# Scaled down LEF created by ScaleLEFMacro.pl
# Original LEF: 16nm/HD_1024X66M8B2.lef
# Don't forget to change metal layer LEF separately!

# Copyright (c) 1993 - 2021 ARM Limited. All Rights Reserved.
# Use of this Software is subject to the terms and conditions of the
# applicable license agreement with ARM Limited.

# PhyVGen V 8.22.0
# ARM Version r3p2
# Creation Date: Thu Sep  9 16:13:23 2021


# Memory Configuration:
# ~~~~~~~~~~~~~~~~~~~~~
#  -activity_factor 50 -atf off -back_biasing off -bits 66 -bmux on
# -bus_notation on -check_instname on -compiler_type sp -diodes on -drive 6
# -ema on -flexible_banking 2 -frequency 1000 -instname HD_1024X66M8B2
# -left_bus_delim "[" -lren_bankmask off -metal_stack 2Xa1Xd -mux 8 -mvt LP
# -name_case upper -pipeline off -power_gating off -power_type otc -prefix ""
# -pwr_gnd_rename vddpe:VDDPE,vddce:VDDCE,vsse:VSSE -rcols 2 -redundancy off
# -retention on -right_bus_delim "]" -rows_p_bl 256 -rrows 0 -scan on -ser none
# -site_def off -top_layer m5-m10 -vmin_assist on -words 1024 -write_mask on
# -write_thru off -corners tt_0p80v_0p80v_25c
# 

VERSION 5.7 ;
BUSBITCHARS "[]" ;
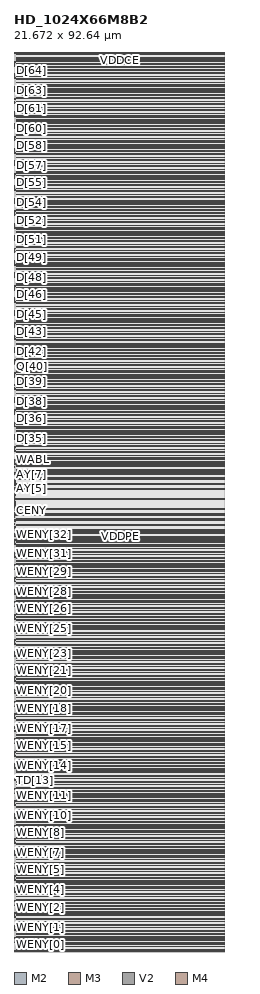
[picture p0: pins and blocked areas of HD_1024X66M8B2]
MACRO HD_1024X66M8B2
	FOREIGN HD_1024X66M8B2 0 0 ;
	SYMMETRY X Y ;
	SIZE 21.672 BY 92.64 ;
	CLASS BLOCK ;
	PIN AY[0]
		USE SIGNAL ;
		DIRECTION OUTPUT ;
		SHAPE ABUTMENT ;
		PORT
			 LAYER M2 ;
			RECT 0.0714 45.7914 0.1097 45.829 ;
			 LAYER M3 ;
			RECT 0.0714 45.7914 0.1097 45.8918 ;
			 LAYER V2 ;
			RECT 0.0831 45.8035 0.098 45.8161 ;
		END

		ANTENNADIFFAREA 0.00194719 ;
		ANTENNAPARTIALMETALAREA 0.00195671 ;
	END AY[0]

	PIN AY[1]
		USE SIGNAL ;
		DIRECTION OUTPUT ;
		SHAPE ABUTMENT ;
		PORT
			 LAYER M2 ;
			RECT 0.0714 46.0925 0.1097 46.1302 ;
			 LAYER M3 ;
			RECT 0.0714 46.0925 0.1097 46.1929 ;
			 LAYER V2 ;
			RECT 0.0831 46.1047 0.098 46.1173 ;
		END

		ANTENNADIFFAREA 0.00194719 ;
		ANTENNAPARTIALMETALAREA 0.00195671 ;
	END AY[1]

	PIN AY[2]
		USE SIGNAL ;
		DIRECTION OUTPUT ;
		SHAPE ABUTMENT ;
		PORT
			 LAYER M2 ;
			RECT 0.0714 46.2431 0.1097 46.2808 ;
			 LAYER M3 ;
			RECT 0.0714 46.2431 0.1097 46.3435 ;
			 LAYER V2 ;
			RECT 0.0831 46.2553 0.098 46.2678 ;
		END

		ANTENNADIFFAREA 0.00194719 ;
		ANTENNAPARTIALMETALAREA 0.00195671 ;
	END AY[2]

	PIN AY[3]
		USE SIGNAL ;
		DIRECTION OUTPUT ;
		SHAPE ABUTMENT ;
		PORT
			 LAYER M2 ;
			RECT 0.0098 46.9082 0.0481 46.9459 ;
			 LAYER M3 ;
			RECT 0.0098 46.8455 0.0481 46.9459 ;
			 LAYER V2 ;
			RECT 0.0215 46.9204 0.0364 46.9329 ;
		END

		ANTENNADIFFAREA 0.00194719 ;
		ANTENNAPARTIALMETALAREA 0.00195671 ;
	END AY[3]

	PIN AY[4]
		USE SIGNAL ;
		DIRECTION OUTPUT ;
		SHAPE ABUTMENT ;
		PORT
			 LAYER M2 ;
			RECT 0.0098 46.0047 0.0481 46.0424 ;
			 LAYER M3 ;
			RECT 0.0098 45.942 0.0481 46.0424 ;
			 LAYER V2 ;
			RECT 0.0215 46.0169 0.0364 46.0294 ;
		END

		ANTENNADIFFAREA 0.00194719 ;
		ANTENNAPARTIALMETALAREA 0.00195671 ;
	END AY[4]

	PIN AY[5]
		USE SIGNAL ;
		DIRECTION OUTPUT ;
		SHAPE ABUTMENT ;
		PORT
			 LAYER M2 ;
			RECT 0.0098 47.6612 0.0481 47.6988 ;
		END

		ANTENNADIFFAREA 0.00194719 ;
		ANTENNAPARTIALMETALAREA 0.00195671 ;
	END AY[5]

	PIN AY[6]
		USE SIGNAL ;
		DIRECTION OUTPUT ;
		SHAPE ABUTMENT ;
		PORT
			 LAYER M2 ;
			RECT 0.0714 47.4478 0.1097 47.4855 ;
			 LAYER M3 ;
			RECT 0.0714 47.4478 0.1097 47.5482 ;
			 LAYER V2 ;
			RECT 0.0831 47.46 0.098 47.4725 ;
		END

		ANTENNADIFFAREA 0.00194719 ;
		ANTENNAPARTIALMETALAREA 0.00195671 ;
	END AY[6]

	PIN AY[7]
		USE SIGNAL ;
		DIRECTION OUTPUT ;
		SHAPE ABUTMENT ;
		PORT
			 LAYER M2 ;
			RECT 0.0098 48.3514 0.0481 48.389 ;
		END

		ANTENNADIFFAREA 0.00194719 ;
		ANTENNAPARTIALMETALAREA 0.00195671 ;
	END AY[7]

	PIN AY[8]
		USE SIGNAL ;
		DIRECTION OUTPUT ;
		SHAPE ABUTMENT ;
		PORT
			 LAYER M2 ;
			RECT 0.0714 48.6525 0.1097 48.6902 ;
			 LAYER M3 ;
			RECT 0.0714 48.6525 0.1097 48.7529 ;
			 LAYER V2 ;
			RECT 0.0831 48.6647 0.098 48.6773 ;
		END

		ANTENNADIFFAREA 0.00194719 ;
		ANTENNAPARTIALMETALAREA 0.00195671 ;
	END AY[8]

	PIN AY[9]
		USE SIGNAL ;
		DIRECTION OUTPUT ;
		SHAPE ABUTMENT ;
		PORT
			 LAYER M3 ;
			RECT 0.0714 48.3514 0.1097 48.4518 ;
		END

		ANTENNADIFFAREA 0.00194719 ;
		ANTENNAPARTIALMETALAREA 0.00195671 ;
	END AY[9]

	PIN A[0]
		USE SIGNAL ;
		DIRECTION INPUT ;
		SHAPE ABUTMENT ;
		PORT
			 LAYER M2 ;
			RECT 0.0098 45.5529 0.0481 45.5906 ;
			 LAYER M3 ;
			RECT 0.0098 45.4902 0.0481 45.5906 ;
			 LAYER V2 ;
			RECT 0.0215 45.5651 0.0364 45.5776 ;
		END

		ANTENNAGATEAREA 0.00027817 ;
		ANTENNADIFFAREA 0.00194719 ;
		ANTENNAPARTIALMETALAREA 0.00195671 ;
	END A[0]

	PIN A[1]
		USE SIGNAL ;
		DIRECTION INPUT ;
		SHAPE ABUTMENT ;
		PORT
			 LAYER M2 ;
			RECT 0.0098 44.8 0.0481 44.8376 ;
			 LAYER M3 ;
			RECT 0.0098 44.7373 0.0481 44.8376 ;
			 LAYER V2 ;
			RECT 0.0215 44.8122 0.0364 44.8247 ;
		END

		ANTENNAGATEAREA 0.00027817 ;
		ANTENNADIFFAREA 0.00194719 ;
		ANTENNAPARTIALMETALAREA 0.00195671 ;
	END A[1]

	PIN A[2]
		USE SIGNAL ;
		DIRECTION INPUT ;
		SHAPE ABUTMENT ;
		PORT
			 LAYER M2 ;
			RECT 0.0714 48.2008 0.1097 48.2384 ;
			 LAYER M3 ;
			RECT 0.0714 48.2008 0.1097 48.3012 ;
			 LAYER V2 ;
			RECT 0.0831 48.2129 0.098 48.2255 ;
		END

		ANTENNAGATEAREA 0.00027817 ;
		ANTENNADIFFAREA 0.00194719 ;
		ANTENNAPARTIALMETALAREA 0.00195671 ;
	END A[2]

	PIN A[3]
		USE SIGNAL ;
		DIRECTION INPUT ;
		SHAPE ABUTMENT ;
		PORT
			 LAYER M2 ;
			RECT 0.0098 47.0588 0.0481 47.0965 ;
			 LAYER M3 ;
			RECT 0.0098 46.9961 0.0481 47.0965 ;
			 LAYER V2 ;
			RECT 0.0215 47.071 0.0364 47.0835 ;
		END

		ANTENNAGATEAREA 0.00027817 ;
		ANTENNADIFFAREA 0.00194719 ;
		ANTENNAPARTIALMETALAREA 0.00195671 ;
	END A[3]

	PIN A[4]
		USE SIGNAL ;
		DIRECTION INPUT ;
		SHAPE ABUTMENT ;
		PORT
			 LAYER M2 ;
			RECT 0.0098 46.4565 0.0481 46.4941 ;
			 LAYER M3 ;
			RECT 0.0098 46.3937 0.0481 46.4941 ;
			 LAYER V2 ;
			RECT 0.0215 46.4686 0.0364 46.4812 ;
		END

		ANTENNAGATEAREA 0.00027817 ;
		ANTENNADIFFAREA 0.00194719 ;
		ANTENNAPARTIALMETALAREA 0.00195671 ;
	END A[4]

	PIN A[5]
		USE SIGNAL ;
		DIRECTION INPUT ;
		SHAPE ABUTMENT ;
		PORT
			 LAYER M2 ;
			RECT 0.0098 47.2094 0.0481 47.2471 ;
			 LAYER M3 ;
			RECT 0.0098 47.1467 0.0481 47.2471 ;
			 LAYER V2 ;
			RECT 0.0215 47.2216 0.0364 47.2341 ;
		END

		ANTENNAGATEAREA 0.00027817 ;
		ANTENNADIFFAREA 0.00194719 ;
		ANTENNAPARTIALMETALAREA 0.00195671 ;
	END A[5]

	PIN A[6]
		USE SIGNAL ;
		DIRECTION INPUT ;
		SHAPE ABUTMENT ;
		PORT
			 LAYER M2 ;
			RECT 0.0098 47.8118 0.0481 47.8494 ;
		END

		ANTENNAGATEAREA 0.00027817 ;
		ANTENNADIFFAREA 0.00194719 ;
		ANTENNAPARTIALMETALAREA 0.00195671 ;
	END A[6]

	PIN A[7]
		USE SIGNAL ;
		DIRECTION INPUT ;
		SHAPE ABUTMENT ;
		PORT
			 LAYER M2 ;
			RECT 0.0098 48.1129 0.0481 48.1506 ;
			 LAYER M3 ;
			RECT 0.0098 48.0502 0.0481 48.1506 ;
			 LAYER V2 ;
			RECT 0.0215 48.1251 0.0364 48.1376 ;
		END

		ANTENNAGATEAREA 0.00027817 ;
		ANTENNADIFFAREA 0.00194719 ;
		ANTENNAPARTIALMETALAREA 0.00195671 ;
	END A[7]

	PIN A[8]
		USE SIGNAL ;
		DIRECTION INPUT ;
		SHAPE ABUTMENT ;
		PORT
			 LAYER M2 ;
			RECT 0.0098 48.2635 0.0481 48.3012 ;
			 LAYER M3 ;
			RECT 0.0098 48.2008 0.0481 48.3012 ;
			 LAYER V2 ;
			RECT 0.0215 48.2757 0.0364 48.2882 ;
		END

		ANTENNAGATEAREA 0.00027817 ;
		ANTENNADIFFAREA 0.00194719 ;
		ANTENNAPARTIALMETALAREA 0.00195671 ;
	END A[8]

	PIN A[9]
		USE SIGNAL ;
		DIRECTION INPUT ;
		SHAPE ABUTMENT ;
		PORT
			 LAYER M2 ;
			RECT 0.0098 48.7153 0.0481 48.7529 ;
			 LAYER M3 ;
			RECT 0.0098 48.6525 0.0481 48.7529 ;
			 LAYER V2 ;
			RECT 0.0215 48.7275 0.0364 48.74 ;
		END

		ANTENNAGATEAREA 0.00027817 ;
		ANTENNADIFFAREA 0.00194719 ;
		ANTENNAPARTIALMETALAREA 0.00195671 ;
	END A[9]

	PIN CEN
		USE SIGNAL ;
		DIRECTION INPUT ;
		SHAPE ABUTMENT ;
		PORT
			 LAYER M2 ;
			RECT 0.0714 49.2549 0.1097 49.2925 ;
			 LAYER M3 ;
			RECT 0.0714 49.2549 0.1097 49.3553 ;
			 LAYER V2 ;
			RECT 0.0831 49.2671 0.098 49.2796 ;
		END

		ANTENNAGATEAREA 0.00027817 ;
		ANTENNADIFFAREA 0.00194719 ;
		ANTENNAPARTIALMETALAREA 0.00195671 ;
	END CEN

	PIN CENY
		USE SIGNAL ;
		DIRECTION OUTPUT ;
		SHAPE ABUTMENT ;
		PORT
			 LAYER M2 ;
			RECT 0.0098 45.4024 0.0481 45.44 ;
		END

		ANTENNADIFFAREA 0.00194719 ;
		ANTENNAPARTIALMETALAREA 0.00195671 ;
	END CENY

	PIN CLK
		USE SIGNAL ;
		DIRECTION INPUT ;
		SHAPE ABUTMENT ;
		PORT
			 LAYER M2 ;
			RECT 0.0098 45.8541 0.0481 45.8918 ;
			 LAYER M3 ;
			RECT 0.0098 45.7914 0.0481 45.8918 ;
			 LAYER V2 ;
			RECT 0.0215 45.8663 0.0364 45.8788 ;
		END

		ANTENNAGATEAREA 0.00027817 ;
		ANTENNADIFFAREA 0.00194719 ;
		ANTENNAPARTIALMETALAREA 0.00195671 ;
	END CLK

	PIN DFTRAMBYP
		USE SIGNAL ;
		DIRECTION INPUT ;
		SHAPE ABUTMENT ;
		PORT
			 LAYER M2 ;
			RECT 0.0714 44.2855 0.1097 44.3231 ;
			 LAYER M3 ;
			RECT 0.0714 44.2855 0.1097 44.3859 ;
			 LAYER V2 ;
			RECT 0.0831 44.2976 0.098 44.3102 ;
		END

		ANTENNAGATEAREA 0.00027817 ;
		ANTENNADIFFAREA 0.00194719 ;
		ANTENNAPARTIALMETALAREA 0.00195671 ;
	END DFTRAMBYP

	PIN D[0]
		USE SIGNAL ;
		DIRECTION INPUT ;
		SHAPE ABUTMENT ;
		PORT
			 LAYER M2 ;
			RECT 0.0098 1.3678 0.0481 1.4055 ;
			 LAYER M3 ;
			RECT 0.0098 1.3678 0.0481 1.4682 ;
			 LAYER V2 ;
			RECT 0.0215 1.3808 0.0364 1.3933 ;
		END

		ANTENNAGATEAREA 0.00027817 ;
		ANTENNADIFFAREA 0.00194719 ;
		ANTENNAPARTIALMETALAREA 0.00195671 ;
	END D[0]

	PIN D[10]
		USE SIGNAL ;
		DIRECTION INPUT ;
		SHAPE ABUTMENT ;
		PORT
			 LAYER M2 ;
			RECT 0.0098 14.1678 0.0481 14.2055 ;
			 LAYER M3 ;
			RECT 0.0098 14.1678 0.0481 14.2682 ;
			 LAYER V2 ;
			RECT 0.0215 14.1808 0.0364 14.1933 ;
		END

		ANTENNAGATEAREA 0.00027817 ;
		ANTENNADIFFAREA 0.00194719 ;
		ANTENNAPARTIALMETALAREA 0.00195671 ;
	END D[10]

	PIN D[11]
		USE SIGNAL ;
		DIRECTION INPUT ;
		SHAPE ABUTMENT ;
		PORT
			 LAYER M2 ;
			RECT 0.0098 15.4478 0.0481 15.4855 ;
			 LAYER M3 ;
			RECT 0.0098 15.4478 0.0481 15.5482 ;
			 LAYER V2 ;
			RECT 0.0215 15.4608 0.0364 15.4733 ;
		END

		ANTENNAGATEAREA 0.00027817 ;
		ANTENNADIFFAREA 0.00194719 ;
		ANTENNAPARTIALMETALAREA 0.00195671 ;
	END D[11]

	PIN D[12]
		USE SIGNAL ;
		DIRECTION INPUT ;
		SHAPE ABUTMENT ;
		PORT
			 LAYER M2 ;
			RECT 0.0098 16.7278 0.0481 16.7655 ;
			 LAYER M3 ;
			RECT 0.0098 16.7278 0.0481 16.8282 ;
			 LAYER V2 ;
			RECT 0.0215 16.7408 0.0364 16.7533 ;
		END

		ANTENNAGATEAREA 0.00027817 ;
		ANTENNADIFFAREA 0.00194719 ;
		ANTENNAPARTIALMETALAREA 0.00195671 ;
	END D[12]

	PIN D[13]
		USE SIGNAL ;
		DIRECTION INPUT ;
		SHAPE ABUTMENT ;
		PORT
			 LAYER M2 ;
			RECT 0.0098 18.0078 0.0481 18.0455 ;
			 LAYER M3 ;
			RECT 0.0098 18.0078 0.0481 18.1082 ;
			 LAYER V2 ;
			RECT 0.0215 18.0208 0.0364 18.0333 ;
		END

		ANTENNAGATEAREA 0.00027817 ;
		ANTENNADIFFAREA 0.00194719 ;
		ANTENNAPARTIALMETALAREA 0.00195671 ;
	END D[13]

	PIN D[14]
		USE SIGNAL ;
		DIRECTION INPUT ;
		SHAPE ABUTMENT ;
		PORT
			 LAYER M2 ;
			RECT 0.0098 19.2878 0.0481 19.3255 ;
			 LAYER M3 ;
			RECT 0.0098 19.2878 0.0481 19.3882 ;
			 LAYER V2 ;
			RECT 0.0215 19.3008 0.0364 19.3133 ;
		END

		ANTENNAGATEAREA 0.00027817 ;
		ANTENNADIFFAREA 0.00194719 ;
		ANTENNAPARTIALMETALAREA 0.00195671 ;
	END D[14]

	PIN D[15]
		USE SIGNAL ;
		DIRECTION INPUT ;
		SHAPE ABUTMENT ;
		PORT
			 LAYER M2 ;
			RECT 0.0098 20.5678 0.0481 20.6055 ;
			 LAYER M3 ;
			RECT 0.0098 20.5678 0.0481 20.6682 ;
			 LAYER V2 ;
			RECT 0.0215 20.5808 0.0364 20.5933 ;
		END

		ANTENNAGATEAREA 0.00027817 ;
		ANTENNADIFFAREA 0.00194719 ;
		ANTENNAPARTIALMETALAREA 0.00195671 ;
	END D[15]

	PIN D[16]
		USE SIGNAL ;
		DIRECTION INPUT ;
		SHAPE ABUTMENT ;
		PORT
			 LAYER M2 ;
			RECT 0.0098 21.8478 0.0481 21.8855 ;
			 LAYER M3 ;
			RECT 0.0098 21.8478 0.0481 21.9482 ;
			 LAYER V2 ;
			RECT 0.0215 21.8608 0.0364 21.8733 ;
		END

		ANTENNAGATEAREA 0.00027817 ;
		ANTENNADIFFAREA 0.00194719 ;
		ANTENNAPARTIALMETALAREA 0.00195671 ;
	END D[16]

	PIN D[17]
		USE SIGNAL ;
		DIRECTION INPUT ;
		SHAPE ABUTMENT ;
		PORT
			 LAYER M2 ;
			RECT 0.0098 23.1278 0.0481 23.1655 ;
			 LAYER M3 ;
			RECT 0.0098 23.1278 0.0481 23.2282 ;
			 LAYER V2 ;
			RECT 0.0215 23.1408 0.0364 23.1533 ;
		END

		ANTENNAGATEAREA 0.00027817 ;
		ANTENNADIFFAREA 0.00194719 ;
		ANTENNAPARTIALMETALAREA 0.00195671 ;
	END D[17]

	PIN D[18]
		USE SIGNAL ;
		DIRECTION INPUT ;
		SHAPE ABUTMENT ;
		PORT
			 LAYER M2 ;
			RECT 0.0098 24.4078 0.0481 24.4455 ;
			 LAYER M3 ;
			RECT 0.0098 24.4078 0.0481 24.5082 ;
			 LAYER V2 ;
			RECT 0.0215 24.4208 0.0364 24.4333 ;
		END

		ANTENNAGATEAREA 0.00027817 ;
		ANTENNADIFFAREA 0.00194719 ;
		ANTENNAPARTIALMETALAREA 0.00195671 ;
	END D[18]

	PIN D[19]
		USE SIGNAL ;
		DIRECTION INPUT ;
		SHAPE ABUTMENT ;
		PORT
			 LAYER M2 ;
			RECT 0.0098 25.6878 0.0481 25.7255 ;
			 LAYER M3 ;
			RECT 0.0098 25.6878 0.0481 25.7882 ;
			 LAYER V2 ;
			RECT 0.0215 25.7008 0.0364 25.7133 ;
		END

		ANTENNAGATEAREA 0.00027817 ;
		ANTENNADIFFAREA 0.00194719 ;
		ANTENNAPARTIALMETALAREA 0.00195671 ;
	END D[19]

	PIN D[1]
		USE SIGNAL ;
		DIRECTION INPUT ;
		SHAPE ABUTMENT ;
		PORT
			 LAYER M2 ;
			RECT 0.0098 2.6478 0.0481 2.6855 ;
			 LAYER M3 ;
			RECT 0.0098 2.6478 0.0481 2.7482 ;
			 LAYER V2 ;
			RECT 0.0215 2.6608 0.0364 2.6733 ;
		END

		ANTENNAGATEAREA 0.00027817 ;
		ANTENNADIFFAREA 0.00194719 ;
		ANTENNAPARTIALMETALAREA 0.00195671 ;
	END D[1]

	PIN D[20]
		USE SIGNAL ;
		DIRECTION INPUT ;
		SHAPE ABUTMENT ;
		PORT
			 LAYER M2 ;
			RECT 0.0098 26.9678 0.0481 27.0055 ;
			 LAYER M3 ;
			RECT 0.0098 26.9678 0.0481 27.0682 ;
			 LAYER V2 ;
			RECT 0.0215 26.9808 0.0364 26.9933 ;
		END

		ANTENNAGATEAREA 0.00027817 ;
		ANTENNADIFFAREA 0.00194719 ;
		ANTENNAPARTIALMETALAREA 0.00195671 ;
	END D[20]

	PIN D[21]
		USE SIGNAL ;
		DIRECTION INPUT ;
		SHAPE ABUTMENT ;
		PORT
			 LAYER M2 ;
			RECT 0.0098 28.2478 0.0481 28.2855 ;
			 LAYER M3 ;
			RECT 0.0098 28.2478 0.0481 28.3482 ;
			 LAYER V2 ;
			RECT 0.0215 28.2608 0.0364 28.2733 ;
		END

		ANTENNAGATEAREA 0.00027817 ;
		ANTENNADIFFAREA 0.00194719 ;
		ANTENNAPARTIALMETALAREA 0.00195671 ;
	END D[21]

	PIN D[22]
		USE SIGNAL ;
		DIRECTION INPUT ;
		SHAPE ABUTMENT ;
		PORT
			 LAYER M2 ;
			RECT 0.0098 29.5278 0.0481 29.5655 ;
			 LAYER M3 ;
			RECT 0.0098 29.5278 0.0481 29.6282 ;
			 LAYER V2 ;
			RECT 0.0215 29.5408 0.0364 29.5533 ;
		END

		ANTENNAGATEAREA 0.00027817 ;
		ANTENNADIFFAREA 0.00194719 ;
		ANTENNAPARTIALMETALAREA 0.00195671 ;
	END D[22]

	PIN D[23]
		USE SIGNAL ;
		DIRECTION INPUT ;
		SHAPE ABUTMENT ;
		PORT
			 LAYER M2 ;
			RECT 0.0098 30.8078 0.0481 30.8455 ;
			 LAYER M3 ;
			RECT 0.0098 30.8078 0.0481 30.9082 ;
			 LAYER V2 ;
			RECT 0.0215 30.8208 0.0364 30.8333 ;
		END

		ANTENNAGATEAREA 0.00027817 ;
		ANTENNADIFFAREA 0.00194719 ;
		ANTENNAPARTIALMETALAREA 0.00195671 ;
	END D[23]

	PIN D[24]
		USE SIGNAL ;
		DIRECTION INPUT ;
		SHAPE ABUTMENT ;
		PORT
			 LAYER M2 ;
			RECT 0.0098 32.0878 0.0481 32.1255 ;
			 LAYER M3 ;
			RECT 0.0098 32.0878 0.0481 32.1882 ;
			 LAYER V2 ;
			RECT 0.0215 32.1008 0.0364 32.1133 ;
		END

		ANTENNAGATEAREA 0.00027817 ;
		ANTENNADIFFAREA 0.00194719 ;
		ANTENNAPARTIALMETALAREA 0.00195671 ;
	END D[24]

	PIN D[25]
		USE SIGNAL ;
		DIRECTION INPUT ;
		SHAPE ABUTMENT ;
		PORT
			 LAYER M2 ;
			RECT 0.0098 33.3678 0.0481 33.4055 ;
			 LAYER M3 ;
			RECT 0.0098 33.3678 0.0481 33.4682 ;
			 LAYER V2 ;
			RECT 0.0215 33.3808 0.0364 33.3933 ;
		END

		ANTENNAGATEAREA 0.00027817 ;
		ANTENNADIFFAREA 0.00194719 ;
		ANTENNAPARTIALMETALAREA 0.00195671 ;
	END D[25]

	PIN D[26]
		USE SIGNAL ;
		DIRECTION INPUT ;
		SHAPE ABUTMENT ;
		PORT
			 LAYER M2 ;
			RECT 0.0098 34.6478 0.0481 34.6855 ;
			 LAYER M3 ;
			RECT 0.0098 34.6478 0.0481 34.7482 ;
			 LAYER V2 ;
			RECT 0.0215 34.6608 0.0364 34.6733 ;
		END

		ANTENNAGATEAREA 0.00027817 ;
		ANTENNADIFFAREA 0.00194719 ;
		ANTENNAPARTIALMETALAREA 0.00195671 ;
	END D[26]

	PIN D[27]
		USE SIGNAL ;
		DIRECTION INPUT ;
		SHAPE ABUTMENT ;
		PORT
			 LAYER M2 ;
			RECT 0.0098 35.9278 0.0481 35.9655 ;
			 LAYER M3 ;
			RECT 0.0098 35.9278 0.0481 36.0282 ;
			 LAYER V2 ;
			RECT 0.0215 35.9408 0.0364 35.9533 ;
		END

		ANTENNAGATEAREA 0.00027817 ;
		ANTENNADIFFAREA 0.00194719 ;
		ANTENNAPARTIALMETALAREA 0.00195671 ;
	END D[27]

	PIN D[28]
		USE SIGNAL ;
		DIRECTION INPUT ;
		SHAPE ABUTMENT ;
		PORT
			 LAYER M2 ;
			RECT 0.0098 37.2078 0.0481 37.2455 ;
			 LAYER M3 ;
			RECT 0.0098 37.2078 0.0481 37.3082 ;
			 LAYER V2 ;
			RECT 0.0215 37.2208 0.0364 37.2333 ;
		END

		ANTENNAGATEAREA 0.00027817 ;
		ANTENNADIFFAREA 0.00194719 ;
		ANTENNAPARTIALMETALAREA 0.00195671 ;
	END D[28]

	PIN D[29]
		USE SIGNAL ;
		DIRECTION INPUT ;
		SHAPE ABUTMENT ;
		PORT
			 LAYER M2 ;
			RECT 0.0098 38.4878 0.0481 38.5255 ;
			 LAYER M3 ;
			RECT 0.0098 38.4878 0.0481 38.5882 ;
			 LAYER V2 ;
			RECT 0.0215 38.5008 0.0364 38.5133 ;
		END

		ANTENNAGATEAREA 0.00027817 ;
		ANTENNADIFFAREA 0.00194719 ;
		ANTENNAPARTIALMETALAREA 0.00195671 ;
	END D[29]

	PIN D[2]
		USE SIGNAL ;
		DIRECTION INPUT ;
		SHAPE ABUTMENT ;
		PORT
			 LAYER M2 ;
			RECT 0.0098 3.9278 0.0481 3.9655 ;
			 LAYER M3 ;
			RECT 0.0098 3.9278 0.0481 4.0282 ;
			 LAYER V2 ;
			RECT 0.0215 3.9408 0.0364 3.9533 ;
		END

		ANTENNAGATEAREA 0.00027817 ;
		ANTENNADIFFAREA 0.00194719 ;
		ANTENNAPARTIALMETALAREA 0.00195671 ;
	END D[2]

	PIN D[30]
		USE SIGNAL ;
		DIRECTION INPUT ;
		SHAPE ABUTMENT ;
		PORT
			 LAYER M2 ;
			RECT 0.0098 39.7678 0.0481 39.8055 ;
			 LAYER M3 ;
			RECT 0.0098 39.7678 0.0481 39.8682 ;
			 LAYER V2 ;
			RECT 0.0215 39.7808 0.0364 39.7933 ;
		END

		ANTENNAGATEAREA 0.00027817 ;
		ANTENNADIFFAREA 0.00194719 ;
		ANTENNAPARTIALMETALAREA 0.00195671 ;
	END D[30]

	PIN D[31]
		USE SIGNAL ;
		DIRECTION INPUT ;
		SHAPE ABUTMENT ;
		PORT
			 LAYER M2 ;
			RECT 0.0098 41.0478 0.0481 41.0855 ;
			 LAYER M3 ;
			RECT 0.0098 41.0478 0.0481 41.1482 ;
			 LAYER V2 ;
			RECT 0.0215 41.0608 0.0364 41.0733 ;
		END

		ANTENNAGATEAREA 0.00027817 ;
		ANTENNADIFFAREA 0.00194719 ;
		ANTENNAPARTIALMETALAREA 0.00195671 ;
	END D[31]

	PIN D[32]
		USE SIGNAL ;
		DIRECTION INPUT ;
		SHAPE ABUTMENT ;
		PORT
			 LAYER M2 ;
			RECT 0.0098 42.3278 0.0481 42.3655 ;
			 LAYER M3 ;
			RECT 0.0098 42.3278 0.0481 42.4282 ;
			 LAYER V2 ;
			RECT 0.0215 42.3408 0.0364 42.3533 ;
		END

		ANTENNAGATEAREA 0.00027817 ;
		ANTENNADIFFAREA 0.00194719 ;
		ANTENNAPARTIALMETALAREA 0.00195671 ;
	END D[32]

	PIN D[33]
		USE SIGNAL ;
		DIRECTION INPUT ;
		SHAPE ABUTMENT ;
		PORT
			 LAYER M2 ;
			RECT 0.0098 50.2651 0.0481 50.3027 ;
			 LAYER M3 ;
			RECT 0.0098 50.2024 0.0481 50.3027 ;
			 LAYER V2 ;
			RECT 0.0215 50.2773 0.0364 50.2898 ;
		END

		ANTENNAGATEAREA 0.00027817 ;
		ANTENNADIFFAREA 0.00194719 ;
		ANTENNAPARTIALMETALAREA 0.00195671 ;
	END D[33]

	PIN D[34]
		USE SIGNAL ;
		DIRECTION INPUT ;
		SHAPE ABUTMENT ;
		PORT
			 LAYER M2 ;
			RECT 0.0098 51.5451 0.0481 51.5827 ;
			 LAYER M3 ;
			RECT 0.0098 51.4824 0.0481 51.5827 ;
			 LAYER V2 ;
			RECT 0.0215 51.5573 0.0364 51.5698 ;
		END

		ANTENNAGATEAREA 0.00027817 ;
		ANTENNADIFFAREA 0.00194719 ;
		ANTENNAPARTIALMETALAREA 0.00195671 ;
	END D[34]

	PIN D[35]
		USE SIGNAL ;
		DIRECTION INPUT ;
		SHAPE ABUTMENT ;
		PORT
			 LAYER M2 ;
			RECT 0.0098 52.8251 0.0481 52.8627 ;
			 LAYER M3 ;
			RECT 0.0098 52.7624 0.0481 52.8627 ;
			 LAYER V2 ;
			RECT 0.0215 52.8373 0.0364 52.8498 ;
		END

		ANTENNAGATEAREA 0.00027817 ;
		ANTENNADIFFAREA 0.00194719 ;
		ANTENNAPARTIALMETALAREA 0.00195671 ;
	END D[35]

	PIN D[36]
		USE SIGNAL ;
		DIRECTION INPUT ;
		SHAPE ABUTMENT ;
		PORT
			 LAYER M2 ;
			RECT 0.0098 54.1051 0.0481 54.1427 ;
			 LAYER M3 ;
			RECT 0.0098 54.0424 0.0481 54.1427 ;
			 LAYER V2 ;
			RECT 0.0215 54.1173 0.0364 54.1298 ;
		END

		ANTENNAGATEAREA 0.00027817 ;
		ANTENNADIFFAREA 0.00194719 ;
		ANTENNAPARTIALMETALAREA 0.00195671 ;
	END D[36]

	PIN D[37]
		USE SIGNAL ;
		DIRECTION INPUT ;
		SHAPE ABUTMENT ;
		PORT
			 LAYER M2 ;
			RECT 0.0098 55.3851 0.0481 55.4227 ;
			 LAYER M3 ;
			RECT 0.0098 55.3224 0.0481 55.4227 ;
			 LAYER V2 ;
			RECT 0.0215 55.3973 0.0364 55.4098 ;
		END

		ANTENNAGATEAREA 0.00027817 ;
		ANTENNADIFFAREA 0.00194719 ;
		ANTENNAPARTIALMETALAREA 0.00195671 ;
	END D[37]

	PIN D[38]
		USE SIGNAL ;
		DIRECTION INPUT ;
		SHAPE ABUTMENT ;
		PORT
			 LAYER M2 ;
			RECT 0.0098 56.6651 0.0481 56.7027 ;
			 LAYER M3 ;
			RECT 0.0098 56.6024 0.0481 56.7027 ;
			 LAYER V2 ;
			RECT 0.0215 56.6773 0.0364 56.6898 ;
		END

		ANTENNAGATEAREA 0.00027817 ;
		ANTENNADIFFAREA 0.00194719 ;
		ANTENNAPARTIALMETALAREA 0.00195671 ;
	END D[38]

	PIN D[39]
		USE SIGNAL ;
		DIRECTION INPUT ;
		SHAPE ABUTMENT ;
		PORT
			 LAYER M2 ;
			RECT 0.0098 57.9451 0.0481 57.9827 ;
			 LAYER M3 ;
			RECT 0.0098 57.8824 0.0481 57.9827 ;
			 LAYER V2 ;
			RECT 0.0215 57.9573 0.0364 57.9698 ;
		END

		ANTENNAGATEAREA 0.00027817 ;
		ANTENNADIFFAREA 0.00194719 ;
		ANTENNAPARTIALMETALAREA 0.00195671 ;
	END D[39]

	PIN D[3]
		USE SIGNAL ;
		DIRECTION INPUT ;
		SHAPE ABUTMENT ;
		PORT
			 LAYER M2 ;
			RECT 0.0098 5.2078 0.0481 5.2455 ;
			 LAYER M3 ;
			RECT 0.0098 5.2078 0.0481 5.3082 ;
			 LAYER V2 ;
			RECT 0.0215 5.2208 0.0364 5.2333 ;
		END

		ANTENNAGATEAREA 0.00027817 ;
		ANTENNADIFFAREA 0.00194719 ;
		ANTENNAPARTIALMETALAREA 0.00195671 ;
	END D[3]

	PIN D[40]
		USE SIGNAL ;
		DIRECTION INPUT ;
		SHAPE ABUTMENT ;
		PORT
			 LAYER M2 ;
			RECT 0.0098 59.2251 0.0481 59.2627 ;
			 LAYER M3 ;
			RECT 0.0098 59.1624 0.0481 59.2627 ;
			 LAYER V2 ;
			RECT 0.0215 59.2373 0.0364 59.2498 ;
		END

		ANTENNAGATEAREA 0.00027817 ;
		ANTENNADIFFAREA 0.00194719 ;
		ANTENNAPARTIALMETALAREA 0.00195671 ;
	END D[40]

	PIN D[41]
		USE SIGNAL ;
		DIRECTION INPUT ;
		SHAPE ABUTMENT ;
		PORT
			 LAYER M2 ;
			RECT 0.0098 60.5051 0.0481 60.5427 ;
			 LAYER M3 ;
			RECT 0.0098 60.4424 0.0481 60.5427 ;
			 LAYER V2 ;
			RECT 0.0215 60.5173 0.0364 60.5298 ;
		END

		ANTENNAGATEAREA 0.00027817 ;
		ANTENNADIFFAREA 0.00194719 ;
		ANTENNAPARTIALMETALAREA 0.00195671 ;
	END D[41]

	PIN D[42]
		USE SIGNAL ;
		DIRECTION INPUT ;
		SHAPE ABUTMENT ;
		PORT
			 LAYER M2 ;
			RECT 0.0098 61.7851 0.0481 61.8227 ;
			 LAYER M3 ;
			RECT 0.0098 61.7224 0.0481 61.8227 ;
			 LAYER V2 ;
			RECT 0.0215 61.7973 0.0364 61.8098 ;
		END

		ANTENNAGATEAREA 0.00027817 ;
		ANTENNADIFFAREA 0.00194719 ;
		ANTENNAPARTIALMETALAREA 0.00195671 ;
	END D[42]

	PIN D[43]
		USE SIGNAL ;
		DIRECTION INPUT ;
		SHAPE ABUTMENT ;
		PORT
			 LAYER M2 ;
			RECT 0.0098 63.0651 0.0481 63.1027 ;
			 LAYER M3 ;
			RECT 0.0098 63.0024 0.0481 63.1027 ;
			 LAYER V2 ;
			RECT 0.0215 63.0773 0.0364 63.0898 ;
		END

		ANTENNAGATEAREA 0.00027817 ;
		ANTENNADIFFAREA 0.00194719 ;
		ANTENNAPARTIALMETALAREA 0.00195671 ;
	END D[43]

	PIN D[44]
		USE SIGNAL ;
		DIRECTION INPUT ;
		SHAPE ABUTMENT ;
		PORT
			 LAYER M2 ;
			RECT 0.0098 64.3451 0.0481 64.3827 ;
			 LAYER M3 ;
			RECT 0.0098 64.2824 0.0481 64.3827 ;
			 LAYER V2 ;
			RECT 0.0215 64.3573 0.0364 64.3698 ;
		END

		ANTENNAGATEAREA 0.00027817 ;
		ANTENNADIFFAREA 0.00194719 ;
		ANTENNAPARTIALMETALAREA 0.00195671 ;
	END D[44]

	PIN D[45]
		USE SIGNAL ;
		DIRECTION INPUT ;
		SHAPE ABUTMENT ;
		PORT
			 LAYER M2 ;
			RECT 0.0098 65.6251 0.0481 65.6627 ;
			 LAYER M3 ;
			RECT 0.0098 65.5624 0.0481 65.6627 ;
			 LAYER V2 ;
			RECT 0.0215 65.6373 0.0364 65.6498 ;
		END

		ANTENNAGATEAREA 0.00027817 ;
		ANTENNADIFFAREA 0.00194719 ;
		ANTENNAPARTIALMETALAREA 0.00195671 ;
	END D[45]

	PIN D[46]
		USE SIGNAL ;
		DIRECTION INPUT ;
		SHAPE ABUTMENT ;
		PORT
			 LAYER M2 ;
			RECT 0.0098 66.9051 0.0481 66.9427 ;
			 LAYER M3 ;
			RECT 0.0098 66.8424 0.0481 66.9427 ;
			 LAYER V2 ;
			RECT 0.0215 66.9173 0.0364 66.9298 ;
		END

		ANTENNAGATEAREA 0.00027817 ;
		ANTENNADIFFAREA 0.00194719 ;
		ANTENNAPARTIALMETALAREA 0.00195671 ;
	END D[46]

	PIN D[47]
		USE SIGNAL ;
		DIRECTION INPUT ;
		SHAPE ABUTMENT ;
		PORT
			 LAYER M2 ;
			RECT 0.0098 68.1851 0.0481 68.2227 ;
			 LAYER M3 ;
			RECT 0.0098 68.1224 0.0481 68.2227 ;
			 LAYER V2 ;
			RECT 0.0215 68.1973 0.0364 68.2098 ;
		END

		ANTENNAGATEAREA 0.00027817 ;
		ANTENNADIFFAREA 0.00194719 ;
		ANTENNAPARTIALMETALAREA 0.00195671 ;
	END D[47]

	PIN D[48]
		USE SIGNAL ;
		DIRECTION INPUT ;
		SHAPE ABUTMENT ;
		PORT
			 LAYER M2 ;
			RECT 0.0098 69.4651 0.0481 69.5027 ;
			 LAYER M3 ;
			RECT 0.0098 69.4024 0.0481 69.5027 ;
			 LAYER V2 ;
			RECT 0.0215 69.4773 0.0364 69.4898 ;
		END

		ANTENNAGATEAREA 0.00027817 ;
		ANTENNADIFFAREA 0.00194719 ;
		ANTENNAPARTIALMETALAREA 0.00195671 ;
	END D[48]

	PIN D[49]
		USE SIGNAL ;
		DIRECTION INPUT ;
		SHAPE ABUTMENT ;
		PORT
			 LAYER M2 ;
			RECT 0.0098 70.7451 0.0481 70.7827 ;
			 LAYER M3 ;
			RECT 0.0098 70.6824 0.0481 70.7827 ;
			 LAYER V2 ;
			RECT 0.0215 70.7573 0.0364 70.7698 ;
		END

		ANTENNAGATEAREA 0.00027817 ;
		ANTENNADIFFAREA 0.00194719 ;
		ANTENNAPARTIALMETALAREA 0.00195671 ;
	END D[49]

	PIN D[4]
		USE SIGNAL ;
		DIRECTION INPUT ;
		SHAPE ABUTMENT ;
		PORT
			 LAYER M2 ;
			RECT 0.0098 6.4878 0.0481 6.5255 ;
			 LAYER M3 ;
			RECT 0.0098 6.4878 0.0481 6.5882 ;
			 LAYER V2 ;
			RECT 0.0215 6.5008 0.0364 6.5133 ;
		END

		ANTENNAGATEAREA 0.00027817 ;
		ANTENNADIFFAREA 0.00194719 ;
		ANTENNAPARTIALMETALAREA 0.00195671 ;
	END D[4]

	PIN D[50]
		USE SIGNAL ;
		DIRECTION INPUT ;
		SHAPE ABUTMENT ;
		PORT
			 LAYER M2 ;
			RECT 0.0098 72.0251 0.0481 72.0627 ;
			 LAYER M3 ;
			RECT 0.0098 71.9624 0.0481 72.0627 ;
			 LAYER V2 ;
			RECT 0.0215 72.0373 0.0364 72.0498 ;
		END

		ANTENNAGATEAREA 0.00027817 ;
		ANTENNADIFFAREA 0.00194719 ;
		ANTENNAPARTIALMETALAREA 0.00195671 ;
	END D[50]

	PIN D[51]
		USE SIGNAL ;
		DIRECTION INPUT ;
		SHAPE ABUTMENT ;
		PORT
			 LAYER M2 ;
			RECT 0.0098 73.3051 0.0481 73.3427 ;
			 LAYER M3 ;
			RECT 0.0098 73.2424 0.0481 73.3427 ;
			 LAYER V2 ;
			RECT 0.0215 73.3173 0.0364 73.3298 ;
		END

		ANTENNAGATEAREA 0.00027817 ;
		ANTENNADIFFAREA 0.00194719 ;
		ANTENNAPARTIALMETALAREA 0.00195671 ;
	END D[51]

	PIN D[52]
		USE SIGNAL ;
		DIRECTION INPUT ;
		SHAPE ABUTMENT ;
		PORT
			 LAYER M2 ;
			RECT 0.0098 74.5851 0.0481 74.6227 ;
			 LAYER M3 ;
			RECT 0.0098 74.5224 0.0481 74.6227 ;
			 LAYER V2 ;
			RECT 0.0215 74.5973 0.0364 74.6098 ;
		END

		ANTENNAGATEAREA 0.00027817 ;
		ANTENNADIFFAREA 0.00194719 ;
		ANTENNAPARTIALMETALAREA 0.00195671 ;
	END D[52]

	PIN D[53]
		USE SIGNAL ;
		DIRECTION INPUT ;
		SHAPE ABUTMENT ;
		PORT
			 LAYER M2 ;
			RECT 0.0098 75.8651 0.0481 75.9027 ;
			 LAYER M3 ;
			RECT 0.0098 75.8024 0.0481 75.9027 ;
			 LAYER V2 ;
			RECT 0.0215 75.8773 0.0364 75.8898 ;
		END

		ANTENNAGATEAREA 0.00027817 ;
		ANTENNADIFFAREA 0.00194719 ;
		ANTENNAPARTIALMETALAREA 0.00195671 ;
	END D[53]

	PIN D[54]
		USE SIGNAL ;
		DIRECTION INPUT ;
		SHAPE ABUTMENT ;
		PORT
			 LAYER M2 ;
			RECT 0.0098 77.1451 0.0481 77.1827 ;
			 LAYER M3 ;
			RECT 0.0098 77.0824 0.0481 77.1827 ;
			 LAYER V2 ;
			RECT 0.0215 77.1573 0.0364 77.1698 ;
		END

		ANTENNAGATEAREA 0.00027817 ;
		ANTENNADIFFAREA 0.00194719 ;
		ANTENNAPARTIALMETALAREA 0.00195671 ;
	END D[54]

	PIN D[55]
		USE SIGNAL ;
		DIRECTION INPUT ;
		SHAPE ABUTMENT ;
		PORT
			 LAYER M2 ;
			RECT 0.0098 78.4251 0.0481 78.4627 ;
			 LAYER M3 ;
			RECT 0.0098 78.3624 0.0481 78.4627 ;
			 LAYER V2 ;
			RECT 0.0215 78.4373 0.0364 78.4498 ;
		END

		ANTENNAGATEAREA 0.00027817 ;
		ANTENNADIFFAREA 0.00194719 ;
		ANTENNAPARTIALMETALAREA 0.00195671 ;
	END D[55]

	PIN D[56]
		USE SIGNAL ;
		DIRECTION INPUT ;
		SHAPE ABUTMENT ;
		PORT
			 LAYER M2 ;
			RECT 0.0098 79.7051 0.0481 79.7427 ;
			 LAYER M3 ;
			RECT 0.0098 79.6424 0.0481 79.7427 ;
			 LAYER V2 ;
			RECT 0.0215 79.7173 0.0364 79.7298 ;
		END

		ANTENNAGATEAREA 0.00027817 ;
		ANTENNADIFFAREA 0.00194719 ;
		ANTENNAPARTIALMETALAREA 0.00195671 ;
	END D[56]

	PIN D[57]
		USE SIGNAL ;
		DIRECTION INPUT ;
		SHAPE ABUTMENT ;
		PORT
			 LAYER M2 ;
			RECT 0.0098 80.9851 0.0481 81.0227 ;
			 LAYER M3 ;
			RECT 0.0098 80.9224 0.0481 81.0227 ;
			 LAYER V2 ;
			RECT 0.0215 80.9973 0.0364 81.0098 ;
		END

		ANTENNAGATEAREA 0.00027817 ;
		ANTENNADIFFAREA 0.00194719 ;
		ANTENNAPARTIALMETALAREA 0.00195671 ;
	END D[57]

	PIN D[58]
		USE SIGNAL ;
		DIRECTION INPUT ;
		SHAPE ABUTMENT ;
		PORT
			 LAYER M2 ;
			RECT 0.0098 82.2651 0.0481 82.3027 ;
			 LAYER M3 ;
			RECT 0.0098 82.2024 0.0481 82.3027 ;
			 LAYER V2 ;
			RECT 0.0215 82.2773 0.0364 82.2898 ;
		END

		ANTENNAGATEAREA 0.00027817 ;
		ANTENNADIFFAREA 0.00194719 ;
		ANTENNAPARTIALMETALAREA 0.00195671 ;
	END D[58]

	PIN D[59]
		USE SIGNAL ;
		DIRECTION INPUT ;
		SHAPE ABUTMENT ;
		PORT
			 LAYER M2 ;
			RECT 0.0098 83.5451 0.0481 83.5827 ;
			 LAYER M3 ;
			RECT 0.0098 83.4824 0.0481 83.5827 ;
			 LAYER V2 ;
			RECT 0.0215 83.5573 0.0364 83.5698 ;
		END

		ANTENNAGATEAREA 0.00027817 ;
		ANTENNADIFFAREA 0.00194719 ;
		ANTENNAPARTIALMETALAREA 0.00195671 ;
	END D[59]

	PIN D[5]
		USE SIGNAL ;
		DIRECTION INPUT ;
		SHAPE ABUTMENT ;
		PORT
			 LAYER M2 ;
			RECT 0.0098 7.7678 0.0481 7.8055 ;
			 LAYER M3 ;
			RECT 0.0098 7.7678 0.0481 7.8682 ;
			 LAYER V2 ;
			RECT 0.0215 7.7808 0.0364 7.7933 ;
		END

		ANTENNAGATEAREA 0.00027817 ;
		ANTENNADIFFAREA 0.00194719 ;
		ANTENNAPARTIALMETALAREA 0.00195671 ;
	END D[5]

	PIN D[60]
		USE SIGNAL ;
		DIRECTION INPUT ;
		SHAPE ABUTMENT ;
		PORT
			 LAYER M2 ;
			RECT 0.0098 84.8251 0.0481 84.8627 ;
			 LAYER M3 ;
			RECT 0.0098 84.7624 0.0481 84.8627 ;
			 LAYER V2 ;
			RECT 0.0215 84.8373 0.0364 84.8498 ;
		END

		ANTENNAGATEAREA 0.00027817 ;
		ANTENNADIFFAREA 0.00194719 ;
		ANTENNAPARTIALMETALAREA 0.00195671 ;
	END D[60]

	PIN D[61]
		USE SIGNAL ;
		DIRECTION INPUT ;
		SHAPE ABUTMENT ;
		PORT
			 LAYER M2 ;
			RECT 0.0098 86.1051 0.0481 86.1427 ;
			 LAYER M3 ;
			RECT 0.0098 86.0424 0.0481 86.1427 ;
			 LAYER V2 ;
			RECT 0.0215 86.1173 0.0364 86.1298 ;
		END

		ANTENNAGATEAREA 0.00027817 ;
		ANTENNADIFFAREA 0.00194719 ;
		ANTENNAPARTIALMETALAREA 0.00195671 ;
	END D[61]

	PIN D[62]
		USE SIGNAL ;
		DIRECTION INPUT ;
		SHAPE ABUTMENT ;
		PORT
			 LAYER M2 ;
			RECT 0.0098 87.3851 0.0481 87.4227 ;
			 LAYER M3 ;
			RECT 0.0098 87.3224 0.0481 87.4227 ;
			 LAYER V2 ;
			RECT 0.0215 87.3973 0.0364 87.4098 ;
		END

		ANTENNAGATEAREA 0.00027817 ;
		ANTENNADIFFAREA 0.00194719 ;
		ANTENNAPARTIALMETALAREA 0.00195671 ;
	END D[62]

	PIN D[63]
		USE SIGNAL ;
		DIRECTION INPUT ;
		SHAPE ABUTMENT ;
		PORT
			 LAYER M2 ;
			RECT 0.0098 88.6651 0.0481 88.7027 ;
			 LAYER M3 ;
			RECT 0.0098 88.6024 0.0481 88.7027 ;
			 LAYER V2 ;
			RECT 0.0215 88.6773 0.0364 88.6898 ;
		END

		ANTENNAGATEAREA 0.00027817 ;
		ANTENNADIFFAREA 0.00194719 ;
		ANTENNAPARTIALMETALAREA 0.00195671 ;
	END D[63]

	PIN D[64]
		USE SIGNAL ;
		DIRECTION INPUT ;
		SHAPE ABUTMENT ;
		PORT
			 LAYER M2 ;
			RECT 0.0098 89.9451 0.0481 89.9827 ;
			 LAYER M3 ;
			RECT 0.0098 89.8824 0.0481 89.9827 ;
			 LAYER V2 ;
			RECT 0.0215 89.9573 0.0364 89.9698 ;
		END

		ANTENNAGATEAREA 0.00027817 ;
		ANTENNADIFFAREA 0.00194719 ;
		ANTENNAPARTIALMETALAREA 0.00195671 ;
	END D[64]

	PIN D[65]
		USE SIGNAL ;
		DIRECTION INPUT ;
		SHAPE ABUTMENT ;
		PORT
			 LAYER M2 ;
			RECT 0.0098 91.2251 0.0481 91.2627 ;
			 LAYER M3 ;
			RECT 0.0098 91.1624 0.0481 91.2627 ;
			 LAYER V2 ;
			RECT 0.0215 91.2373 0.0364 91.2498 ;
		END

		ANTENNAGATEAREA 0.00027817 ;
		ANTENNADIFFAREA 0.00194719 ;
		ANTENNAPARTIALMETALAREA 0.00195671 ;
	END D[65]

	PIN D[6]
		USE SIGNAL ;
		DIRECTION INPUT ;
		SHAPE ABUTMENT ;
		PORT
			 LAYER M2 ;
			RECT 0.0098 9.0478 0.0481 9.0855 ;
			 LAYER M3 ;
			RECT 0.0098 9.0478 0.0481 9.1482 ;
			 LAYER V2 ;
			RECT 0.0215 9.0608 0.0364 9.0733 ;
		END

		ANTENNAGATEAREA 0.00027817 ;
		ANTENNADIFFAREA 0.00194719 ;
		ANTENNAPARTIALMETALAREA 0.00195671 ;
	END D[6]

	PIN D[7]
		USE SIGNAL ;
		DIRECTION INPUT ;
		SHAPE ABUTMENT ;
		PORT
			 LAYER M2 ;
			RECT 0.0098 10.3278 0.0481 10.3655 ;
			 LAYER M3 ;
			RECT 0.0098 10.3278 0.0481 10.4282 ;
			 LAYER V2 ;
			RECT 0.0215 10.3408 0.0364 10.3533 ;
		END

		ANTENNAGATEAREA 0.00027817 ;
		ANTENNADIFFAREA 0.00194719 ;
		ANTENNAPARTIALMETALAREA 0.00195671 ;
	END D[7]

	PIN D[8]
		USE SIGNAL ;
		DIRECTION INPUT ;
		SHAPE ABUTMENT ;
		PORT
			 LAYER M2 ;
			RECT 0.0098 11.6078 0.0481 11.6455 ;
			 LAYER M3 ;
			RECT 0.0098 11.6078 0.0481 11.7082 ;
			 LAYER V2 ;
			RECT 0.0215 11.6208 0.0364 11.6333 ;
		END

		ANTENNAGATEAREA 0.00027817 ;
		ANTENNADIFFAREA 0.00194719 ;
		ANTENNAPARTIALMETALAREA 0.00195671 ;
	END D[8]

	PIN D[9]
		USE SIGNAL ;
		DIRECTION INPUT ;
		SHAPE ABUTMENT ;
		PORT
			 LAYER M2 ;
			RECT 0.0098 12.8878 0.0481 12.9255 ;
			 LAYER M3 ;
			RECT 0.0098 12.8878 0.0481 12.9882 ;
			 LAYER V2 ;
			RECT 0.0215 12.9008 0.0364 12.9133 ;
		END

		ANTENNAGATEAREA 0.00027817 ;
		ANTENNADIFFAREA 0.00194719 ;
		ANTENNAPARTIALMETALAREA 0.00195671 ;
	END D[9]

	PIN EMAS
		USE SIGNAL ;
		DIRECTION INPUT ;
		SHAPE ABUTMENT ;
		PORT
			 LAYER M2 ;
			RECT 0.0714 44.8878 0.1097 44.9255 ;
			 LAYER M3 ;
			RECT 0.0714 44.8878 0.1097 44.9882 ;
			 LAYER V2 ;
			RECT 0.0831 44.9 0.098 44.9125 ;
		END

		ANTENNAGATEAREA 0.00027817 ;
		ANTENNADIFFAREA 0.00194719 ;
		ANTENNAPARTIALMETALAREA 0.00195671 ;
	END EMAS

	PIN EMAW[0]
		USE SIGNAL ;
		DIRECTION INPUT ;
		SHAPE ABUTMENT ;
		PORT
			 LAYER M2 ;
			RECT 0.0714 43.6831 0.1097 43.7208 ;
			 LAYER M3 ;
			RECT 0.0714 43.6831 0.1097 43.7835 ;
			 LAYER V2 ;
			RECT 0.0831 43.6953 0.098 43.7078 ;
		END

		ANTENNAGATEAREA 0.00027817 ;
		ANTENNADIFFAREA 0.00194719 ;
		ANTENNAPARTIALMETALAREA 0.00195671 ;
	END EMAW[0]

	PIN EMAW[1]
		USE SIGNAL ;
		DIRECTION INPUT ;
		SHAPE ABUTMENT ;
		PORT
			 LAYER M2 ;
			RECT 0.0098 43.7459 0.0481 43.7835 ;
			 LAYER M3 ;
			RECT 0.0098 43.6831 0.0481 43.7835 ;
			 LAYER V2 ;
			RECT 0.0215 43.758 0.0364 43.7706 ;
		END

		ANTENNAGATEAREA 0.00027817 ;
		ANTENNADIFFAREA 0.00194719 ;
		ANTENNAPARTIALMETALAREA 0.00195671 ;
	END EMAW[1]

	PIN EMA[0]
		USE SIGNAL ;
		DIRECTION INPUT ;
		SHAPE ABUTMENT ;
		PORT
			 LAYER M2 ;
			RECT 0.0098 43.4447 0.0481 43.4824 ;
			 LAYER M3 ;
			RECT 0.0098 43.382 0.0481 43.4824 ;
			 LAYER V2 ;
			RECT 0.0215 43.4569 0.0364 43.4694 ;
		END

		ANTENNAGATEAREA 0.00027817 ;
		ANTENNADIFFAREA 0.00194719 ;
		ANTENNAPARTIALMETALAREA 0.00195671 ;
	END EMA[0]

	PIN EMA[1]
		USE SIGNAL ;
		DIRECTION INPUT ;
		SHAPE ABUTMENT ;
		PORT
			 LAYER M2 ;
			RECT 0.0714 43.5325 0.1097 43.5702 ;
			 LAYER M3 ;
			RECT 0.0714 43.5325 0.1097 43.6329 ;
			 LAYER V2 ;
			RECT 0.0831 43.5447 0.098 43.5573 ;
		END

		ANTENNAGATEAREA 0.00027817 ;
		ANTENNADIFFAREA 0.00194719 ;
		ANTENNAPARTIALMETALAREA 0.00195671 ;
	END EMA[1]

	PIN EMA[2]
		USE SIGNAL ;
		DIRECTION INPUT ;
		SHAPE ABUTMENT ;
		PORT
			 LAYER M2 ;
			RECT 0.0714 44.4361 0.1097 44.4737 ;
			 LAYER M3 ;
			RECT 0.0714 44.4361 0.1097 44.5365 ;
			 LAYER V2 ;
			RECT 0.0831 44.4482 0.098 44.4608 ;
		END

		ANTENNAGATEAREA 0.00027817 ;
		ANTENNADIFFAREA 0.00194719 ;
		ANTENNAPARTIALMETALAREA 0.00195671 ;
	END EMA[2]

	PIN GWEN
		USE SIGNAL ;
		DIRECTION INPUT ;
		SHAPE ABUTMENT ;
		PORT
			 LAYER M2 ;
			RECT 0.0098 44.3482 0.0481 44.3859 ;
			 LAYER M3 ;
			RECT 0.0098 44.2855 0.0481 44.3859 ;
			 LAYER V2 ;
			RECT 0.0215 44.3604 0.0364 44.3729 ;
		END

		ANTENNAGATEAREA 0.00027817 ;
		ANTENNADIFFAREA 0.00194719 ;
		ANTENNAPARTIALMETALAREA 0.00195671 ;
	END GWEN

	PIN GWENY
		USE SIGNAL ;
		DIRECTION OUTPUT ;
		SHAPE ABUTMENT ;
		PORT
			 LAYER M2 ;
			RECT 0.0714 45.0384 0.1097 45.0761 ;
			 LAYER M3 ;
			RECT 0.0714 45.0384 0.1097 45.1388 ;
			 LAYER V2 ;
			RECT 0.0831 45.0506 0.098 45.0631 ;
		END

		ANTENNADIFFAREA 0.00194719 ;
		ANTENNAPARTIALMETALAREA 0.00195671 ;
	END GWENY

	PIN Q[0]
		USE SIGNAL ;
		DIRECTION OUTPUT ;
		SHAPE ABUTMENT ;
		PORT
			 LAYER M2 ;
			RECT 0.0098 1.0918 0.0481 1.1922 ;
			 LAYER M3 ;
			RECT 0.0098 1.0918 0.0481 1.1922 ;
			 LAYER V2 ;
			RECT 0.021 1.1667 0.0359 1.1792 ;
		END

		ANTENNADIFFAREA 0.00194719 ;
		ANTENNAPARTIALMETALAREA 0.00195671 ;
	END Q[0]

	PIN Q[10]
		USE SIGNAL ;
		DIRECTION OUTPUT ;
		SHAPE ABUTMENT ;
		PORT
			 LAYER M2 ;
			RECT 0.0098 13.8918 0.0481 13.9922 ;
			 LAYER M3 ;
			RECT 0.0098 13.8918 0.0481 13.9922 ;
			 LAYER V2 ;
			RECT 0.021 13.9667 0.0359 13.9792 ;
		END

		ANTENNADIFFAREA 0.00194719 ;
		ANTENNAPARTIALMETALAREA 0.00195671 ;
	END Q[10]

	PIN Q[11]
		USE SIGNAL ;
		DIRECTION OUTPUT ;
		SHAPE ABUTMENT ;
		PORT
			 LAYER M2 ;
			RECT 0.0098 15.1718 0.0481 15.2722 ;
			 LAYER M3 ;
			RECT 0.0098 15.1718 0.0481 15.2722 ;
			 LAYER V2 ;
			RECT 0.021 15.2467 0.0359 15.2592 ;
		END

		ANTENNADIFFAREA 0.00194719 ;
		ANTENNAPARTIALMETALAREA 0.00195671 ;
	END Q[11]

	PIN Q[12]
		USE SIGNAL ;
		DIRECTION OUTPUT ;
		SHAPE ABUTMENT ;
		PORT
			 LAYER M2 ;
			RECT 0.0098 16.4518 0.0481 16.5522 ;
			 LAYER M3 ;
			RECT 0.0098 16.4518 0.0481 16.5522 ;
			 LAYER V2 ;
			RECT 0.021 16.5267 0.0359 16.5392 ;
		END

		ANTENNADIFFAREA 0.00194719 ;
		ANTENNAPARTIALMETALAREA 0.00195671 ;
	END Q[12]

	PIN Q[13]
		USE SIGNAL ;
		DIRECTION OUTPUT ;
		SHAPE ABUTMENT ;
		PORT
			 LAYER M2 ;
			RECT 0.0098 17.7318 0.0481 17.8322 ;
			 LAYER M3 ;
			RECT 0.0098 17.7318 0.0481 17.8322 ;
			 LAYER V2 ;
			RECT 0.021 17.8067 0.0359 17.8192 ;
		END

		ANTENNADIFFAREA 0.00194719 ;
		ANTENNAPARTIALMETALAREA 0.00195671 ;
	END Q[13]

	PIN Q[14]
		USE SIGNAL ;
		DIRECTION OUTPUT ;
		SHAPE ABUTMENT ;
		PORT
			 LAYER M2 ;
			RECT 0.0098 19.0118 0.0481 19.1122 ;
			 LAYER M3 ;
			RECT 0.0098 19.0118 0.0481 19.1122 ;
			 LAYER V2 ;
			RECT 0.021 19.0867 0.0359 19.0992 ;
		END

		ANTENNADIFFAREA 0.00194719 ;
		ANTENNAPARTIALMETALAREA 0.00195671 ;
	END Q[14]

	PIN Q[15]
		USE SIGNAL ;
		DIRECTION OUTPUT ;
		SHAPE ABUTMENT ;
		PORT
			 LAYER M2 ;
			RECT 0.0098 20.2918 0.0481 20.3922 ;
			 LAYER M3 ;
			RECT 0.0098 20.2918 0.0481 20.3922 ;
			 LAYER V2 ;
			RECT 0.021 20.3667 0.0359 20.3792 ;
		END

		ANTENNADIFFAREA 0.00194719 ;
		ANTENNAPARTIALMETALAREA 0.00195671 ;
	END Q[15]

	PIN Q[16]
		USE SIGNAL ;
		DIRECTION OUTPUT ;
		SHAPE ABUTMENT ;
		PORT
			 LAYER M2 ;
			RECT 0.0098 21.5718 0.0481 21.6722 ;
			 LAYER M3 ;
			RECT 0.0098 21.5718 0.0481 21.6722 ;
			 LAYER V2 ;
			RECT 0.021 21.6467 0.0359 21.6592 ;
		END

		ANTENNADIFFAREA 0.00194719 ;
		ANTENNAPARTIALMETALAREA 0.00195671 ;
	END Q[16]

	PIN Q[17]
		USE SIGNAL ;
		DIRECTION OUTPUT ;
		SHAPE ABUTMENT ;
		PORT
			 LAYER M2 ;
			RECT 0.0098 22.8518 0.0481 22.9522 ;
			 LAYER M3 ;
			RECT 0.0098 22.8518 0.0481 22.9522 ;
			 LAYER V2 ;
			RECT 0.021 22.9267 0.0359 22.9392 ;
		END

		ANTENNADIFFAREA 0.00194719 ;
		ANTENNAPARTIALMETALAREA 0.00195671 ;
	END Q[17]

	PIN Q[18]
		USE SIGNAL ;
		DIRECTION OUTPUT ;
		SHAPE ABUTMENT ;
		PORT
			 LAYER M2 ;
			RECT 0.0098 24.1318 0.0481 24.2322 ;
			 LAYER M3 ;
			RECT 0.0098 24.1318 0.0481 24.2322 ;
			 LAYER V2 ;
			RECT 0.021 24.2067 0.0359 24.2192 ;
		END

		ANTENNADIFFAREA 0.00194719 ;
		ANTENNAPARTIALMETALAREA 0.00195671 ;
	END Q[18]

	PIN Q[19]
		USE SIGNAL ;
		DIRECTION OUTPUT ;
		SHAPE ABUTMENT ;
		PORT
			 LAYER M2 ;
			RECT 0.0098 25.4118 0.0481 25.5122 ;
			 LAYER M3 ;
			RECT 0.0098 25.4118 0.0481 25.5122 ;
			 LAYER V2 ;
			RECT 0.021 25.4867 0.0359 25.4992 ;
		END

		ANTENNADIFFAREA 0.00194719 ;
		ANTENNAPARTIALMETALAREA 0.00195671 ;
	END Q[19]

	PIN Q[1]
		USE SIGNAL ;
		DIRECTION OUTPUT ;
		SHAPE ABUTMENT ;
		PORT
			 LAYER M2 ;
			RECT 0.0098 2.3718 0.0481 2.4722 ;
			 LAYER M3 ;
			RECT 0.0098 2.3718 0.0481 2.4722 ;
			 LAYER V2 ;
			RECT 0.021 2.4467 0.0359 2.4592 ;
		END

		ANTENNADIFFAREA 0.00194719 ;
		ANTENNAPARTIALMETALAREA 0.00195671 ;
	END Q[1]

	PIN Q[20]
		USE SIGNAL ;
		DIRECTION OUTPUT ;
		SHAPE ABUTMENT ;
		PORT
			 LAYER M2 ;
			RECT 0.0098 26.6918 0.0481 26.7922 ;
			 LAYER M3 ;
			RECT 0.0098 26.6918 0.0481 26.7922 ;
			 LAYER V2 ;
			RECT 0.021 26.7667 0.0359 26.7792 ;
		END

		ANTENNADIFFAREA 0.00194719 ;
		ANTENNAPARTIALMETALAREA 0.00195671 ;
	END Q[20]

	PIN Q[21]
		USE SIGNAL ;
		DIRECTION OUTPUT ;
		SHAPE ABUTMENT ;
		PORT
			 LAYER M2 ;
			RECT 0.0098 27.9718 0.0481 28.0722 ;
			 LAYER M3 ;
			RECT 0.0098 27.9718 0.0481 28.0722 ;
			 LAYER V2 ;
			RECT 0.021 28.0467 0.0359 28.0592 ;
		END

		ANTENNADIFFAREA 0.00194719 ;
		ANTENNAPARTIALMETALAREA 0.00195671 ;
	END Q[21]

	PIN Q[22]
		USE SIGNAL ;
		DIRECTION OUTPUT ;
		SHAPE ABUTMENT ;
		PORT
			 LAYER M2 ;
			RECT 0.0098 29.2518 0.0481 29.3522 ;
			 LAYER M3 ;
			RECT 0.0098 29.2518 0.0481 29.3522 ;
			 LAYER V2 ;
			RECT 0.021 29.3267 0.0359 29.3392 ;
		END

		ANTENNADIFFAREA 0.00194719 ;
		ANTENNAPARTIALMETALAREA 0.00195671 ;
	END Q[22]

	PIN Q[23]
		USE SIGNAL ;
		DIRECTION OUTPUT ;
		SHAPE ABUTMENT ;
		PORT
			 LAYER M2 ;
			RECT 0.0098 30.5318 0.0481 30.6322 ;
			 LAYER M3 ;
			RECT 0.0098 30.5318 0.0481 30.6322 ;
			 LAYER V2 ;
			RECT 0.021 30.6067 0.0359 30.6192 ;
		END

		ANTENNADIFFAREA 0.00194719 ;
		ANTENNAPARTIALMETALAREA 0.00195671 ;
	END Q[23]

	PIN Q[24]
		USE SIGNAL ;
		DIRECTION OUTPUT ;
		SHAPE ABUTMENT ;
		PORT
			 LAYER M2 ;
			RECT 0.0098 31.8118 0.0481 31.9122 ;
			 LAYER M3 ;
			RECT 0.0098 31.8118 0.0481 31.9122 ;
			 LAYER V2 ;
			RECT 0.021 31.8867 0.0359 31.8992 ;
		END

		ANTENNADIFFAREA 0.00194719 ;
		ANTENNAPARTIALMETALAREA 0.00195671 ;
	END Q[24]

	PIN Q[25]
		USE SIGNAL ;
		DIRECTION OUTPUT ;
		SHAPE ABUTMENT ;
		PORT
			 LAYER M2 ;
			RECT 0.0098 33.0918 0.0481 33.1922 ;
			 LAYER M3 ;
			RECT 0.0098 33.0918 0.0481 33.1922 ;
			 LAYER V2 ;
			RECT 0.021 33.1667 0.0359 33.1792 ;
		END

		ANTENNADIFFAREA 0.00194719 ;
		ANTENNAPARTIALMETALAREA 0.00195671 ;
	END Q[25]

	PIN Q[26]
		USE SIGNAL ;
		DIRECTION OUTPUT ;
		SHAPE ABUTMENT ;
		PORT
			 LAYER M2 ;
			RECT 0.0098 34.3718 0.0481 34.4722 ;
			 LAYER M3 ;
			RECT 0.0098 34.3718 0.0481 34.4722 ;
			 LAYER V2 ;
			RECT 0.021 34.4467 0.0359 34.4592 ;
		END

		ANTENNADIFFAREA 0.00194719 ;
		ANTENNAPARTIALMETALAREA 0.00195671 ;
	END Q[26]

	PIN Q[27]
		USE SIGNAL ;
		DIRECTION OUTPUT ;
		SHAPE ABUTMENT ;
		PORT
			 LAYER M2 ;
			RECT 0.0098 35.6518 0.0481 35.7522 ;
			 LAYER M3 ;
			RECT 0.0098 35.6518 0.0481 35.7522 ;
			 LAYER V2 ;
			RECT 0.021 35.7267 0.0359 35.7392 ;
		END

		ANTENNADIFFAREA 0.00194719 ;
		ANTENNAPARTIALMETALAREA 0.00195671 ;
	END Q[27]

	PIN Q[28]
		USE SIGNAL ;
		DIRECTION OUTPUT ;
		SHAPE ABUTMENT ;
		PORT
			 LAYER M2 ;
			RECT 0.0098 36.9318 0.0481 37.0322 ;
			 LAYER M3 ;
			RECT 0.0098 36.9318 0.0481 37.0322 ;
			 LAYER V2 ;
			RECT 0.021 37.0067 0.0359 37.0192 ;
		END

		ANTENNADIFFAREA 0.00194719 ;
		ANTENNAPARTIALMETALAREA 0.00195671 ;
	END Q[28]

	PIN Q[29]
		USE SIGNAL ;
		DIRECTION OUTPUT ;
		SHAPE ABUTMENT ;
		PORT
			 LAYER M2 ;
			RECT 0.0098 38.2118 0.0481 38.3122 ;
			 LAYER M3 ;
			RECT 0.0098 38.2118 0.0481 38.3122 ;
			 LAYER V2 ;
			RECT 0.021 38.2867 0.0359 38.2992 ;
		END

		ANTENNADIFFAREA 0.00194719 ;
		ANTENNAPARTIALMETALAREA 0.00195671 ;
	END Q[29]

	PIN Q[2]
		USE SIGNAL ;
		DIRECTION OUTPUT ;
		SHAPE ABUTMENT ;
		PORT
			 LAYER M2 ;
			RECT 0.0098 3.6518 0.0481 3.7522 ;
			 LAYER M3 ;
			RECT 0.0098 3.6518 0.0481 3.7522 ;
			 LAYER V2 ;
			RECT 0.021 3.7267 0.0359 3.7392 ;
		END

		ANTENNADIFFAREA 0.00194719 ;
		ANTENNAPARTIALMETALAREA 0.00195671 ;
	END Q[2]

	PIN Q[30]
		USE SIGNAL ;
		DIRECTION OUTPUT ;
		SHAPE ABUTMENT ;
		PORT
			 LAYER M2 ;
			RECT 0.0098 39.4918 0.0481 39.5922 ;
			 LAYER M3 ;
			RECT 0.0098 39.4918 0.0481 39.5922 ;
			 LAYER V2 ;
			RECT 0.021 39.5667 0.0359 39.5792 ;
		END

		ANTENNADIFFAREA 0.00194719 ;
		ANTENNAPARTIALMETALAREA 0.00195671 ;
	END Q[30]

	PIN Q[31]
		USE SIGNAL ;
		DIRECTION OUTPUT ;
		SHAPE ABUTMENT ;
		PORT
			 LAYER M2 ;
			RECT 0.0098 40.7718 0.0481 40.8722 ;
			 LAYER M3 ;
			RECT 0.0098 40.7718 0.0481 40.8722 ;
			 LAYER V2 ;
			RECT 0.021 40.8467 0.0359 40.8592 ;
		END

		ANTENNADIFFAREA 0.00194719 ;
		ANTENNAPARTIALMETALAREA 0.00195671 ;
	END Q[31]

	PIN Q[32]
		USE SIGNAL ;
		DIRECTION OUTPUT ;
		SHAPE ABUTMENT ;
		PORT
			 LAYER M2 ;
			RECT 0.0098 42.0518 0.0481 42.1522 ;
			 LAYER M3 ;
			RECT 0.0098 42.0518 0.0481 42.1522 ;
			 LAYER V2 ;
			RECT 0.021 42.1267 0.0359 42.1392 ;
		END

		ANTENNADIFFAREA 0.00194719 ;
		ANTENNAPARTIALMETALAREA 0.00195671 ;
	END Q[32]

	PIN Q[33]
		USE SIGNAL ;
		DIRECTION OUTPUT ;
		SHAPE ABUTMENT ;
		PORT
			 LAYER M2 ;
			RECT 0.0098 50.4784 0.0481 50.5788 ;
			 LAYER M3 ;
			RECT 0.0098 50.4784 0.0481 50.5788 ;
			 LAYER V2 ;
			RECT 0.021 50.4914 0.0359 50.5039 ;
		END

		ANTENNADIFFAREA 0.00194719 ;
		ANTENNAPARTIALMETALAREA 0.00195671 ;
	END Q[33]

	PIN Q[34]
		USE SIGNAL ;
		DIRECTION OUTPUT ;
		SHAPE ABUTMENT ;
		PORT
			 LAYER M2 ;
			RECT 0.0098 51.7584 0.0481 51.8588 ;
			 LAYER M3 ;
			RECT 0.0098 51.7584 0.0481 51.8588 ;
			 LAYER V2 ;
			RECT 0.021 51.7714 0.0359 51.7839 ;
		END

		ANTENNADIFFAREA 0.00194719 ;
		ANTENNAPARTIALMETALAREA 0.00195671 ;
	END Q[34]

	PIN Q[35]
		USE SIGNAL ;
		DIRECTION OUTPUT ;
		SHAPE ABUTMENT ;
		PORT
			 LAYER M2 ;
			RECT 0.0098 53.0384 0.0481 53.1388 ;
			 LAYER M3 ;
			RECT 0.0098 53.0384 0.0481 53.1388 ;
			 LAYER V2 ;
			RECT 0.021 53.0514 0.0359 53.0639 ;
		END

		ANTENNADIFFAREA 0.00194719 ;
		ANTENNAPARTIALMETALAREA 0.00195671 ;
	END Q[35]

	PIN Q[36]
		USE SIGNAL ;
		DIRECTION OUTPUT ;
		SHAPE ABUTMENT ;
		PORT
			 LAYER M2 ;
			RECT 0.0098 54.3184 0.0481 54.4188 ;
			 LAYER M3 ;
			RECT 0.0098 54.3184 0.0481 54.4188 ;
			 LAYER V2 ;
			RECT 0.021 54.3314 0.0359 54.3439 ;
		END

		ANTENNADIFFAREA 0.00194719 ;
		ANTENNAPARTIALMETALAREA 0.00195671 ;
	END Q[36]

	PIN Q[37]
		USE SIGNAL ;
		DIRECTION OUTPUT ;
		SHAPE ABUTMENT ;
		PORT
			 LAYER M2 ;
			RECT 0.0098 55.5984 0.0481 55.6988 ;
			 LAYER M3 ;
			RECT 0.0098 55.5984 0.0481 55.6988 ;
			 LAYER V2 ;
			RECT 0.021 55.6114 0.0359 55.6239 ;
		END

		ANTENNADIFFAREA 0.00194719 ;
		ANTENNAPARTIALMETALAREA 0.00195671 ;
	END Q[37]

	PIN Q[38]
		USE SIGNAL ;
		DIRECTION OUTPUT ;
		SHAPE ABUTMENT ;
		PORT
			 LAYER M2 ;
			RECT 0.0098 56.8784 0.0481 56.9788 ;
			 LAYER M3 ;
			RECT 0.0098 56.8784 0.0481 56.9788 ;
			 LAYER V2 ;
			RECT 0.021 56.8914 0.0359 56.9039 ;
		END

		ANTENNADIFFAREA 0.00194719 ;
		ANTENNAPARTIALMETALAREA 0.00195671 ;
	END Q[38]

	PIN Q[39]
		USE SIGNAL ;
		DIRECTION OUTPUT ;
		SHAPE ABUTMENT ;
		PORT
			 LAYER M2 ;
			RECT 0.0098 58.1584 0.0481 58.2588 ;
			 LAYER M3 ;
			RECT 0.0098 58.1584 0.0481 58.2588 ;
			 LAYER V2 ;
			RECT 0.021 58.1714 0.0359 58.1839 ;
		END

		ANTENNADIFFAREA 0.00194719 ;
		ANTENNAPARTIALMETALAREA 0.00195671 ;
	END Q[39]

	PIN Q[3]
		USE SIGNAL ;
		DIRECTION OUTPUT ;
		SHAPE ABUTMENT ;
		PORT
			 LAYER M2 ;
			RECT 0.0098 4.9318 0.0481 5.0322 ;
			 LAYER M3 ;
			RECT 0.0098 4.9318 0.0481 5.0322 ;
			 LAYER V2 ;
			RECT 0.021 5.0067 0.0359 5.0192 ;
		END

		ANTENNADIFFAREA 0.00194719 ;
		ANTENNAPARTIALMETALAREA 0.00195671 ;
	END Q[3]

	PIN Q[40]
		USE SIGNAL ;
		DIRECTION OUTPUT ;
		SHAPE ABUTMENT ;
		PORT
			 LAYER M2 ;
			RECT 0.0098 59.4384 0.0481 59.5388 ;
			 LAYER M3 ;
			RECT 0.0098 59.4384 0.0481 59.5388 ;
			 LAYER V2 ;
			RECT 0.021 59.4514 0.0359 59.4639 ;
		END

		ANTENNADIFFAREA 0.00194719 ;
		ANTENNAPARTIALMETALAREA 0.00195671 ;
	END Q[40]

	PIN Q[41]
		USE SIGNAL ;
		DIRECTION OUTPUT ;
		SHAPE ABUTMENT ;
		PORT
			 LAYER M2 ;
			RECT 0.0098 60.7184 0.0481 60.8188 ;
			 LAYER M3 ;
			RECT 0.0098 60.7184 0.0481 60.8188 ;
			 LAYER V2 ;
			RECT 0.021 60.7314 0.0359 60.7439 ;
		END

		ANTENNADIFFAREA 0.00194719 ;
		ANTENNAPARTIALMETALAREA 0.00195671 ;
	END Q[41]

	PIN Q[42]
		USE SIGNAL ;
		DIRECTION OUTPUT ;
		SHAPE ABUTMENT ;
		PORT
			 LAYER M2 ;
			RECT 0.0098 61.9984 0.0481 62.0988 ;
			 LAYER M3 ;
			RECT 0.0098 61.9984 0.0481 62.0988 ;
			 LAYER V2 ;
			RECT 0.021 62.0114 0.0359 62.0239 ;
		END

		ANTENNADIFFAREA 0.00194719 ;
		ANTENNAPARTIALMETALAREA 0.00195671 ;
	END Q[42]

	PIN Q[43]
		USE SIGNAL ;
		DIRECTION OUTPUT ;
		SHAPE ABUTMENT ;
		PORT
			 LAYER M2 ;
			RECT 0.0098 63.2784 0.0481 63.3788 ;
			 LAYER M3 ;
			RECT 0.0098 63.2784 0.0481 63.3788 ;
			 LAYER V2 ;
			RECT 0.021 63.2914 0.0359 63.3039 ;
		END

		ANTENNADIFFAREA 0.00194719 ;
		ANTENNAPARTIALMETALAREA 0.00195671 ;
	END Q[43]

	PIN Q[44]
		USE SIGNAL ;
		DIRECTION OUTPUT ;
		SHAPE ABUTMENT ;
		PORT
			 LAYER M2 ;
			RECT 0.0098 64.5584 0.0481 64.6588 ;
			 LAYER M3 ;
			RECT 0.0098 64.5584 0.0481 64.6588 ;
			 LAYER V2 ;
			RECT 0.021 64.5714 0.0359 64.5839 ;
		END

		ANTENNADIFFAREA 0.00194719 ;
		ANTENNAPARTIALMETALAREA 0.00195671 ;
	END Q[44]

	PIN Q[45]
		USE SIGNAL ;
		DIRECTION OUTPUT ;
		SHAPE ABUTMENT ;
		PORT
			 LAYER M2 ;
			RECT 0.0098 65.8384 0.0481 65.9388 ;
			 LAYER M3 ;
			RECT 0.0098 65.8384 0.0481 65.9388 ;
			 LAYER V2 ;
			RECT 0.021 65.8514 0.0359 65.8639 ;
		END

		ANTENNADIFFAREA 0.00194719 ;
		ANTENNAPARTIALMETALAREA 0.00195671 ;
	END Q[45]

	PIN Q[46]
		USE SIGNAL ;
		DIRECTION OUTPUT ;
		SHAPE ABUTMENT ;
		PORT
			 LAYER M2 ;
			RECT 0.0098 67.1184 0.0481 67.2188 ;
			 LAYER M3 ;
			RECT 0.0098 67.1184 0.0481 67.2188 ;
			 LAYER V2 ;
			RECT 0.021 67.1314 0.0359 67.1439 ;
		END

		ANTENNADIFFAREA 0.00194719 ;
		ANTENNAPARTIALMETALAREA 0.00195671 ;
	END Q[46]

	PIN Q[47]
		USE SIGNAL ;
		DIRECTION OUTPUT ;
		SHAPE ABUTMENT ;
		PORT
			 LAYER M2 ;
			RECT 0.0098 68.3984 0.0481 68.4988 ;
			 LAYER M3 ;
			RECT 0.0098 68.3984 0.0481 68.4988 ;
			 LAYER V2 ;
			RECT 0.021 68.4114 0.0359 68.4239 ;
		END

		ANTENNADIFFAREA 0.00194719 ;
		ANTENNAPARTIALMETALAREA 0.00195671 ;
	END Q[47]

	PIN Q[48]
		USE SIGNAL ;
		DIRECTION OUTPUT ;
		SHAPE ABUTMENT ;
		PORT
			 LAYER M2 ;
			RECT 0.0098 69.6784 0.0481 69.7788 ;
			 LAYER M3 ;
			RECT 0.0098 69.6784 0.0481 69.7788 ;
			 LAYER V2 ;
			RECT 0.021 69.6914 0.0359 69.7039 ;
		END

		ANTENNADIFFAREA 0.00194719 ;
		ANTENNAPARTIALMETALAREA 0.00195671 ;
	END Q[48]

	PIN Q[49]
		USE SIGNAL ;
		DIRECTION OUTPUT ;
		SHAPE ABUTMENT ;
		PORT
			 LAYER M2 ;
			RECT 0.0098 70.9584 0.0481 71.0588 ;
			 LAYER M3 ;
			RECT 0.0098 70.9584 0.0481 71.0588 ;
			 LAYER V2 ;
			RECT 0.021 70.9714 0.0359 70.9839 ;
		END

		ANTENNADIFFAREA 0.00194719 ;
		ANTENNAPARTIALMETALAREA 0.00195671 ;
	END Q[49]

	PIN Q[4]
		USE SIGNAL ;
		DIRECTION OUTPUT ;
		SHAPE ABUTMENT ;
		PORT
			 LAYER M2 ;
			RECT 0.0098 6.2118 0.0481 6.3122 ;
			 LAYER M3 ;
			RECT 0.0098 6.2118 0.0481 6.3122 ;
			 LAYER V2 ;
			RECT 0.021 6.2867 0.0359 6.2992 ;
		END

		ANTENNADIFFAREA 0.00194719 ;
		ANTENNAPARTIALMETALAREA 0.00195671 ;
	END Q[4]

	PIN Q[50]
		USE SIGNAL ;
		DIRECTION OUTPUT ;
		SHAPE ABUTMENT ;
		PORT
			 LAYER M2 ;
			RECT 0.0098 72.2384 0.0481 72.3388 ;
			 LAYER M3 ;
			RECT 0.0098 72.2384 0.0481 72.3388 ;
			 LAYER V2 ;
			RECT 0.021 72.2514 0.0359 72.2639 ;
		END

		ANTENNADIFFAREA 0.00194719 ;
		ANTENNAPARTIALMETALAREA 0.00195671 ;
	END Q[50]

	PIN Q[51]
		USE SIGNAL ;
		DIRECTION OUTPUT ;
		SHAPE ABUTMENT ;
		PORT
			 LAYER M2 ;
			RECT 0.0098 73.5184 0.0481 73.6188 ;
			 LAYER M3 ;
			RECT 0.0098 73.5184 0.0481 73.6188 ;
			 LAYER V2 ;
			RECT 0.021 73.5314 0.0359 73.5439 ;
		END

		ANTENNADIFFAREA 0.00194719 ;
		ANTENNAPARTIALMETALAREA 0.00195671 ;
	END Q[51]

	PIN Q[52]
		USE SIGNAL ;
		DIRECTION OUTPUT ;
		SHAPE ABUTMENT ;
		PORT
			 LAYER M2 ;
			RECT 0.0098 74.7984 0.0481 74.8988 ;
			 LAYER M3 ;
			RECT 0.0098 74.7984 0.0481 74.8988 ;
			 LAYER V2 ;
			RECT 0.021 74.8114 0.0359 74.8239 ;
		END

		ANTENNADIFFAREA 0.00194719 ;
		ANTENNAPARTIALMETALAREA 0.00195671 ;
	END Q[52]

	PIN Q[53]
		USE SIGNAL ;
		DIRECTION OUTPUT ;
		SHAPE ABUTMENT ;
		PORT
			 LAYER M2 ;
			RECT 0.0098 76.0784 0.0481 76.1788 ;
			 LAYER M3 ;
			RECT 0.0098 76.0784 0.0481 76.1788 ;
			 LAYER V2 ;
			RECT 0.021 76.0914 0.0359 76.1039 ;
		END

		ANTENNADIFFAREA 0.00194719 ;
		ANTENNAPARTIALMETALAREA 0.00195671 ;
	END Q[53]

	PIN Q[54]
		USE SIGNAL ;
		DIRECTION OUTPUT ;
		SHAPE ABUTMENT ;
		PORT
			 LAYER M2 ;
			RECT 0.0098 77.3584 0.0481 77.4588 ;
			 LAYER M3 ;
			RECT 0.0098 77.3584 0.0481 77.4588 ;
			 LAYER V2 ;
			RECT 0.021 77.3714 0.0359 77.3839 ;
		END

		ANTENNADIFFAREA 0.00194719 ;
		ANTENNAPARTIALMETALAREA 0.00195671 ;
	END Q[54]

	PIN Q[55]
		USE SIGNAL ;
		DIRECTION OUTPUT ;
		SHAPE ABUTMENT ;
		PORT
			 LAYER M2 ;
			RECT 0.0098 78.6384 0.0481 78.7388 ;
			 LAYER M3 ;
			RECT 0.0098 78.6384 0.0481 78.7388 ;
			 LAYER V2 ;
			RECT 0.021 78.6514 0.0359 78.6639 ;
		END

		ANTENNADIFFAREA 0.00194719 ;
		ANTENNAPARTIALMETALAREA 0.00195671 ;
	END Q[55]

	PIN Q[56]
		USE SIGNAL ;
		DIRECTION OUTPUT ;
		SHAPE ABUTMENT ;
		PORT
			 LAYER M2 ;
			RECT 0.0098 79.9184 0.0481 80.0188 ;
			 LAYER M3 ;
			RECT 0.0098 79.9184 0.0481 80.0188 ;
			 LAYER V2 ;
			RECT 0.021 79.9314 0.0359 79.9439 ;
		END

		ANTENNADIFFAREA 0.00194719 ;
		ANTENNAPARTIALMETALAREA 0.00195671 ;
	END Q[56]

	PIN Q[57]
		USE SIGNAL ;
		DIRECTION OUTPUT ;
		SHAPE ABUTMENT ;
		PORT
			 LAYER M2 ;
			RECT 0.0098 81.1984 0.0481 81.2988 ;
			 LAYER M3 ;
			RECT 0.0098 81.1984 0.0481 81.2988 ;
			 LAYER V2 ;
			RECT 0.021 81.2114 0.0359 81.2239 ;
		END

		ANTENNADIFFAREA 0.00194719 ;
		ANTENNAPARTIALMETALAREA 0.00195671 ;
	END Q[57]

	PIN Q[58]
		USE SIGNAL ;
		DIRECTION OUTPUT ;
		SHAPE ABUTMENT ;
		PORT
			 LAYER M2 ;
			RECT 0.0098 82.4784 0.0481 82.5788 ;
			 LAYER M3 ;
			RECT 0.0098 82.4784 0.0481 82.5788 ;
			 LAYER V2 ;
			RECT 0.021 82.4914 0.0359 82.5039 ;
		END

		ANTENNADIFFAREA 0.00194719 ;
		ANTENNAPARTIALMETALAREA 0.00195671 ;
	END Q[58]

	PIN Q[59]
		USE SIGNAL ;
		DIRECTION OUTPUT ;
		SHAPE ABUTMENT ;
		PORT
			 LAYER M2 ;
			RECT 0.0098 83.7584 0.0481 83.8588 ;
			 LAYER M3 ;
			RECT 0.0098 83.7584 0.0481 83.8588 ;
			 LAYER V2 ;
			RECT 0.021 83.7714 0.0359 83.7839 ;
		END

		ANTENNADIFFAREA 0.00194719 ;
		ANTENNAPARTIALMETALAREA 0.00195671 ;
	END Q[59]

	PIN Q[5]
		USE SIGNAL ;
		DIRECTION OUTPUT ;
		SHAPE ABUTMENT ;
		PORT
			 LAYER M2 ;
			RECT 0.0098 7.4918 0.0481 7.5922 ;
			 LAYER M3 ;
			RECT 0.0098 7.4918 0.0481 7.5922 ;
			 LAYER V2 ;
			RECT 0.021 7.5667 0.0359 7.5792 ;
		END

		ANTENNADIFFAREA 0.00194719 ;
		ANTENNAPARTIALMETALAREA 0.00195671 ;
	END Q[5]

	PIN Q[60]
		USE SIGNAL ;
		DIRECTION OUTPUT ;
		SHAPE ABUTMENT ;
		PORT
			 LAYER M2 ;
			RECT 0.0098 85.0384 0.0481 85.1388 ;
			 LAYER M3 ;
			RECT 0.0098 85.0384 0.0481 85.1388 ;
			 LAYER V2 ;
			RECT 0.021 85.0514 0.0359 85.0639 ;
		END

		ANTENNADIFFAREA 0.00194719 ;
		ANTENNAPARTIALMETALAREA 0.00195671 ;
	END Q[60]

	PIN Q[61]
		USE SIGNAL ;
		DIRECTION OUTPUT ;
		SHAPE ABUTMENT ;
		PORT
			 LAYER M2 ;
			RECT 0.0098 86.3184 0.0481 86.4188 ;
			 LAYER M3 ;
			RECT 0.0098 86.3184 0.0481 86.4188 ;
			 LAYER V2 ;
			RECT 0.021 86.3314 0.0359 86.3439 ;
		END

		ANTENNADIFFAREA 0.00194719 ;
		ANTENNAPARTIALMETALAREA 0.00195671 ;
	END Q[61]

	PIN Q[62]
		USE SIGNAL ;
		DIRECTION OUTPUT ;
		SHAPE ABUTMENT ;
		PORT
			 LAYER M2 ;
			RECT 0.0098 87.5984 0.0481 87.6988 ;
			 LAYER M3 ;
			RECT 0.0098 87.5984 0.0481 87.6988 ;
			 LAYER V2 ;
			RECT 0.021 87.6114 0.0359 87.6239 ;
		END

		ANTENNADIFFAREA 0.00194719 ;
		ANTENNAPARTIALMETALAREA 0.00195671 ;
	END Q[62]

	PIN Q[63]
		USE SIGNAL ;
		DIRECTION OUTPUT ;
		SHAPE ABUTMENT ;
		PORT
			 LAYER M2 ;
			RECT 0.0098 88.8784 0.0481 88.9788 ;
			 LAYER M3 ;
			RECT 0.0098 88.8784 0.0481 88.9788 ;
			 LAYER V2 ;
			RECT 0.021 88.8914 0.0359 88.9039 ;
		END

		ANTENNADIFFAREA 0.00194719 ;
		ANTENNAPARTIALMETALAREA 0.00195671 ;
	END Q[63]

	PIN Q[64]
		USE SIGNAL ;
		DIRECTION OUTPUT ;
		SHAPE ABUTMENT ;
		PORT
			 LAYER M2 ;
			RECT 0.0098 90.1584 0.0481 90.2588 ;
			 LAYER M3 ;
			RECT 0.0098 90.1584 0.0481 90.2588 ;
			 LAYER V2 ;
			RECT 0.021 90.1714 0.0359 90.1839 ;
		END

		ANTENNADIFFAREA 0.00194719 ;
		ANTENNAPARTIALMETALAREA 0.00195671 ;
	END Q[64]

	PIN Q[65]
		USE SIGNAL ;
		DIRECTION OUTPUT ;
		SHAPE ABUTMENT ;
		PORT
			 LAYER M2 ;
			RECT 0.0098 91.4384 0.0481 91.5388 ;
			 LAYER M3 ;
			RECT 0.0098 91.4384 0.0481 91.5388 ;
			 LAYER V2 ;
			RECT 0.021 91.4514 0.0359 91.4639 ;
		END

		ANTENNADIFFAREA 0.00194719 ;
		ANTENNAPARTIALMETALAREA 0.00195671 ;
	END Q[65]

	PIN Q[6]
		USE SIGNAL ;
		DIRECTION OUTPUT ;
		SHAPE ABUTMENT ;
		PORT
			 LAYER M2 ;
			RECT 0.0098 8.7718 0.0481 8.8722 ;
			 LAYER M3 ;
			RECT 0.0098 8.7718 0.0481 8.8722 ;
			 LAYER V2 ;
			RECT 0.021 8.8467 0.0359 8.8592 ;
		END

		ANTENNADIFFAREA 0.00194719 ;
		ANTENNAPARTIALMETALAREA 0.00195671 ;
	END Q[6]

	PIN Q[7]
		USE SIGNAL ;
		DIRECTION OUTPUT ;
		SHAPE ABUTMENT ;
		PORT
			 LAYER M2 ;
			RECT 0.0098 10.0518 0.0481 10.1522 ;
			 LAYER M3 ;
			RECT 0.0098 10.0518 0.0481 10.1522 ;
			 LAYER V2 ;
			RECT 0.021 10.1267 0.0359 10.1392 ;
		END

		ANTENNADIFFAREA 0.00194719 ;
		ANTENNAPARTIALMETALAREA 0.00195671 ;
	END Q[7]

	PIN Q[8]
		USE SIGNAL ;
		DIRECTION OUTPUT ;
		SHAPE ABUTMENT ;
		PORT
			 LAYER M2 ;
			RECT 0.0098 11.3318 0.0481 11.4322 ;
			 LAYER M3 ;
			RECT 0.0098 11.3318 0.0481 11.4322 ;
			 LAYER V2 ;
			RECT 0.021 11.4067 0.0359 11.4192 ;
		END

		ANTENNADIFFAREA 0.00194719 ;
		ANTENNAPARTIALMETALAREA 0.00195671 ;
	END Q[8]

	PIN Q[9]
		USE SIGNAL ;
		DIRECTION OUTPUT ;
		SHAPE ABUTMENT ;
		PORT
			 LAYER M2 ;
			RECT 0.0098 12.6118 0.0481 12.7122 ;
			 LAYER M3 ;
			RECT 0.0098 12.6118 0.0481 12.7122 ;
			 LAYER V2 ;
			RECT 0.021 12.6867 0.0359 12.6992 ;
		END

		ANTENNADIFFAREA 0.00194719 ;
		ANTENNAPARTIALMETALAREA 0.00195671 ;
	END Q[9]

	PIN RAWL
		USE SIGNAL ;
		DIRECTION INPUT ;
		SHAPE ABUTMENT ;
		PORT
			 LAYER M2 ;
			RECT 0.0714 42.9302 0.1097 42.9678 ;
			 LAYER M3 ;
			RECT 0.0714 42.9302 0.1097 43.0306 ;
			 LAYER V2 ;
			RECT 0.0831 42.9424 0.098 42.9549 ;
		END

		ANTENNAGATEAREA 0.00027817 ;
		ANTENNADIFFAREA 0.00194719 ;
		ANTENNAPARTIALMETALAREA 0.00195671 ;
	END RAWL

	PIN RAWLM[0]
		USE SIGNAL ;
		DIRECTION INPUT ;
		SHAPE ABUTMENT ;
		PORT
			 LAYER M2 ;
			RECT 0.0098 46.6949 0.0481 46.7325 ;
		END

		ANTENNAGATEAREA 0.00027817 ;
		ANTENNADIFFAREA 0.00194719 ;
		ANTENNAPARTIALMETALAREA 0.00195671 ;
	END RAWLM[0]

	PIN RAWLM[1]
		USE SIGNAL ;
		DIRECTION INPUT ;
		SHAPE ABUTMENT ;
		PORT
			 LAYER M3 ;
			RECT 0.0714 47.5984 0.1097 47.6988 ;
		END

		ANTENNAGATEAREA 0.00027817 ;
		ANTENNADIFFAREA 0.00194719 ;
		ANTENNAPARTIALMETALAREA 0.00195671 ;
	END RAWLM[1]

	PIN RET1N
		USE SIGNAL ;
		DIRECTION INPUT ;
		SHAPE ABUTMENT ;
		PORT
			 LAYER M2 ;
			RECT 0.0098 44.4988 0.0481 44.5365 ;
			 LAYER M3 ;
			RECT 0.0098 44.4361 0.0481 44.5365 ;
			 LAYER V2 ;
			RECT 0.0215 44.511 0.0364 44.5235 ;
		END

		ANTENNAGATEAREA 0.00027817 ;
		ANTENNADIFFAREA 0.00194719 ;
		ANTENNAPARTIALMETALAREA 0.00195671 ;
	END RET1N

	PIN SE
		USE SIGNAL ;
		DIRECTION INPUT ;
		SHAPE ABUTMENT ;
		PORT
			 LAYER M3 ;
			RECT 0.0714 47.749 0.1097 47.8494 ;
		END

		ANTENNAGATEAREA 0.00027817 ;
		ANTENNADIFFAREA 0.00194719 ;
		ANTENNAPARTIALMETALAREA 0.00195671 ;
	END SE

	PIN SI[0]
		USE SIGNAL ;
		DIRECTION INPUT ;
		SHAPE ABUTMENT ;
		PORT
			 LAYER M2 ;
			RECT 0.0714 0.0627 0.1097 0.1004 ;
			 LAYER M3 ;
			RECT 0.0714 0.0627 0.1097 0.1631 ;
			 LAYER V2 ;
			RECT 0.0831 0.0749 0.098 0.0875 ;
		END

		ANTENNAGATEAREA 0.00027817 ;
		ANTENNADIFFAREA 0.00194719 ;
		ANTENNAPARTIALMETALAREA 0.00195671 ;
	END SI[0]

	PIN SI[1]
		USE SIGNAL ;
		DIRECTION INPUT ;
		SHAPE ABUTMENT ;
		PORT
			 LAYER M2 ;
			RECT 0.0714 92.5302 0.1097 92.5678 ;
			 LAYER M3 ;
			RECT 0.0714 92.4675 0.1097 92.5678 ;
			 LAYER V2 ;
			RECT 0.0831 92.5431 0.098 92.5557 ;
		END

		ANTENNAGATEAREA 0.00027817 ;
		ANTENNADIFFAREA 0.00194719 ;
		ANTENNAPARTIALMETALAREA 0.00195671 ;
	END SI[1]

	PIN SO[0]
		USE SIGNAL ;
		DIRECTION OUTPUT ;
		SHAPE ABUTMENT ;
		PORT
			 LAYER M2 ;
			RECT 0.0714 48.502 0.1097 48.5396 ;
			 LAYER M3 ;
			RECT 0.0714 48.502 0.1097 48.6024 ;
			 LAYER V2 ;
			RECT 0.0831 48.5141 0.098 48.5267 ;
		END

		ANTENNADIFFAREA 0.00194719 ;
		ANTENNAPARTIALMETALAREA 0.00195671 ;
	END SO[0]

	PIN SO[1]
		USE SIGNAL ;
		DIRECTION OUTPUT ;
		SHAPE ABUTMENT ;
		PORT
			 LAYER M2 ;
			RECT 0.0714 46.5443 0.1097 46.582 ;
			 LAYER M3 ;
			RECT 0.0714 46.5443 0.1097 46.6447 ;
			 LAYER V2 ;
			RECT 0.0831 46.5565 0.098 46.569 ;
		END

		ANTENNADIFFAREA 0.00194719 ;
		ANTENNAPARTIALMETALAREA 0.00195671 ;
	END SO[1]

	PIN STOV
		USE SIGNAL ;
		DIRECTION INPUT ;
		SHAPE ABUTMENT ;
		PORT
			 LAYER M2 ;
			RECT 0.0098 44.9506 0.0481 44.9882 ;
			 LAYER M3 ;
			RECT 0.0098 44.8878 0.0481 44.9882 ;
			 LAYER V2 ;
			RECT 0.0215 44.9627 0.0364 44.9753 ;
		END

		ANTENNAGATEAREA 0.00027817 ;
		ANTENNADIFFAREA 0.00194719 ;
		ANTENNAPARTIALMETALAREA 0.00195671 ;
	END STOV

	PIN TA[0]
		USE SIGNAL ;
		DIRECTION INPUT ;
		SHAPE ABUTMENT ;
		PORT
			 LAYER M2 ;
			RECT 0.0098 45.7035 0.0481 45.7412 ;
			 LAYER M3 ;
			RECT 0.0098 45.6408 0.0481 45.7412 ;
			 LAYER V2 ;
			RECT 0.0215 45.7157 0.0364 45.7282 ;
		END

		ANTENNAGATEAREA 0.00027817 ;
		ANTENNADIFFAREA 0.00194719 ;
		ANTENNAPARTIALMETALAREA 0.00195671 ;
	END TA[0]

	PIN TA[1]
		USE SIGNAL ;
		DIRECTION INPUT ;
		SHAPE ABUTMENT ;
		PORT
			 LAYER M2 ;
			RECT 0.0714 45.942 0.1097 45.9796 ;
			 LAYER M3 ;
			RECT 0.0714 45.942 0.1097 46.0424 ;
			 LAYER V2 ;
			RECT 0.0831 45.9541 0.098 45.9667 ;
		END

		ANTENNAGATEAREA 0.00027817 ;
		ANTENNADIFFAREA 0.00194719 ;
		ANTENNAPARTIALMETALAREA 0.00195671 ;
	END TA[1]

	PIN TA[2]
		USE SIGNAL ;
		DIRECTION INPUT ;
		SHAPE ABUTMENT ;
		PORT
			 LAYER M2 ;
			RECT 0.0098 46.3059 0.0481 46.3435 ;
			 LAYER M3 ;
			RECT 0.0098 46.2431 0.0481 46.3435 ;
			 LAYER V2 ;
			RECT 0.0215 46.318 0.0364 46.3306 ;
		END

		ANTENNAGATEAREA 0.00027817 ;
		ANTENNADIFFAREA 0.00194719 ;
		ANTENNAPARTIALMETALAREA 0.00195671 ;
	END TA[2]

	PIN TA[3]
		USE SIGNAL ;
		DIRECTION INPUT ;
		SHAPE ABUTMENT ;
		PORT
			 LAYER M2 ;
			RECT 0.0714 46.9961 0.1097 47.0337 ;
			 LAYER M3 ;
			RECT 0.0714 46.9961 0.1097 47.0965 ;
			 LAYER V2 ;
			RECT 0.0831 47.0082 0.098 47.0208 ;
		END

		ANTENNAGATEAREA 0.00027817 ;
		ANTENNADIFFAREA 0.00194719 ;
		ANTENNAPARTIALMETALAREA 0.00195671 ;
	END TA[3]

	PIN TA[4]
		USE SIGNAL ;
		DIRECTION INPUT ;
		SHAPE ABUTMENT ;
		PORT
			 LAYER M2 ;
			RECT 0.0098 46.1553 0.0481 46.1929 ;
			 LAYER M3 ;
			RECT 0.0098 46.0925 0.0481 46.1929 ;
			 LAYER V2 ;
			RECT 0.0215 46.1675 0.0364 46.18 ;
		END

		ANTENNAGATEAREA 0.00027817 ;
		ANTENNADIFFAREA 0.00194719 ;
		ANTENNAPARTIALMETALAREA 0.00195671 ;
	END TA[4]

	PIN TA[5]
		USE SIGNAL ;
		DIRECTION INPUT ;
		SHAPE ABUTMENT ;
		PORT
			 LAYER M2 ;
			RECT 0.0098 47.2973 0.0481 47.3349 ;
		END

		ANTENNAGATEAREA 0.00027817 ;
		ANTENNADIFFAREA 0.00194719 ;
		ANTENNAPARTIALMETALAREA 0.00195671 ;
	END TA[5]

	PIN TA[6]
		USE SIGNAL ;
		DIRECTION INPUT ;
		SHAPE ABUTMENT ;
		PORT
			 LAYER M2 ;
			RECT 0.0098 47.749 0.0481 47.7867 ;
		END

		ANTENNAGATEAREA 0.00027817 ;
		ANTENNADIFFAREA 0.00194719 ;
		ANTENNAPARTIALMETALAREA 0.00195671 ;
	END TA[6]

	PIN TA[7]
		USE SIGNAL ;
		DIRECTION INPUT ;
		SHAPE ABUTMENT ;
		PORT
			 LAYER M2 ;
			RECT 0.0098 48.5647 0.0481 48.6024 ;
			 LAYER M3 ;
			RECT 0.0098 48.502 0.0481 48.6024 ;
			 LAYER V2 ;
			RECT 0.0215 48.5769 0.0364 48.5894 ;
		END

		ANTENNAGATEAREA 0.00027817 ;
		ANTENNADIFFAREA 0.00194719 ;
		ANTENNAPARTIALMETALAREA 0.00195671 ;
	END TA[7]

	PIN TA[8]
		USE SIGNAL ;
		DIRECTION INPUT ;
		SHAPE ABUTMENT ;
		PORT
			 LAYER M2 ;
			RECT 0.0714 48.0502 0.1097 48.0878 ;
			 LAYER M3 ;
			RECT 0.0714 48.0502 0.1097 48.1506 ;
			 LAYER V2 ;
			RECT 0.0831 48.0624 0.098 48.0749 ;
		END

		ANTENNAGATEAREA 0.00027817 ;
		ANTENNADIFFAREA 0.00194719 ;
		ANTENNAPARTIALMETALAREA 0.00195671 ;
	END TA[8]

	PIN TA[9]
		USE SIGNAL ;
		DIRECTION INPUT ;
		SHAPE ABUTMENT ;
		PORT
			 LAYER M2 ;
			RECT 0.0714 49.1043 0.1097 49.142 ;
			 LAYER M3 ;
			RECT 0.0714 49.1043 0.1097 49.2047 ;
			 LAYER V2 ;
			RECT 0.0831 49.1165 0.098 49.129 ;
		END

		ANTENNAGATEAREA 0.00027817 ;
		ANTENNADIFFAREA 0.00194719 ;
		ANTENNAPARTIALMETALAREA 0.00195671 ;
	END TA[9]

	PIN TCEN
		USE SIGNAL ;
		DIRECTION INPUT ;
		SHAPE ABUTMENT ;
		PORT
			 LAYER M2 ;
			RECT 0.0098 45.1012 0.0481 45.1388 ;
			 LAYER M3 ;
			RECT 0.0098 45.0384 0.0481 45.1388 ;
			 LAYER V2 ;
			RECT 0.0215 45.1133 0.0364 45.1259 ;
		END

		ANTENNAGATEAREA 0.00027817 ;
		ANTENNADIFFAREA 0.00194719 ;
		ANTENNAPARTIALMETALAREA 0.00195671 ;
	END TCEN

	PIN TD[0]
		USE SIGNAL ;
		DIRECTION INPUT ;
		SHAPE ABUTMENT ;
		PORT
			 LAYER M2 ;
			RECT 0.0098 0.9663 0.0481 1.0039 ;
			 LAYER M3 ;
			RECT 0.0098 0.9663 0.0481 1.0667 ;
			 LAYER V2 ;
			RECT 0.0215 0.9792 0.0364 0.9918 ;
		END

		ANTENNAGATEAREA 0.00027817 ;
		ANTENNADIFFAREA 0.00194719 ;
		ANTENNAPARTIALMETALAREA 0.00195671 ;
	END TD[0]

	PIN TD[10]
		USE SIGNAL ;
		DIRECTION INPUT ;
		SHAPE ABUTMENT ;
		PORT
			 LAYER M2 ;
			RECT 0.0098 13.7663 0.0481 13.8039 ;
			 LAYER M3 ;
			RECT 0.0098 13.7663 0.0481 13.8667 ;
			 LAYER V2 ;
			RECT 0.0215 13.7792 0.0364 13.7918 ;
		END

		ANTENNAGATEAREA 0.00027817 ;
		ANTENNADIFFAREA 0.00194719 ;
		ANTENNAPARTIALMETALAREA 0.00195671 ;
	END TD[10]

	PIN TD[11]
		USE SIGNAL ;
		DIRECTION INPUT ;
		SHAPE ABUTMENT ;
		PORT
			 LAYER M2 ;
			RECT 0.0098 15.0463 0.0481 15.0839 ;
			 LAYER M3 ;
			RECT 0.0098 15.0463 0.0481 15.1467 ;
			 LAYER V2 ;
			RECT 0.0215 15.0592 0.0364 15.0718 ;
		END

		ANTENNAGATEAREA 0.00027817 ;
		ANTENNADIFFAREA 0.00194719 ;
		ANTENNAPARTIALMETALAREA 0.00195671 ;
	END TD[11]

	PIN TD[12]
		USE SIGNAL ;
		DIRECTION INPUT ;
		SHAPE ABUTMENT ;
		PORT
			 LAYER M2 ;
			RECT 0.0098 16.3263 0.0481 16.3639 ;
			 LAYER M3 ;
			RECT 0.0098 16.3263 0.0481 16.4267 ;
			 LAYER V2 ;
			RECT 0.0215 16.3392 0.0364 16.3518 ;
		END

		ANTENNAGATEAREA 0.00027817 ;
		ANTENNADIFFAREA 0.00194719 ;
		ANTENNAPARTIALMETALAREA 0.00195671 ;
	END TD[12]

	PIN TD[13]
		USE SIGNAL ;
		DIRECTION INPUT ;
		SHAPE ABUTMENT ;
		PORT
			 LAYER M2 ;
			RECT 0.0098 17.6063 0.0481 17.6439 ;
			 LAYER M3 ;
			RECT 0.0098 17.6063 0.0481 17.7067 ;
			 LAYER V2 ;
			RECT 0.0215 17.6192 0.0364 17.6318 ;
		END

		ANTENNAGATEAREA 0.00027817 ;
		ANTENNADIFFAREA 0.00194719 ;
		ANTENNAPARTIALMETALAREA 0.00195671 ;
	END TD[13]

	PIN TD[14]
		USE SIGNAL ;
		DIRECTION INPUT ;
		SHAPE ABUTMENT ;
		PORT
			 LAYER M2 ;
			RECT 0.0098 18.8863 0.0481 18.9239 ;
			 LAYER M3 ;
			RECT 0.0098 18.8863 0.0481 18.9867 ;
			 LAYER V2 ;
			RECT 0.0215 18.8992 0.0364 18.9118 ;
		END

		ANTENNAGATEAREA 0.00027817 ;
		ANTENNADIFFAREA 0.00194719 ;
		ANTENNAPARTIALMETALAREA 0.00195671 ;
	END TD[14]

	PIN TD[15]
		USE SIGNAL ;
		DIRECTION INPUT ;
		SHAPE ABUTMENT ;
		PORT
			 LAYER M2 ;
			RECT 0.0098 20.1663 0.0481 20.2039 ;
			 LAYER M3 ;
			RECT 0.0098 20.1663 0.0481 20.2667 ;
			 LAYER V2 ;
			RECT 0.0215 20.1792 0.0364 20.1918 ;
		END

		ANTENNAGATEAREA 0.00027817 ;
		ANTENNADIFFAREA 0.00194719 ;
		ANTENNAPARTIALMETALAREA 0.00195671 ;
	END TD[15]

	PIN TD[16]
		USE SIGNAL ;
		DIRECTION INPUT ;
		SHAPE ABUTMENT ;
		PORT
			 LAYER M2 ;
			RECT 0.0098 21.4463 0.0481 21.4839 ;
			 LAYER M3 ;
			RECT 0.0098 21.4463 0.0481 21.5467 ;
			 LAYER V2 ;
			RECT 0.0215 21.4592 0.0364 21.4718 ;
		END

		ANTENNAGATEAREA 0.00027817 ;
		ANTENNADIFFAREA 0.00194719 ;
		ANTENNAPARTIALMETALAREA 0.00195671 ;
	END TD[16]

	PIN TD[17]
		USE SIGNAL ;
		DIRECTION INPUT ;
		SHAPE ABUTMENT ;
		PORT
			 LAYER M2 ;
			RECT 0.0098 22.7263 0.0481 22.7639 ;
			 LAYER M3 ;
			RECT 0.0098 22.7263 0.0481 22.8267 ;
			 LAYER V2 ;
			RECT 0.0215 22.7392 0.0364 22.7518 ;
		END

		ANTENNAGATEAREA 0.00027817 ;
		ANTENNADIFFAREA 0.00194719 ;
		ANTENNAPARTIALMETALAREA 0.00195671 ;
	END TD[17]

	PIN TD[18]
		USE SIGNAL ;
		DIRECTION INPUT ;
		SHAPE ABUTMENT ;
		PORT
			 LAYER M2 ;
			RECT 0.0098 24.0063 0.0481 24.0439 ;
			 LAYER M3 ;
			RECT 0.0098 24.0063 0.0481 24.1067 ;
			 LAYER V2 ;
			RECT 0.0215 24.0192 0.0364 24.0318 ;
		END

		ANTENNAGATEAREA 0.00027817 ;
		ANTENNADIFFAREA 0.00194719 ;
		ANTENNAPARTIALMETALAREA 0.00195671 ;
	END TD[18]

	PIN TD[19]
		USE SIGNAL ;
		DIRECTION INPUT ;
		SHAPE ABUTMENT ;
		PORT
			 LAYER M2 ;
			RECT 0.0098 25.2863 0.0481 25.3239 ;
			 LAYER M3 ;
			RECT 0.0098 25.2863 0.0481 25.3867 ;
			 LAYER V2 ;
			RECT 0.0215 25.2992 0.0364 25.3118 ;
		END

		ANTENNAGATEAREA 0.00027817 ;
		ANTENNADIFFAREA 0.00194719 ;
		ANTENNAPARTIALMETALAREA 0.00195671 ;
	END TD[19]

	PIN TD[1]
		USE SIGNAL ;
		DIRECTION INPUT ;
		SHAPE ABUTMENT ;
		PORT
			 LAYER M2 ;
			RECT 0.0098 2.2463 0.0481 2.2839 ;
			 LAYER M3 ;
			RECT 0.0098 2.2463 0.0481 2.3467 ;
			 LAYER V2 ;
			RECT 0.0215 2.2592 0.0364 2.2718 ;
		END

		ANTENNAGATEAREA 0.00027817 ;
		ANTENNADIFFAREA 0.00194719 ;
		ANTENNAPARTIALMETALAREA 0.00195671 ;
	END TD[1]

	PIN TD[20]
		USE SIGNAL ;
		DIRECTION INPUT ;
		SHAPE ABUTMENT ;
		PORT
			 LAYER M2 ;
			RECT 0.0098 26.5663 0.0481 26.6039 ;
			 LAYER M3 ;
			RECT 0.0098 26.5663 0.0481 26.6667 ;
			 LAYER V2 ;
			RECT 0.0215 26.5792 0.0364 26.5918 ;
		END

		ANTENNAGATEAREA 0.00027817 ;
		ANTENNADIFFAREA 0.00194719 ;
		ANTENNAPARTIALMETALAREA 0.00195671 ;
	END TD[20]

	PIN TD[21]
		USE SIGNAL ;
		DIRECTION INPUT ;
		SHAPE ABUTMENT ;
		PORT
			 LAYER M2 ;
			RECT 0.0098 27.8463 0.0481 27.8839 ;
			 LAYER M3 ;
			RECT 0.0098 27.8463 0.0481 27.9467 ;
			 LAYER V2 ;
			RECT 0.0215 27.8592 0.0364 27.8718 ;
		END

		ANTENNAGATEAREA 0.00027817 ;
		ANTENNADIFFAREA 0.00194719 ;
		ANTENNAPARTIALMETALAREA 0.00195671 ;
	END TD[21]

	PIN TD[22]
		USE SIGNAL ;
		DIRECTION INPUT ;
		SHAPE ABUTMENT ;
		PORT
			 LAYER M2 ;
			RECT 0.0098 29.1263 0.0481 29.1639 ;
			 LAYER M3 ;
			RECT 0.0098 29.1263 0.0481 29.2267 ;
			 LAYER V2 ;
			RECT 0.0215 29.1392 0.0364 29.1518 ;
		END

		ANTENNAGATEAREA 0.00027817 ;
		ANTENNADIFFAREA 0.00194719 ;
		ANTENNAPARTIALMETALAREA 0.00195671 ;
	END TD[22]

	PIN TD[23]
		USE SIGNAL ;
		DIRECTION INPUT ;
		SHAPE ABUTMENT ;
		PORT
			 LAYER M2 ;
			RECT 0.0098 30.4063 0.0481 30.4439 ;
			 LAYER M3 ;
			RECT 0.0098 30.4063 0.0481 30.5067 ;
			 LAYER V2 ;
			RECT 0.0215 30.4192 0.0364 30.4318 ;
		END

		ANTENNAGATEAREA 0.00027817 ;
		ANTENNADIFFAREA 0.00194719 ;
		ANTENNAPARTIALMETALAREA 0.00195671 ;
	END TD[23]

	PIN TD[24]
		USE SIGNAL ;
		DIRECTION INPUT ;
		SHAPE ABUTMENT ;
		PORT
			 LAYER M2 ;
			RECT 0.0098 31.6863 0.0481 31.7239 ;
			 LAYER M3 ;
			RECT 0.0098 31.6863 0.0481 31.7867 ;
			 LAYER V2 ;
			RECT 0.0215 31.6992 0.0364 31.7118 ;
		END

		ANTENNAGATEAREA 0.00027817 ;
		ANTENNADIFFAREA 0.00194719 ;
		ANTENNAPARTIALMETALAREA 0.00195671 ;
	END TD[24]

	PIN TD[25]
		USE SIGNAL ;
		DIRECTION INPUT ;
		SHAPE ABUTMENT ;
		PORT
			 LAYER M2 ;
			RECT 0.0098 32.9663 0.0481 33.0039 ;
			 LAYER M3 ;
			RECT 0.0098 32.9663 0.0481 33.0667 ;
			 LAYER V2 ;
			RECT 0.0215 32.9792 0.0364 32.9918 ;
		END

		ANTENNAGATEAREA 0.00027817 ;
		ANTENNADIFFAREA 0.00194719 ;
		ANTENNAPARTIALMETALAREA 0.00195671 ;
	END TD[25]

	PIN TD[26]
		USE SIGNAL ;
		DIRECTION INPUT ;
		SHAPE ABUTMENT ;
		PORT
			 LAYER M2 ;
			RECT 0.0098 34.2463 0.0481 34.2839 ;
			 LAYER M3 ;
			RECT 0.0098 34.2463 0.0481 34.3467 ;
			 LAYER V2 ;
			RECT 0.0215 34.2592 0.0364 34.2718 ;
		END

		ANTENNAGATEAREA 0.00027817 ;
		ANTENNADIFFAREA 0.00194719 ;
		ANTENNAPARTIALMETALAREA 0.00195671 ;
	END TD[26]

	PIN TD[27]
		USE SIGNAL ;
		DIRECTION INPUT ;
		SHAPE ABUTMENT ;
		PORT
			 LAYER M2 ;
			RECT 0.0098 35.5263 0.0481 35.5639 ;
			 LAYER M3 ;
			RECT 0.0098 35.5263 0.0481 35.6267 ;
			 LAYER V2 ;
			RECT 0.0215 35.5392 0.0364 35.5518 ;
		END

		ANTENNAGATEAREA 0.00027817 ;
		ANTENNADIFFAREA 0.00194719 ;
		ANTENNAPARTIALMETALAREA 0.00195671 ;
	END TD[27]

	PIN TD[28]
		USE SIGNAL ;
		DIRECTION INPUT ;
		SHAPE ABUTMENT ;
		PORT
			 LAYER M2 ;
			RECT 0.0098 36.8063 0.0481 36.8439 ;
			 LAYER M3 ;
			RECT 0.0098 36.8063 0.0481 36.9067 ;
			 LAYER V2 ;
			RECT 0.0215 36.8192 0.0364 36.8318 ;
		END

		ANTENNAGATEAREA 0.00027817 ;
		ANTENNADIFFAREA 0.00194719 ;
		ANTENNAPARTIALMETALAREA 0.00195671 ;
	END TD[28]

	PIN TD[29]
		USE SIGNAL ;
		DIRECTION INPUT ;
		SHAPE ABUTMENT ;
		PORT
			 LAYER M2 ;
			RECT 0.0098 38.0863 0.0481 38.1239 ;
			 LAYER M3 ;
			RECT 0.0098 38.0863 0.0481 38.1867 ;
			 LAYER V2 ;
			RECT 0.0215 38.0992 0.0364 38.1118 ;
		END

		ANTENNAGATEAREA 0.00027817 ;
		ANTENNADIFFAREA 0.00194719 ;
		ANTENNAPARTIALMETALAREA 0.00195671 ;
	END TD[29]

	PIN TD[2]
		USE SIGNAL ;
		DIRECTION INPUT ;
		SHAPE ABUTMENT ;
		PORT
			 LAYER M2 ;
			RECT 0.0098 3.5263 0.0481 3.5639 ;
			 LAYER M3 ;
			RECT 0.0098 3.5263 0.0481 3.6267 ;
			 LAYER V2 ;
			RECT 0.0215 3.5392 0.0364 3.5518 ;
		END

		ANTENNAGATEAREA 0.00027817 ;
		ANTENNADIFFAREA 0.00194719 ;
		ANTENNAPARTIALMETALAREA 0.00195671 ;
	END TD[2]

	PIN TD[30]
		USE SIGNAL ;
		DIRECTION INPUT ;
		SHAPE ABUTMENT ;
		PORT
			 LAYER M2 ;
			RECT 0.0098 39.3663 0.0481 39.4039 ;
			 LAYER M3 ;
			RECT 0.0098 39.3663 0.0481 39.4667 ;
			 LAYER V2 ;
			RECT 0.0215 39.3792 0.0364 39.3918 ;
		END

		ANTENNAGATEAREA 0.00027817 ;
		ANTENNADIFFAREA 0.00194719 ;
		ANTENNAPARTIALMETALAREA 0.00195671 ;
	END TD[30]

	PIN TD[31]
		USE SIGNAL ;
		DIRECTION INPUT ;
		SHAPE ABUTMENT ;
		PORT
			 LAYER M2 ;
			RECT 0.0098 40.6463 0.0481 40.6839 ;
			 LAYER M3 ;
			RECT 0.0098 40.6463 0.0481 40.7467 ;
			 LAYER V2 ;
			RECT 0.0215 40.6592 0.0364 40.6718 ;
		END

		ANTENNAGATEAREA 0.00027817 ;
		ANTENNADIFFAREA 0.00194719 ;
		ANTENNAPARTIALMETALAREA 0.00195671 ;
	END TD[31]

	PIN TD[32]
		USE SIGNAL ;
		DIRECTION INPUT ;
		SHAPE ABUTMENT ;
		PORT
			 LAYER M2 ;
			RECT 0.0098 41.9263 0.0481 41.9639 ;
			 LAYER M3 ;
			RECT 0.0098 41.9263 0.0481 42.0267 ;
			 LAYER V2 ;
			RECT 0.0215 41.9392 0.0364 41.9518 ;
		END

		ANTENNAGATEAREA 0.00027817 ;
		ANTENNADIFFAREA 0.00194719 ;
		ANTENNAPARTIALMETALAREA 0.00195671 ;
	END TD[32]

	PIN TD[33]
		USE SIGNAL ;
		DIRECTION INPUT ;
		SHAPE ABUTMENT ;
		PORT
			 LAYER M2 ;
			RECT 0.0098 50.6667 0.0481 50.7043 ;
			 LAYER M3 ;
			RECT 0.0098 50.6039 0.0481 50.7043 ;
			 LAYER V2 ;
			RECT 0.0215 50.6788 0.0364 50.6914 ;
		END

		ANTENNAGATEAREA 0.00027817 ;
		ANTENNADIFFAREA 0.00194719 ;
		ANTENNAPARTIALMETALAREA 0.00195671 ;
	END TD[33]

	PIN TD[34]
		USE SIGNAL ;
		DIRECTION INPUT ;
		SHAPE ABUTMENT ;
		PORT
			 LAYER M2 ;
			RECT 0.0098 51.9467 0.0481 51.9843 ;
			 LAYER M3 ;
			RECT 0.0098 51.8839 0.0481 51.9843 ;
			 LAYER V2 ;
			RECT 0.0215 51.9588 0.0364 51.9714 ;
		END

		ANTENNAGATEAREA 0.00027817 ;
		ANTENNADIFFAREA 0.00194719 ;
		ANTENNAPARTIALMETALAREA 0.00195671 ;
	END TD[34]

	PIN TD[35]
		USE SIGNAL ;
		DIRECTION INPUT ;
		SHAPE ABUTMENT ;
		PORT
			 LAYER M2 ;
			RECT 0.0098 53.2267 0.0481 53.2643 ;
			 LAYER M3 ;
			RECT 0.0098 53.1639 0.0481 53.2643 ;
			 LAYER V2 ;
			RECT 0.0215 53.2388 0.0364 53.2514 ;
		END

		ANTENNAGATEAREA 0.00027817 ;
		ANTENNADIFFAREA 0.00194719 ;
		ANTENNAPARTIALMETALAREA 0.00195671 ;
	END TD[35]

	PIN TD[36]
		USE SIGNAL ;
		DIRECTION INPUT ;
		SHAPE ABUTMENT ;
		PORT
			 LAYER M2 ;
			RECT 0.0098 54.5067 0.0481 54.5443 ;
			 LAYER M3 ;
			RECT 0.0098 54.4439 0.0481 54.5443 ;
			 LAYER V2 ;
			RECT 0.0215 54.5188 0.0364 54.5314 ;
		END

		ANTENNAGATEAREA 0.00027817 ;
		ANTENNADIFFAREA 0.00194719 ;
		ANTENNAPARTIALMETALAREA 0.00195671 ;
	END TD[36]

	PIN TD[37]
		USE SIGNAL ;
		DIRECTION INPUT ;
		SHAPE ABUTMENT ;
		PORT
			 LAYER M2 ;
			RECT 0.0098 55.7867 0.0481 55.8243 ;
			 LAYER M3 ;
			RECT 0.0098 55.7239 0.0481 55.8243 ;
			 LAYER V2 ;
			RECT 0.0215 55.7988 0.0364 55.8114 ;
		END

		ANTENNAGATEAREA 0.00027817 ;
		ANTENNADIFFAREA 0.00194719 ;
		ANTENNAPARTIALMETALAREA 0.00195671 ;
	END TD[37]

	PIN TD[38]
		USE SIGNAL ;
		DIRECTION INPUT ;
		SHAPE ABUTMENT ;
		PORT
			 LAYER M2 ;
			RECT 0.0098 57.0667 0.0481 57.1043 ;
			 LAYER M3 ;
			RECT 0.0098 57.0039 0.0481 57.1043 ;
			 LAYER V2 ;
			RECT 0.0215 57.0788 0.0364 57.0914 ;
		END

		ANTENNAGATEAREA 0.00027817 ;
		ANTENNADIFFAREA 0.00194719 ;
		ANTENNAPARTIALMETALAREA 0.00195671 ;
	END TD[38]

	PIN TD[39]
		USE SIGNAL ;
		DIRECTION INPUT ;
		SHAPE ABUTMENT ;
		PORT
			 LAYER M2 ;
			RECT 0.0098 58.3467 0.0481 58.3843 ;
			 LAYER M3 ;
			RECT 0.0098 58.2839 0.0481 58.3843 ;
			 LAYER V2 ;
			RECT 0.0215 58.3588 0.0364 58.3714 ;
		END

		ANTENNAGATEAREA 0.00027817 ;
		ANTENNADIFFAREA 0.00194719 ;
		ANTENNAPARTIALMETALAREA 0.00195671 ;
	END TD[39]

	PIN TD[3]
		USE SIGNAL ;
		DIRECTION INPUT ;
		SHAPE ABUTMENT ;
		PORT
			 LAYER M2 ;
			RECT 0.0098 4.8063 0.0481 4.8439 ;
			 LAYER M3 ;
			RECT 0.0098 4.8063 0.0481 4.9067 ;
			 LAYER V2 ;
			RECT 0.0215 4.8192 0.0364 4.8318 ;
		END

		ANTENNAGATEAREA 0.00027817 ;
		ANTENNADIFFAREA 0.00194719 ;
		ANTENNAPARTIALMETALAREA 0.00195671 ;
	END TD[3]

	PIN TD[40]
		USE SIGNAL ;
		DIRECTION INPUT ;
		SHAPE ABUTMENT ;
		PORT
			 LAYER M2 ;
			RECT 0.0098 59.6267 0.0481 59.6643 ;
			 LAYER M3 ;
			RECT 0.0098 59.5639 0.0481 59.6643 ;
			 LAYER V2 ;
			RECT 0.0215 59.6388 0.0364 59.6514 ;
		END

		ANTENNAGATEAREA 0.00027817 ;
		ANTENNADIFFAREA 0.00194719 ;
		ANTENNAPARTIALMETALAREA 0.00195671 ;
	END TD[40]

	PIN TD[41]
		USE SIGNAL ;
		DIRECTION INPUT ;
		SHAPE ABUTMENT ;
		PORT
			 LAYER M2 ;
			RECT 0.0098 60.9067 0.0481 60.9443 ;
			 LAYER M3 ;
			RECT 0.0098 60.8439 0.0481 60.9443 ;
			 LAYER V2 ;
			RECT 0.0215 60.9188 0.0364 60.9314 ;
		END

		ANTENNAGATEAREA 0.00027817 ;
		ANTENNADIFFAREA 0.00194719 ;
		ANTENNAPARTIALMETALAREA 0.00195671 ;
	END TD[41]

	PIN TD[42]
		USE SIGNAL ;
		DIRECTION INPUT ;
		SHAPE ABUTMENT ;
		PORT
			 LAYER M2 ;
			RECT 0.0098 62.1867 0.0481 62.2243 ;
			 LAYER M3 ;
			RECT 0.0098 62.1239 0.0481 62.2243 ;
			 LAYER V2 ;
			RECT 0.0215 62.1988 0.0364 62.2114 ;
		END

		ANTENNAGATEAREA 0.00027817 ;
		ANTENNADIFFAREA 0.00194719 ;
		ANTENNAPARTIALMETALAREA 0.00195671 ;
	END TD[42]

	PIN TD[43]
		USE SIGNAL ;
		DIRECTION INPUT ;
		SHAPE ABUTMENT ;
		PORT
			 LAYER M2 ;
			RECT 0.0098 63.4667 0.0481 63.5043 ;
			 LAYER M3 ;
			RECT 0.0098 63.4039 0.0481 63.5043 ;
			 LAYER V2 ;
			RECT 0.0215 63.4788 0.0364 63.4914 ;
		END

		ANTENNAGATEAREA 0.00027817 ;
		ANTENNADIFFAREA 0.00194719 ;
		ANTENNAPARTIALMETALAREA 0.00195671 ;
	END TD[43]

	PIN TD[44]
		USE SIGNAL ;
		DIRECTION INPUT ;
		SHAPE ABUTMENT ;
		PORT
			 LAYER M2 ;
			RECT 0.0098 64.7467 0.0481 64.7843 ;
			 LAYER M3 ;
			RECT 0.0098 64.6839 0.0481 64.7843 ;
			 LAYER V2 ;
			RECT 0.0215 64.7588 0.0364 64.7714 ;
		END

		ANTENNAGATEAREA 0.00027817 ;
		ANTENNADIFFAREA 0.00194719 ;
		ANTENNAPARTIALMETALAREA 0.00195671 ;
	END TD[44]

	PIN TD[45]
		USE SIGNAL ;
		DIRECTION INPUT ;
		SHAPE ABUTMENT ;
		PORT
			 LAYER M2 ;
			RECT 0.0098 66.0267 0.0481 66.0643 ;
			 LAYER M3 ;
			RECT 0.0098 65.9639 0.0481 66.0643 ;
			 LAYER V2 ;
			RECT 0.0215 66.0388 0.0364 66.0514 ;
		END

		ANTENNAGATEAREA 0.00027817 ;
		ANTENNADIFFAREA 0.00194719 ;
		ANTENNAPARTIALMETALAREA 0.00195671 ;
	END TD[45]

	PIN TD[46]
		USE SIGNAL ;
		DIRECTION INPUT ;
		SHAPE ABUTMENT ;
		PORT
			 LAYER M2 ;
			RECT 0.0098 67.3067 0.0481 67.3443 ;
			 LAYER M3 ;
			RECT 0.0098 67.2439 0.0481 67.3443 ;
			 LAYER V2 ;
			RECT 0.0215 67.3188 0.0364 67.3314 ;
		END

		ANTENNAGATEAREA 0.00027817 ;
		ANTENNADIFFAREA 0.00194719 ;
		ANTENNAPARTIALMETALAREA 0.00195671 ;
	END TD[46]

	PIN TD[47]
		USE SIGNAL ;
		DIRECTION INPUT ;
		SHAPE ABUTMENT ;
		PORT
			 LAYER M2 ;
			RECT 0.0098 68.5867 0.0481 68.6243 ;
			 LAYER M3 ;
			RECT 0.0098 68.5239 0.0481 68.6243 ;
			 LAYER V2 ;
			RECT 0.0215 68.5988 0.0364 68.6114 ;
		END

		ANTENNAGATEAREA 0.00027817 ;
		ANTENNADIFFAREA 0.00194719 ;
		ANTENNAPARTIALMETALAREA 0.00195671 ;
	END TD[47]

	PIN TD[48]
		USE SIGNAL ;
		DIRECTION INPUT ;
		SHAPE ABUTMENT ;
		PORT
			 LAYER M2 ;
			RECT 0.0098 69.8667 0.0481 69.9043 ;
			 LAYER M3 ;
			RECT 0.0098 69.8039 0.0481 69.9043 ;
			 LAYER V2 ;
			RECT 0.0215 69.8788 0.0364 69.8914 ;
		END

		ANTENNAGATEAREA 0.00027817 ;
		ANTENNADIFFAREA 0.00194719 ;
		ANTENNAPARTIALMETALAREA 0.00195671 ;
	END TD[48]

	PIN TD[49]
		USE SIGNAL ;
		DIRECTION INPUT ;
		SHAPE ABUTMENT ;
		PORT
			 LAYER M2 ;
			RECT 0.0098 71.1467 0.0481 71.1843 ;
			 LAYER M3 ;
			RECT 0.0098 71.0839 0.0481 71.1843 ;
			 LAYER V2 ;
			RECT 0.0215 71.1588 0.0364 71.1714 ;
		END

		ANTENNAGATEAREA 0.00027817 ;
		ANTENNADIFFAREA 0.00194719 ;
		ANTENNAPARTIALMETALAREA 0.00195671 ;
	END TD[49]

	PIN TD[4]
		USE SIGNAL ;
		DIRECTION INPUT ;
		SHAPE ABUTMENT ;
		PORT
			 LAYER M2 ;
			RECT 0.0098 6.0863 0.0481 6.1239 ;
			 LAYER M3 ;
			RECT 0.0098 6.0863 0.0481 6.1867 ;
			 LAYER V2 ;
			RECT 0.0215 6.0992 0.0364 6.1118 ;
		END

		ANTENNAGATEAREA 0.00027817 ;
		ANTENNADIFFAREA 0.00194719 ;
		ANTENNAPARTIALMETALAREA 0.00195671 ;
	END TD[4]

	PIN TD[50]
		USE SIGNAL ;
		DIRECTION INPUT ;
		SHAPE ABUTMENT ;
		PORT
			 LAYER M2 ;
			RECT 0.0098 72.4267 0.0481 72.4643 ;
			 LAYER M3 ;
			RECT 0.0098 72.3639 0.0481 72.4643 ;
			 LAYER V2 ;
			RECT 0.0215 72.4388 0.0364 72.4514 ;
		END

		ANTENNAGATEAREA 0.00027817 ;
		ANTENNADIFFAREA 0.00194719 ;
		ANTENNAPARTIALMETALAREA 0.00195671 ;
	END TD[50]

	PIN TD[51]
		USE SIGNAL ;
		DIRECTION INPUT ;
		SHAPE ABUTMENT ;
		PORT
			 LAYER M2 ;
			RECT 0.0098 73.7067 0.0481 73.7443 ;
			 LAYER M3 ;
			RECT 0.0098 73.6439 0.0481 73.7443 ;
			 LAYER V2 ;
			RECT 0.0215 73.7188 0.0364 73.7314 ;
		END

		ANTENNAGATEAREA 0.00027817 ;
		ANTENNADIFFAREA 0.00194719 ;
		ANTENNAPARTIALMETALAREA 0.00195671 ;
	END TD[51]

	PIN TD[52]
		USE SIGNAL ;
		DIRECTION INPUT ;
		SHAPE ABUTMENT ;
		PORT
			 LAYER M2 ;
			RECT 0.0098 74.9867 0.0481 75.0243 ;
			 LAYER M3 ;
			RECT 0.0098 74.9239 0.0481 75.0243 ;
			 LAYER V2 ;
			RECT 0.0215 74.9988 0.0364 75.0114 ;
		END

		ANTENNAGATEAREA 0.00027817 ;
		ANTENNADIFFAREA 0.00194719 ;
		ANTENNAPARTIALMETALAREA 0.00195671 ;
	END TD[52]

	PIN TD[53]
		USE SIGNAL ;
		DIRECTION INPUT ;
		SHAPE ABUTMENT ;
		PORT
			 LAYER M2 ;
			RECT 0.0098 76.2667 0.0481 76.3043 ;
			 LAYER M3 ;
			RECT 0.0098 76.2039 0.0481 76.3043 ;
			 LAYER V2 ;
			RECT 0.0215 76.2788 0.0364 76.2914 ;
		END

		ANTENNAGATEAREA 0.00027817 ;
		ANTENNADIFFAREA 0.00194719 ;
		ANTENNAPARTIALMETALAREA 0.00195671 ;
	END TD[53]

	PIN TD[54]
		USE SIGNAL ;
		DIRECTION INPUT ;
		SHAPE ABUTMENT ;
		PORT
			 LAYER M2 ;
			RECT 0.0098 77.5467 0.0481 77.5843 ;
			 LAYER M3 ;
			RECT 0.0098 77.4839 0.0481 77.5843 ;
			 LAYER V2 ;
			RECT 0.0215 77.5588 0.0364 77.5714 ;
		END

		ANTENNAGATEAREA 0.00027817 ;
		ANTENNADIFFAREA 0.00194719 ;
		ANTENNAPARTIALMETALAREA 0.00195671 ;
	END TD[54]

	PIN TD[55]
		USE SIGNAL ;
		DIRECTION INPUT ;
		SHAPE ABUTMENT ;
		PORT
			 LAYER M2 ;
			RECT 0.0098 78.8267 0.0481 78.8643 ;
			 LAYER M3 ;
			RECT 0.0098 78.7639 0.0481 78.8643 ;
			 LAYER V2 ;
			RECT 0.0215 78.8388 0.0364 78.8514 ;
		END

		ANTENNAGATEAREA 0.00027817 ;
		ANTENNADIFFAREA 0.00194719 ;
		ANTENNAPARTIALMETALAREA 0.00195671 ;
	END TD[55]

	PIN TD[56]
		USE SIGNAL ;
		DIRECTION INPUT ;
		SHAPE ABUTMENT ;
		PORT
			 LAYER M2 ;
			RECT 0.0098 80.1067 0.0481 80.1443 ;
			 LAYER M3 ;
			RECT 0.0098 80.0439 0.0481 80.1443 ;
			 LAYER V2 ;
			RECT 0.0215 80.1188 0.0364 80.1314 ;
		END

		ANTENNAGATEAREA 0.00027817 ;
		ANTENNADIFFAREA 0.00194719 ;
		ANTENNAPARTIALMETALAREA 0.00195671 ;
	END TD[56]

	PIN TD[57]
		USE SIGNAL ;
		DIRECTION INPUT ;
		SHAPE ABUTMENT ;
		PORT
			 LAYER M2 ;
			RECT 0.0098 81.3867 0.0481 81.4243 ;
			 LAYER M3 ;
			RECT 0.0098 81.3239 0.0481 81.4243 ;
			 LAYER V2 ;
			RECT 0.0215 81.3988 0.0364 81.4114 ;
		END

		ANTENNAGATEAREA 0.00027817 ;
		ANTENNADIFFAREA 0.00194719 ;
		ANTENNAPARTIALMETALAREA 0.00195671 ;
	END TD[57]

	PIN TD[58]
		USE SIGNAL ;
		DIRECTION INPUT ;
		SHAPE ABUTMENT ;
		PORT
			 LAYER M2 ;
			RECT 0.0098 82.6667 0.0481 82.7043 ;
			 LAYER M3 ;
			RECT 0.0098 82.6039 0.0481 82.7043 ;
			 LAYER V2 ;
			RECT 0.0215 82.6788 0.0364 82.6914 ;
		END

		ANTENNAGATEAREA 0.00027817 ;
		ANTENNADIFFAREA 0.00194719 ;
		ANTENNAPARTIALMETALAREA 0.00195671 ;
	END TD[58]

	PIN TD[59]
		USE SIGNAL ;
		DIRECTION INPUT ;
		SHAPE ABUTMENT ;
		PORT
			 LAYER M2 ;
			RECT 0.0098 83.9467 0.0481 83.9843 ;
			 LAYER M3 ;
			RECT 0.0098 83.8839 0.0481 83.9843 ;
			 LAYER V2 ;
			RECT 0.0215 83.9588 0.0364 83.9714 ;
		END

		ANTENNAGATEAREA 0.00027817 ;
		ANTENNADIFFAREA 0.00194719 ;
		ANTENNAPARTIALMETALAREA 0.00195671 ;
	END TD[59]

	PIN TD[5]
		USE SIGNAL ;
		DIRECTION INPUT ;
		SHAPE ABUTMENT ;
		PORT
			 LAYER M2 ;
			RECT 0.0098 7.3663 0.0481 7.4039 ;
			 LAYER M3 ;
			RECT 0.0098 7.3663 0.0481 7.4667 ;
			 LAYER V2 ;
			RECT 0.0215 7.3792 0.0364 7.3918 ;
		END

		ANTENNAGATEAREA 0.00027817 ;
		ANTENNADIFFAREA 0.00194719 ;
		ANTENNAPARTIALMETALAREA 0.00195671 ;
	END TD[5]

	PIN TD[60]
		USE SIGNAL ;
		DIRECTION INPUT ;
		SHAPE ABUTMENT ;
		PORT
			 LAYER M2 ;
			RECT 0.0098 85.2267 0.0481 85.2643 ;
			 LAYER M3 ;
			RECT 0.0098 85.1639 0.0481 85.2643 ;
			 LAYER V2 ;
			RECT 0.0215 85.2388 0.0364 85.2514 ;
		END

		ANTENNAGATEAREA 0.00027817 ;
		ANTENNADIFFAREA 0.00194719 ;
		ANTENNAPARTIALMETALAREA 0.00195671 ;
	END TD[60]

	PIN TD[61]
		USE SIGNAL ;
		DIRECTION INPUT ;
		SHAPE ABUTMENT ;
		PORT
			 LAYER M2 ;
			RECT 0.0098 86.5067 0.0481 86.5443 ;
			 LAYER M3 ;
			RECT 0.0098 86.4439 0.0481 86.5443 ;
			 LAYER V2 ;
			RECT 0.0215 86.5188 0.0364 86.5314 ;
		END

		ANTENNAGATEAREA 0.00027817 ;
		ANTENNADIFFAREA 0.00194719 ;
		ANTENNAPARTIALMETALAREA 0.00195671 ;
	END TD[61]

	PIN TD[62]
		USE SIGNAL ;
		DIRECTION INPUT ;
		SHAPE ABUTMENT ;
		PORT
			 LAYER M2 ;
			RECT 0.0098 87.7867 0.0481 87.8243 ;
			 LAYER M3 ;
			RECT 0.0098 87.7239 0.0481 87.8243 ;
			 LAYER V2 ;
			RECT 0.0215 87.7988 0.0364 87.8114 ;
		END

		ANTENNAGATEAREA 0.00027817 ;
		ANTENNADIFFAREA 0.00194719 ;
		ANTENNAPARTIALMETALAREA 0.00195671 ;
	END TD[62]

	PIN TD[63]
		USE SIGNAL ;
		DIRECTION INPUT ;
		SHAPE ABUTMENT ;
		PORT
			 LAYER M2 ;
			RECT 0.0098 89.0667 0.0481 89.1043 ;
			 LAYER M3 ;
			RECT 0.0098 89.0039 0.0481 89.1043 ;
			 LAYER V2 ;
			RECT 0.0215 89.0788 0.0364 89.0914 ;
		END

		ANTENNAGATEAREA 0.00027817 ;
		ANTENNADIFFAREA 0.00194719 ;
		ANTENNAPARTIALMETALAREA 0.00195671 ;
	END TD[63]

	PIN TD[64]
		USE SIGNAL ;
		DIRECTION INPUT ;
		SHAPE ABUTMENT ;
		PORT
			 LAYER M2 ;
			RECT 0.0098 90.3467 0.0481 90.3843 ;
			 LAYER M3 ;
			RECT 0.0098 90.2839 0.0481 90.3843 ;
			 LAYER V2 ;
			RECT 0.0215 90.3588 0.0364 90.3714 ;
		END

		ANTENNAGATEAREA 0.00027817 ;
		ANTENNADIFFAREA 0.00194719 ;
		ANTENNAPARTIALMETALAREA 0.00195671 ;
	END TD[64]

	PIN TD[65]
		USE SIGNAL ;
		DIRECTION INPUT ;
		SHAPE ABUTMENT ;
		PORT
			 LAYER M2 ;
			RECT 0.0098 91.6267 0.0481 91.6643 ;
			 LAYER M3 ;
			RECT 0.0098 91.5639 0.0481 91.6643 ;
			 LAYER V2 ;
			RECT 0.0215 91.6388 0.0364 91.6514 ;
		END

		ANTENNAGATEAREA 0.00027817 ;
		ANTENNADIFFAREA 0.00194719 ;
		ANTENNAPARTIALMETALAREA 0.00195671 ;
	END TD[65]

	PIN TD[6]
		USE SIGNAL ;
		DIRECTION INPUT ;
		SHAPE ABUTMENT ;
		PORT
			 LAYER M2 ;
			RECT 0.0098 8.6463 0.0481 8.6839 ;
			 LAYER M3 ;
			RECT 0.0098 8.6463 0.0481 8.7467 ;
			 LAYER V2 ;
			RECT 0.0215 8.6592 0.0364 8.6718 ;
		END

		ANTENNAGATEAREA 0.00027817 ;
		ANTENNADIFFAREA 0.00194719 ;
		ANTENNAPARTIALMETALAREA 0.00195671 ;
	END TD[6]

	PIN TD[7]
		USE SIGNAL ;
		DIRECTION INPUT ;
		SHAPE ABUTMENT ;
		PORT
			 LAYER M2 ;
			RECT 0.0098 9.9263 0.0481 9.9639 ;
			 LAYER M3 ;
			RECT 0.0098 9.9263 0.0481 10.0267 ;
			 LAYER V2 ;
			RECT 0.0215 9.9392 0.0364 9.9518 ;
		END

		ANTENNAGATEAREA 0.00027817 ;
		ANTENNADIFFAREA 0.00194719 ;
		ANTENNAPARTIALMETALAREA 0.00195671 ;
	END TD[7]

	PIN TD[8]
		USE SIGNAL ;
		DIRECTION INPUT ;
		SHAPE ABUTMENT ;
		PORT
			 LAYER M2 ;
			RECT 0.0098 11.2063 0.0481 11.2439 ;
			 LAYER M3 ;
			RECT 0.0098 11.2063 0.0481 11.3067 ;
			 LAYER V2 ;
			RECT 0.0215 11.2192 0.0364 11.2318 ;
		END

		ANTENNAGATEAREA 0.00027817 ;
		ANTENNADIFFAREA 0.00194719 ;
		ANTENNAPARTIALMETALAREA 0.00195671 ;
	END TD[8]

	PIN TD[9]
		USE SIGNAL ;
		DIRECTION INPUT ;
		SHAPE ABUTMENT ;
		PORT
			 LAYER M2 ;
			RECT 0.0098 12.4863 0.0481 12.5239 ;
			 LAYER M3 ;
			RECT 0.0098 12.4863 0.0481 12.5867 ;
			 LAYER V2 ;
			RECT 0.0215 12.4992 0.0364 12.5118 ;
		END

		ANTENNAGATEAREA 0.00027817 ;
		ANTENNADIFFAREA 0.00194719 ;
		ANTENNAPARTIALMETALAREA 0.00195671 ;
	END TD[9]

	PIN TEN
		USE SIGNAL ;
		DIRECTION INPUT ;
		SHAPE ABUTMENT ;
		PORT
			 LAYER M2 ;
			RECT 0.0098 44.0471 0.0481 44.0847 ;
			 LAYER M3 ;
			RECT 0.0098 43.9843 0.0481 44.0847 ;
			 LAYER V2 ;
			RECT 0.0215 44.0592 0.0364 44.0718 ;
		END

		ANTENNAGATEAREA 0.00027817 ;
		ANTENNADIFFAREA 0.00194719 ;
		ANTENNAPARTIALMETALAREA 0.00195671 ;
	END TEN

	PIN TGWEN
		USE SIGNAL ;
		DIRECTION INPUT ;
		SHAPE ABUTMENT ;
		PORT
			 LAYER M2 ;
			RECT 0.0714 45.189 0.1097 45.2267 ;
			 LAYER M3 ;
			RECT 0.0714 45.189 0.1097 45.2894 ;
			 LAYER V2 ;
			RECT 0.0831 45.2012 0.098 45.2137 ;
		END

		ANTENNAGATEAREA 0.00027817 ;
		ANTENNADIFFAREA 0.00194719 ;
		ANTENNAPARTIALMETALAREA 0.00195671 ;
	END TGWEN

	PIN TWEN[0]
		USE SIGNAL ;
		DIRECTION INPUT ;
		SHAPE ABUTMENT ;
		PORT
			 LAYER M2 ;
			RECT 0.0714 1.4306 0.1097 1.4682 ;
			 LAYER M3 ;
			RECT 0.0714 1.3678 0.1097 1.4682 ;
			 LAYER V2 ;
			RECT 0.0831 1.4435 0.098 1.4561 ;
		END

		ANTENNAGATEAREA 0.00027817 ;
		ANTENNADIFFAREA 0.00194719 ;
		ANTENNAPARTIALMETALAREA 0.00195671 ;
	END TWEN[0]

	PIN TWEN[10]
		USE SIGNAL ;
		DIRECTION INPUT ;
		SHAPE ABUTMENT ;
		PORT
			 LAYER M2 ;
			RECT 0.0714 14.2306 0.1097 14.2682 ;
			 LAYER M3 ;
			RECT 0.0714 14.1678 0.1097 14.2682 ;
			 LAYER V2 ;
			RECT 0.0831 14.2435 0.098 14.2561 ;
		END

		ANTENNAGATEAREA 0.00027817 ;
		ANTENNADIFFAREA 0.00194719 ;
		ANTENNAPARTIALMETALAREA 0.00195671 ;
	END TWEN[10]

	PIN TWEN[11]
		USE SIGNAL ;
		DIRECTION INPUT ;
		SHAPE ABUTMENT ;
		PORT
			 LAYER M2 ;
			RECT 0.0714 15.5106 0.1097 15.5482 ;
			 LAYER M3 ;
			RECT 0.0714 15.4478 0.1097 15.5482 ;
			 LAYER V2 ;
			RECT 0.0831 15.5235 0.098 15.5361 ;
		END

		ANTENNAGATEAREA 0.00027817 ;
		ANTENNADIFFAREA 0.00194719 ;
		ANTENNAPARTIALMETALAREA 0.00195671 ;
	END TWEN[11]

	PIN TWEN[12]
		USE SIGNAL ;
		DIRECTION INPUT ;
		SHAPE ABUTMENT ;
		PORT
			 LAYER M2 ;
			RECT 0.0714 16.7906 0.1097 16.8282 ;
			 LAYER M3 ;
			RECT 0.0714 16.7278 0.1097 16.8282 ;
			 LAYER V2 ;
			RECT 0.0831 16.8035 0.098 16.8161 ;
		END

		ANTENNAGATEAREA 0.00027817 ;
		ANTENNADIFFAREA 0.00194719 ;
		ANTENNAPARTIALMETALAREA 0.00195671 ;
	END TWEN[12]

	PIN TWEN[13]
		USE SIGNAL ;
		DIRECTION INPUT ;
		SHAPE ABUTMENT ;
		PORT
			 LAYER M2 ;
			RECT 0.0714 18.0706 0.1097 18.1082 ;
			 LAYER M3 ;
			RECT 0.0714 18.0078 0.1097 18.1082 ;
			 LAYER V2 ;
			RECT 0.0831 18.0835 0.098 18.0961 ;
		END

		ANTENNAGATEAREA 0.00027817 ;
		ANTENNADIFFAREA 0.00194719 ;
		ANTENNAPARTIALMETALAREA 0.00195671 ;
	END TWEN[13]

	PIN TWEN[14]
		USE SIGNAL ;
		DIRECTION INPUT ;
		SHAPE ABUTMENT ;
		PORT
			 LAYER M2 ;
			RECT 0.0714 19.3506 0.1097 19.3882 ;
			 LAYER M3 ;
			RECT 0.0714 19.2878 0.1097 19.3882 ;
			 LAYER V2 ;
			RECT 0.0831 19.3635 0.098 19.3761 ;
		END

		ANTENNAGATEAREA 0.00027817 ;
		ANTENNADIFFAREA 0.00194719 ;
		ANTENNAPARTIALMETALAREA 0.00195671 ;
	END TWEN[14]

	PIN TWEN[15]
		USE SIGNAL ;
		DIRECTION INPUT ;
		SHAPE ABUTMENT ;
		PORT
			 LAYER M2 ;
			RECT 0.0714 20.6306 0.1097 20.6682 ;
			 LAYER M3 ;
			RECT 0.0714 20.5678 0.1097 20.6682 ;
			 LAYER V2 ;
			RECT 0.0831 20.6435 0.098 20.6561 ;
		END

		ANTENNAGATEAREA 0.00027817 ;
		ANTENNADIFFAREA 0.00194719 ;
		ANTENNAPARTIALMETALAREA 0.00195671 ;
	END TWEN[15]

	PIN TWEN[16]
		USE SIGNAL ;
		DIRECTION INPUT ;
		SHAPE ABUTMENT ;
		PORT
			 LAYER M2 ;
			RECT 0.0714 21.9106 0.1097 21.9482 ;
			 LAYER M3 ;
			RECT 0.0714 21.8478 0.1097 21.9482 ;
			 LAYER V2 ;
			RECT 0.0831 21.9235 0.098 21.9361 ;
		END

		ANTENNAGATEAREA 0.00027817 ;
		ANTENNADIFFAREA 0.00194719 ;
		ANTENNAPARTIALMETALAREA 0.00195671 ;
	END TWEN[16]

	PIN TWEN[17]
		USE SIGNAL ;
		DIRECTION INPUT ;
		SHAPE ABUTMENT ;
		PORT
			 LAYER M2 ;
			RECT 0.0714 23.1906 0.1097 23.2282 ;
			 LAYER M3 ;
			RECT 0.0714 23.1278 0.1097 23.2282 ;
			 LAYER V2 ;
			RECT 0.0831 23.2035 0.098 23.2161 ;
		END

		ANTENNAGATEAREA 0.00027817 ;
		ANTENNADIFFAREA 0.00194719 ;
		ANTENNAPARTIALMETALAREA 0.00195671 ;
	END TWEN[17]

	PIN TWEN[18]
		USE SIGNAL ;
		DIRECTION INPUT ;
		SHAPE ABUTMENT ;
		PORT
			 LAYER M2 ;
			RECT 0.0714 24.4706 0.1097 24.5082 ;
			 LAYER M3 ;
			RECT 0.0714 24.4078 0.1097 24.5082 ;
			 LAYER V2 ;
			RECT 0.0831 24.4835 0.098 24.4961 ;
		END

		ANTENNAGATEAREA 0.00027817 ;
		ANTENNADIFFAREA 0.00194719 ;
		ANTENNAPARTIALMETALAREA 0.00195671 ;
	END TWEN[18]

	PIN TWEN[19]
		USE SIGNAL ;
		DIRECTION INPUT ;
		SHAPE ABUTMENT ;
		PORT
			 LAYER M2 ;
			RECT 0.0714 25.7506 0.1097 25.7882 ;
			 LAYER M3 ;
			RECT 0.0714 25.6878 0.1097 25.7882 ;
			 LAYER V2 ;
			RECT 0.0831 25.7635 0.098 25.7761 ;
		END

		ANTENNAGATEAREA 0.00027817 ;
		ANTENNADIFFAREA 0.00194719 ;
		ANTENNAPARTIALMETALAREA 0.00195671 ;
	END TWEN[19]

	PIN TWEN[1]
		USE SIGNAL ;
		DIRECTION INPUT ;
		SHAPE ABUTMENT ;
		PORT
			 LAYER M2 ;
			RECT 0.0714 2.7106 0.1097 2.7482 ;
			 LAYER M3 ;
			RECT 0.0714 2.6478 0.1097 2.7482 ;
			 LAYER V2 ;
			RECT 0.0831 2.7235 0.098 2.7361 ;
		END

		ANTENNAGATEAREA 0.00027817 ;
		ANTENNADIFFAREA 0.00194719 ;
		ANTENNAPARTIALMETALAREA 0.00195671 ;
	END TWEN[1]

	PIN TWEN[20]
		USE SIGNAL ;
		DIRECTION INPUT ;
		SHAPE ABUTMENT ;
		PORT
			 LAYER M2 ;
			RECT 0.0714 27.0306 0.1097 27.0682 ;
			 LAYER M3 ;
			RECT 0.0714 26.9678 0.1097 27.0682 ;
			 LAYER V2 ;
			RECT 0.0831 27.0435 0.098 27.0561 ;
		END

		ANTENNAGATEAREA 0.00027817 ;
		ANTENNADIFFAREA 0.00194719 ;
		ANTENNAPARTIALMETALAREA 0.00195671 ;
	END TWEN[20]

	PIN TWEN[21]
		USE SIGNAL ;
		DIRECTION INPUT ;
		SHAPE ABUTMENT ;
		PORT
			 LAYER M2 ;
			RECT 0.0714 28.3106 0.1097 28.3482 ;
			 LAYER M3 ;
			RECT 0.0714 28.2478 0.1097 28.3482 ;
			 LAYER V2 ;
			RECT 0.0831 28.3235 0.098 28.3361 ;
		END

		ANTENNAGATEAREA 0.00027817 ;
		ANTENNADIFFAREA 0.00194719 ;
		ANTENNAPARTIALMETALAREA 0.00195671 ;
	END TWEN[21]

	PIN TWEN[22]
		USE SIGNAL ;
		DIRECTION INPUT ;
		SHAPE ABUTMENT ;
		PORT
			 LAYER M2 ;
			RECT 0.0714 29.5906 0.1097 29.6282 ;
			 LAYER M3 ;
			RECT 0.0714 29.5278 0.1097 29.6282 ;
			 LAYER V2 ;
			RECT 0.0831 29.6035 0.098 29.6161 ;
		END

		ANTENNAGATEAREA 0.00027817 ;
		ANTENNADIFFAREA 0.00194719 ;
		ANTENNAPARTIALMETALAREA 0.00195671 ;
	END TWEN[22]

	PIN TWEN[23]
		USE SIGNAL ;
		DIRECTION INPUT ;
		SHAPE ABUTMENT ;
		PORT
			 LAYER M2 ;
			RECT 0.0714 30.8706 0.1097 30.9082 ;
			 LAYER M3 ;
			RECT 0.0714 30.8078 0.1097 30.9082 ;
			 LAYER V2 ;
			RECT 0.0831 30.8835 0.098 30.8961 ;
		END

		ANTENNAGATEAREA 0.00027817 ;
		ANTENNADIFFAREA 0.00194719 ;
		ANTENNAPARTIALMETALAREA 0.00195671 ;
	END TWEN[23]

	PIN TWEN[24]
		USE SIGNAL ;
		DIRECTION INPUT ;
		SHAPE ABUTMENT ;
		PORT
			 LAYER M2 ;
			RECT 0.0714 32.1506 0.1097 32.1882 ;
			 LAYER M3 ;
			RECT 0.0714 32.0878 0.1097 32.1882 ;
			 LAYER V2 ;
			RECT 0.0831 32.1635 0.098 32.1761 ;
		END

		ANTENNAGATEAREA 0.00027817 ;
		ANTENNADIFFAREA 0.00194719 ;
		ANTENNAPARTIALMETALAREA 0.00195671 ;
	END TWEN[24]

	PIN TWEN[25]
		USE SIGNAL ;
		DIRECTION INPUT ;
		SHAPE ABUTMENT ;
		PORT
			 LAYER M2 ;
			RECT 0.0714 33.4306 0.1097 33.4682 ;
			 LAYER M3 ;
			RECT 0.0714 33.3678 0.1097 33.4682 ;
			 LAYER V2 ;
			RECT 0.0831 33.4435 0.098 33.4561 ;
		END

		ANTENNAGATEAREA 0.00027817 ;
		ANTENNADIFFAREA 0.00194719 ;
		ANTENNAPARTIALMETALAREA 0.00195671 ;
	END TWEN[25]

	PIN TWEN[26]
		USE SIGNAL ;
		DIRECTION INPUT ;
		SHAPE ABUTMENT ;
		PORT
			 LAYER M2 ;
			RECT 0.0714 34.7106 0.1097 34.7482 ;
			 LAYER M3 ;
			RECT 0.0714 34.6478 0.1097 34.7482 ;
			 LAYER V2 ;
			RECT 0.0831 34.7235 0.098 34.7361 ;
		END

		ANTENNAGATEAREA 0.00027817 ;
		ANTENNADIFFAREA 0.00194719 ;
		ANTENNAPARTIALMETALAREA 0.00195671 ;
	END TWEN[26]

	PIN TWEN[27]
		USE SIGNAL ;
		DIRECTION INPUT ;
		SHAPE ABUTMENT ;
		PORT
			 LAYER M2 ;
			RECT 0.0714 35.9906 0.1097 36.0282 ;
			 LAYER M3 ;
			RECT 0.0714 35.9278 0.1097 36.0282 ;
			 LAYER V2 ;
			RECT 0.0831 36.0035 0.098 36.0161 ;
		END

		ANTENNAGATEAREA 0.00027817 ;
		ANTENNADIFFAREA 0.00194719 ;
		ANTENNAPARTIALMETALAREA 0.00195671 ;
	END TWEN[27]

	PIN TWEN[28]
		USE SIGNAL ;
		DIRECTION INPUT ;
		SHAPE ABUTMENT ;
		PORT
			 LAYER M2 ;
			RECT 0.0714 37.2706 0.1097 37.3082 ;
			 LAYER M3 ;
			RECT 0.0714 37.2078 0.1097 37.3082 ;
			 LAYER V2 ;
			RECT 0.0831 37.2835 0.098 37.2961 ;
		END

		ANTENNAGATEAREA 0.00027817 ;
		ANTENNADIFFAREA 0.00194719 ;
		ANTENNAPARTIALMETALAREA 0.00195671 ;
	END TWEN[28]

	PIN TWEN[29]
		USE SIGNAL ;
		DIRECTION INPUT ;
		SHAPE ABUTMENT ;
		PORT
			 LAYER M2 ;
			RECT 0.0714 38.5506 0.1097 38.5882 ;
			 LAYER M3 ;
			RECT 0.0714 38.4878 0.1097 38.5882 ;
			 LAYER V2 ;
			RECT 0.0831 38.5635 0.098 38.5761 ;
		END

		ANTENNAGATEAREA 0.00027817 ;
		ANTENNADIFFAREA 0.00194719 ;
		ANTENNAPARTIALMETALAREA 0.00195671 ;
	END TWEN[29]

	PIN TWEN[2]
		USE SIGNAL ;
		DIRECTION INPUT ;
		SHAPE ABUTMENT ;
		PORT
			 LAYER M2 ;
			RECT 0.0714 3.9906 0.1097 4.0282 ;
			 LAYER M3 ;
			RECT 0.0714 3.9278 0.1097 4.0282 ;
			 LAYER V2 ;
			RECT 0.0831 4.0035 0.098 4.0161 ;
		END

		ANTENNAGATEAREA 0.00027817 ;
		ANTENNADIFFAREA 0.00194719 ;
		ANTENNAPARTIALMETALAREA 0.00195671 ;
	END TWEN[2]

	PIN TWEN[30]
		USE SIGNAL ;
		DIRECTION INPUT ;
		SHAPE ABUTMENT ;
		PORT
			 LAYER M2 ;
			RECT 0.0714 39.8306 0.1097 39.8682 ;
			 LAYER M3 ;
			RECT 0.0714 39.7678 0.1097 39.8682 ;
			 LAYER V2 ;
			RECT 0.0831 39.8435 0.098 39.8561 ;
		END

		ANTENNAGATEAREA 0.00027817 ;
		ANTENNADIFFAREA 0.00194719 ;
		ANTENNAPARTIALMETALAREA 0.00195671 ;
	END TWEN[30]

	PIN TWEN[31]
		USE SIGNAL ;
		DIRECTION INPUT ;
		SHAPE ABUTMENT ;
		PORT
			 LAYER M2 ;
			RECT 0.0714 41.1106 0.1097 41.1482 ;
			 LAYER M3 ;
			RECT 0.0714 41.0478 0.1097 41.1482 ;
			 LAYER V2 ;
			RECT 0.0831 41.1235 0.098 41.1361 ;
		END

		ANTENNAGATEAREA 0.00027817 ;
		ANTENNADIFFAREA 0.00194719 ;
		ANTENNAPARTIALMETALAREA 0.00195671 ;
	END TWEN[31]

	PIN TWEN[32]
		USE SIGNAL ;
		DIRECTION INPUT ;
		SHAPE ABUTMENT ;
		PORT
			 LAYER M2 ;
			RECT 0.0714 42.3906 0.1097 42.4282 ;
			 LAYER M3 ;
			RECT 0.0714 42.3278 0.1097 42.4282 ;
			 LAYER V2 ;
			RECT 0.0831 42.4035 0.098 42.4161 ;
		END

		ANTENNAGATEAREA 0.00027817 ;
		ANTENNADIFFAREA 0.00194719 ;
		ANTENNAPARTIALMETALAREA 0.00195671 ;
	END TWEN[32]

	PIN TWEN[33]
		USE SIGNAL ;
		DIRECTION INPUT ;
		SHAPE ABUTMENT ;
		PORT
			 LAYER M2 ;
			RECT 0.0714 50.2024 0.1097 50.24 ;
			 LAYER M3 ;
			RECT 0.0714 50.2024 0.1097 50.3027 ;
			 LAYER V2 ;
			RECT 0.0831 50.2145 0.098 50.2271 ;
		END

		ANTENNAGATEAREA 0.00027817 ;
		ANTENNADIFFAREA 0.00194719 ;
		ANTENNAPARTIALMETALAREA 0.00195671 ;
	END TWEN[33]

	PIN TWEN[34]
		USE SIGNAL ;
		DIRECTION INPUT ;
		SHAPE ABUTMENT ;
		PORT
			 LAYER M2 ;
			RECT 0.0714 51.4824 0.1097 51.52 ;
			 LAYER M3 ;
			RECT 0.0714 51.4824 0.1097 51.5827 ;
			 LAYER V2 ;
			RECT 0.0831 51.4945 0.098 51.5071 ;
		END

		ANTENNAGATEAREA 0.00027817 ;
		ANTENNADIFFAREA 0.00194719 ;
		ANTENNAPARTIALMETALAREA 0.00195671 ;
	END TWEN[34]

	PIN TWEN[35]
		USE SIGNAL ;
		DIRECTION INPUT ;
		SHAPE ABUTMENT ;
		PORT
			 LAYER M2 ;
			RECT 0.0714 52.7624 0.1097 52.8 ;
			 LAYER M3 ;
			RECT 0.0714 52.7624 0.1097 52.8627 ;
			 LAYER V2 ;
			RECT 0.0831 52.7745 0.098 52.7871 ;
		END

		ANTENNAGATEAREA 0.00027817 ;
		ANTENNADIFFAREA 0.00194719 ;
		ANTENNAPARTIALMETALAREA 0.00195671 ;
	END TWEN[35]

	PIN TWEN[36]
		USE SIGNAL ;
		DIRECTION INPUT ;
		SHAPE ABUTMENT ;
		PORT
			 LAYER M2 ;
			RECT 0.0714 54.0424 0.1097 54.08 ;
			 LAYER M3 ;
			RECT 0.0714 54.0424 0.1097 54.1427 ;
			 LAYER V2 ;
			RECT 0.0831 54.0545 0.098 54.0671 ;
		END

		ANTENNAGATEAREA 0.00027817 ;
		ANTENNADIFFAREA 0.00194719 ;
		ANTENNAPARTIALMETALAREA 0.00195671 ;
	END TWEN[36]

	PIN TWEN[37]
		USE SIGNAL ;
		DIRECTION INPUT ;
		SHAPE ABUTMENT ;
		PORT
			 LAYER M2 ;
			RECT 0.0714 55.3224 0.1097 55.36 ;
			 LAYER M3 ;
			RECT 0.0714 55.3224 0.1097 55.4227 ;
			 LAYER V2 ;
			RECT 0.0831 55.3345 0.098 55.3471 ;
		END

		ANTENNAGATEAREA 0.00027817 ;
		ANTENNADIFFAREA 0.00194719 ;
		ANTENNAPARTIALMETALAREA 0.00195671 ;
	END TWEN[37]

	PIN TWEN[38]
		USE SIGNAL ;
		DIRECTION INPUT ;
		SHAPE ABUTMENT ;
		PORT
			 LAYER M2 ;
			RECT 0.0714 56.6024 0.1097 56.64 ;
			 LAYER M3 ;
			RECT 0.0714 56.6024 0.1097 56.7027 ;
			 LAYER V2 ;
			RECT 0.0831 56.6145 0.098 56.6271 ;
		END

		ANTENNAGATEAREA 0.00027817 ;
		ANTENNADIFFAREA 0.00194719 ;
		ANTENNAPARTIALMETALAREA 0.00195671 ;
	END TWEN[38]

	PIN TWEN[39]
		USE SIGNAL ;
		DIRECTION INPUT ;
		SHAPE ABUTMENT ;
		PORT
			 LAYER M2 ;
			RECT 0.0714 57.8824 0.1097 57.92 ;
			 LAYER M3 ;
			RECT 0.0714 57.8824 0.1097 57.9827 ;
			 LAYER V2 ;
			RECT 0.0831 57.8945 0.098 57.9071 ;
		END

		ANTENNAGATEAREA 0.00027817 ;
		ANTENNADIFFAREA 0.00194719 ;
		ANTENNAPARTIALMETALAREA 0.00195671 ;
	END TWEN[39]

	PIN TWEN[3]
		USE SIGNAL ;
		DIRECTION INPUT ;
		SHAPE ABUTMENT ;
		PORT
			 LAYER M2 ;
			RECT 0.0714 5.2706 0.1097 5.3082 ;
			 LAYER M3 ;
			RECT 0.0714 5.2078 0.1097 5.3082 ;
			 LAYER V2 ;
			RECT 0.0831 5.2835 0.098 5.2961 ;
		END

		ANTENNAGATEAREA 0.00027817 ;
		ANTENNADIFFAREA 0.00194719 ;
		ANTENNAPARTIALMETALAREA 0.00195671 ;
	END TWEN[3]

	PIN TWEN[40]
		USE SIGNAL ;
		DIRECTION INPUT ;
		SHAPE ABUTMENT ;
		PORT
			 LAYER M2 ;
			RECT 0.0714 59.1624 0.1097 59.2 ;
			 LAYER M3 ;
			RECT 0.0714 59.1624 0.1097 59.2627 ;
			 LAYER V2 ;
			RECT 0.0831 59.1745 0.098 59.1871 ;
		END

		ANTENNAGATEAREA 0.00027817 ;
		ANTENNADIFFAREA 0.00194719 ;
		ANTENNAPARTIALMETALAREA 0.00195671 ;
	END TWEN[40]

	PIN TWEN[41]
		USE SIGNAL ;
		DIRECTION INPUT ;
		SHAPE ABUTMENT ;
		PORT
			 LAYER M2 ;
			RECT 0.0714 60.4424 0.1097 60.48 ;
			 LAYER M3 ;
			RECT 0.0714 60.4424 0.1097 60.5427 ;
			 LAYER V2 ;
			RECT 0.0831 60.4545 0.098 60.4671 ;
		END

		ANTENNAGATEAREA 0.00027817 ;
		ANTENNADIFFAREA 0.00194719 ;
		ANTENNAPARTIALMETALAREA 0.00195671 ;
	END TWEN[41]

	PIN TWEN[42]
		USE SIGNAL ;
		DIRECTION INPUT ;
		SHAPE ABUTMENT ;
		PORT
			 LAYER M2 ;
			RECT 0.0714 61.7224 0.1097 61.76 ;
			 LAYER M3 ;
			RECT 0.0714 61.7224 0.1097 61.8227 ;
			 LAYER V2 ;
			RECT 0.0831 61.7345 0.098 61.7471 ;
		END

		ANTENNAGATEAREA 0.00027817 ;
		ANTENNADIFFAREA 0.00194719 ;
		ANTENNAPARTIALMETALAREA 0.00195671 ;
	END TWEN[42]

	PIN TWEN[43]
		USE SIGNAL ;
		DIRECTION INPUT ;
		SHAPE ABUTMENT ;
		PORT
			 LAYER M2 ;
			RECT 0.0714 63.0024 0.1097 63.04 ;
			 LAYER M3 ;
			RECT 0.0714 63.0024 0.1097 63.1027 ;
			 LAYER V2 ;
			RECT 0.0831 63.0145 0.098 63.0271 ;
		END

		ANTENNAGATEAREA 0.00027817 ;
		ANTENNADIFFAREA 0.00194719 ;
		ANTENNAPARTIALMETALAREA 0.00195671 ;
	END TWEN[43]

	PIN TWEN[44]
		USE SIGNAL ;
		DIRECTION INPUT ;
		SHAPE ABUTMENT ;
		PORT
			 LAYER M2 ;
			RECT 0.0714 64.2824 0.1097 64.32 ;
			 LAYER M3 ;
			RECT 0.0714 64.2824 0.1097 64.3827 ;
			 LAYER V2 ;
			RECT 0.0831 64.2945 0.098 64.3071 ;
		END

		ANTENNAGATEAREA 0.00027817 ;
		ANTENNADIFFAREA 0.00194719 ;
		ANTENNAPARTIALMETALAREA 0.00195671 ;
	END TWEN[44]

	PIN TWEN[45]
		USE SIGNAL ;
		DIRECTION INPUT ;
		SHAPE ABUTMENT ;
		PORT
			 LAYER M2 ;
			RECT 0.0714 65.5624 0.1097 65.6 ;
			 LAYER M3 ;
			RECT 0.0714 65.5624 0.1097 65.6627 ;
			 LAYER V2 ;
			RECT 0.0831 65.5745 0.098 65.5871 ;
		END

		ANTENNAGATEAREA 0.00027817 ;
		ANTENNADIFFAREA 0.00194719 ;
		ANTENNAPARTIALMETALAREA 0.00195671 ;
	END TWEN[45]

	PIN TWEN[46]
		USE SIGNAL ;
		DIRECTION INPUT ;
		SHAPE ABUTMENT ;
		PORT
			 LAYER M2 ;
			RECT 0.0714 66.8424 0.1097 66.88 ;
			 LAYER M3 ;
			RECT 0.0714 66.8424 0.1097 66.9427 ;
			 LAYER V2 ;
			RECT 0.0831 66.8545 0.098 66.8671 ;
		END

		ANTENNAGATEAREA 0.00027817 ;
		ANTENNADIFFAREA 0.00194719 ;
		ANTENNAPARTIALMETALAREA 0.00195671 ;
	END TWEN[46]

	PIN TWEN[47]
		USE SIGNAL ;
		DIRECTION INPUT ;
		SHAPE ABUTMENT ;
		PORT
			 LAYER M2 ;
			RECT 0.0714 68.1224 0.1097 68.16 ;
			 LAYER M3 ;
			RECT 0.0714 68.1224 0.1097 68.2227 ;
			 LAYER V2 ;
			RECT 0.0831 68.1345 0.098 68.1471 ;
		END

		ANTENNAGATEAREA 0.00027817 ;
		ANTENNADIFFAREA 0.00194719 ;
		ANTENNAPARTIALMETALAREA 0.00195671 ;
	END TWEN[47]

	PIN TWEN[48]
		USE SIGNAL ;
		DIRECTION INPUT ;
		SHAPE ABUTMENT ;
		PORT
			 LAYER M2 ;
			RECT 0.0714 69.4024 0.1097 69.44 ;
			 LAYER M3 ;
			RECT 0.0714 69.4024 0.1097 69.5027 ;
			 LAYER V2 ;
			RECT 0.0831 69.4145 0.098 69.4271 ;
		END

		ANTENNAGATEAREA 0.00027817 ;
		ANTENNADIFFAREA 0.00194719 ;
		ANTENNAPARTIALMETALAREA 0.00195671 ;
	END TWEN[48]

	PIN TWEN[49]
		USE SIGNAL ;
		DIRECTION INPUT ;
		SHAPE ABUTMENT ;
		PORT
			 LAYER M2 ;
			RECT 0.0714 70.6824 0.1097 70.72 ;
			 LAYER M3 ;
			RECT 0.0714 70.6824 0.1097 70.7827 ;
			 LAYER V2 ;
			RECT 0.0831 70.6945 0.098 70.7071 ;
		END

		ANTENNAGATEAREA 0.00027817 ;
		ANTENNADIFFAREA 0.00194719 ;
		ANTENNAPARTIALMETALAREA 0.00195671 ;
	END TWEN[49]

	PIN TWEN[4]
		USE SIGNAL ;
		DIRECTION INPUT ;
		SHAPE ABUTMENT ;
		PORT
			 LAYER M2 ;
			RECT 0.0714 6.5506 0.1097 6.5882 ;
			 LAYER M3 ;
			RECT 0.0714 6.4878 0.1097 6.5882 ;
			 LAYER V2 ;
			RECT 0.0831 6.5635 0.098 6.5761 ;
		END

		ANTENNAGATEAREA 0.00027817 ;
		ANTENNADIFFAREA 0.00194719 ;
		ANTENNAPARTIALMETALAREA 0.00195671 ;
	END TWEN[4]

	PIN TWEN[50]
		USE SIGNAL ;
		DIRECTION INPUT ;
		SHAPE ABUTMENT ;
		PORT
			 LAYER M2 ;
			RECT 0.0714 71.9624 0.1097 72 ;
			 LAYER M3 ;
			RECT 0.0714 71.9624 0.1097 72.0627 ;
			 LAYER V2 ;
			RECT 0.0831 71.9745 0.098 71.9871 ;
		END

		ANTENNAGATEAREA 0.00027817 ;
		ANTENNADIFFAREA 0.00194719 ;
		ANTENNAPARTIALMETALAREA 0.00195671 ;
	END TWEN[50]

	PIN TWEN[51]
		USE SIGNAL ;
		DIRECTION INPUT ;
		SHAPE ABUTMENT ;
		PORT
			 LAYER M2 ;
			RECT 0.0714 73.2424 0.1097 73.28 ;
			 LAYER M3 ;
			RECT 0.0714 73.2424 0.1097 73.3427 ;
			 LAYER V2 ;
			RECT 0.0831 73.2545 0.098 73.2671 ;
		END

		ANTENNAGATEAREA 0.00027817 ;
		ANTENNADIFFAREA 0.00194719 ;
		ANTENNAPARTIALMETALAREA 0.00195671 ;
	END TWEN[51]

	PIN TWEN[52]
		USE SIGNAL ;
		DIRECTION INPUT ;
		SHAPE ABUTMENT ;
		PORT
			 LAYER M2 ;
			RECT 0.0714 74.5224 0.1097 74.56 ;
			 LAYER M3 ;
			RECT 0.0714 74.5224 0.1097 74.6227 ;
			 LAYER V2 ;
			RECT 0.0831 74.5345 0.098 74.5471 ;
		END

		ANTENNAGATEAREA 0.00027817 ;
		ANTENNADIFFAREA 0.00194719 ;
		ANTENNAPARTIALMETALAREA 0.00195671 ;
	END TWEN[52]

	PIN TWEN[53]
		USE SIGNAL ;
		DIRECTION INPUT ;
		SHAPE ABUTMENT ;
		PORT
			 LAYER M2 ;
			RECT 0.0714 75.8024 0.1097 75.84 ;
			 LAYER M3 ;
			RECT 0.0714 75.8024 0.1097 75.9027 ;
			 LAYER V2 ;
			RECT 0.0831 75.8145 0.098 75.8271 ;
		END

		ANTENNAGATEAREA 0.00027817 ;
		ANTENNADIFFAREA 0.00194719 ;
		ANTENNAPARTIALMETALAREA 0.00195671 ;
	END TWEN[53]

	PIN TWEN[54]
		USE SIGNAL ;
		DIRECTION INPUT ;
		SHAPE ABUTMENT ;
		PORT
			 LAYER M2 ;
			RECT 0.0714 77.0824 0.1097 77.12 ;
			 LAYER M3 ;
			RECT 0.0714 77.0824 0.1097 77.1827 ;
			 LAYER V2 ;
			RECT 0.0831 77.0945 0.098 77.1071 ;
		END

		ANTENNAGATEAREA 0.00027817 ;
		ANTENNADIFFAREA 0.00194719 ;
		ANTENNAPARTIALMETALAREA 0.00195671 ;
	END TWEN[54]

	PIN TWEN[55]
		USE SIGNAL ;
		DIRECTION INPUT ;
		SHAPE ABUTMENT ;
		PORT
			 LAYER M2 ;
			RECT 0.0714 78.3624 0.1097 78.4 ;
			 LAYER M3 ;
			RECT 0.0714 78.3624 0.1097 78.4627 ;
			 LAYER V2 ;
			RECT 0.0831 78.3745 0.098 78.3871 ;
		END

		ANTENNAGATEAREA 0.00027817 ;
		ANTENNADIFFAREA 0.00194719 ;
		ANTENNAPARTIALMETALAREA 0.00195671 ;
	END TWEN[55]

	PIN TWEN[56]
		USE SIGNAL ;
		DIRECTION INPUT ;
		SHAPE ABUTMENT ;
		PORT
			 LAYER M2 ;
			RECT 0.0714 79.6424 0.1097 79.68 ;
			 LAYER M3 ;
			RECT 0.0714 79.6424 0.1097 79.7427 ;
			 LAYER V2 ;
			RECT 0.0831 79.6545 0.098 79.6671 ;
		END

		ANTENNAGATEAREA 0.00027817 ;
		ANTENNADIFFAREA 0.00194719 ;
		ANTENNAPARTIALMETALAREA 0.00195671 ;
	END TWEN[56]

	PIN TWEN[57]
		USE SIGNAL ;
		DIRECTION INPUT ;
		SHAPE ABUTMENT ;
		PORT
			 LAYER M2 ;
			RECT 0.0714 80.9224 0.1097 80.96 ;
			 LAYER M3 ;
			RECT 0.0714 80.9224 0.1097 81.0227 ;
			 LAYER V2 ;
			RECT 0.0831 80.9345 0.098 80.9471 ;
		END

		ANTENNAGATEAREA 0.00027817 ;
		ANTENNADIFFAREA 0.00194719 ;
		ANTENNAPARTIALMETALAREA 0.00195671 ;
	END TWEN[57]

	PIN TWEN[58]
		USE SIGNAL ;
		DIRECTION INPUT ;
		SHAPE ABUTMENT ;
		PORT
			 LAYER M2 ;
			RECT 0.0714 82.2024 0.1097 82.24 ;
			 LAYER M3 ;
			RECT 0.0714 82.2024 0.1097 82.3027 ;
			 LAYER V2 ;
			RECT 0.0831 82.2145 0.098 82.2271 ;
		END

		ANTENNAGATEAREA 0.00027817 ;
		ANTENNADIFFAREA 0.00194719 ;
		ANTENNAPARTIALMETALAREA 0.00195671 ;
	END TWEN[58]

	PIN TWEN[59]
		USE SIGNAL ;
		DIRECTION INPUT ;
		SHAPE ABUTMENT ;
		PORT
			 LAYER M2 ;
			RECT 0.0714 83.4824 0.1097 83.52 ;
			 LAYER M3 ;
			RECT 0.0714 83.4824 0.1097 83.5827 ;
			 LAYER V2 ;
			RECT 0.0831 83.4945 0.098 83.5071 ;
		END

		ANTENNAGATEAREA 0.00027817 ;
		ANTENNADIFFAREA 0.00194719 ;
		ANTENNAPARTIALMETALAREA 0.00195671 ;
	END TWEN[59]

	PIN TWEN[5]
		USE SIGNAL ;
		DIRECTION INPUT ;
		SHAPE ABUTMENT ;
		PORT
			 LAYER M2 ;
			RECT 0.0714 7.8306 0.1097 7.8682 ;
			 LAYER M3 ;
			RECT 0.0714 7.7678 0.1097 7.8682 ;
			 LAYER V2 ;
			RECT 0.0831 7.8435 0.098 7.8561 ;
		END

		ANTENNAGATEAREA 0.00027817 ;
		ANTENNADIFFAREA 0.00194719 ;
		ANTENNAPARTIALMETALAREA 0.00195671 ;
	END TWEN[5]

	PIN TWEN[60]
		USE SIGNAL ;
		DIRECTION INPUT ;
		SHAPE ABUTMENT ;
		PORT
			 LAYER M2 ;
			RECT 0.0714 84.7624 0.1097 84.8 ;
			 LAYER M3 ;
			RECT 0.0714 84.7624 0.1097 84.8627 ;
			 LAYER V2 ;
			RECT 0.0831 84.7745 0.098 84.7871 ;
		END

		ANTENNAGATEAREA 0.00027817 ;
		ANTENNADIFFAREA 0.00194719 ;
		ANTENNAPARTIALMETALAREA 0.00195671 ;
	END TWEN[60]

	PIN TWEN[61]
		USE SIGNAL ;
		DIRECTION INPUT ;
		SHAPE ABUTMENT ;
		PORT
			 LAYER M2 ;
			RECT 0.0714 86.0424 0.1097 86.08 ;
			 LAYER M3 ;
			RECT 0.0714 86.0424 0.1097 86.1427 ;
			 LAYER V2 ;
			RECT 0.0831 86.0545 0.098 86.0671 ;
		END

		ANTENNAGATEAREA 0.00027817 ;
		ANTENNADIFFAREA 0.00194719 ;
		ANTENNAPARTIALMETALAREA 0.00195671 ;
	END TWEN[61]

	PIN TWEN[62]
		USE SIGNAL ;
		DIRECTION INPUT ;
		SHAPE ABUTMENT ;
		PORT
			 LAYER M2 ;
			RECT 0.0714 87.3224 0.1097 87.36 ;
			 LAYER M3 ;
			RECT 0.0714 87.3224 0.1097 87.4227 ;
			 LAYER V2 ;
			RECT 0.0831 87.3345 0.098 87.3471 ;
		END

		ANTENNAGATEAREA 0.00027817 ;
		ANTENNADIFFAREA 0.00194719 ;
		ANTENNAPARTIALMETALAREA 0.00195671 ;
	END TWEN[62]

	PIN TWEN[63]
		USE SIGNAL ;
		DIRECTION INPUT ;
		SHAPE ABUTMENT ;
		PORT
			 LAYER M2 ;
			RECT 0.0714 88.6024 0.1097 88.64 ;
			 LAYER M3 ;
			RECT 0.0714 88.6024 0.1097 88.7027 ;
			 LAYER V2 ;
			RECT 0.0831 88.6145 0.098 88.6271 ;
		END

		ANTENNAGATEAREA 0.00027817 ;
		ANTENNADIFFAREA 0.00194719 ;
		ANTENNAPARTIALMETALAREA 0.00195671 ;
	END TWEN[63]

	PIN TWEN[64]
		USE SIGNAL ;
		DIRECTION INPUT ;
		SHAPE ABUTMENT ;
		PORT
			 LAYER M2 ;
			RECT 0.0714 89.8824 0.1097 89.92 ;
			 LAYER M3 ;
			RECT 0.0714 89.8824 0.1097 89.9827 ;
			 LAYER V2 ;
			RECT 0.0831 89.8945 0.098 89.9071 ;
		END

		ANTENNAGATEAREA 0.00027817 ;
		ANTENNADIFFAREA 0.00194719 ;
		ANTENNAPARTIALMETALAREA 0.00195671 ;
	END TWEN[64]

	PIN TWEN[65]
		USE SIGNAL ;
		DIRECTION INPUT ;
		SHAPE ABUTMENT ;
		PORT
			 LAYER M2 ;
			RECT 0.0714 91.1624 0.1097 91.2 ;
			 LAYER M3 ;
			RECT 0.0714 91.1624 0.1097 91.2627 ;
			 LAYER V2 ;
			RECT 0.0831 91.1745 0.098 91.1871 ;
		END

		ANTENNAGATEAREA 0.00027817 ;
		ANTENNADIFFAREA 0.00194719 ;
		ANTENNAPARTIALMETALAREA 0.00195671 ;
	END TWEN[65]

	PIN TWEN[6]
		USE SIGNAL ;
		DIRECTION INPUT ;
		SHAPE ABUTMENT ;
		PORT
			 LAYER M2 ;
			RECT 0.0714 9.1106 0.1097 9.1482 ;
			 LAYER M3 ;
			RECT 0.0714 9.0478 0.1097 9.1482 ;
			 LAYER V2 ;
			RECT 0.0831 9.1235 0.098 9.1361 ;
		END

		ANTENNAGATEAREA 0.00027817 ;
		ANTENNADIFFAREA 0.00194719 ;
		ANTENNAPARTIALMETALAREA 0.00195671 ;
	END TWEN[6]

	PIN TWEN[7]
		USE SIGNAL ;
		DIRECTION INPUT ;
		SHAPE ABUTMENT ;
		PORT
			 LAYER M2 ;
			RECT 0.0714 10.3906 0.1097 10.4282 ;
			 LAYER M3 ;
			RECT 0.0714 10.3278 0.1097 10.4282 ;
			 LAYER V2 ;
			RECT 0.0831 10.4035 0.098 10.4161 ;
		END

		ANTENNAGATEAREA 0.00027817 ;
		ANTENNADIFFAREA 0.00194719 ;
		ANTENNAPARTIALMETALAREA 0.00195671 ;
	END TWEN[7]

	PIN TWEN[8]
		USE SIGNAL ;
		DIRECTION INPUT ;
		SHAPE ABUTMENT ;
		PORT
			 LAYER M2 ;
			RECT 0.0714 11.6706 0.1097 11.7082 ;
			 LAYER M3 ;
			RECT 0.0714 11.6078 0.1097 11.7082 ;
			 LAYER V2 ;
			RECT 0.0831 11.6835 0.098 11.6961 ;
		END

		ANTENNAGATEAREA 0.00027817 ;
		ANTENNADIFFAREA 0.00194719 ;
		ANTENNAPARTIALMETALAREA 0.00195671 ;
	END TWEN[8]

	PIN TWEN[9]
		USE SIGNAL ;
		DIRECTION INPUT ;
		SHAPE ABUTMENT ;
		PORT
			 LAYER M2 ;
			RECT 0.0714 12.9506 0.1097 12.9882 ;
			 LAYER M3 ;
			RECT 0.0714 12.8878 0.1097 12.9882 ;
			 LAYER V2 ;
			RECT 0.0831 12.9635 0.098 12.9761 ;
		END

		ANTENNAGATEAREA 0.00027817 ;
		ANTENNADIFFAREA 0.00194719 ;
		ANTENNAPARTIALMETALAREA 0.00195671 ;
	END TWEN[9]

	PIN VDDCE
		USE POWER ;
		DIRECTION INOUT ;
		PORT
			 LAYER M4 ;
			RECT 0.2105 91.789 21.693 91.8361 ;
		END

		PORT
			 LAYER M4 ;
			RECT 0.2105 71.309 21.693 71.3561 ;
		END

		PORT
			 LAYER M4 ;
			RECT 0.2105 70.669 21.693 70.7161 ;
		END

		PORT
			 LAYER M4 ;
			RECT 0.2105 70.029 21.693 70.0761 ;
		END

		PORT
			 LAYER M4 ;
			RECT 0.2105 90.509 21.693 90.5561 ;
		END

		PORT
			 LAYER M4 ;
			RECT 0.2105 69.389 21.693 69.4361 ;
		END

		PORT
			 LAYER M4 ;
			RECT 0.2105 68.749 21.693 68.7961 ;
		END

		PORT
			 LAYER M4 ;
			RECT 0.2105 68.109 21.693 68.1561 ;
		END

		PORT
			 LAYER M4 ;
			RECT 0.2105 67.469 21.693 67.5161 ;
		END

		PORT
			 LAYER M4 ;
			RECT 0.2105 66.829 21.693 66.8761 ;
		END

		PORT
			 LAYER M4 ;
			RECT 0.2105 66.189 21.693 66.2361 ;
		END

		PORT
			 LAYER M4 ;
			RECT 0.2105 65.549 21.693 65.5961 ;
		END

		PORT
			 LAYER M4 ;
			RECT 0.2105 64.909 21.693 64.9561 ;
		END

		PORT
			 LAYER M4 ;
			RECT 0.2105 64.269 21.693 64.3161 ;
		END

		PORT
			 LAYER M4 ;
			RECT 0.2105 63.629 21.693 63.6761 ;
		END

		PORT
			 LAYER M4 ;
			RECT 0.2105 89.869 21.693 89.9161 ;
		END

		PORT
			 LAYER M4 ;
			RECT 0.2105 62.989 21.693 63.0361 ;
		END

		PORT
			 LAYER M4 ;
			RECT 0.2105 62.349 21.693 62.3961 ;
		END

		PORT
			 LAYER M4 ;
			RECT 0.2105 61.709 21.693 61.7561 ;
		END

		PORT
			 LAYER M4 ;
			RECT 0.2105 61.069 21.693 61.1161 ;
		END

		PORT
			 LAYER M4 ;
			RECT 0.2105 60.429 21.693 60.4761 ;
		END

		PORT
			 LAYER M4 ;
			RECT 0.2105 59.789 21.693 59.8361 ;
		END

		PORT
			 LAYER M4 ;
			RECT 0.2105 59.149 21.693 59.1961 ;
		END

		PORT
			 LAYER M4 ;
			RECT 0.2105 58.509 21.693 58.5561 ;
		END

		PORT
			 LAYER M4 ;
			RECT 0.2105 57.869 21.693 57.9161 ;
		END

		PORT
			 LAYER M4 ;
			RECT 0.2105 57.229 21.693 57.2761 ;
		END

		PORT
			 LAYER M4 ;
			RECT 0.2105 89.229 21.693 89.2761 ;
		END

		PORT
			 LAYER M4 ;
			RECT 0.2105 56.589 21.693 56.6361 ;
		END

		PORT
			 LAYER M4 ;
			RECT 0.2105 55.949 21.693 55.9961 ;
		END

		PORT
			 LAYER M4 ;
			RECT 0.2105 55.309 21.693 55.3561 ;
		END

		PORT
			 LAYER M4 ;
			RECT 0.2105 54.669 21.693 54.7161 ;
		END

		PORT
			 LAYER M4 ;
			RECT 0.2105 54.029 21.693 54.0761 ;
		END

		PORT
			 LAYER M4 ;
			RECT 0.2105 53.389 21.693 53.4361 ;
		END

		PORT
			 LAYER M4 ;
			RECT 0.2105 52.749 21.693 52.7961 ;
		END

		PORT
			 LAYER M4 ;
			RECT 0.2105 52.109 21.693 52.1561 ;
		END

		PORT
			 LAYER M4 ;
			RECT 0.2105 51.469 21.693 51.5161 ;
		END

		PORT
			 LAYER M4 ;
			RECT 0.2105 50.829 21.693 50.8761 ;
		END

		PORT
			 LAYER M4 ;
			RECT 0.2105 88.589 21.693 88.6361 ;
		END

		PORT
			 LAYER M4 ;
			RECT 0.2105 50.189 21.693 50.2361 ;
		END

		PORT
			 LAYER M4 ;
			RECT 0.2105 87.949 21.693 87.9961 ;
		END

		PORT
			 LAYER M4 ;
			RECT 0.2105 42.3945 21.693 42.4416 ;
		END

		PORT
			 LAYER M4 ;
			RECT 0.2105 41.7545 21.693 41.8016 ;
		END

		PORT
			 LAYER M4 ;
			RECT 0.2105 41.1145 21.693 41.1616 ;
		END

		PORT
			 LAYER M4 ;
			RECT 0.2105 40.4745 21.693 40.5216 ;
		END

		PORT
			 LAYER M4 ;
			RECT 0.2105 39.8345 21.693 39.8816 ;
		END

		PORT
			 LAYER M4 ;
			RECT 0.2105 39.1945 21.693 39.2416 ;
		END

		PORT
			 LAYER M4 ;
			RECT 0.2105 38.5545 21.693 38.6016 ;
		END

		PORT
			 LAYER M4 ;
			RECT 0.2105 37.9145 21.693 37.9616 ;
		END

		PORT
			 LAYER M4 ;
			RECT 0.2105 87.309 21.693 87.3561 ;
		END

		PORT
			 LAYER M4 ;
			RECT 0.2105 37.2745 21.693 37.3216 ;
		END

		PORT
			 LAYER M4 ;
			RECT 0.2105 36.6345 21.693 36.6816 ;
		END

		PORT
			 LAYER M4 ;
			RECT 0.2105 35.9945 21.693 36.0416 ;
		END

		PORT
			 LAYER M4 ;
			RECT 0.2105 35.3545 21.693 35.4016 ;
		END

		PORT
			 LAYER M4 ;
			RECT 0.2105 34.7145 21.693 34.7616 ;
		END

		PORT
			 LAYER M4 ;
			RECT 0.2105 34.0745 21.693 34.1216 ;
		END

		PORT
			 LAYER M4 ;
			RECT 0.2105 33.4345 21.693 33.4816 ;
		END

		PORT
			 LAYER M4 ;
			RECT 0.2105 32.7945 21.693 32.8416 ;
		END

		PORT
			 LAYER M4 ;
			RECT 0.2105 32.1545 21.693 32.2016 ;
		END

		PORT
			 LAYER M4 ;
			RECT 0.2105 31.5145 21.693 31.5616 ;
		END

		PORT
			 LAYER M4 ;
			RECT 0.2105 86.669 21.693 86.7161 ;
		END

		PORT
			 LAYER M4 ;
			RECT 0.2105 30.8745 21.693 30.9216 ;
		END

		PORT
			 LAYER M4 ;
			RECT 0.2105 30.2345 21.693 30.2816 ;
		END

		PORT
			 LAYER M4 ;
			RECT 0.2105 29.5945 21.693 29.6416 ;
		END

		PORT
			 LAYER M4 ;
			RECT 0.2105 28.9545 21.693 29.0016 ;
		END

		PORT
			 LAYER M4 ;
			RECT 0.2105 28.3145 21.693 28.3616 ;
		END

		PORT
			 LAYER M4 ;
			RECT 0.2105 27.6745 21.693 27.7216 ;
		END

		PORT
			 LAYER M4 ;
			RECT 0.2105 27.0345 21.693 27.0816 ;
		END

		PORT
			 LAYER M4 ;
			RECT 0.2105 26.3945 21.693 26.4416 ;
		END

		PORT
			 LAYER M4 ;
			RECT 0.2105 25.7545 21.693 25.8016 ;
		END

		PORT
			 LAYER M4 ;
			RECT 0.2105 25.1145 21.693 25.1616 ;
		END

		PORT
			 LAYER M4 ;
			RECT 0.2105 86.029 21.693 86.0761 ;
		END

		PORT
			 LAYER M4 ;
			RECT 0.2105 24.4745 21.693 24.5216 ;
		END

		PORT
			 LAYER M4 ;
			RECT 0.2105 23.8345 21.693 23.8816 ;
		END

		PORT
			 LAYER M4 ;
			RECT 0.2105 23.1945 21.693 23.2416 ;
		END

		PORT
			 LAYER M4 ;
			RECT 0.2105 22.5545 21.693 22.6016 ;
		END

		PORT
			 LAYER M4 ;
			RECT 0.2105 21.9145 21.693 21.9616 ;
		END

		PORT
			 LAYER M4 ;
			RECT 0.2105 21.2745 21.693 21.3216 ;
		END

		PORT
			 LAYER M4 ;
			RECT 0.2105 20.6345 21.693 20.6816 ;
		END

		PORT
			 LAYER M4 ;
			RECT 0.2105 19.9945 21.693 20.0416 ;
		END

		PORT
			 LAYER M4 ;
			RECT 0.2105 19.3545 21.693 19.4016 ;
		END

		PORT
			 LAYER M4 ;
			RECT 0.2105 18.7145 21.693 18.7616 ;
		END

		PORT
			 LAYER M4 ;
			RECT 0.2105 85.389 21.693 85.4361 ;
		END

		PORT
			 LAYER M4 ;
			RECT 0.2105 18.0745 21.693 18.1216 ;
		END

		PORT
			 LAYER M4 ;
			RECT 0.2105 17.4345 21.693 17.4816 ;
		END

		PORT
			 LAYER M4 ;
			RECT 0.2105 16.7945 21.693 16.8416 ;
		END

		PORT
			 LAYER M4 ;
			RECT 0.2105 16.1545 21.693 16.2016 ;
		END

		PORT
			 LAYER M4 ;
			RECT 0.2105 15.5145 21.693 15.5616 ;
		END

		PORT
			 LAYER M4 ;
			RECT 0.2105 14.8745 21.693 14.9216 ;
		END

		PORT
			 LAYER M4 ;
			RECT 0.2105 14.2345 21.693 14.2816 ;
		END

		PORT
			 LAYER M4 ;
			RECT 0.2105 13.5945 21.693 13.6416 ;
		END

		PORT
			 LAYER M4 ;
			RECT 0.2105 12.9545 21.693 13.0016 ;
		END

		PORT
			 LAYER M4 ;
			RECT 0.2105 12.3145 21.693 12.3616 ;
		END

		PORT
			 LAYER M4 ;
			RECT 0.2105 84.749 21.693 84.7961 ;
		END

		PORT
			 LAYER M4 ;
			RECT 0.2105 11.6745 21.693 11.7216 ;
		END

		PORT
			 LAYER M4 ;
			RECT 0.2105 11.0345 21.693 11.0816 ;
		END

		PORT
			 LAYER M4 ;
			RECT 0.2105 10.3945 21.693 10.4416 ;
		END

		PORT
			 LAYER M4 ;
			RECT 0.2105 9.7545 21.693 9.8016 ;
		END

		PORT
			 LAYER M4 ;
			RECT 0.2105 9.1145 21.693 9.1616 ;
		END

		PORT
			 LAYER M4 ;
			RECT 0.2105 8.4745 21.693 8.5216 ;
		END

		PORT
			 LAYER M4 ;
			RECT 0.2105 7.8345 21.693 7.8816 ;
		END

		PORT
			 LAYER M4 ;
			RECT 0.2105 7.1945 21.693 7.2416 ;
		END

		PORT
			 LAYER M4 ;
			RECT 0.2105 6.5545 21.693 6.6016 ;
		END

		PORT
			 LAYER M4 ;
			RECT 0.2105 5.9145 21.693 5.9616 ;
		END

		PORT
			 LAYER M4 ;
			RECT 0.2105 84.109 21.693 84.1561 ;
		END

		PORT
			 LAYER M4 ;
			RECT 0.2105 5.2745 21.693 5.3216 ;
		END

		PORT
			 LAYER M4 ;
			RECT 0.2105 4.6345 21.693 4.6816 ;
		END

		PORT
			 LAYER M4 ;
			RECT 0.2105 3.9945 21.693 4.0416 ;
		END

		PORT
			 LAYER M4 ;
			RECT 0.2105 3.3545 21.693 3.4016 ;
		END

		PORT
			 LAYER M4 ;
			RECT 0.2105 2.7145 21.693 2.7616 ;
		END

		PORT
			 LAYER M4 ;
			RECT 0.2105 2.0745 21.693 2.1216 ;
		END

		PORT
			 LAYER M4 ;
			RECT 0.2105 1.4345 21.693 1.4816 ;
		END

		PORT
			 LAYER M4 ;
			RECT 0.2105 0.7945 21.693 0.8416 ;
		END

		PORT
			 LAYER M4 ;
			RECT 0.2105 83.469 21.693 83.5161 ;
		END

		PORT
			 LAYER M4 ;
			RECT 0.2105 82.829 21.693 82.8761 ;
		END

		PORT
			 LAYER M4 ;
			RECT 0.2105 82.189 21.693 82.2361 ;
		END

		PORT
			 LAYER M4 ;
			RECT 0.2105 81.549 21.693 81.5961 ;
		END

		PORT
			 LAYER M4 ;
			RECT 0.2105 80.909 21.693 80.9561 ;
		END

		PORT
			 LAYER M4 ;
			RECT 0.2105 80.269 21.693 80.3161 ;
		END

		PORT
			 LAYER M4 ;
			RECT 0.2105 79.629 21.693 79.6761 ;
		END

		PORT
			 LAYER M4 ;
			RECT 0.2105 78.989 21.693 79.0361 ;
		END

		PORT
			 LAYER M4 ;
			RECT 0.2105 78.349 21.693 78.3961 ;
		END

		PORT
			 LAYER M4 ;
			RECT 0.2105 77.709 21.693 77.7561 ;
		END

		PORT
			 LAYER M4 ;
			RECT 0.2105 77.069 21.693 77.1161 ;
		END

		PORT
			 LAYER M4 ;
			RECT 0.2105 76.429 21.693 76.4761 ;
		END

		PORT
			 LAYER M4 ;
			RECT 0.2105 91.149 21.693 91.1961 ;
		END

		PORT
			 LAYER M4 ;
			RECT 0.2105 75.789 21.693 75.8361 ;
		END

		PORT
			 LAYER M4 ;
			RECT 0.2105 75.149 21.693 75.1961 ;
		END

		PORT
			 LAYER M4 ;
			RECT 0.2105 74.509 21.693 74.5561 ;
		END

		PORT
			 LAYER M4 ;
			RECT 0.2105 73.869 21.693 73.9161 ;
		END

		PORT
			 LAYER M4 ;
			RECT 0.2105 73.229 21.693 73.2761 ;
		END

		PORT
			 LAYER M4 ;
			RECT 0.2105 72.589 21.693 72.6361 ;
		END

		PORT
			 LAYER M4 ;
			RECT 0.2105 71.949 21.693 71.9961 ;
		END

		PORT
			 LAYER M4 ;
			RECT 0.2105 92.5459 21.693 92.5773 ;
		END

		PORT
			 LAYER M4 ;
			RECT 0.2105 0.0533 21.693 0.0847 ;
		END

		PORT
			 LAYER M4 ;
			RECT 0.2105 43.1075 21.693 43.1545 ;
		END

		PORT
			 LAYER M4 ;
			RECT 0.2105 43.3992 21.693 43.4463 ;
		END

		PORT
			 LAYER M4 ;
			RECT 0.2105 49.3537 21.693 49.4008 ;
		END

		PORT
			 LAYER M4 ;
			RECT 0.2105 49.6455 21.693 49.6925 ;
		END

		PORT
			 LAYER M4 ;
			RECT 0.2105 42.5443 21.693 42.5757 ;
		END

		PORT
			 LAYER M4 ;
			RECT 0.2105 50.0584 21.693 50.0898 ;
		END

		PORT
			 LAYER M4 ;
			RECT 0.2105 92.4204 21.693 92.4518 ;
		END

		PORT
			 LAYER M4 ;
			RECT 0.2105 0.1788 21.693 0.2102 ;
		END

	END VDDCE

	PIN VDDPE
		USE POWER ;
		DIRECTION INOUT ;
		PORT
			 LAYER M4 ;
			RECT 0.2105 92.022 21.693 92.069 ;
		END

		PORT
			 LAYER M4 ;
			RECT 0.2105 90.742 21.693 90.789 ;
		END

		PORT
			 LAYER M4 ;
			RECT 0.2105 71.542 21.693 71.589 ;
		END

		PORT
			 LAYER M4 ;
			RECT 0.2105 70.902 21.693 70.949 ;
		END

		PORT
			 LAYER M4 ;
			RECT 0.2105 70.262 21.693 70.309 ;
		END

		PORT
			 LAYER M4 ;
			RECT 0.2105 69.622 21.693 69.669 ;
		END

		PORT
			 LAYER M4 ;
			RECT 0.2105 68.982 21.693 69.029 ;
		END

		PORT
			 LAYER M4 ;
			RECT 0.2105 68.342 21.693 68.389 ;
		END

		PORT
			 LAYER M4 ;
			RECT 0.2105 67.702 21.693 67.749 ;
		END

		PORT
			 LAYER M4 ;
			RECT 0.2105 67.062 21.693 67.109 ;
		END

		PORT
			 LAYER M4 ;
			RECT 0.2105 66.422 21.693 66.469 ;
		END

		PORT
			 LAYER M4 ;
			RECT 0.2105 65.782 21.693 65.829 ;
		END

		PORT
			 LAYER M4 ;
			RECT 0.2105 90.102 21.693 90.149 ;
		END

		PORT
			 LAYER M4 ;
			RECT 0.2105 65.142 21.693 65.189 ;
		END

		PORT
			 LAYER M4 ;
			RECT 0.2105 64.502 21.693 64.549 ;
		END

		PORT
			 LAYER M4 ;
			RECT 0.2105 63.862 21.693 63.909 ;
		END

		PORT
			 LAYER M4 ;
			RECT 0.2105 63.222 21.693 63.269 ;
		END

		PORT
			 LAYER M4 ;
			RECT 0.2105 62.582 21.693 62.629 ;
		END

		PORT
			 LAYER M4 ;
			RECT 0.2105 61.942 21.693 61.989 ;
		END

		PORT
			 LAYER M4 ;
			RECT 0.2105 61.302 21.693 61.349 ;
		END

		PORT
			 LAYER M4 ;
			RECT 0.2105 60.662 21.693 60.709 ;
		END

		PORT
			 LAYER M4 ;
			RECT 0.2105 60.022 21.693 60.069 ;
		END

		PORT
			 LAYER M4 ;
			RECT 0.2105 59.382 21.693 59.429 ;
		END

		PORT
			 LAYER M4 ;
			RECT 0.2105 89.462 21.693 89.509 ;
		END

		PORT
			 LAYER M4 ;
			RECT 0.2105 58.742 21.693 58.789 ;
		END

		PORT
			 LAYER M4 ;
			RECT 0.2105 58.102 21.693 58.149 ;
		END

		PORT
			 LAYER M4 ;
			RECT 0.2105 57.462 21.693 57.509 ;
		END

		PORT
			 LAYER M4 ;
			RECT 0.2105 56.822 21.693 56.869 ;
		END

		PORT
			 LAYER M4 ;
			RECT 0.2105 56.182 21.693 56.229 ;
		END

		PORT
			 LAYER M4 ;
			RECT 0.2105 55.542 21.693 55.589 ;
		END

		PORT
			 LAYER M4 ;
			RECT 0.2105 54.902 21.693 54.949 ;
		END

		PORT
			 LAYER M4 ;
			RECT 0.2105 54.262 21.693 54.309 ;
		END

		PORT
			 LAYER M4 ;
			RECT 0.2105 53.622 21.693 53.669 ;
		END

		PORT
			 LAYER M4 ;
			RECT 0.2105 52.982 21.693 53.029 ;
		END

		PORT
			 LAYER M4 ;
			RECT 0.2105 88.822 21.693 88.869 ;
		END

		PORT
			 LAYER M4 ;
			RECT 0.2105 52.342 21.693 52.389 ;
		END

		PORT
			 LAYER M4 ;
			RECT 0.2105 51.702 21.693 51.749 ;
		END

		PORT
			 LAYER M4 ;
			RECT 0.2105 51.062 21.693 51.109 ;
		END

		PORT
			 LAYER M4 ;
			RECT 0.2105 50.422 21.693 50.469 ;
		END

		PORT
			 LAYER M4 ;
			RECT 0.2105 88.182 21.693 88.229 ;
		END

		PORT
			 LAYER M4 ;
			RECT 0.2105 42.1616 21.693 42.2086 ;
		END

		PORT
			 LAYER M4 ;
			RECT 0.2105 41.5216 21.693 41.5686 ;
		END

		PORT
			 LAYER M4 ;
			RECT 0.2105 40.8816 21.693 40.9286 ;
		END

		PORT
			 LAYER M4 ;
			RECT 0.2105 40.2416 21.693 40.2886 ;
		END

		PORT
			 LAYER M4 ;
			RECT 0.2105 39.6016 21.693 39.6486 ;
		END

		PORT
			 LAYER M4 ;
			RECT 0.2105 87.542 21.693 87.589 ;
		END

		PORT
			 LAYER M4 ;
			RECT 0.2105 38.9616 21.693 39.0086 ;
		END

		PORT
			 LAYER M4 ;
			RECT 0.2105 38.3216 21.693 38.3686 ;
		END

		PORT
			 LAYER M4 ;
			RECT 0.2105 37.6816 21.693 37.7286 ;
		END

		PORT
			 LAYER M4 ;
			RECT 0.2105 37.0416 21.693 37.0886 ;
		END

		PORT
			 LAYER M4 ;
			RECT 0.2105 36.4016 21.693 36.4486 ;
		END

		PORT
			 LAYER M4 ;
			RECT 0.2105 35.7616 21.693 35.8086 ;
		END

		PORT
			 LAYER M4 ;
			RECT 0.2105 35.1216 21.693 35.1686 ;
		END

		PORT
			 LAYER M4 ;
			RECT 0.2105 34.4816 21.693 34.5286 ;
		END

		PORT
			 LAYER M4 ;
			RECT 0.2105 33.8416 21.693 33.8886 ;
		END

		PORT
			 LAYER M4 ;
			RECT 0.2105 33.2016 21.693 33.2486 ;
		END

		PORT
			 LAYER M4 ;
			RECT 0.2105 86.902 21.693 86.949 ;
		END

		PORT
			 LAYER M4 ;
			RECT 0.2105 32.5616 21.693 32.6086 ;
		END

		PORT
			 LAYER M4 ;
			RECT 0.2105 31.9216 21.693 31.9686 ;
		END

		PORT
			 LAYER M4 ;
			RECT 0.2105 31.2816 21.693 31.3286 ;
		END

		PORT
			 LAYER M4 ;
			RECT 0.2105 30.6416 21.693 30.6886 ;
		END

		PORT
			 LAYER M4 ;
			RECT 0.2105 30.0016 21.693 30.0486 ;
		END

		PORT
			 LAYER M4 ;
			RECT 0.2105 29.3616 21.693 29.4086 ;
		END

		PORT
			 LAYER M4 ;
			RECT 0.2105 28.7216 21.693 28.7686 ;
		END

		PORT
			 LAYER M4 ;
			RECT 0.2105 28.0816 21.693 28.1286 ;
		END

		PORT
			 LAYER M4 ;
			RECT 0.2105 27.4416 21.693 27.4886 ;
		END

		PORT
			 LAYER M4 ;
			RECT 0.2105 26.8016 21.693 26.8486 ;
		END

		PORT
			 LAYER M4 ;
			RECT 0.2105 86.262 21.693 86.309 ;
		END

		PORT
			 LAYER M4 ;
			RECT 0.2105 26.1616 21.693 26.2086 ;
		END

		PORT
			 LAYER M4 ;
			RECT 0.2105 25.5216 21.693 25.5686 ;
		END

		PORT
			 LAYER M4 ;
			RECT 0.2105 24.8816 21.693 24.9286 ;
		END

		PORT
			 LAYER M4 ;
			RECT 0.2105 24.2416 21.693 24.2886 ;
		END

		PORT
			 LAYER M4 ;
			RECT 0.2105 23.6016 21.693 23.6486 ;
		END

		PORT
			 LAYER M4 ;
			RECT 0.2105 22.9616 21.693 23.0086 ;
		END

		PORT
			 LAYER M4 ;
			RECT 0.2105 22.3216 21.693 22.3686 ;
		END

		PORT
			 LAYER M4 ;
			RECT 0.2105 21.6816 21.693 21.7286 ;
		END

		PORT
			 LAYER M4 ;
			RECT 0.2105 21.0416 21.693 21.0886 ;
		END

		PORT
			 LAYER M4 ;
			RECT 0.2105 20.4016 21.693 20.4486 ;
		END

		PORT
			 LAYER M4 ;
			RECT 0.2105 85.622 21.693 85.669 ;
		END

		PORT
			 LAYER M4 ;
			RECT 0.2105 19.7616 21.693 19.8086 ;
		END

		PORT
			 LAYER M4 ;
			RECT 0.2105 19.1216 21.693 19.1686 ;
		END

		PORT
			 LAYER M4 ;
			RECT 0.2105 18.4816 21.693 18.5286 ;
		END

		PORT
			 LAYER M4 ;
			RECT 0.2105 17.8416 21.693 17.8886 ;
		END

		PORT
			 LAYER M4 ;
			RECT 0.2105 17.2016 21.693 17.2486 ;
		END

		PORT
			 LAYER M4 ;
			RECT 0.2105 16.5616 21.693 16.6086 ;
		END

		PORT
			 LAYER M4 ;
			RECT 0.2105 15.9216 21.693 15.9686 ;
		END

		PORT
			 LAYER M4 ;
			RECT 0.2105 15.2816 21.693 15.3286 ;
		END

		PORT
			 LAYER M4 ;
			RECT 0.2105 14.6416 21.693 14.6886 ;
		END

		PORT
			 LAYER M4 ;
			RECT 0.2105 14.0016 21.693 14.0486 ;
		END

		PORT
			 LAYER M4 ;
			RECT 0.2105 84.982 21.693 85.029 ;
		END

		PORT
			 LAYER M4 ;
			RECT 0.2105 13.3616 21.693 13.4086 ;
		END

		PORT
			 LAYER M4 ;
			RECT 0.2105 12.7216 21.693 12.7686 ;
		END

		PORT
			 LAYER M4 ;
			RECT 0.2105 12.0816 21.693 12.1286 ;
		END

		PORT
			 LAYER M4 ;
			RECT 0.2105 11.4416 21.693 11.4886 ;
		END

		PORT
			 LAYER M4 ;
			RECT 0.2105 10.8016 21.693 10.8486 ;
		END

		PORT
			 LAYER M4 ;
			RECT 0.2105 10.1616 21.693 10.2086 ;
		END

		PORT
			 LAYER M4 ;
			RECT 0.2105 9.5216 21.693 9.5686 ;
		END

		PORT
			 LAYER M4 ;
			RECT 0.2105 8.8816 21.693 8.9286 ;
		END

		PORT
			 LAYER M4 ;
			RECT 0.2105 8.2416 21.693 8.2886 ;
		END

		PORT
			 LAYER M4 ;
			RECT 0.2105 7.6016 21.693 7.6486 ;
		END

		PORT
			 LAYER M4 ;
			RECT 0.2105 84.342 21.693 84.389 ;
		END

		PORT
			 LAYER M4 ;
			RECT 0.2105 6.9616 21.693 7.0086 ;
		END

		PORT
			 LAYER M4 ;
			RECT 0.2105 6.3216 21.693 6.3686 ;
		END

		PORT
			 LAYER M4 ;
			RECT 0.2105 5.6816 21.693 5.7286 ;
		END

		PORT
			 LAYER M4 ;
			RECT 0.2105 5.0416 21.693 5.0886 ;
		END

		PORT
			 LAYER M4 ;
			RECT 0.2105 4.4016 21.693 4.4486 ;
		END

		PORT
			 LAYER M4 ;
			RECT 0.2105 3.7616 21.693 3.8086 ;
		END

		PORT
			 LAYER M4 ;
			RECT 0.2105 3.1216 21.693 3.1686 ;
		END

		PORT
			 LAYER M4 ;
			RECT 0.2105 2.4816 21.693 2.5286 ;
		END

		PORT
			 LAYER M4 ;
			RECT 0.2105 1.8416 21.693 1.8886 ;
		END

		PORT
			 LAYER M4 ;
			RECT 0.2105 1.2016 21.693 1.2486 ;
		END

		PORT
			 LAYER M4 ;
			RECT 0.2105 83.702 21.693 83.749 ;
		END

		PORT
			 LAYER M4 ;
			RECT 0.2105 0.5616 21.693 0.6086 ;
		END

		PORT
			 LAYER M4 ;
			RECT 0.2105 83.062 21.693 83.109 ;
		END

		PORT
			 LAYER M4 ;
			RECT 0.2105 82.422 21.693 82.469 ;
		END

		PORT
			 LAYER M4 ;
			RECT 0.2105 81.782 21.693 81.829 ;
		END

		PORT
			 LAYER M4 ;
			RECT 0.2105 81.142 21.693 81.189 ;
		END

		PORT
			 LAYER M4 ;
			RECT 0.2105 80.502 21.693 80.549 ;
		END

		PORT
			 LAYER M4 ;
			RECT 0.2105 79.862 21.693 79.909 ;
		END

		PORT
			 LAYER M4 ;
			RECT 0.2105 79.222 21.693 79.269 ;
		END

		PORT
			 LAYER M4 ;
			RECT 0.2105 78.582 21.693 78.629 ;
		END

		PORT
			 LAYER M4 ;
			RECT 0.2105 91.382 21.693 91.429 ;
		END

		PORT
			 LAYER M4 ;
			RECT 0.2105 77.942 21.693 77.989 ;
		END

		PORT
			 LAYER M4 ;
			RECT 0.2105 77.302 21.693 77.349 ;
		END

		PORT
			 LAYER M4 ;
			RECT 0.2105 76.662 21.693 76.709 ;
		END

		PORT
			 LAYER M4 ;
			RECT 0.2105 76.022 21.693 76.069 ;
		END

		PORT
			 LAYER M4 ;
			RECT 0.2105 75.382 21.693 75.429 ;
		END

		PORT
			 LAYER M4 ;
			RECT 0.2105 74.742 21.693 74.789 ;
		END

		PORT
			 LAYER M4 ;
			RECT 0.2105 74.102 21.693 74.149 ;
		END

		PORT
			 LAYER M4 ;
			RECT 0.2105 73.462 21.693 73.509 ;
		END

		PORT
			 LAYER M4 ;
			RECT 0.2105 72.822 21.693 72.869 ;
		END

		PORT
			 LAYER M4 ;
			RECT 0.2105 72.182 21.693 72.229 ;
		END

		PORT
			 LAYER M4 ;
			RECT 0.2105 42.7482 21.693 42.7953 ;
		END

		PORT
			 LAYER M4 ;
			RECT 0.2105 43.1859 21.693 43.2329 ;
		END

		PORT
			 LAYER M4 ;
			RECT 0.2105 43.4776 21.693 43.5247 ;
		END

		PORT
			 LAYER M4 ;
			RECT 0.2105 44.0047 21.693 44.0518 ;
		END

		PORT
			 LAYER M4 ;
			RECT 0.2105 44.5318 21.693 44.5788 ;
		END

		PORT
			 LAYER M4 ;
			RECT 0.2105 45.0588 21.693 45.1059 ;
		END

		PORT
			 LAYER M4 ;
			RECT 0.2105 45.5859 21.693 45.6329 ;
		END

		PORT
			 LAYER M4 ;
			RECT 0.2105 46.64 21.693 46.6871 ;
		END

		PORT
			 LAYER M4 ;
			RECT 0.2105 47.6941 21.693 47.7412 ;
		END

		PORT
			 LAYER M4 ;
			RECT 0.2105 48.2212 21.693 48.2682 ;
		END

		PORT
			 LAYER M4 ;
			RECT 0.2105 48.7482 21.693 48.7953 ;
		END

		PORT
			 LAYER M4 ;
			RECT 0.2105 49.2753 21.693 49.3224 ;
		END

		PORT
			 LAYER M4 ;
			RECT 0.2105 49.5671 21.693 49.6141 ;
		END

		PORT
			 LAYER M4 ;
			RECT 0.2105 42.6071 21.693 42.6384 ;
		END

		PORT
			 LAYER M4 ;
			RECT 0.2105 49.9957 21.693 50.0271 ;
		END

	END VDDPE

	PIN VSSE
		USE GROUND ;
		DIRECTION INOUT ;
		PORT
			 LAYER M4 ;
			RECT 0.2105 42.4816 21.693 42.5129 ;
		END

		PORT
			 LAYER M4 ;
			RECT 0.2105 50.1212 21.693 50.1525 ;
		END

		PORT
			 LAYER M4 ;
			RECT 0.2105 92.4831 21.693 92.5145 ;
		END

		PORT
			 LAYER M4 ;
			RECT 0.2105 0.1161 21.693 0.1475 ;
		END

		PORT
			 LAYER M4 ;
			RECT 0.2105 49.4322 21.693 49.4792 ;
		END

		PORT
			 LAYER M4 ;
			RECT 0.2105 42.6698 21.693 42.7169 ;
		END

		PORT
			 LAYER M4 ;
			RECT 0.2105 43.3208 21.693 43.3678 ;
		END

		PORT
			 LAYER M4 ;
			RECT 0.2105 43.9263 21.693 43.9733 ;
		END

		PORT
			 LAYER M4 ;
			RECT 0.2105 44.4533 21.693 44.5004 ;
		END

		PORT
			 LAYER M4 ;
			RECT 0.2105 44.9804 21.693 45.0275 ;
		END

		PORT
			 LAYER M4 ;
			RECT 0.2105 45.5075 21.693 45.5545 ;
		END

		PORT
			 LAYER M4 ;
			RECT 0.2105 46.5616 21.693 46.6086 ;
		END

		PORT
			 LAYER M4 ;
			RECT 0.2105 47.6157 21.693 47.6627 ;
		END

		PORT
			 LAYER M4 ;
			RECT 0.2105 48.1427 21.693 48.1898 ;
		END

		PORT
			 LAYER M4 ;
			RECT 0.2105 48.6698 21.693 48.7169 ;
		END

		PORT
			 LAYER M4 ;
			RECT 0.2105 49.1969 21.693 49.2439 ;
		END

		PORT
			 LAYER M4 ;
			RECT 0.2105 92.3333 21.693 92.3804 ;
		END

		PORT
			 LAYER M4 ;
			RECT 0.2105 71.2133 21.693 71.2604 ;
		END

		PORT
			 LAYER M4 ;
			RECT 0.2105 70.5733 21.693 70.6204 ;
		END

		PORT
			 LAYER M4 ;
			RECT 0.2105 69.9333 21.693 69.9804 ;
		END

		PORT
			 LAYER M4 ;
			RECT 0.2105 69.2933 21.693 69.3404 ;
		END

		PORT
			 LAYER M4 ;
			RECT 0.2105 68.6533 21.693 68.7004 ;
		END

		PORT
			 LAYER M4 ;
			RECT 0.2105 68.0133 21.693 68.0604 ;
		END

		PORT
			 LAYER M4 ;
			RECT 0.2105 90.4133 21.693 90.4604 ;
		END

		PORT
			 LAYER M4 ;
			RECT 0.2105 67.3733 21.693 67.4204 ;
		END

		PORT
			 LAYER M4 ;
			RECT 0.2105 66.7333 21.693 66.7804 ;
		END

		PORT
			 LAYER M4 ;
			RECT 0.2105 66.0933 21.693 66.1404 ;
		END

		PORT
			 LAYER M4 ;
			RECT 0.2105 65.4533 21.693 65.5004 ;
		END

		PORT
			 LAYER M4 ;
			RECT 0.2105 64.8133 21.693 64.8604 ;
		END

		PORT
			 LAYER M4 ;
			RECT 0.2105 64.1733 21.693 64.2204 ;
		END

		PORT
			 LAYER M4 ;
			RECT 0.2105 63.5333 21.693 63.5804 ;
		END

		PORT
			 LAYER M4 ;
			RECT 0.2105 62.8933 21.693 62.9404 ;
		END

		PORT
			 LAYER M4 ;
			RECT 0.2105 62.2533 21.693 62.3004 ;
		END

		PORT
			 LAYER M4 ;
			RECT 0.2105 61.6133 21.693 61.6604 ;
		END

		PORT
			 LAYER M4 ;
			RECT 0.2105 89.7733 21.693 89.8204 ;
		END

		PORT
			 LAYER M4 ;
			RECT 0.2105 60.9733 21.693 61.0204 ;
		END

		PORT
			 LAYER M4 ;
			RECT 0.2105 60.3333 21.693 60.3804 ;
		END

		PORT
			 LAYER M4 ;
			RECT 0.2105 59.6933 21.693 59.7404 ;
		END

		PORT
			 LAYER M4 ;
			RECT 0.2105 59.0533 21.693 59.1004 ;
		END

		PORT
			 LAYER M4 ;
			RECT 0.2105 58.4133 21.693 58.4604 ;
		END

		PORT
			 LAYER M4 ;
			RECT 0.2105 57.7733 21.693 57.8204 ;
		END

		PORT
			 LAYER M4 ;
			RECT 0.2105 57.1333 21.693 57.1804 ;
		END

		PORT
			 LAYER M4 ;
			RECT 0.2105 56.4933 21.693 56.5404 ;
		END

		PORT
			 LAYER M4 ;
			RECT 0.2105 55.8533 21.693 55.9004 ;
		END

		PORT
			 LAYER M4 ;
			RECT 0.2105 55.2133 21.693 55.2604 ;
		END

		PORT
			 LAYER M4 ;
			RECT 0.2105 89.1333 21.693 89.1804 ;
		END

		PORT
			 LAYER M4 ;
			RECT 0.2105 54.5733 21.693 54.6204 ;
		END

		PORT
			 LAYER M4 ;
			RECT 0.2105 53.9333 21.693 53.9804 ;
		END

		PORT
			 LAYER M4 ;
			RECT 0.2105 53.2933 21.693 53.3404 ;
		END

		PORT
			 LAYER M4 ;
			RECT 0.2105 52.6533 21.693 52.7004 ;
		END

		PORT
			 LAYER M4 ;
			RECT 0.2105 52.0133 21.693 52.0604 ;
		END

		PORT
			 LAYER M4 ;
			RECT 0.2105 51.3733 21.693 51.4204 ;
		END

		PORT
			 LAYER M4 ;
			RECT 0.2105 50.7333 21.693 50.7804 ;
		END

		PORT
			 LAYER M4 ;
			RECT 0.2105 88.4933 21.693 88.5404 ;
		END

		PORT
			 LAYER M4 ;
			RECT 0.2105 41.8502 21.693 41.8973 ;
		END

		PORT
			 LAYER M4 ;
			RECT 0.2105 87.8533 21.693 87.9004 ;
		END

		PORT
			 LAYER M4 ;
			RECT 0.2105 41.2102 21.693 41.2573 ;
		END

		PORT
			 LAYER M4 ;
			RECT 0.2105 40.5702 21.693 40.6173 ;
		END

		PORT
			 LAYER M4 ;
			RECT 0.2105 39.9302 21.693 39.9773 ;
		END

		PORT
			 LAYER M4 ;
			RECT 0.2105 39.2902 21.693 39.3373 ;
		END

		PORT
			 LAYER M4 ;
			RECT 0.2105 38.6502 21.693 38.6973 ;
		END

		PORT
			 LAYER M4 ;
			RECT 0.2105 38.0102 21.693 38.0573 ;
		END

		PORT
			 LAYER M4 ;
			RECT 0.2105 37.3702 21.693 37.4173 ;
		END

		PORT
			 LAYER M4 ;
			RECT 0.2105 36.7302 21.693 36.7773 ;
		END

		PORT
			 LAYER M4 ;
			RECT 0.2105 36.0902 21.693 36.1373 ;
		END

		PORT
			 LAYER M4 ;
			RECT 0.2105 35.4502 21.693 35.4973 ;
		END

		PORT
			 LAYER M4 ;
			RECT 0.2105 87.2133 21.693 87.2604 ;
		END

		PORT
			 LAYER M4 ;
			RECT 0.2105 34.8102 21.693 34.8573 ;
		END

		PORT
			 LAYER M4 ;
			RECT 0.2105 34.1702 21.693 34.2173 ;
		END

		PORT
			 LAYER M4 ;
			RECT 0.2105 33.5302 21.693 33.5773 ;
		END

		PORT
			 LAYER M4 ;
			RECT 0.2105 32.8902 21.693 32.9373 ;
		END

		PORT
			 LAYER M4 ;
			RECT 0.2105 32.2502 21.693 32.2973 ;
		END

		PORT
			 LAYER M4 ;
			RECT 0.2105 31.6102 21.693 31.6573 ;
		END

		PORT
			 LAYER M4 ;
			RECT 0.2105 30.9702 21.693 31.0173 ;
		END

		PORT
			 LAYER M4 ;
			RECT 0.2105 30.3302 21.693 30.3773 ;
		END

		PORT
			 LAYER M4 ;
			RECT 0.2105 29.6902 21.693 29.7373 ;
		END

		PORT
			 LAYER M4 ;
			RECT 0.2105 29.0502 21.693 29.0973 ;
		END

		PORT
			 LAYER M4 ;
			RECT 0.2105 86.5733 21.693 86.6204 ;
		END

		PORT
			 LAYER M4 ;
			RECT 0.2105 28.4102 21.693 28.4573 ;
		END

		PORT
			 LAYER M4 ;
			RECT 0.2105 27.7702 21.693 27.8173 ;
		END

		PORT
			 LAYER M4 ;
			RECT 0.2105 27.1302 21.693 27.1773 ;
		END

		PORT
			 LAYER M4 ;
			RECT 0.2105 26.4902 21.693 26.5373 ;
		END

		PORT
			 LAYER M4 ;
			RECT 0.2105 25.8502 21.693 25.8973 ;
		END

		PORT
			 LAYER M4 ;
			RECT 0.2105 25.2102 21.693 25.2573 ;
		END

		PORT
			 LAYER M4 ;
			RECT 0.2105 24.5702 21.693 24.6173 ;
		END

		PORT
			 LAYER M4 ;
			RECT 0.2105 23.9302 21.693 23.9773 ;
		END

		PORT
			 LAYER M4 ;
			RECT 0.2105 23.2902 21.693 23.3373 ;
		END

		PORT
			 LAYER M4 ;
			RECT 0.2105 22.6502 21.693 22.6973 ;
		END

		PORT
			 LAYER M4 ;
			RECT 0.2105 85.9333 21.693 85.9804 ;
		END

		PORT
			 LAYER M4 ;
			RECT 0.2105 22.0102 21.693 22.0573 ;
		END

		PORT
			 LAYER M4 ;
			RECT 0.2105 21.3702 21.693 21.4173 ;
		END

		PORT
			 LAYER M4 ;
			RECT 0.2105 20.7302 21.693 20.7773 ;
		END

		PORT
			 LAYER M4 ;
			RECT 0.2105 20.0902 21.693 20.1373 ;
		END

		PORT
			 LAYER M4 ;
			RECT 0.2105 19.4502 21.693 19.4973 ;
		END

		PORT
			 LAYER M4 ;
			RECT 0.2105 18.8102 21.693 18.8573 ;
		END

		PORT
			 LAYER M4 ;
			RECT 0.2105 18.1702 21.693 18.2173 ;
		END

		PORT
			 LAYER M4 ;
			RECT 0.2105 17.5302 21.693 17.5773 ;
		END

		PORT
			 LAYER M4 ;
			RECT 0.2105 16.8902 21.693 16.9373 ;
		END

		PORT
			 LAYER M4 ;
			RECT 0.2105 16.2502 21.693 16.2973 ;
		END

		PORT
			 LAYER M4 ;
			RECT 0.2105 85.2933 21.693 85.3404 ;
		END

		PORT
			 LAYER M4 ;
			RECT 0.2105 15.6102 21.693 15.6573 ;
		END

		PORT
			 LAYER M4 ;
			RECT 0.2105 14.9702 21.693 15.0173 ;
		END

		PORT
			 LAYER M4 ;
			RECT 0.2105 14.3302 21.693 14.3773 ;
		END

		PORT
			 LAYER M4 ;
			RECT 0.2105 13.6902 21.693 13.7373 ;
		END

		PORT
			 LAYER M4 ;
			RECT 0.2105 13.0502 21.693 13.0973 ;
		END

		PORT
			 LAYER M4 ;
			RECT 0.2105 12.4102 21.693 12.4573 ;
		END

		PORT
			 LAYER M4 ;
			RECT 0.2105 11.7702 21.693 11.8173 ;
		END

		PORT
			 LAYER M4 ;
			RECT 0.2105 11.1302 21.693 11.1773 ;
		END

		PORT
			 LAYER M4 ;
			RECT 0.2105 10.4902 21.693 10.5373 ;
		END

		PORT
			 LAYER M4 ;
			RECT 0.2105 9.8502 21.693 9.8973 ;
		END

		PORT
			 LAYER M4 ;
			RECT 0.2105 84.6533 21.693 84.7004 ;
		END

		PORT
			 LAYER M4 ;
			RECT 0.2105 9.2102 21.693 9.2573 ;
		END

		PORT
			 LAYER M4 ;
			RECT 0.2105 8.5702 21.693 8.6173 ;
		END

		PORT
			 LAYER M4 ;
			RECT 0.2105 7.9302 21.693 7.9773 ;
		END

		PORT
			 LAYER M4 ;
			RECT 0.2105 7.2902 21.693 7.3373 ;
		END

		PORT
			 LAYER M4 ;
			RECT 0.2105 6.6502 21.693 6.6973 ;
		END

		PORT
			 LAYER M4 ;
			RECT 0.2105 6.0102 21.693 6.0573 ;
		END

		PORT
			 LAYER M4 ;
			RECT 0.2105 5.3702 21.693 5.4173 ;
		END

		PORT
			 LAYER M4 ;
			RECT 0.2105 4.7302 21.693 4.7773 ;
		END

		PORT
			 LAYER M4 ;
			RECT 0.2105 4.0902 21.693 4.1373 ;
		END

		PORT
			 LAYER M4 ;
			RECT 0.2105 3.4502 21.693 3.4973 ;
		END

		PORT
			 LAYER M4 ;
			RECT 0.2105 84.0133 21.693 84.0604 ;
		END

		PORT
			 LAYER M4 ;
			RECT 0.2105 2.8102 21.693 2.8573 ;
		END

		PORT
			 LAYER M4 ;
			RECT 0.2105 2.1702 21.693 2.2173 ;
		END

		PORT
			 LAYER M4 ;
			RECT 0.2105 1.5302 21.693 1.5773 ;
		END

		PORT
			 LAYER M4 ;
			RECT 0.2105 0.8902 21.693 0.9373 ;
		END

		PORT
			 LAYER M4 ;
			RECT 0.2105 0.2502 21.693 0.2973 ;
		END

		PORT
			 LAYER M4 ;
			RECT 0.2105 83.3733 21.693 83.4204 ;
		END

		PORT
			 LAYER M4 ;
			RECT 0.2105 82.7333 21.693 82.7804 ;
		END

		PORT
			 LAYER M4 ;
			RECT 0.2105 82.0933 21.693 82.1404 ;
		END

		PORT
			 LAYER M4 ;
			RECT 0.2105 81.4533 21.693 81.5004 ;
		END

		PORT
			 LAYER M4 ;
			RECT 0.2105 80.8133 21.693 80.8604 ;
		END

		PORT
			 LAYER M4 ;
			RECT 0.2105 91.6933 21.693 91.7404 ;
		END

		PORT
			 LAYER M4 ;
			RECT 0.2105 80.1733 21.693 80.2204 ;
		END

		PORT
			 LAYER M4 ;
			RECT 0.2105 79.5333 21.693 79.5804 ;
		END

		PORT
			 LAYER M4 ;
			RECT 0.2105 78.8933 21.693 78.9404 ;
		END

		PORT
			 LAYER M4 ;
			RECT 0.2105 78.2533 21.693 78.3004 ;
		END

		PORT
			 LAYER M4 ;
			RECT 0.2105 77.6133 21.693 77.6604 ;
		END

		PORT
			 LAYER M4 ;
			RECT 0.2105 76.9733 21.693 77.0204 ;
		END

		PORT
			 LAYER M4 ;
			RECT 0.2105 76.3333 21.693 76.3804 ;
		END

		PORT
			 LAYER M4 ;
			RECT 0.2105 75.6933 21.693 75.7404 ;
		END

		PORT
			 LAYER M4 ;
			RECT 0.2105 75.0533 21.693 75.1004 ;
		END

		PORT
			 LAYER M4 ;
			RECT 0.2105 74.4133 21.693 74.4604 ;
		END

		PORT
			 LAYER M4 ;
			RECT 0.2105 91.0533 21.693 91.1004 ;
		END

		PORT
			 LAYER M4 ;
			RECT 0.2105 73.7733 21.693 73.8204 ;
		END

		PORT
			 LAYER M4 ;
			RECT 0.2105 73.1333 21.693 73.1804 ;
		END

		PORT
			 LAYER M4 ;
			RECT 0.2105 72.4933 21.693 72.5404 ;
		END

		PORT
			 LAYER M4 ;
			RECT 0.2105 71.8533 21.693 71.9004 ;
		END

	END VSSE

	PIN WABL
		USE SIGNAL ;
		DIRECTION INPUT ;
		SHAPE ABUTMENT ;
		PORT
			 LAYER M2 ;
			RECT 0.0098 49.92 0.0481 49.9576 ;
			 LAYER M3 ;
			RECT 0.0098 49.8573 0.0481 49.9576 ;
			 LAYER V2 ;
			RECT 0.0215 49.9322 0.0364 49.9447 ;
		END

		ANTENNAGATEAREA 0.00027817 ;
		ANTENNADIFFAREA 0.00194719 ;
		ANTENNAPARTIALMETALAREA 0.00195671 ;
	END WABL

	PIN WABLM[0]
		USE SIGNAL ;
		DIRECTION INPUT ;
		SHAPE ABUTMENT ;
		PORT
			 LAYER M2 ;
			RECT 0.0714 42.7796 0.1097 42.8173 ;
			 LAYER M3 ;
			RECT 0.0714 42.7796 0.1097 42.88 ;
			 LAYER V2 ;
			RECT 0.0831 42.7918 0.098 42.8043 ;
		END

		ANTENNAGATEAREA 0.00027817 ;
		ANTENNADIFFAREA 0.00194719 ;
		ANTENNAPARTIALMETALAREA 0.00195671 ;
	END WABLM[0]

	PIN WABLM[1]
		USE SIGNAL ;
		DIRECTION INPUT ;
		SHAPE ABUTMENT ;
		PORT
			 LAYER M3 ;
			RECT 0.0714 47.2973 0.1097 47.3976 ;
		END

		ANTENNAGATEAREA 0.00027817 ;
		ANTENNADIFFAREA 0.00194719 ;
		ANTENNAPARTIALMETALAREA 0.00195671 ;
	END WABLM[1]

	PIN WENY[0]
		USE SIGNAL ;
		DIRECTION OUTPUT ;
		SHAPE ABUTMENT ;
		PORT
			 LAYER M2 ;
			RECT 0.0098 1.2424 0.0481 1.3427 ;
			 LAYER M3 ;
			RECT 0.0098 1.2424 0.0481 1.3427 ;
			 LAYER V2 ;
			RECT 0.021 1.2553 0.0359 1.2678 ;
		END

		ANTENNADIFFAREA 0.00194719 ;
		ANTENNAPARTIALMETALAREA 0.00195671 ;
	END WENY[0]

	PIN WENY[10]
		USE SIGNAL ;
		DIRECTION OUTPUT ;
		SHAPE ABUTMENT ;
		PORT
			 LAYER M2 ;
			RECT 0.0098 14.0424 0.0481 14.1427 ;
			 LAYER M3 ;
			RECT 0.0098 14.0424 0.0481 14.1427 ;
			 LAYER V2 ;
			RECT 0.021 14.0553 0.0359 14.0678 ;
		END

		ANTENNADIFFAREA 0.00194719 ;
		ANTENNAPARTIALMETALAREA 0.00195671 ;
	END WENY[10]

	PIN WENY[11]
		USE SIGNAL ;
		DIRECTION OUTPUT ;
		SHAPE ABUTMENT ;
		PORT
			 LAYER M2 ;
			RECT 0.0098 15.3224 0.0481 15.4227 ;
			 LAYER M3 ;
			RECT 0.0098 15.3224 0.0481 15.4227 ;
			 LAYER V2 ;
			RECT 0.021 15.3353 0.0359 15.3478 ;
		END

		ANTENNADIFFAREA 0.00194719 ;
		ANTENNAPARTIALMETALAREA 0.00195671 ;
	END WENY[11]

	PIN WENY[12]
		USE SIGNAL ;
		DIRECTION OUTPUT ;
		SHAPE ABUTMENT ;
		PORT
			 LAYER M2 ;
			RECT 0.0098 16.6024 0.0481 16.7027 ;
			 LAYER M3 ;
			RECT 0.0098 16.6024 0.0481 16.7027 ;
			 LAYER V2 ;
			RECT 0.021 16.6153 0.0359 16.6278 ;
		END

		ANTENNADIFFAREA 0.00194719 ;
		ANTENNAPARTIALMETALAREA 0.00195671 ;
	END WENY[12]

	PIN WENY[13]
		USE SIGNAL ;
		DIRECTION OUTPUT ;
		SHAPE ABUTMENT ;
		PORT
			 LAYER M2 ;
			RECT 0.0098 17.8824 0.0481 17.9827 ;
			 LAYER M3 ;
			RECT 0.0098 17.8824 0.0481 17.9827 ;
			 LAYER V2 ;
			RECT 0.021 17.8953 0.0359 17.9078 ;
		END

		ANTENNADIFFAREA 0.00194719 ;
		ANTENNAPARTIALMETALAREA 0.00195671 ;
	END WENY[13]

	PIN WENY[14]
		USE SIGNAL ;
		DIRECTION OUTPUT ;
		SHAPE ABUTMENT ;
		PORT
			 LAYER M2 ;
			RECT 0.0098 19.1624 0.0481 19.2627 ;
			 LAYER M3 ;
			RECT 0.0098 19.1624 0.0481 19.2627 ;
			 LAYER V2 ;
			RECT 0.021 19.1753 0.0359 19.1878 ;
		END

		ANTENNADIFFAREA 0.00194719 ;
		ANTENNAPARTIALMETALAREA 0.00195671 ;
	END WENY[14]

	PIN WENY[15]
		USE SIGNAL ;
		DIRECTION OUTPUT ;
		SHAPE ABUTMENT ;
		PORT
			 LAYER M2 ;
			RECT 0.0098 20.4424 0.0481 20.5427 ;
			 LAYER M3 ;
			RECT 0.0098 20.4424 0.0481 20.5427 ;
			 LAYER V2 ;
			RECT 0.021 20.4553 0.0359 20.4678 ;
		END

		ANTENNADIFFAREA 0.00194719 ;
		ANTENNAPARTIALMETALAREA 0.00195671 ;
	END WENY[15]

	PIN WENY[16]
		USE SIGNAL ;
		DIRECTION OUTPUT ;
		SHAPE ABUTMENT ;
		PORT
			 LAYER M2 ;
			RECT 0.0098 21.7224 0.0481 21.8227 ;
			 LAYER M3 ;
			RECT 0.0098 21.7224 0.0481 21.8227 ;
			 LAYER V2 ;
			RECT 0.021 21.7353 0.0359 21.7478 ;
		END

		ANTENNADIFFAREA 0.00194719 ;
		ANTENNAPARTIALMETALAREA 0.00195671 ;
	END WENY[16]

	PIN WENY[17]
		USE SIGNAL ;
		DIRECTION OUTPUT ;
		SHAPE ABUTMENT ;
		PORT
			 LAYER M2 ;
			RECT 0.0098 23.0024 0.0481 23.1027 ;
			 LAYER M3 ;
			RECT 0.0098 23.0024 0.0481 23.1027 ;
			 LAYER V2 ;
			RECT 0.021 23.0153 0.0359 23.0278 ;
		END

		ANTENNADIFFAREA 0.00194719 ;
		ANTENNAPARTIALMETALAREA 0.00195671 ;
	END WENY[17]

	PIN WENY[18]
		USE SIGNAL ;
		DIRECTION OUTPUT ;
		SHAPE ABUTMENT ;
		PORT
			 LAYER M2 ;
			RECT 0.0098 24.2824 0.0481 24.3827 ;
			 LAYER M3 ;
			RECT 0.0098 24.2824 0.0481 24.3827 ;
			 LAYER V2 ;
			RECT 0.021 24.2953 0.0359 24.3078 ;
		END

		ANTENNADIFFAREA 0.00194719 ;
		ANTENNAPARTIALMETALAREA 0.00195671 ;
	END WENY[18]

	PIN WENY[19]
		USE SIGNAL ;
		DIRECTION OUTPUT ;
		SHAPE ABUTMENT ;
		PORT
			 LAYER M2 ;
			RECT 0.0098 25.5624 0.0481 25.6627 ;
			 LAYER M3 ;
			RECT 0.0098 25.5624 0.0481 25.6627 ;
			 LAYER V2 ;
			RECT 0.021 25.5753 0.0359 25.5878 ;
		END

		ANTENNADIFFAREA 0.00194719 ;
		ANTENNAPARTIALMETALAREA 0.00195671 ;
	END WENY[19]

	PIN WENY[1]
		USE SIGNAL ;
		DIRECTION OUTPUT ;
		SHAPE ABUTMENT ;
		PORT
			 LAYER M2 ;
			RECT 0.0098 2.5224 0.0481 2.6227 ;
			 LAYER M3 ;
			RECT 0.0098 2.5224 0.0481 2.6227 ;
			 LAYER V2 ;
			RECT 0.021 2.5353 0.0359 2.5478 ;
		END

		ANTENNADIFFAREA 0.00194719 ;
		ANTENNAPARTIALMETALAREA 0.00195671 ;
	END WENY[1]

	PIN WENY[20]
		USE SIGNAL ;
		DIRECTION OUTPUT ;
		SHAPE ABUTMENT ;
		PORT
			 LAYER M2 ;
			RECT 0.0098 26.8424 0.0481 26.9427 ;
			 LAYER M3 ;
			RECT 0.0098 26.8424 0.0481 26.9427 ;
			 LAYER V2 ;
			RECT 0.021 26.8553 0.0359 26.8678 ;
		END

		ANTENNADIFFAREA 0.00194719 ;
		ANTENNAPARTIALMETALAREA 0.00195671 ;
	END WENY[20]

	PIN WENY[21]
		USE SIGNAL ;
		DIRECTION OUTPUT ;
		SHAPE ABUTMENT ;
		PORT
			 LAYER M2 ;
			RECT 0.0098 28.1224 0.0481 28.2227 ;
			 LAYER M3 ;
			RECT 0.0098 28.1224 0.0481 28.2227 ;
			 LAYER V2 ;
			RECT 0.021 28.1353 0.0359 28.1478 ;
		END

		ANTENNADIFFAREA 0.00194719 ;
		ANTENNAPARTIALMETALAREA 0.00195671 ;
	END WENY[21]

	PIN WENY[22]
		USE SIGNAL ;
		DIRECTION OUTPUT ;
		SHAPE ABUTMENT ;
		PORT
			 LAYER M2 ;
			RECT 0.0098 29.4024 0.0481 29.5027 ;
			 LAYER M3 ;
			RECT 0.0098 29.4024 0.0481 29.5027 ;
			 LAYER V2 ;
			RECT 0.021 29.4153 0.0359 29.4278 ;
		END

		ANTENNADIFFAREA 0.00194719 ;
		ANTENNAPARTIALMETALAREA 0.00195671 ;
	END WENY[22]

	PIN WENY[23]
		USE SIGNAL ;
		DIRECTION OUTPUT ;
		SHAPE ABUTMENT ;
		PORT
			 LAYER M2 ;
			RECT 0.0098 30.6824 0.0481 30.7827 ;
			 LAYER M3 ;
			RECT 0.0098 30.6824 0.0481 30.7827 ;
			 LAYER V2 ;
			RECT 0.021 30.6953 0.0359 30.7078 ;
		END

		ANTENNADIFFAREA 0.00194719 ;
		ANTENNAPARTIALMETALAREA 0.00195671 ;
	END WENY[23]

	PIN WENY[24]
		USE SIGNAL ;
		DIRECTION OUTPUT ;
		SHAPE ABUTMENT ;
		PORT
			 LAYER M2 ;
			RECT 0.0098 31.9624 0.0481 32.0627 ;
			 LAYER M3 ;
			RECT 0.0098 31.9624 0.0481 32.0627 ;
			 LAYER V2 ;
			RECT 0.021 31.9753 0.0359 31.9878 ;
		END

		ANTENNADIFFAREA 0.00194719 ;
		ANTENNAPARTIALMETALAREA 0.00195671 ;
	END WENY[24]

	PIN WENY[25]
		USE SIGNAL ;
		DIRECTION OUTPUT ;
		SHAPE ABUTMENT ;
		PORT
			 LAYER M2 ;
			RECT 0.0098 33.2424 0.0481 33.3427 ;
			 LAYER M3 ;
			RECT 0.0098 33.2424 0.0481 33.3427 ;
			 LAYER V2 ;
			RECT 0.021 33.2553 0.0359 33.2678 ;
		END

		ANTENNADIFFAREA 0.00194719 ;
		ANTENNAPARTIALMETALAREA 0.00195671 ;
	END WENY[25]

	PIN WENY[26]
		USE SIGNAL ;
		DIRECTION OUTPUT ;
		SHAPE ABUTMENT ;
		PORT
			 LAYER M2 ;
			RECT 0.0098 34.5224 0.0481 34.6227 ;
			 LAYER M3 ;
			RECT 0.0098 34.5224 0.0481 34.6227 ;
			 LAYER V2 ;
			RECT 0.021 34.5353 0.0359 34.5478 ;
		END

		ANTENNADIFFAREA 0.00194719 ;
		ANTENNAPARTIALMETALAREA 0.00195671 ;
	END WENY[26]

	PIN WENY[27]
		USE SIGNAL ;
		DIRECTION OUTPUT ;
		SHAPE ABUTMENT ;
		PORT
			 LAYER M2 ;
			RECT 0.0098 35.8024 0.0481 35.9027 ;
			 LAYER M3 ;
			RECT 0.0098 35.8024 0.0481 35.9027 ;
			 LAYER V2 ;
			RECT 0.021 35.8153 0.0359 35.8278 ;
		END

		ANTENNADIFFAREA 0.00194719 ;
		ANTENNAPARTIALMETALAREA 0.00195671 ;
	END WENY[27]

	PIN WENY[28]
		USE SIGNAL ;
		DIRECTION OUTPUT ;
		SHAPE ABUTMENT ;
		PORT
			 LAYER M2 ;
			RECT 0.0098 37.0824 0.0481 37.1827 ;
			 LAYER M3 ;
			RECT 0.0098 37.0824 0.0481 37.1827 ;
			 LAYER V2 ;
			RECT 0.021 37.0953 0.0359 37.1078 ;
		END

		ANTENNADIFFAREA 0.00194719 ;
		ANTENNAPARTIALMETALAREA 0.00195671 ;
	END WENY[28]

	PIN WENY[29]
		USE SIGNAL ;
		DIRECTION OUTPUT ;
		SHAPE ABUTMENT ;
		PORT
			 LAYER M2 ;
			RECT 0.0098 38.3624 0.0481 38.4627 ;
			 LAYER M3 ;
			RECT 0.0098 38.3624 0.0481 38.4627 ;
			 LAYER V2 ;
			RECT 0.021 38.3753 0.0359 38.3878 ;
		END

		ANTENNADIFFAREA 0.00194719 ;
		ANTENNAPARTIALMETALAREA 0.00195671 ;
	END WENY[29]

	PIN WENY[2]
		USE SIGNAL ;
		DIRECTION OUTPUT ;
		SHAPE ABUTMENT ;
		PORT
			 LAYER M2 ;
			RECT 0.0098 3.8024 0.0481 3.9027 ;
			 LAYER M3 ;
			RECT 0.0098 3.8024 0.0481 3.9027 ;
			 LAYER V2 ;
			RECT 0.021 3.8153 0.0359 3.8278 ;
		END

		ANTENNADIFFAREA 0.00194719 ;
		ANTENNAPARTIALMETALAREA 0.00195671 ;
	END WENY[2]

	PIN WENY[30]
		USE SIGNAL ;
		DIRECTION OUTPUT ;
		SHAPE ABUTMENT ;
		PORT
			 LAYER M2 ;
			RECT 0.0098 39.6424 0.0481 39.7427 ;
			 LAYER M3 ;
			RECT 0.0098 39.6424 0.0481 39.7427 ;
			 LAYER V2 ;
			RECT 0.021 39.6553 0.0359 39.6678 ;
		END

		ANTENNADIFFAREA 0.00194719 ;
		ANTENNAPARTIALMETALAREA 0.00195671 ;
	END WENY[30]

	PIN WENY[31]
		USE SIGNAL ;
		DIRECTION OUTPUT ;
		SHAPE ABUTMENT ;
		PORT
			 LAYER M2 ;
			RECT 0.0098 40.9224 0.0481 41.0227 ;
			 LAYER M3 ;
			RECT 0.0098 40.9224 0.0481 41.0227 ;
			 LAYER V2 ;
			RECT 0.021 40.9353 0.0359 40.9478 ;
		END

		ANTENNADIFFAREA 0.00194719 ;
		ANTENNAPARTIALMETALAREA 0.00195671 ;
	END WENY[31]

	PIN WENY[32]
		USE SIGNAL ;
		DIRECTION OUTPUT ;
		SHAPE ABUTMENT ;
		PORT
			 LAYER M2 ;
			RECT 0.0098 42.2024 0.0481 42.3027 ;
			 LAYER M3 ;
			RECT 0.0098 42.2024 0.0481 42.3027 ;
			 LAYER V2 ;
			RECT 0.021 42.2153 0.0359 42.2278 ;
		END

		ANTENNADIFFAREA 0.00194719 ;
		ANTENNAPARTIALMETALAREA 0.00195671 ;
	END WENY[32]

	PIN WENY[33]
		USE SIGNAL ;
		DIRECTION OUTPUT ;
		SHAPE ABUTMENT ;
		PORT
			 LAYER M2 ;
			RECT 0.0098 50.3278 0.0481 50.4282 ;
			 LAYER M3 ;
			RECT 0.0098 50.3278 0.0481 50.4282 ;
			 LAYER V2 ;
			RECT 0.021 50.4027 0.0359 50.4153 ;
		END

		ANTENNADIFFAREA 0.00194719 ;
		ANTENNAPARTIALMETALAREA 0.00195671 ;
	END WENY[33]

	PIN WENY[34]
		USE SIGNAL ;
		DIRECTION OUTPUT ;
		SHAPE ABUTMENT ;
		PORT
			 LAYER M2 ;
			RECT 0.0098 51.6078 0.0481 51.7082 ;
			 LAYER M3 ;
			RECT 0.0098 51.6078 0.0481 51.7082 ;
			 LAYER V2 ;
			RECT 0.021 51.6827 0.0359 51.6953 ;
		END

		ANTENNADIFFAREA 0.00194719 ;
		ANTENNAPARTIALMETALAREA 0.00195671 ;
	END WENY[34]

	PIN WENY[35]
		USE SIGNAL ;
		DIRECTION OUTPUT ;
		SHAPE ABUTMENT ;
		PORT
			 LAYER M2 ;
			RECT 0.0098 52.8878 0.0481 52.9882 ;
			 LAYER M3 ;
			RECT 0.0098 52.8878 0.0481 52.9882 ;
			 LAYER V2 ;
			RECT 0.021 52.9627 0.0359 52.9753 ;
		END

		ANTENNADIFFAREA 0.00194719 ;
		ANTENNAPARTIALMETALAREA 0.00195671 ;
	END WENY[35]

	PIN WENY[36]
		USE SIGNAL ;
		DIRECTION OUTPUT ;
		SHAPE ABUTMENT ;
		PORT
			 LAYER M2 ;
			RECT 0.0098 54.1678 0.0481 54.2682 ;
			 LAYER M3 ;
			RECT 0.0098 54.1678 0.0481 54.2682 ;
			 LAYER V2 ;
			RECT 0.021 54.2427 0.0359 54.2553 ;
		END

		ANTENNADIFFAREA 0.00194719 ;
		ANTENNAPARTIALMETALAREA 0.00195671 ;
	END WENY[36]

	PIN WENY[37]
		USE SIGNAL ;
		DIRECTION OUTPUT ;
		SHAPE ABUTMENT ;
		PORT
			 LAYER M2 ;
			RECT 0.0098 55.4478 0.0481 55.5482 ;
			 LAYER M3 ;
			RECT 0.0098 55.4478 0.0481 55.5482 ;
			 LAYER V2 ;
			RECT 0.021 55.5227 0.0359 55.5353 ;
		END

		ANTENNADIFFAREA 0.00194719 ;
		ANTENNAPARTIALMETALAREA 0.00195671 ;
	END WENY[37]

	PIN WENY[38]
		USE SIGNAL ;
		DIRECTION OUTPUT ;
		SHAPE ABUTMENT ;
		PORT
			 LAYER M2 ;
			RECT 0.0098 56.7278 0.0481 56.8282 ;
			 LAYER M3 ;
			RECT 0.0098 56.7278 0.0481 56.8282 ;
			 LAYER V2 ;
			RECT 0.021 56.8027 0.0359 56.8153 ;
		END

		ANTENNADIFFAREA 0.00194719 ;
		ANTENNAPARTIALMETALAREA 0.00195671 ;
	END WENY[38]

	PIN WENY[39]
		USE SIGNAL ;
		DIRECTION OUTPUT ;
		SHAPE ABUTMENT ;
		PORT
			 LAYER M2 ;
			RECT 0.0098 58.0078 0.0481 58.1082 ;
			 LAYER M3 ;
			RECT 0.0098 58.0078 0.0481 58.1082 ;
			 LAYER V2 ;
			RECT 0.021 58.0827 0.0359 58.0953 ;
		END

		ANTENNADIFFAREA 0.00194719 ;
		ANTENNAPARTIALMETALAREA 0.00195671 ;
	END WENY[39]

	PIN WENY[3]
		USE SIGNAL ;
		DIRECTION OUTPUT ;
		SHAPE ABUTMENT ;
		PORT
			 LAYER M2 ;
			RECT 0.0098 5.0824 0.0481 5.1827 ;
			 LAYER M3 ;
			RECT 0.0098 5.0824 0.0481 5.1827 ;
			 LAYER V2 ;
			RECT 0.021 5.0953 0.0359 5.1078 ;
		END

		ANTENNADIFFAREA 0.00194719 ;
		ANTENNAPARTIALMETALAREA 0.00195671 ;
	END WENY[3]

	PIN WENY[40]
		USE SIGNAL ;
		DIRECTION OUTPUT ;
		SHAPE ABUTMENT ;
		PORT
			 LAYER M2 ;
			RECT 0.0098 59.2878 0.0481 59.3882 ;
			 LAYER M3 ;
			RECT 0.0098 59.2878 0.0481 59.3882 ;
			 LAYER V2 ;
			RECT 0.021 59.3627 0.0359 59.3753 ;
		END

		ANTENNADIFFAREA 0.00194719 ;
		ANTENNAPARTIALMETALAREA 0.00195671 ;
	END WENY[40]

	PIN WENY[41]
		USE SIGNAL ;
		DIRECTION OUTPUT ;
		SHAPE ABUTMENT ;
		PORT
			 LAYER M2 ;
			RECT 0.0098 60.5678 0.0481 60.6682 ;
			 LAYER M3 ;
			RECT 0.0098 60.5678 0.0481 60.6682 ;
			 LAYER V2 ;
			RECT 0.021 60.6427 0.0359 60.6553 ;
		END

		ANTENNADIFFAREA 0.00194719 ;
		ANTENNAPARTIALMETALAREA 0.00195671 ;
	END WENY[41]

	PIN WENY[42]
		USE SIGNAL ;
		DIRECTION OUTPUT ;
		SHAPE ABUTMENT ;
		PORT
			 LAYER M2 ;
			RECT 0.0098 61.8478 0.0481 61.9482 ;
			 LAYER M3 ;
			RECT 0.0098 61.8478 0.0481 61.9482 ;
			 LAYER V2 ;
			RECT 0.021 61.9227 0.0359 61.9353 ;
		END

		ANTENNADIFFAREA 0.00194719 ;
		ANTENNAPARTIALMETALAREA 0.00195671 ;
	END WENY[42]

	PIN WENY[43]
		USE SIGNAL ;
		DIRECTION OUTPUT ;
		SHAPE ABUTMENT ;
		PORT
			 LAYER M2 ;
			RECT 0.0098 63.1278 0.0481 63.2282 ;
			 LAYER M3 ;
			RECT 0.0098 63.1278 0.0481 63.2282 ;
			 LAYER V2 ;
			RECT 0.021 63.2027 0.0359 63.2153 ;
		END

		ANTENNADIFFAREA 0.00194719 ;
		ANTENNAPARTIALMETALAREA 0.00195671 ;
	END WENY[43]

	PIN WENY[44]
		USE SIGNAL ;
		DIRECTION OUTPUT ;
		SHAPE ABUTMENT ;
		PORT
			 LAYER M2 ;
			RECT 0.0098 64.4078 0.0481 64.5082 ;
			 LAYER M3 ;
			RECT 0.0098 64.4078 0.0481 64.5082 ;
			 LAYER V2 ;
			RECT 0.021 64.4827 0.0359 64.4953 ;
		END

		ANTENNADIFFAREA 0.00194719 ;
		ANTENNAPARTIALMETALAREA 0.00195671 ;
	END WENY[44]

	PIN WENY[45]
		USE SIGNAL ;
		DIRECTION OUTPUT ;
		SHAPE ABUTMENT ;
		PORT
			 LAYER M2 ;
			RECT 0.0098 65.6878 0.0481 65.7882 ;
			 LAYER M3 ;
			RECT 0.0098 65.6878 0.0481 65.7882 ;
			 LAYER V2 ;
			RECT 0.021 65.7627 0.0359 65.7753 ;
		END

		ANTENNADIFFAREA 0.00194719 ;
		ANTENNAPARTIALMETALAREA 0.00195671 ;
	END WENY[45]

	PIN WENY[46]
		USE SIGNAL ;
		DIRECTION OUTPUT ;
		SHAPE ABUTMENT ;
		PORT
			 LAYER M2 ;
			RECT 0.0098 66.9678 0.0481 67.0682 ;
			 LAYER M3 ;
			RECT 0.0098 66.9678 0.0481 67.0682 ;
			 LAYER V2 ;
			RECT 0.021 67.0427 0.0359 67.0553 ;
		END

		ANTENNADIFFAREA 0.00194719 ;
		ANTENNAPARTIALMETALAREA 0.00195671 ;
	END WENY[46]

	PIN WENY[47]
		USE SIGNAL ;
		DIRECTION OUTPUT ;
		SHAPE ABUTMENT ;
		PORT
			 LAYER M2 ;
			RECT 0.0098 68.2478 0.0481 68.3482 ;
			 LAYER M3 ;
			RECT 0.0098 68.2478 0.0481 68.3482 ;
			 LAYER V2 ;
			RECT 0.021 68.3227 0.0359 68.3353 ;
		END

		ANTENNADIFFAREA 0.00194719 ;
		ANTENNAPARTIALMETALAREA 0.00195671 ;
	END WENY[47]

	PIN WENY[48]
		USE SIGNAL ;
		DIRECTION OUTPUT ;
		SHAPE ABUTMENT ;
		PORT
			 LAYER M2 ;
			RECT 0.0098 69.5278 0.0481 69.6282 ;
			 LAYER M3 ;
			RECT 0.0098 69.5278 0.0481 69.6282 ;
			 LAYER V2 ;
			RECT 0.021 69.6027 0.0359 69.6153 ;
		END

		ANTENNADIFFAREA 0.00194719 ;
		ANTENNAPARTIALMETALAREA 0.00195671 ;
	END WENY[48]

	PIN WENY[49]
		USE SIGNAL ;
		DIRECTION OUTPUT ;
		SHAPE ABUTMENT ;
		PORT
			 LAYER M2 ;
			RECT 0.0098 70.8078 0.0481 70.9082 ;
			 LAYER M3 ;
			RECT 0.0098 70.8078 0.0481 70.9082 ;
			 LAYER V2 ;
			RECT 0.021 70.8827 0.0359 70.8953 ;
		END

		ANTENNADIFFAREA 0.00194719 ;
		ANTENNAPARTIALMETALAREA 0.00195671 ;
	END WENY[49]

	PIN WENY[4]
		USE SIGNAL ;
		DIRECTION OUTPUT ;
		SHAPE ABUTMENT ;
		PORT
			 LAYER M2 ;
			RECT 0.0098 6.3624 0.0481 6.4627 ;
			 LAYER M3 ;
			RECT 0.0098 6.3624 0.0481 6.4627 ;
			 LAYER V2 ;
			RECT 0.021 6.3753 0.0359 6.3878 ;
		END

		ANTENNADIFFAREA 0.00194719 ;
		ANTENNAPARTIALMETALAREA 0.00195671 ;
	END WENY[4]

	PIN WENY[50]
		USE SIGNAL ;
		DIRECTION OUTPUT ;
		SHAPE ABUTMENT ;
		PORT
			 LAYER M2 ;
			RECT 0.0098 72.0878 0.0481 72.1882 ;
			 LAYER M3 ;
			RECT 0.0098 72.0878 0.0481 72.1882 ;
			 LAYER V2 ;
			RECT 0.021 72.1627 0.0359 72.1753 ;
		END

		ANTENNADIFFAREA 0.00194719 ;
		ANTENNAPARTIALMETALAREA 0.00195671 ;
	END WENY[50]

	PIN WENY[51]
		USE SIGNAL ;
		DIRECTION OUTPUT ;
		SHAPE ABUTMENT ;
		PORT
			 LAYER M2 ;
			RECT 0.0098 73.3678 0.0481 73.4682 ;
			 LAYER M3 ;
			RECT 0.0098 73.3678 0.0481 73.4682 ;
			 LAYER V2 ;
			RECT 0.021 73.4427 0.0359 73.4553 ;
		END

		ANTENNADIFFAREA 0.00194719 ;
		ANTENNAPARTIALMETALAREA 0.00195671 ;
	END WENY[51]

	PIN WENY[52]
		USE SIGNAL ;
		DIRECTION OUTPUT ;
		SHAPE ABUTMENT ;
		PORT
			 LAYER M2 ;
			RECT 0.0098 74.6478 0.0481 74.7482 ;
			 LAYER M3 ;
			RECT 0.0098 74.6478 0.0481 74.7482 ;
			 LAYER V2 ;
			RECT 0.021 74.7227 0.0359 74.7353 ;
		END

		ANTENNADIFFAREA 0.00194719 ;
		ANTENNAPARTIALMETALAREA 0.00195671 ;
	END WENY[52]

	PIN WENY[53]
		USE SIGNAL ;
		DIRECTION OUTPUT ;
		SHAPE ABUTMENT ;
		PORT
			 LAYER M2 ;
			RECT 0.0098 75.9278 0.0481 76.0282 ;
			 LAYER M3 ;
			RECT 0.0098 75.9278 0.0481 76.0282 ;
			 LAYER V2 ;
			RECT 0.021 76.0027 0.0359 76.0153 ;
		END

		ANTENNADIFFAREA 0.00194719 ;
		ANTENNAPARTIALMETALAREA 0.00195671 ;
	END WENY[53]

	PIN WENY[54]
		USE SIGNAL ;
		DIRECTION OUTPUT ;
		SHAPE ABUTMENT ;
		PORT
			 LAYER M2 ;
			RECT 0.0098 77.2078 0.0481 77.3082 ;
			 LAYER M3 ;
			RECT 0.0098 77.2078 0.0481 77.3082 ;
			 LAYER V2 ;
			RECT 0.021 77.2827 0.0359 77.2953 ;
		END

		ANTENNADIFFAREA 0.00194719 ;
		ANTENNAPARTIALMETALAREA 0.00195671 ;
	END WENY[54]

	PIN WENY[55]
		USE SIGNAL ;
		DIRECTION OUTPUT ;
		SHAPE ABUTMENT ;
		PORT
			 LAYER M2 ;
			RECT 0.0098 78.4878 0.0481 78.5882 ;
			 LAYER M3 ;
			RECT 0.0098 78.4878 0.0481 78.5882 ;
			 LAYER V2 ;
			RECT 0.021 78.5627 0.0359 78.5753 ;
		END

		ANTENNADIFFAREA 0.00194719 ;
		ANTENNAPARTIALMETALAREA 0.00195671 ;
	END WENY[55]

	PIN WENY[56]
		USE SIGNAL ;
		DIRECTION OUTPUT ;
		SHAPE ABUTMENT ;
		PORT
			 LAYER M2 ;
			RECT 0.0098 79.7678 0.0481 79.8682 ;
			 LAYER M3 ;
			RECT 0.0098 79.7678 0.0481 79.8682 ;
			 LAYER V2 ;
			RECT 0.021 79.8427 0.0359 79.8553 ;
		END

		ANTENNADIFFAREA 0.00194719 ;
		ANTENNAPARTIALMETALAREA 0.00195671 ;
	END WENY[56]

	PIN WENY[57]
		USE SIGNAL ;
		DIRECTION OUTPUT ;
		SHAPE ABUTMENT ;
		PORT
			 LAYER M2 ;
			RECT 0.0098 81.0478 0.0481 81.1482 ;
			 LAYER M3 ;
			RECT 0.0098 81.0478 0.0481 81.1482 ;
			 LAYER V2 ;
			RECT 0.021 81.1227 0.0359 81.1353 ;
		END

		ANTENNADIFFAREA 0.00194719 ;
		ANTENNAPARTIALMETALAREA 0.00195671 ;
	END WENY[57]

	PIN WENY[58]
		USE SIGNAL ;
		DIRECTION OUTPUT ;
		SHAPE ABUTMENT ;
		PORT
			 LAYER M2 ;
			RECT 0.0098 82.3278 0.0481 82.4282 ;
			 LAYER M3 ;
			RECT 0.0098 82.3278 0.0481 82.4282 ;
			 LAYER V2 ;
			RECT 0.021 82.4027 0.0359 82.4153 ;
		END

		ANTENNADIFFAREA 0.00194719 ;
		ANTENNAPARTIALMETALAREA 0.00195671 ;
	END WENY[58]

	PIN WENY[59]
		USE SIGNAL ;
		DIRECTION OUTPUT ;
		SHAPE ABUTMENT ;
		PORT
			 LAYER M2 ;
			RECT 0.0098 83.6078 0.0481 83.7082 ;
			 LAYER M3 ;
			RECT 0.0098 83.6078 0.0481 83.7082 ;
			 LAYER V2 ;
			RECT 0.021 83.6827 0.0359 83.6953 ;
		END

		ANTENNADIFFAREA 0.00194719 ;
		ANTENNAPARTIALMETALAREA 0.00195671 ;
	END WENY[59]

	PIN WENY[5]
		USE SIGNAL ;
		DIRECTION OUTPUT ;
		SHAPE ABUTMENT ;
		PORT
			 LAYER M2 ;
			RECT 0.0098 7.6424 0.0481 7.7427 ;
			 LAYER M3 ;
			RECT 0.0098 7.6424 0.0481 7.7427 ;
			 LAYER V2 ;
			RECT 0.021 7.6553 0.0359 7.6678 ;
		END

		ANTENNADIFFAREA 0.00194719 ;
		ANTENNAPARTIALMETALAREA 0.00195671 ;
	END WENY[5]

	PIN WENY[60]
		USE SIGNAL ;
		DIRECTION OUTPUT ;
		SHAPE ABUTMENT ;
		PORT
			 LAYER M2 ;
			RECT 0.0098 84.8878 0.0481 84.9882 ;
			 LAYER M3 ;
			RECT 0.0098 84.8878 0.0481 84.9882 ;
			 LAYER V2 ;
			RECT 0.021 84.9627 0.0359 84.9753 ;
		END

		ANTENNADIFFAREA 0.00194719 ;
		ANTENNAPARTIALMETALAREA 0.00195671 ;
	END WENY[60]

	PIN WENY[61]
		USE SIGNAL ;
		DIRECTION OUTPUT ;
		SHAPE ABUTMENT ;
		PORT
			 LAYER M2 ;
			RECT 0.0098 86.1678 0.0481 86.2682 ;
			 LAYER M3 ;
			RECT 0.0098 86.1678 0.0481 86.2682 ;
			 LAYER V2 ;
			RECT 0.021 86.2427 0.0359 86.2553 ;
		END

		ANTENNADIFFAREA 0.00194719 ;
		ANTENNAPARTIALMETALAREA 0.00195671 ;
	END WENY[61]

	PIN WENY[62]
		USE SIGNAL ;
		DIRECTION OUTPUT ;
		SHAPE ABUTMENT ;
		PORT
			 LAYER M2 ;
			RECT 0.0098 87.4478 0.0481 87.5482 ;
			 LAYER M3 ;
			RECT 0.0098 87.4478 0.0481 87.5482 ;
			 LAYER V2 ;
			RECT 0.021 87.5227 0.0359 87.5353 ;
		END

		ANTENNADIFFAREA 0.00194719 ;
		ANTENNAPARTIALMETALAREA 0.00195671 ;
	END WENY[62]

	PIN WENY[63]
		USE SIGNAL ;
		DIRECTION OUTPUT ;
		SHAPE ABUTMENT ;
		PORT
			 LAYER M2 ;
			RECT 0.0098 88.7278 0.0481 88.8282 ;
			 LAYER M3 ;
			RECT 0.0098 88.7278 0.0481 88.8282 ;
			 LAYER V2 ;
			RECT 0.021 88.8027 0.0359 88.8153 ;
		END

		ANTENNADIFFAREA 0.00194719 ;
		ANTENNAPARTIALMETALAREA 0.00195671 ;
	END WENY[63]

	PIN WENY[64]
		USE SIGNAL ;
		DIRECTION OUTPUT ;
		SHAPE ABUTMENT ;
		PORT
			 LAYER M2 ;
			RECT 0.0098 90.0078 0.0481 90.1082 ;
			 LAYER M3 ;
			RECT 0.0098 90.0078 0.0481 90.1082 ;
			 LAYER V2 ;
			RECT 0.021 90.0827 0.0359 90.0953 ;
		END

		ANTENNADIFFAREA 0.00194719 ;
		ANTENNAPARTIALMETALAREA 0.00195671 ;
	END WENY[64]

	PIN WENY[65]
		USE SIGNAL ;
		DIRECTION OUTPUT ;
		SHAPE ABUTMENT ;
		PORT
			 LAYER M2 ;
			RECT 0.0098 91.2878 0.0481 91.3882 ;
			 LAYER M3 ;
			RECT 0.0098 91.2878 0.0481 91.3882 ;
			 LAYER V2 ;
			RECT 0.021 91.3627 0.0359 91.3753 ;
		END

		ANTENNADIFFAREA 0.00194719 ;
		ANTENNAPARTIALMETALAREA 0.00195671 ;
	END WENY[65]

	PIN WENY[6]
		USE SIGNAL ;
		DIRECTION OUTPUT ;
		SHAPE ABUTMENT ;
		PORT
			 LAYER M2 ;
			RECT 0.0098 8.9224 0.0481 9.0227 ;
			 LAYER M3 ;
			RECT 0.0098 8.9224 0.0481 9.0227 ;
			 LAYER V2 ;
			RECT 0.021 8.9353 0.0359 8.9478 ;
		END

		ANTENNADIFFAREA 0.00194719 ;
		ANTENNAPARTIALMETALAREA 0.00195671 ;
	END WENY[6]

	PIN WENY[7]
		USE SIGNAL ;
		DIRECTION OUTPUT ;
		SHAPE ABUTMENT ;
		PORT
			 LAYER M2 ;
			RECT 0.0098 10.2024 0.0481 10.3027 ;
			 LAYER M3 ;
			RECT 0.0098 10.2024 0.0481 10.3027 ;
			 LAYER V2 ;
			RECT 0.021 10.2153 0.0359 10.2278 ;
		END

		ANTENNADIFFAREA 0.00194719 ;
		ANTENNAPARTIALMETALAREA 0.00195671 ;
	END WENY[7]

	PIN WENY[8]
		USE SIGNAL ;
		DIRECTION OUTPUT ;
		SHAPE ABUTMENT ;
		PORT
			 LAYER M2 ;
			RECT 0.0098 11.4824 0.0481 11.5827 ;
			 LAYER M3 ;
			RECT 0.0098 11.4824 0.0481 11.5827 ;
			 LAYER V2 ;
			RECT 0.021 11.4953 0.0359 11.5078 ;
		END

		ANTENNADIFFAREA 0.00194719 ;
		ANTENNAPARTIALMETALAREA 0.00195671 ;
	END WENY[8]

	PIN WENY[9]
		USE SIGNAL ;
		DIRECTION OUTPUT ;
		SHAPE ABUTMENT ;
		PORT
			 LAYER M2 ;
			RECT 0.0098 12.7624 0.0481 12.8627 ;
			 LAYER M3 ;
			RECT 0.0098 12.7624 0.0481 12.8627 ;
			 LAYER V2 ;
			RECT 0.021 12.7753 0.0359 12.7878 ;
		END

		ANTENNADIFFAREA 0.00194719 ;
		ANTENNAPARTIALMETALAREA 0.00195671 ;
	END WENY[9]

	PIN WEN[0]
		USE SIGNAL ;
		DIRECTION INPUT ;
		SHAPE ABUTMENT ;
		PORT
			 LAYER M2 ;
			RECT 0.0714 1.029 0.1097 1.0667 ;
			 LAYER M3 ;
			RECT 0.0714 0.9663 0.1097 1.0667 ;
			 LAYER V2 ;
			RECT 0.0831 1.042 0.098 1.0545 ;
		END

		ANTENNAGATEAREA 0.00027817 ;
		ANTENNADIFFAREA 0.00194719 ;
		ANTENNAPARTIALMETALAREA 0.00195671 ;
	END WEN[0]

	PIN WEN[10]
		USE SIGNAL ;
		DIRECTION INPUT ;
		SHAPE ABUTMENT ;
		PORT
			 LAYER M2 ;
			RECT 0.0714 13.829 0.1097 13.8667 ;
			 LAYER M3 ;
			RECT 0.0714 13.7663 0.1097 13.8667 ;
			 LAYER V2 ;
			RECT 0.0831 13.842 0.098 13.8545 ;
		END

		ANTENNAGATEAREA 0.00027817 ;
		ANTENNADIFFAREA 0.00194719 ;
		ANTENNAPARTIALMETALAREA 0.00195671 ;
	END WEN[10]

	PIN WEN[11]
		USE SIGNAL ;
		DIRECTION INPUT ;
		SHAPE ABUTMENT ;
		PORT
			 LAYER M2 ;
			RECT 0.0714 15.109 0.1097 15.1467 ;
			 LAYER M3 ;
			RECT 0.0714 15.0463 0.1097 15.1467 ;
			 LAYER V2 ;
			RECT 0.0831 15.122 0.098 15.1345 ;
		END

		ANTENNAGATEAREA 0.00027817 ;
		ANTENNADIFFAREA 0.00194719 ;
		ANTENNAPARTIALMETALAREA 0.00195671 ;
	END WEN[11]

	PIN WEN[12]
		USE SIGNAL ;
		DIRECTION INPUT ;
		SHAPE ABUTMENT ;
		PORT
			 LAYER M2 ;
			RECT 0.0714 16.389 0.1097 16.4267 ;
			 LAYER M3 ;
			RECT 0.0714 16.3263 0.1097 16.4267 ;
			 LAYER V2 ;
			RECT 0.0831 16.402 0.098 16.4145 ;
		END

		ANTENNAGATEAREA 0.00027817 ;
		ANTENNADIFFAREA 0.00194719 ;
		ANTENNAPARTIALMETALAREA 0.00195671 ;
	END WEN[12]

	PIN WEN[13]
		USE SIGNAL ;
		DIRECTION INPUT ;
		SHAPE ABUTMENT ;
		PORT
			 LAYER M2 ;
			RECT 0.0714 17.669 0.1097 17.7067 ;
			 LAYER M3 ;
			RECT 0.0714 17.6063 0.1097 17.7067 ;
			 LAYER V2 ;
			RECT 0.0831 17.682 0.098 17.6945 ;
		END

		ANTENNAGATEAREA 0.00027817 ;
		ANTENNADIFFAREA 0.00194719 ;
		ANTENNAPARTIALMETALAREA 0.00195671 ;
	END WEN[13]

	PIN WEN[14]
		USE SIGNAL ;
		DIRECTION INPUT ;
		SHAPE ABUTMENT ;
		PORT
			 LAYER M2 ;
			RECT 0.0714 18.949 0.1097 18.9867 ;
			 LAYER M3 ;
			RECT 0.0714 18.8863 0.1097 18.9867 ;
			 LAYER V2 ;
			RECT 0.0831 18.962 0.098 18.9745 ;
		END

		ANTENNAGATEAREA 0.00027817 ;
		ANTENNADIFFAREA 0.00194719 ;
		ANTENNAPARTIALMETALAREA 0.00195671 ;
	END WEN[14]

	PIN WEN[15]
		USE SIGNAL ;
		DIRECTION INPUT ;
		SHAPE ABUTMENT ;
		PORT
			 LAYER M2 ;
			RECT 0.0714 20.229 0.1097 20.2667 ;
			 LAYER M3 ;
			RECT 0.0714 20.1663 0.1097 20.2667 ;
			 LAYER V2 ;
			RECT 0.0831 20.242 0.098 20.2545 ;
		END

		ANTENNAGATEAREA 0.00027817 ;
		ANTENNADIFFAREA 0.00194719 ;
		ANTENNAPARTIALMETALAREA 0.00195671 ;
	END WEN[15]

	PIN WEN[16]
		USE SIGNAL ;
		DIRECTION INPUT ;
		SHAPE ABUTMENT ;
		PORT
			 LAYER M2 ;
			RECT 0.0714 21.509 0.1097 21.5467 ;
			 LAYER M3 ;
			RECT 0.0714 21.4463 0.1097 21.5467 ;
			 LAYER V2 ;
			RECT 0.0831 21.522 0.098 21.5345 ;
		END

		ANTENNAGATEAREA 0.00027817 ;
		ANTENNADIFFAREA 0.00194719 ;
		ANTENNAPARTIALMETALAREA 0.00195671 ;
	END WEN[16]

	PIN WEN[17]
		USE SIGNAL ;
		DIRECTION INPUT ;
		SHAPE ABUTMENT ;
		PORT
			 LAYER M2 ;
			RECT 0.0714 22.789 0.1097 22.8267 ;
			 LAYER M3 ;
			RECT 0.0714 22.7263 0.1097 22.8267 ;
			 LAYER V2 ;
			RECT 0.0831 22.802 0.098 22.8145 ;
		END

		ANTENNAGATEAREA 0.00027817 ;
		ANTENNADIFFAREA 0.00194719 ;
		ANTENNAPARTIALMETALAREA 0.00195671 ;
	END WEN[17]

	PIN WEN[18]
		USE SIGNAL ;
		DIRECTION INPUT ;
		SHAPE ABUTMENT ;
		PORT
			 LAYER M2 ;
			RECT 0.0714 24.069 0.1097 24.1067 ;
			 LAYER M3 ;
			RECT 0.0714 24.0063 0.1097 24.1067 ;
			 LAYER V2 ;
			RECT 0.0831 24.082 0.098 24.0945 ;
		END

		ANTENNAGATEAREA 0.00027817 ;
		ANTENNADIFFAREA 0.00194719 ;
		ANTENNAPARTIALMETALAREA 0.00195671 ;
	END WEN[18]

	PIN WEN[19]
		USE SIGNAL ;
		DIRECTION INPUT ;
		SHAPE ABUTMENT ;
		PORT
			 LAYER M2 ;
			RECT 0.0714 25.349 0.1097 25.3867 ;
			 LAYER M3 ;
			RECT 0.0714 25.2863 0.1097 25.3867 ;
			 LAYER V2 ;
			RECT 0.0831 25.362 0.098 25.3745 ;
		END

		ANTENNAGATEAREA 0.00027817 ;
		ANTENNADIFFAREA 0.00194719 ;
		ANTENNAPARTIALMETALAREA 0.00195671 ;
	END WEN[19]

	PIN WEN[1]
		USE SIGNAL ;
		DIRECTION INPUT ;
		SHAPE ABUTMENT ;
		PORT
			 LAYER M2 ;
			RECT 0.0714 2.309 0.1097 2.3467 ;
			 LAYER M3 ;
			RECT 0.0714 2.2463 0.1097 2.3467 ;
			 LAYER V2 ;
			RECT 0.0831 2.322 0.098 2.3345 ;
		END

		ANTENNAGATEAREA 0.00027817 ;
		ANTENNADIFFAREA 0.00194719 ;
		ANTENNAPARTIALMETALAREA 0.00195671 ;
	END WEN[1]

	PIN WEN[20]
		USE SIGNAL ;
		DIRECTION INPUT ;
		SHAPE ABUTMENT ;
		PORT
			 LAYER M2 ;
			RECT 0.0714 26.629 0.1097 26.6667 ;
			 LAYER M3 ;
			RECT 0.0714 26.5663 0.1097 26.6667 ;
			 LAYER V2 ;
			RECT 0.0831 26.642 0.098 26.6545 ;
		END

		ANTENNAGATEAREA 0.00027817 ;
		ANTENNADIFFAREA 0.00194719 ;
		ANTENNAPARTIALMETALAREA 0.00195671 ;
	END WEN[20]

	PIN WEN[21]
		USE SIGNAL ;
		DIRECTION INPUT ;
		SHAPE ABUTMENT ;
		PORT
			 LAYER M2 ;
			RECT 0.0714 27.909 0.1097 27.9467 ;
			 LAYER M3 ;
			RECT 0.0714 27.8463 0.1097 27.9467 ;
			 LAYER V2 ;
			RECT 0.0831 27.922 0.098 27.9345 ;
		END

		ANTENNAGATEAREA 0.00027817 ;
		ANTENNADIFFAREA 0.00194719 ;
		ANTENNAPARTIALMETALAREA 0.00195671 ;
	END WEN[21]

	PIN WEN[22]
		USE SIGNAL ;
		DIRECTION INPUT ;
		SHAPE ABUTMENT ;
		PORT
			 LAYER M2 ;
			RECT 0.0714 29.189 0.1097 29.2267 ;
			 LAYER M3 ;
			RECT 0.0714 29.1263 0.1097 29.2267 ;
			 LAYER V2 ;
			RECT 0.0831 29.202 0.098 29.2145 ;
		END

		ANTENNAGATEAREA 0.00027817 ;
		ANTENNADIFFAREA 0.00194719 ;
		ANTENNAPARTIALMETALAREA 0.00195671 ;
	END WEN[22]

	PIN WEN[23]
		USE SIGNAL ;
		DIRECTION INPUT ;
		SHAPE ABUTMENT ;
		PORT
			 LAYER M2 ;
			RECT 0.0714 30.469 0.1097 30.5067 ;
			 LAYER M3 ;
			RECT 0.0714 30.4063 0.1097 30.5067 ;
			 LAYER V2 ;
			RECT 0.0831 30.482 0.098 30.4945 ;
		END

		ANTENNAGATEAREA 0.00027817 ;
		ANTENNADIFFAREA 0.00194719 ;
		ANTENNAPARTIALMETALAREA 0.00195671 ;
	END WEN[23]

	PIN WEN[24]
		USE SIGNAL ;
		DIRECTION INPUT ;
		SHAPE ABUTMENT ;
		PORT
			 LAYER M2 ;
			RECT 0.0714 31.749 0.1097 31.7867 ;
			 LAYER M3 ;
			RECT 0.0714 31.6863 0.1097 31.7867 ;
			 LAYER V2 ;
			RECT 0.0831 31.762 0.098 31.7745 ;
		END

		ANTENNAGATEAREA 0.00027817 ;
		ANTENNADIFFAREA 0.00194719 ;
		ANTENNAPARTIALMETALAREA 0.00195671 ;
	END WEN[24]

	PIN WEN[25]
		USE SIGNAL ;
		DIRECTION INPUT ;
		SHAPE ABUTMENT ;
		PORT
			 LAYER M2 ;
			RECT 0.0714 33.029 0.1097 33.0667 ;
			 LAYER M3 ;
			RECT 0.0714 32.9663 0.1097 33.0667 ;
			 LAYER V2 ;
			RECT 0.0831 33.042 0.098 33.0545 ;
		END

		ANTENNAGATEAREA 0.00027817 ;
		ANTENNADIFFAREA 0.00194719 ;
		ANTENNAPARTIALMETALAREA 0.00195671 ;
	END WEN[25]

	PIN WEN[26]
		USE SIGNAL ;
		DIRECTION INPUT ;
		SHAPE ABUTMENT ;
		PORT
			 LAYER M2 ;
			RECT 0.0714 34.309 0.1097 34.3467 ;
			 LAYER M3 ;
			RECT 0.0714 34.2463 0.1097 34.3467 ;
			 LAYER V2 ;
			RECT 0.0831 34.322 0.098 34.3345 ;
		END

		ANTENNAGATEAREA 0.00027817 ;
		ANTENNADIFFAREA 0.00194719 ;
		ANTENNAPARTIALMETALAREA 0.00195671 ;
	END WEN[26]

	PIN WEN[27]
		USE SIGNAL ;
		DIRECTION INPUT ;
		SHAPE ABUTMENT ;
		PORT
			 LAYER M2 ;
			RECT 0.0714 35.589 0.1097 35.6267 ;
			 LAYER M3 ;
			RECT 0.0714 35.5263 0.1097 35.6267 ;
			 LAYER V2 ;
			RECT 0.0831 35.602 0.098 35.6145 ;
		END

		ANTENNAGATEAREA 0.00027817 ;
		ANTENNADIFFAREA 0.00194719 ;
		ANTENNAPARTIALMETALAREA 0.00195671 ;
	END WEN[27]

	PIN WEN[28]
		USE SIGNAL ;
		DIRECTION INPUT ;
		SHAPE ABUTMENT ;
		PORT
			 LAYER M2 ;
			RECT 0.0714 36.869 0.1097 36.9067 ;
			 LAYER M3 ;
			RECT 0.0714 36.8063 0.1097 36.9067 ;
			 LAYER V2 ;
			RECT 0.0831 36.882 0.098 36.8945 ;
		END

		ANTENNAGATEAREA 0.00027817 ;
		ANTENNADIFFAREA 0.00194719 ;
		ANTENNAPARTIALMETALAREA 0.00195671 ;
	END WEN[28]

	PIN WEN[29]
		USE SIGNAL ;
		DIRECTION INPUT ;
		SHAPE ABUTMENT ;
		PORT
			 LAYER M2 ;
			RECT 0.0714 38.149 0.1097 38.1867 ;
			 LAYER M3 ;
			RECT 0.0714 38.0863 0.1097 38.1867 ;
			 LAYER V2 ;
			RECT 0.0831 38.162 0.098 38.1745 ;
		END

		ANTENNAGATEAREA 0.00027817 ;
		ANTENNADIFFAREA 0.00194719 ;
		ANTENNAPARTIALMETALAREA 0.00195671 ;
	END WEN[29]

	PIN WEN[2]
		USE SIGNAL ;
		DIRECTION INPUT ;
		SHAPE ABUTMENT ;
		PORT
			 LAYER M2 ;
			RECT 0.0714 3.589 0.1097 3.6267 ;
			 LAYER M3 ;
			RECT 0.0714 3.5263 0.1097 3.6267 ;
			 LAYER V2 ;
			RECT 0.0831 3.602 0.098 3.6145 ;
		END

		ANTENNAGATEAREA 0.00027817 ;
		ANTENNADIFFAREA 0.00194719 ;
		ANTENNAPARTIALMETALAREA 0.00195671 ;
	END WEN[2]

	PIN WEN[30]
		USE SIGNAL ;
		DIRECTION INPUT ;
		SHAPE ABUTMENT ;
		PORT
			 LAYER M2 ;
			RECT 0.0714 39.429 0.1097 39.4667 ;
			 LAYER M3 ;
			RECT 0.0714 39.3663 0.1097 39.4667 ;
			 LAYER V2 ;
			RECT 0.0831 39.442 0.098 39.4545 ;
		END

		ANTENNAGATEAREA 0.00027817 ;
		ANTENNADIFFAREA 0.00194719 ;
		ANTENNAPARTIALMETALAREA 0.00195671 ;
	END WEN[30]

	PIN WEN[31]
		USE SIGNAL ;
		DIRECTION INPUT ;
		SHAPE ABUTMENT ;
		PORT
			 LAYER M2 ;
			RECT 0.0714 40.709 0.1097 40.7467 ;
			 LAYER M3 ;
			RECT 0.0714 40.6463 0.1097 40.7467 ;
			 LAYER V2 ;
			RECT 0.0831 40.722 0.098 40.7345 ;
		END

		ANTENNAGATEAREA 0.00027817 ;
		ANTENNADIFFAREA 0.00194719 ;
		ANTENNAPARTIALMETALAREA 0.00195671 ;
	END WEN[31]

	PIN WEN[32]
		USE SIGNAL ;
		DIRECTION INPUT ;
		SHAPE ABUTMENT ;
		PORT
			 LAYER M2 ;
			RECT 0.0714 41.989 0.1097 42.0267 ;
			 LAYER M3 ;
			RECT 0.0714 41.9263 0.1097 42.0267 ;
			 LAYER V2 ;
			RECT 0.0831 42.002 0.098 42.0145 ;
		END

		ANTENNAGATEAREA 0.00027817 ;
		ANTENNADIFFAREA 0.00194719 ;
		ANTENNAPARTIALMETALAREA 0.00195671 ;
	END WEN[32]

	PIN WEN[33]
		USE SIGNAL ;
		DIRECTION INPUT ;
		SHAPE ABUTMENT ;
		PORT
			 LAYER M2 ;
			RECT 0.0714 50.6039 0.1097 50.6416 ;
			 LAYER M3 ;
			RECT 0.0714 50.6039 0.1097 50.7043 ;
			 LAYER V2 ;
			RECT 0.0831 50.6161 0.098 50.6286 ;
		END

		ANTENNAGATEAREA 0.00027817 ;
		ANTENNADIFFAREA 0.00194719 ;
		ANTENNAPARTIALMETALAREA 0.00195671 ;
	END WEN[33]

	PIN WEN[34]
		USE SIGNAL ;
		DIRECTION INPUT ;
		SHAPE ABUTMENT ;
		PORT
			 LAYER M2 ;
			RECT 0.0714 51.8839 0.1097 51.9216 ;
			 LAYER M3 ;
			RECT 0.0714 51.8839 0.1097 51.9843 ;
			 LAYER V2 ;
			RECT 0.0831 51.8961 0.098 51.9086 ;
		END

		ANTENNAGATEAREA 0.00027817 ;
		ANTENNADIFFAREA 0.00194719 ;
		ANTENNAPARTIALMETALAREA 0.00195671 ;
	END WEN[34]

	PIN WEN[35]
		USE SIGNAL ;
		DIRECTION INPUT ;
		SHAPE ABUTMENT ;
		PORT
			 LAYER M2 ;
			RECT 0.0714 53.1639 0.1097 53.2016 ;
			 LAYER M3 ;
			RECT 0.0714 53.1639 0.1097 53.2643 ;
			 LAYER V2 ;
			RECT 0.0831 53.1761 0.098 53.1886 ;
		END

		ANTENNAGATEAREA 0.00027817 ;
		ANTENNADIFFAREA 0.00194719 ;
		ANTENNAPARTIALMETALAREA 0.00195671 ;
	END WEN[35]

	PIN WEN[36]
		USE SIGNAL ;
		DIRECTION INPUT ;
		SHAPE ABUTMENT ;
		PORT
			 LAYER M2 ;
			RECT 0.0714 54.4439 0.1097 54.4816 ;
			 LAYER M3 ;
			RECT 0.0714 54.4439 0.1097 54.5443 ;
			 LAYER V2 ;
			RECT 0.0831 54.4561 0.098 54.4686 ;
		END

		ANTENNAGATEAREA 0.00027817 ;
		ANTENNADIFFAREA 0.00194719 ;
		ANTENNAPARTIALMETALAREA 0.00195671 ;
	END WEN[36]

	PIN WEN[37]
		USE SIGNAL ;
		DIRECTION INPUT ;
		SHAPE ABUTMENT ;
		PORT
			 LAYER M2 ;
			RECT 0.0714 55.7239 0.1097 55.7616 ;
			 LAYER M3 ;
			RECT 0.0714 55.7239 0.1097 55.8243 ;
			 LAYER V2 ;
			RECT 0.0831 55.7361 0.098 55.7486 ;
		END

		ANTENNAGATEAREA 0.00027817 ;
		ANTENNADIFFAREA 0.00194719 ;
		ANTENNAPARTIALMETALAREA 0.00195671 ;
	END WEN[37]

	PIN WEN[38]
		USE SIGNAL ;
		DIRECTION INPUT ;
		SHAPE ABUTMENT ;
		PORT
			 LAYER M2 ;
			RECT 0.0714 57.0039 0.1097 57.0416 ;
			 LAYER M3 ;
			RECT 0.0714 57.0039 0.1097 57.1043 ;
			 LAYER V2 ;
			RECT 0.0831 57.0161 0.098 57.0286 ;
		END

		ANTENNAGATEAREA 0.00027817 ;
		ANTENNADIFFAREA 0.00194719 ;
		ANTENNAPARTIALMETALAREA 0.00195671 ;
	END WEN[38]

	PIN WEN[39]
		USE SIGNAL ;
		DIRECTION INPUT ;
		SHAPE ABUTMENT ;
		PORT
			 LAYER M2 ;
			RECT 0.0714 58.2839 0.1097 58.3216 ;
			 LAYER M3 ;
			RECT 0.0714 58.2839 0.1097 58.3843 ;
			 LAYER V2 ;
			RECT 0.0831 58.2961 0.098 58.3086 ;
		END

		ANTENNAGATEAREA 0.00027817 ;
		ANTENNADIFFAREA 0.00194719 ;
		ANTENNAPARTIALMETALAREA 0.00195671 ;
	END WEN[39]

	PIN WEN[3]
		USE SIGNAL ;
		DIRECTION INPUT ;
		SHAPE ABUTMENT ;
		PORT
			 LAYER M2 ;
			RECT 0.0714 4.869 0.1097 4.9067 ;
			 LAYER M3 ;
			RECT 0.0714 4.8063 0.1097 4.9067 ;
			 LAYER V2 ;
			RECT 0.0831 4.882 0.098 4.8945 ;
		END

		ANTENNAGATEAREA 0.00027817 ;
		ANTENNADIFFAREA 0.00194719 ;
		ANTENNAPARTIALMETALAREA 0.00195671 ;
	END WEN[3]

	PIN WEN[40]
		USE SIGNAL ;
		DIRECTION INPUT ;
		SHAPE ABUTMENT ;
		PORT
			 LAYER M2 ;
			RECT 0.0714 59.5639 0.1097 59.6016 ;
			 LAYER M3 ;
			RECT 0.0714 59.5639 0.1097 59.6643 ;
			 LAYER V2 ;
			RECT 0.0831 59.5761 0.098 59.5886 ;
		END

		ANTENNAGATEAREA 0.00027817 ;
		ANTENNADIFFAREA 0.00194719 ;
		ANTENNAPARTIALMETALAREA 0.00195671 ;
	END WEN[40]

	PIN WEN[41]
		USE SIGNAL ;
		DIRECTION INPUT ;
		SHAPE ABUTMENT ;
		PORT
			 LAYER M2 ;
			RECT 0.0714 60.8439 0.1097 60.8816 ;
			 LAYER M3 ;
			RECT 0.0714 60.8439 0.1097 60.9443 ;
			 LAYER V2 ;
			RECT 0.0831 60.8561 0.098 60.8686 ;
		END

		ANTENNAGATEAREA 0.00027817 ;
		ANTENNADIFFAREA 0.00194719 ;
		ANTENNAPARTIALMETALAREA 0.00195671 ;
	END WEN[41]

	PIN WEN[42]
		USE SIGNAL ;
		DIRECTION INPUT ;
		SHAPE ABUTMENT ;
		PORT
			 LAYER M2 ;
			RECT 0.0714 62.1239 0.1097 62.1616 ;
			 LAYER M3 ;
			RECT 0.0714 62.1239 0.1097 62.2243 ;
			 LAYER V2 ;
			RECT 0.0831 62.1361 0.098 62.1486 ;
		END

		ANTENNAGATEAREA 0.00027817 ;
		ANTENNADIFFAREA 0.00194719 ;
		ANTENNAPARTIALMETALAREA 0.00195671 ;
	END WEN[42]

	PIN WEN[43]
		USE SIGNAL ;
		DIRECTION INPUT ;
		SHAPE ABUTMENT ;
		PORT
			 LAYER M2 ;
			RECT 0.0714 63.4039 0.1097 63.4416 ;
			 LAYER M3 ;
			RECT 0.0714 63.4039 0.1097 63.5043 ;
			 LAYER V2 ;
			RECT 0.0831 63.4161 0.098 63.4286 ;
		END

		ANTENNAGATEAREA 0.00027817 ;
		ANTENNADIFFAREA 0.00194719 ;
		ANTENNAPARTIALMETALAREA 0.00195671 ;
	END WEN[43]

	PIN WEN[44]
		USE SIGNAL ;
		DIRECTION INPUT ;
		SHAPE ABUTMENT ;
		PORT
			 LAYER M2 ;
			RECT 0.0714 64.6839 0.1097 64.7216 ;
			 LAYER M3 ;
			RECT 0.0714 64.6839 0.1097 64.7843 ;
			 LAYER V2 ;
			RECT 0.0831 64.6961 0.098 64.7086 ;
		END

		ANTENNAGATEAREA 0.00027817 ;
		ANTENNADIFFAREA 0.00194719 ;
		ANTENNAPARTIALMETALAREA 0.00195671 ;
	END WEN[44]

	PIN WEN[45]
		USE SIGNAL ;
		DIRECTION INPUT ;
		SHAPE ABUTMENT ;
		PORT
			 LAYER M2 ;
			RECT 0.0714 65.9639 0.1097 66.0016 ;
			 LAYER M3 ;
			RECT 0.0714 65.9639 0.1097 66.0643 ;
			 LAYER V2 ;
			RECT 0.0831 65.9761 0.098 65.9886 ;
		END

		ANTENNAGATEAREA 0.00027817 ;
		ANTENNADIFFAREA 0.00194719 ;
		ANTENNAPARTIALMETALAREA 0.00195671 ;
	END WEN[45]

	PIN WEN[46]
		USE SIGNAL ;
		DIRECTION INPUT ;
		SHAPE ABUTMENT ;
		PORT
			 LAYER M2 ;
			RECT 0.0714 67.2439 0.1097 67.2816 ;
			 LAYER M3 ;
			RECT 0.0714 67.2439 0.1097 67.3443 ;
			 LAYER V2 ;
			RECT 0.0831 67.2561 0.098 67.2686 ;
		END

		ANTENNAGATEAREA 0.00027817 ;
		ANTENNADIFFAREA 0.00194719 ;
		ANTENNAPARTIALMETALAREA 0.00195671 ;
	END WEN[46]

	PIN WEN[47]
		USE SIGNAL ;
		DIRECTION INPUT ;
		SHAPE ABUTMENT ;
		PORT
			 LAYER M2 ;
			RECT 0.0714 68.5239 0.1097 68.5616 ;
			 LAYER M3 ;
			RECT 0.0714 68.5239 0.1097 68.6243 ;
			 LAYER V2 ;
			RECT 0.0831 68.5361 0.098 68.5486 ;
		END

		ANTENNAGATEAREA 0.00027817 ;
		ANTENNADIFFAREA 0.00194719 ;
		ANTENNAPARTIALMETALAREA 0.00195671 ;
	END WEN[47]

	PIN WEN[48]
		USE SIGNAL ;
		DIRECTION INPUT ;
		SHAPE ABUTMENT ;
		PORT
			 LAYER M2 ;
			RECT 0.0714 69.8039 0.1097 69.8416 ;
			 LAYER M3 ;
			RECT 0.0714 69.8039 0.1097 69.9043 ;
			 LAYER V2 ;
			RECT 0.0831 69.8161 0.098 69.8286 ;
		END

		ANTENNAGATEAREA 0.00027817 ;
		ANTENNADIFFAREA 0.00194719 ;
		ANTENNAPARTIALMETALAREA 0.00195671 ;
	END WEN[48]

	PIN WEN[49]
		USE SIGNAL ;
		DIRECTION INPUT ;
		SHAPE ABUTMENT ;
		PORT
			 LAYER M2 ;
			RECT 0.0714 71.0839 0.1097 71.1216 ;
			 LAYER M3 ;
			RECT 0.0714 71.0839 0.1097 71.1843 ;
			 LAYER V2 ;
			RECT 0.0831 71.0961 0.098 71.1086 ;
		END

		ANTENNAGATEAREA 0.00027817 ;
		ANTENNADIFFAREA 0.00194719 ;
		ANTENNAPARTIALMETALAREA 0.00195671 ;
	END WEN[49]

	PIN WEN[4]
		USE SIGNAL ;
		DIRECTION INPUT ;
		SHAPE ABUTMENT ;
		PORT
			 LAYER M2 ;
			RECT 0.0714 6.149 0.1097 6.1867 ;
			 LAYER M3 ;
			RECT 0.0714 6.0863 0.1097 6.1867 ;
			 LAYER V2 ;
			RECT 0.0831 6.162 0.098 6.1745 ;
		END

		ANTENNAGATEAREA 0.00027817 ;
		ANTENNADIFFAREA 0.00194719 ;
		ANTENNAPARTIALMETALAREA 0.00195671 ;
	END WEN[4]

	PIN WEN[50]
		USE SIGNAL ;
		DIRECTION INPUT ;
		SHAPE ABUTMENT ;
		PORT
			 LAYER M2 ;
			RECT 0.0714 72.3639 0.1097 72.4016 ;
			 LAYER M3 ;
			RECT 0.0714 72.3639 0.1097 72.4643 ;
			 LAYER V2 ;
			RECT 0.0831 72.3761 0.098 72.3886 ;
		END

		ANTENNAGATEAREA 0.00027817 ;
		ANTENNADIFFAREA 0.00194719 ;
		ANTENNAPARTIALMETALAREA 0.00195671 ;
	END WEN[50]

	PIN WEN[51]
		USE SIGNAL ;
		DIRECTION INPUT ;
		SHAPE ABUTMENT ;
		PORT
			 LAYER M2 ;
			RECT 0.0714 73.6439 0.1097 73.6816 ;
			 LAYER M3 ;
			RECT 0.0714 73.6439 0.1097 73.7443 ;
			 LAYER V2 ;
			RECT 0.0831 73.6561 0.098 73.6686 ;
		END

		ANTENNAGATEAREA 0.00027817 ;
		ANTENNADIFFAREA 0.00194719 ;
		ANTENNAPARTIALMETALAREA 0.00195671 ;
	END WEN[51]

	PIN WEN[52]
		USE SIGNAL ;
		DIRECTION INPUT ;
		SHAPE ABUTMENT ;
		PORT
			 LAYER M2 ;
			RECT 0.0714 74.9239 0.1097 74.9616 ;
			 LAYER M3 ;
			RECT 0.0714 74.9239 0.1097 75.0243 ;
			 LAYER V2 ;
			RECT 0.0831 74.9361 0.098 74.9486 ;
		END

		ANTENNAGATEAREA 0.00027817 ;
		ANTENNADIFFAREA 0.00194719 ;
		ANTENNAPARTIALMETALAREA 0.00195671 ;
	END WEN[52]

	PIN WEN[53]
		USE SIGNAL ;
		DIRECTION INPUT ;
		SHAPE ABUTMENT ;
		PORT
			 LAYER M2 ;
			RECT 0.0714 76.2039 0.1097 76.2416 ;
			 LAYER M3 ;
			RECT 0.0714 76.2039 0.1097 76.3043 ;
			 LAYER V2 ;
			RECT 0.0831 76.2161 0.098 76.2286 ;
		END

		ANTENNAGATEAREA 0.00027817 ;
		ANTENNADIFFAREA 0.00194719 ;
		ANTENNAPARTIALMETALAREA 0.00195671 ;
	END WEN[53]

	PIN WEN[54]
		USE SIGNAL ;
		DIRECTION INPUT ;
		SHAPE ABUTMENT ;
		PORT
			 LAYER M2 ;
			RECT 0.0714 77.4839 0.1097 77.5216 ;
			 LAYER M3 ;
			RECT 0.0714 77.4839 0.1097 77.5843 ;
			 LAYER V2 ;
			RECT 0.0831 77.4961 0.098 77.5086 ;
		END

		ANTENNAGATEAREA 0.00027817 ;
		ANTENNADIFFAREA 0.00194719 ;
		ANTENNAPARTIALMETALAREA 0.00195671 ;
	END WEN[54]

	PIN WEN[55]
		USE SIGNAL ;
		DIRECTION INPUT ;
		SHAPE ABUTMENT ;
		PORT
			 LAYER M2 ;
			RECT 0.0714 78.7639 0.1097 78.8016 ;
			 LAYER M3 ;
			RECT 0.0714 78.7639 0.1097 78.8643 ;
			 LAYER V2 ;
			RECT 0.0831 78.7761 0.098 78.7886 ;
		END

		ANTENNAGATEAREA 0.00027817 ;
		ANTENNADIFFAREA 0.00194719 ;
		ANTENNAPARTIALMETALAREA 0.00195671 ;
	END WEN[55]

	PIN WEN[56]
		USE SIGNAL ;
		DIRECTION INPUT ;
		SHAPE ABUTMENT ;
		PORT
			 LAYER M2 ;
			RECT 0.0714 80.0439 0.1097 80.0816 ;
			 LAYER M3 ;
			RECT 0.0714 80.0439 0.1097 80.1443 ;
			 LAYER V2 ;
			RECT 0.0831 80.0561 0.098 80.0686 ;
		END

		ANTENNAGATEAREA 0.00027817 ;
		ANTENNADIFFAREA 0.00194719 ;
		ANTENNAPARTIALMETALAREA 0.00195671 ;
	END WEN[56]

	PIN WEN[57]
		USE SIGNAL ;
		DIRECTION INPUT ;
		SHAPE ABUTMENT ;
		PORT
			 LAYER M2 ;
			RECT 0.0714 81.3239 0.1097 81.3616 ;
			 LAYER M3 ;
			RECT 0.0714 81.3239 0.1097 81.4243 ;
			 LAYER V2 ;
			RECT 0.0831 81.3361 0.098 81.3486 ;
		END

		ANTENNAGATEAREA 0.00027817 ;
		ANTENNADIFFAREA 0.00194719 ;
		ANTENNAPARTIALMETALAREA 0.00195671 ;
	END WEN[57]

	PIN WEN[58]
		USE SIGNAL ;
		DIRECTION INPUT ;
		SHAPE ABUTMENT ;
		PORT
			 LAYER M2 ;
			RECT 0.0714 82.6039 0.1097 82.6416 ;
			 LAYER M3 ;
			RECT 0.0714 82.6039 0.1097 82.7043 ;
			 LAYER V2 ;
			RECT 0.0831 82.6161 0.098 82.6286 ;
		END

		ANTENNAGATEAREA 0.00027817 ;
		ANTENNADIFFAREA 0.00194719 ;
		ANTENNAPARTIALMETALAREA 0.00195671 ;
	END WEN[58]

	PIN WEN[59]
		USE SIGNAL ;
		DIRECTION INPUT ;
		SHAPE ABUTMENT ;
		PORT
			 LAYER M2 ;
			RECT 0.0714 83.8839 0.1097 83.9216 ;
			 LAYER M3 ;
			RECT 0.0714 83.8839 0.1097 83.9843 ;
			 LAYER V2 ;
			RECT 0.0831 83.8961 0.098 83.9086 ;
		END

		ANTENNAGATEAREA 0.00027817 ;
		ANTENNADIFFAREA 0.00194719 ;
		ANTENNAPARTIALMETALAREA 0.00195671 ;
	END WEN[59]

	PIN WEN[5]
		USE SIGNAL ;
		DIRECTION INPUT ;
		SHAPE ABUTMENT ;
		PORT
			 LAYER M2 ;
			RECT 0.0714 7.429 0.1097 7.4667 ;
			 LAYER M3 ;
			RECT 0.0714 7.3663 0.1097 7.4667 ;
			 LAYER V2 ;
			RECT 0.0831 7.442 0.098 7.4545 ;
		END

		ANTENNAGATEAREA 0.00027817 ;
		ANTENNADIFFAREA 0.00194719 ;
		ANTENNAPARTIALMETALAREA 0.00195671 ;
	END WEN[5]

	PIN WEN[60]
		USE SIGNAL ;
		DIRECTION INPUT ;
		SHAPE ABUTMENT ;
		PORT
			 LAYER M2 ;
			RECT 0.0714 85.1639 0.1097 85.2016 ;
			 LAYER M3 ;
			RECT 0.0714 85.1639 0.1097 85.2643 ;
			 LAYER V2 ;
			RECT 0.0831 85.1761 0.098 85.1886 ;
		END

		ANTENNAGATEAREA 0.00027817 ;
		ANTENNADIFFAREA 0.00194719 ;
		ANTENNAPARTIALMETALAREA 0.00195671 ;
	END WEN[60]

	PIN WEN[61]
		USE SIGNAL ;
		DIRECTION INPUT ;
		SHAPE ABUTMENT ;
		PORT
			 LAYER M2 ;
			RECT 0.0714 86.4439 0.1097 86.4816 ;
			 LAYER M3 ;
			RECT 0.0714 86.4439 0.1097 86.5443 ;
			 LAYER V2 ;
			RECT 0.0831 86.4561 0.098 86.4686 ;
		END

		ANTENNAGATEAREA 0.00027817 ;
		ANTENNADIFFAREA 0.00194719 ;
		ANTENNAPARTIALMETALAREA 0.00195671 ;
	END WEN[61]

	PIN WEN[62]
		USE SIGNAL ;
		DIRECTION INPUT ;
		SHAPE ABUTMENT ;
		PORT
			 LAYER M2 ;
			RECT 0.0714 87.7239 0.1097 87.7616 ;
			 LAYER M3 ;
			RECT 0.0714 87.7239 0.1097 87.8243 ;
			 LAYER V2 ;
			RECT 0.0831 87.7361 0.098 87.7486 ;
		END

		ANTENNAGATEAREA 0.00027817 ;
		ANTENNADIFFAREA 0.00194719 ;
		ANTENNAPARTIALMETALAREA 0.00195671 ;
	END WEN[62]

	PIN WEN[63]
		USE SIGNAL ;
		DIRECTION INPUT ;
		SHAPE ABUTMENT ;
		PORT
			 LAYER M2 ;
			RECT 0.0714 89.0039 0.1097 89.0416 ;
			 LAYER M3 ;
			RECT 0.0714 89.0039 0.1097 89.1043 ;
			 LAYER V2 ;
			RECT 0.0831 89.0161 0.098 89.0286 ;
		END

		ANTENNAGATEAREA 0.00027817 ;
		ANTENNADIFFAREA 0.00194719 ;
		ANTENNAPARTIALMETALAREA 0.00195671 ;
	END WEN[63]

	PIN WEN[64]
		USE SIGNAL ;
		DIRECTION INPUT ;
		SHAPE ABUTMENT ;
		PORT
			 LAYER M2 ;
			RECT 0.0714 90.2839 0.1097 90.3216 ;
			 LAYER M3 ;
			RECT 0.0714 90.2839 0.1097 90.3843 ;
			 LAYER V2 ;
			RECT 0.0831 90.2961 0.098 90.3086 ;
		END

		ANTENNAGATEAREA 0.00027817 ;
		ANTENNADIFFAREA 0.00194719 ;
		ANTENNAPARTIALMETALAREA 0.00195671 ;
	END WEN[64]

	PIN WEN[65]
		USE SIGNAL ;
		DIRECTION INPUT ;
		SHAPE ABUTMENT ;
		PORT
			 LAYER M2 ;
			RECT 0.0714 91.5639 0.1097 91.6016 ;
			 LAYER M3 ;
			RECT 0.0714 91.5639 0.1097 91.6643 ;
			 LAYER V2 ;
			RECT 0.0831 91.5761 0.098 91.5886 ;
		END

		ANTENNAGATEAREA 0.00027817 ;
		ANTENNADIFFAREA 0.00194719 ;
		ANTENNAPARTIALMETALAREA 0.00195671 ;
	END WEN[65]

	PIN WEN[6]
		USE SIGNAL ;
		DIRECTION INPUT ;
		SHAPE ABUTMENT ;
		PORT
			 LAYER M2 ;
			RECT 0.0714 8.709 0.1097 8.7467 ;
			 LAYER M3 ;
			RECT 0.0714 8.6463 0.1097 8.7467 ;
			 LAYER V2 ;
			RECT 0.0831 8.722 0.098 8.7345 ;
		END

		ANTENNAGATEAREA 0.00027817 ;
		ANTENNADIFFAREA 0.00194719 ;
		ANTENNAPARTIALMETALAREA 0.00195671 ;
	END WEN[6]

	PIN WEN[7]
		USE SIGNAL ;
		DIRECTION INPUT ;
		SHAPE ABUTMENT ;
		PORT
			 LAYER M2 ;
			RECT 0.0714 9.989 0.1097 10.0267 ;
			 LAYER M3 ;
			RECT 0.0714 9.9263 0.1097 10.0267 ;
			 LAYER V2 ;
			RECT 0.0831 10.002 0.098 10.0145 ;
		END

		ANTENNAGATEAREA 0.00027817 ;
		ANTENNADIFFAREA 0.00194719 ;
		ANTENNAPARTIALMETALAREA 0.00195671 ;
	END WEN[7]

	PIN WEN[8]
		USE SIGNAL ;
		DIRECTION INPUT ;
		SHAPE ABUTMENT ;
		PORT
			 LAYER M2 ;
			RECT 0.0714 11.269 0.1097 11.3067 ;
			 LAYER M3 ;
			RECT 0.0714 11.2063 0.1097 11.3067 ;
			 LAYER V2 ;
			RECT 0.0831 11.282 0.098 11.2945 ;
		END

		ANTENNAGATEAREA 0.00027817 ;
		ANTENNADIFFAREA 0.00194719 ;
		ANTENNAPARTIALMETALAREA 0.00195671 ;
	END WEN[8]

	PIN WEN[9]
		USE SIGNAL ;
		DIRECTION INPUT ;
		SHAPE ABUTMENT ;
		PORT
			 LAYER M2 ;
			RECT 0.0714 12.549 0.1097 12.5867 ;
			 LAYER M3 ;
			RECT 0.0714 12.4863 0.1097 12.5867 ;
			 LAYER V2 ;
			RECT 0.0831 12.562 0.098 12.5745 ;
		END

		ANTENNAGATEAREA 0.00027817 ;
		ANTENNADIFFAREA 0.00194719 ;
		ANTENNAPARTIALMETALAREA 0.00195671 ;
	END WEN[9]

	OBS
		 LAYER M1 SPACING 0.012 ;
		RECT 0 0 21.693 92.6306 ;
		 LAYER M2 SPACING 0.012 ;
		RECT 0.133 0 21.693 92.6306 ;
		RECT 0 0 0.133 0.0439 ;
		RECT 0 0.182 0.133 0.9475 ;
		RECT 0.0714 1.0918 0.133 1.2235 ;
		RECT 0 1.211 0.133 1.2235 ;
		RECT 0.0714 1.2235 0.133 1.349 ;
		RECT 0 1.4871 0.133 2.2275 ;
		RECT 0.0714 2.3718 0.133 2.5035 ;
		RECT 0 2.491 0.133 2.5035 ;
		RECT 0.0714 2.5035 0.133 2.629 ;
		RECT 0 2.7671 0.133 3.5075 ;
		RECT 0.0714 3.6518 0.133 3.7835 ;
		RECT 0 3.771 0.133 3.7835 ;
		RECT 0.0714 3.7835 0.133 3.909 ;
		RECT 0 4.0471 0.133 4.7875 ;
		RECT 0.0714 4.9318 0.133 5.0635 ;
		RECT 0 5.051 0.133 5.0635 ;
		RECT 0.0714 5.0635 0.133 5.189 ;
		RECT 0 5.3271 0.133 6.0675 ;
		RECT 0.0714 6.2118 0.133 6.3435 ;
		RECT 0 6.331 0.133 6.3435 ;
		RECT 0.0714 6.3435 0.133 6.469 ;
		RECT 0 6.6071 0.133 7.3475 ;
		RECT 0.0714 7.4918 0.133 7.6235 ;
		RECT 0 7.611 0.133 7.6235 ;
		RECT 0.0714 7.6235 0.133 7.749 ;
		RECT 0 7.8871 0.133 8.6275 ;
		RECT 0.0714 8.7718 0.133 8.9035 ;
		RECT 0 8.891 0.133 8.9035 ;
		RECT 0.0714 8.9035 0.133 9.029 ;
		RECT 0 9.1671 0.133 9.9075 ;
		RECT 0.0714 10.0518 0.133 10.1835 ;
		RECT 0 10.171 0.133 10.1835 ;
		RECT 0.0714 10.1835 0.133 10.309 ;
		RECT 0 10.4471 0.133 11.1875 ;
		RECT 0.0714 11.3318 0.133 11.4635 ;
		RECT 0 11.451 0.133 11.4635 ;
		RECT 0.0714 11.4635 0.133 11.589 ;
		RECT 0 11.7271 0.133 12.4675 ;
		RECT 0.0714 12.6118 0.133 12.7435 ;
		RECT 0 12.731 0.133 12.7435 ;
		RECT 0.0714 12.7435 0.133 12.869 ;
		RECT 0 13.0071 0.133 13.7475 ;
		RECT 0.0714 13.8918 0.133 14.0235 ;
		RECT 0 14.011 0.133 14.0235 ;
		RECT 0.0714 14.0235 0.133 14.149 ;
		RECT 0 14.2871 0.133 15.0275 ;
		RECT 0.0714 15.1718 0.133 15.3035 ;
		RECT 0 15.291 0.133 15.3035 ;
		RECT 0.0714 15.3035 0.133 15.429 ;
		RECT 0 15.5671 0.133 16.3075 ;
		RECT 0.0714 16.4518 0.133 16.5835 ;
		RECT 0 16.571 0.133 16.5835 ;
		RECT 0.0714 16.5835 0.133 16.709 ;
		RECT 0 16.8471 0.133 17.5875 ;
		RECT 0.0714 17.7318 0.133 17.8635 ;
		RECT 0 17.851 0.133 17.8635 ;
		RECT 0.0714 17.8635 0.133 17.989 ;
		RECT 0 18.1271 0.133 18.8675 ;
		RECT 0.0714 19.0118 0.133 19.1435 ;
		RECT 0 19.131 0.133 19.1435 ;
		RECT 0.0714 19.1435 0.133 19.269 ;
		RECT 0 19.4071 0.133 20.1475 ;
		RECT 0.0714 20.2918 0.133 20.4235 ;
		RECT 0 20.411 0.133 20.4235 ;
		RECT 0.0714 20.4235 0.133 20.549 ;
		RECT 0 20.6871 0.133 21.4275 ;
		RECT 0.0714 21.5718 0.133 21.7035 ;
		RECT 0 21.691 0.133 21.7035 ;
		RECT 0.0714 21.7035 0.133 21.829 ;
		RECT 0 21.9671 0.133 22.7075 ;
		RECT 0.0714 22.8518 0.133 22.9835 ;
		RECT 0 22.971 0.133 22.9835 ;
		RECT 0.0714 22.9835 0.133 23.109 ;
		RECT 0 23.2471 0.133 23.9875 ;
		RECT 0.0714 24.1318 0.133 24.2635 ;
		RECT 0 24.251 0.133 24.2635 ;
		RECT 0.0714 24.2635 0.133 24.389 ;
		RECT 0 24.5271 0.133 25.2675 ;
		RECT 0.0714 25.4118 0.133 25.5435 ;
		RECT 0 25.531 0.133 25.5435 ;
		RECT 0.0714 25.5435 0.133 25.669 ;
		RECT 0 25.8071 0.133 26.5475 ;
		RECT 0.0714 26.6918 0.133 26.8235 ;
		RECT 0 26.811 0.133 26.8235 ;
		RECT 0.0714 26.8235 0.133 26.949 ;
		RECT 0 27.0871 0.133 27.8275 ;
		RECT 0.0714 27.9718 0.133 28.1035 ;
		RECT 0 28.091 0.133 28.1035 ;
		RECT 0.0714 28.1035 0.133 28.229 ;
		RECT 0 28.3671 0.133 29.1075 ;
		RECT 0.0714 29.2518 0.133 29.3835 ;
		RECT 0 29.371 0.133 29.3835 ;
		RECT 0.0714 29.3835 0.133 29.509 ;
		RECT 0 29.6471 0.133 30.3875 ;
		RECT 0.0714 30.5318 0.133 30.6635 ;
		RECT 0 30.651 0.133 30.6635 ;
		RECT 0.0714 30.6635 0.133 30.789 ;
		RECT 0 30.9271 0.133 31.6675 ;
		RECT 0.0714 31.8118 0.133 31.9435 ;
		RECT 0 31.931 0.133 31.9435 ;
		RECT 0.0714 31.9435 0.133 32.069 ;
		RECT 0 32.2071 0.133 32.9475 ;
		RECT 0.0714 33.0918 0.133 33.2235 ;
		RECT 0 33.211 0.133 33.2235 ;
		RECT 0.0714 33.2235 0.133 33.349 ;
		RECT 0 33.4871 0.133 34.2275 ;
		RECT 0.0714 34.3718 0.133 34.5035 ;
		RECT 0 34.491 0.133 34.5035 ;
		RECT 0.0714 34.5035 0.133 34.629 ;
		RECT 0 34.7671 0.133 35.5075 ;
		RECT 0.0714 35.6518 0.133 35.7835 ;
		RECT 0 35.771 0.133 35.7835 ;
		RECT 0.0714 35.7835 0.133 35.909 ;
		RECT 0 36.0471 0.133 36.7875 ;
		RECT 0.0714 36.9318 0.133 37.0635 ;
		RECT 0 37.051 0.133 37.0635 ;
		RECT 0.0714 37.0635 0.133 37.189 ;
		RECT 0 37.3271 0.133 38.0675 ;
		RECT 0.0714 38.2118 0.133 38.3435 ;
		RECT 0 38.331 0.133 38.3435 ;
		RECT 0.0714 38.3435 0.133 38.469 ;
		RECT 0 38.6071 0.133 39.3475 ;
		RECT 0.0714 39.4918 0.133 39.6235 ;
		RECT 0 39.611 0.133 39.6235 ;
		RECT 0.0714 39.6235 0.133 39.749 ;
		RECT 0 39.8871 0.133 40.6275 ;
		RECT 0.0714 40.7718 0.133 40.9035 ;
		RECT 0 40.891 0.133 40.9035 ;
		RECT 0.0714 40.9035 0.133 41.029 ;
		RECT 0 41.1671 0.133 41.9075 ;
		RECT 0.0714 42.0518 0.133 42.1835 ;
		RECT 0 42.171 0.133 42.1835 ;
		RECT 0.0714 42.1835 0.133 42.309 ;
		RECT 0 42.4471 0.133 42.7608 ;
		RECT 0 42.8988 0.133 42.9114 ;
		RECT 0 43.0494 0.133 43.3631 ;
		RECT 0 43.5012 0.133 43.5137 ;
		RECT 0 43.6518 0.133 43.6643 ;
		RECT 0 43.8024 0.133 43.9655 ;
		RECT 0 44.1035 0.133 44.2667 ;
		RECT 0 44.4047 0.133 44.4173 ;
		RECT 0 44.5553 0.133 44.7184 ;
		RECT 0 44.8565 0.133 44.869 ;
		RECT 0 45.0071 0.133 45.0196 ;
		RECT 0 45.1576 0.133 45.1702 ;
		RECT 0 45.3082 0.133 45.3208 ;
		RECT 0 45.4588 0.133 45.4714 ;
		RECT 0 45.6094 0.133 45.622 ;
		RECT 0 45.76 0.133 45.7725 ;
		RECT 0 45.9106 0.133 45.9231 ;
		RECT 0 46.0612 0.133 46.0737 ;
		RECT 0 46.2118 0.133 46.2243 ;
		RECT 0 46.3624 0.133 46.3749 ;
		RECT 0 46.5129 0.133 46.5255 ;
		RECT 0 46.6635 0.133 46.6761 ;
		RECT 0 46.8141 0.133 46.8267 ;
		RECT 0 46.9647 0.133 46.9773 ;
		RECT 0 47.1153 0.133 47.1278 ;
		RECT 0 47.2659 0.133 47.2784 ;
		RECT 0 47.4165 0.133 47.429 ;
		RECT 0 47.5671 0.133 47.5796 ;
		RECT 0 47.7176 0.133 47.7302 ;
		RECT 0 47.8682 0.133 48.0314 ;
		RECT 0 48.1694 0.133 48.182 ;
		RECT 0 48.32 0.133 48.3325 ;
		RECT 0 48.4706 0.133 48.4831 ;
		RECT 0 48.6212 0.133 48.6337 ;
		RECT 0 48.7718 0.133 49.0855 ;
		RECT 0 49.2235 0.133 49.2361 ;
		RECT 0 49.3741 0.133 49.8384 ;
		RECT 0 49.9765 0.133 50.1835 ;
		RECT 0.0714 50.3278 0.133 50.4596 ;
		RECT 0 50.4471 0.133 50.4596 ;
		RECT 0.0714 50.4596 0.133 50.5851 ;
		RECT 0 50.7231 0.133 51.4635 ;
		RECT 0.0714 51.6078 0.133 51.7396 ;
		RECT 0 51.7271 0.133 51.7396 ;
		RECT 0.0714 51.7396 0.133 51.8651 ;
		RECT 0 52.0031 0.133 52.7435 ;
		RECT 0.0714 52.8878 0.133 53.0196 ;
		RECT 0 53.0071 0.133 53.0196 ;
		RECT 0.0714 53.0196 0.133 53.1451 ;
		RECT 0 53.2831 0.133 54.0235 ;
		RECT 0.0714 54.1678 0.133 54.2996 ;
		RECT 0 54.2871 0.133 54.2996 ;
		RECT 0.0714 54.2996 0.133 54.4251 ;
		RECT 0 54.5631 0.133 55.3035 ;
		RECT 0.0714 55.4478 0.133 55.5796 ;
		RECT 0 55.5671 0.133 55.5796 ;
		RECT 0.0714 55.5796 0.133 55.7051 ;
		RECT 0 55.8431 0.133 56.5835 ;
		RECT 0.0714 56.7278 0.133 56.8596 ;
		RECT 0 56.8471 0.133 56.8596 ;
		RECT 0.0714 56.8596 0.133 56.9851 ;
		RECT 0 57.1231 0.133 57.8635 ;
		RECT 0.0714 58.0078 0.133 58.1396 ;
		RECT 0 58.1271 0.133 58.1396 ;
		RECT 0.0714 58.1396 0.133 58.2651 ;
		RECT 0 58.4031 0.133 59.1435 ;
		RECT 0.0714 59.2878 0.133 59.4196 ;
		RECT 0 59.4071 0.133 59.4196 ;
		RECT 0.0714 59.4196 0.133 59.5451 ;
		RECT 0 59.6831 0.133 60.4235 ;
		RECT 0.0714 60.5678 0.133 60.6996 ;
		RECT 0 60.6871 0.133 60.6996 ;
		RECT 0.0714 60.6996 0.133 60.8251 ;
		RECT 0 60.9631 0.133 61.7035 ;
		RECT 0.0714 61.8478 0.133 61.9796 ;
		RECT 0 61.9671 0.133 61.9796 ;
		RECT 0.0714 61.9796 0.133 62.1051 ;
		RECT 0 62.2431 0.133 62.9835 ;
		RECT 0.0714 63.1278 0.133 63.2596 ;
		RECT 0 63.2471 0.133 63.2596 ;
		RECT 0.0714 63.2596 0.133 63.3851 ;
		RECT 0 63.5231 0.133 64.2635 ;
		RECT 0.0714 64.4078 0.133 64.5396 ;
		RECT 0 64.5271 0.133 64.5396 ;
		RECT 0.0714 64.5396 0.133 64.6651 ;
		RECT 0 64.8031 0.133 65.5435 ;
		RECT 0.0714 65.6878 0.133 65.8196 ;
		RECT 0 65.8071 0.133 65.8196 ;
		RECT 0.0714 65.8196 0.133 65.9451 ;
		RECT 0 66.0831 0.133 66.8235 ;
		RECT 0.0714 66.9678 0.133 67.0996 ;
		RECT 0 67.0871 0.133 67.0996 ;
		RECT 0.0714 67.0996 0.133 67.2251 ;
		RECT 0 67.3631 0.133 68.1035 ;
		RECT 0.0714 68.2478 0.133 68.3796 ;
		RECT 0 68.3671 0.133 68.3796 ;
		RECT 0.0714 68.3796 0.133 68.5051 ;
		RECT 0 68.6431 0.133 69.3835 ;
		RECT 0.0714 69.5278 0.133 69.6596 ;
		RECT 0 69.6471 0.133 69.6596 ;
		RECT 0.0714 69.6596 0.133 69.7851 ;
		RECT 0 69.9231 0.133 70.6635 ;
		RECT 0.0714 70.8078 0.133 70.9396 ;
		RECT 0 70.9271 0.133 70.9396 ;
		RECT 0.0714 70.9396 0.133 71.0651 ;
		RECT 0 71.2031 0.133 71.9435 ;
		RECT 0.0714 72.0878 0.133 72.2196 ;
		RECT 0 72.2071 0.133 72.2196 ;
		RECT 0.0714 72.2196 0.133 72.3451 ;
		RECT 0 72.4831 0.133 73.2235 ;
		RECT 0.0714 73.3678 0.133 73.4996 ;
		RECT 0 73.4871 0.133 73.4996 ;
		RECT 0.0714 73.4996 0.133 73.6251 ;
		RECT 0 73.7631 0.133 74.5035 ;
		RECT 0.0714 74.6478 0.133 74.7796 ;
		RECT 0 74.7671 0.133 74.7796 ;
		RECT 0.0714 74.7796 0.133 74.9051 ;
		RECT 0 75.0431 0.133 75.7835 ;
		RECT 0.0714 75.9278 0.133 76.0596 ;
		RECT 0 76.0471 0.133 76.0596 ;
		RECT 0.0714 76.0596 0.133 76.1851 ;
		RECT 0 76.3231 0.133 77.0635 ;
		RECT 0.0714 77.2078 0.133 77.3396 ;
		RECT 0 77.3271 0.133 77.3396 ;
		RECT 0.0714 77.3396 0.133 77.4651 ;
		RECT 0 77.6031 0.133 78.3435 ;
		RECT 0.0714 78.4878 0.133 78.6196 ;
		RECT 0 78.6071 0.133 78.6196 ;
		RECT 0.0714 78.6196 0.133 78.7451 ;
		RECT 0 78.8831 0.133 79.6235 ;
		RECT 0.0714 79.7678 0.133 79.8996 ;
		RECT 0 79.8871 0.133 79.8996 ;
		RECT 0.0714 79.8996 0.133 80.0251 ;
		RECT 0 80.1631 0.133 80.9035 ;
		RECT 0.0714 81.0478 0.133 81.1796 ;
		RECT 0 81.1671 0.133 81.1796 ;
		RECT 0.0714 81.1796 0.133 81.3051 ;
		RECT 0 81.4431 0.133 82.1835 ;
		RECT 0.0714 82.3278 0.133 82.4596 ;
		RECT 0 82.4471 0.133 82.4596 ;
		RECT 0.0714 82.4596 0.133 82.5851 ;
		RECT 0 82.7231 0.133 83.4635 ;
		RECT 0.0714 83.6078 0.133 83.7396 ;
		RECT 0 83.7271 0.133 83.7396 ;
		RECT 0.0714 83.7396 0.133 83.8651 ;
		RECT 0 84.0031 0.133 84.7435 ;
		RECT 0.0714 84.8878 0.133 85.0196 ;
		RECT 0 85.0071 0.133 85.0196 ;
		RECT 0.0714 85.0196 0.133 85.1451 ;
		RECT 0 85.2831 0.133 86.0235 ;
		RECT 0.0714 86.1678 0.133 86.2996 ;
		RECT 0 86.2871 0.133 86.2996 ;
		RECT 0.0714 86.2996 0.133 86.4251 ;
		RECT 0 86.5631 0.133 87.3035 ;
		RECT 0.0714 87.4478 0.133 87.5796 ;
		RECT 0 87.5671 0.133 87.5796 ;
		RECT 0.0714 87.5796 0.133 87.7051 ;
		RECT 0 87.8431 0.133 88.5835 ;
		RECT 0.0714 88.7278 0.133 88.8596 ;
		RECT 0 88.8471 0.133 88.8596 ;
		RECT 0.0714 88.8596 0.133 88.9851 ;
		RECT 0 89.1231 0.133 89.8635 ;
		RECT 0.0714 90.0078 0.133 90.1396 ;
		RECT 0 90.1271 0.133 90.1396 ;
		RECT 0.0714 90.1396 0.133 90.2651 ;
		RECT 0 90.4031 0.133 91.1435 ;
		RECT 0.0714 91.2878 0.133 91.4196 ;
		RECT 0 91.4071 0.133 91.4196 ;
		RECT 0.0714 91.4196 0.133 91.5451 ;
		RECT 0 91.6831 0.133 92.4486 ;
		RECT 0 92.5867 0.133 92.6306 ;
		 LAYER M2 ;
		RECT 0.0714 45.3396 0.1097 45.44 ;
		RECT 0.0714 46.6949 0.1097 46.7953 ;
		RECT 0.0714 47.2973 0.1097 47.3976 ;
		RECT 0.0714 47.5984 0.1097 47.6988 ;
		RECT 0.0714 47.749 0.1097 47.8494 ;
		RECT 0.0714 48.3514 0.1097 48.4518 ;
		RECT 0.0714 42.4784 0.1097 42.5161 ;
		RECT 0.0098 42.5412 0.0481 42.5788 ;
		RECT 0.0098 43.5953 0.0481 43.6329 ;
		RECT 0.0714 43.8337 0.1097 43.8714 ;
		RECT 0.0098 43.8965 0.0481 43.9341 ;
		RECT 0.0714 43.9843 0.1097 44.022 ;
		RECT 0.0098 44.1349 0.0481 44.2353 ;
		RECT 0.0714 44.5867 0.1097 44.6243 ;
		RECT 0.0098 44.6494 0.0481 44.6871 ;
		RECT 0.0714 44.7373 0.1097 44.7749 ;
		RECT 0.0098 45.2518 0.0481 45.2894 ;
		RECT 0.0098 45.3396 0.0481 45.3773 ;
		RECT 0.0714 42.629 0.1097 42.6667 ;
		RECT 0.0714 45.4902 0.1097 45.5278 ;
		RECT 0.0714 45.6408 0.1097 45.6784 ;
		RECT 0.0714 46.3937 0.1097 46.4314 ;
		RECT 0.0098 46.6071 0.0481 46.6447 ;
		RECT 0.0098 46.7576 0.0481 46.7953 ;
		RECT 0.0714 46.8455 0.1097 46.8831 ;
		RECT 0.0714 47.1467 0.1097 47.1843 ;
		RECT 0.0098 47.36 0.0481 47.3976 ;
		RECT 0.0098 47.5106 0.0481 47.5482 ;
		RECT 0.0098 47.5984 0.0481 47.6361 ;
		RECT 0.0098 42.6918 0.0481 42.7294 ;
		RECT 0.0098 47.8996 0.0481 47.9373 ;
		RECT 0.0714 47.9624 0.1097 48 ;
		RECT 0.0098 48.4141 0.0481 48.4518 ;
		RECT 0.0714 48.8031 0.1097 48.8408 ;
		RECT 0.0098 48.8659 0.0481 48.9035 ;
		RECT 0.0098 48.9537 0.0481 49.0541 ;
		RECT 0.0098 49.1671 0.0481 49.2047 ;
		RECT 0.0098 49.3176 0.0481 49.3553 ;
		RECT 0.0714 49.4055 0.1097 49.4431 ;
		RECT 0.0098 49.4682 0.0481 49.5059 ;
		RECT 0.0098 42.8424 0.0481 42.88 ;
		RECT 0.0098 49.5561 0.0481 49.6565 ;
		RECT 0.0714 49.7067 0.1097 49.7443 ;
		RECT 0.0098 49.7694 0.0481 49.8071 ;
		RECT 0.0714 49.8573 0.1097 49.8949 ;
		RECT 0.0098 50.0078 0.0481 50.1082 ;
		RECT 0.0098 0.1255 0.0481 0.1631 ;
		RECT 0.0098 92.4675 0.0481 92.5051 ;
		RECT 0.0098 42.9929 0.0481 43.0306 ;
		RECT 0.0098 43.0808 0.0481 43.1812 ;
		RECT 0.0714 43.2314 0.1097 43.269 ;
		RECT 0.0098 43.2941 0.0481 43.3318 ;
		RECT 0.0714 43.382 0.1097 43.4196 ;
		 LAYER M2 SPACING 0.012 ;
		RECT 0.0714 45.3396 0.1097 45.44 ;
		RECT 0.0714 46.6949 0.1097 46.7953 ;
		RECT 0.0714 47.2973 0.1097 47.3976 ;
		RECT 0.0714 47.5984 0.1097 47.6988 ;
		RECT 0.0714 47.749 0.1097 47.8494 ;
		RECT 0.0714 48.3514 0.1097 48.4518 ;
		RECT 0.0714 42.4784 0.1097 42.5161 ;
		RECT 0.0098 42.5412 0.0481 42.5788 ;
		RECT 0.0098 43.5953 0.0481 43.6329 ;
		RECT 0.0714 43.8337 0.1097 43.8714 ;
		RECT 0.0098 43.8965 0.0481 43.9341 ;
		RECT 0.0714 43.9843 0.1097 44.022 ;
		RECT 0.0098 44.1349 0.0481 44.2353 ;
		RECT 0.0714 44.5867 0.1097 44.6243 ;
		RECT 0.0098 44.6494 0.0481 44.6871 ;
		RECT 0.0714 44.7373 0.1097 44.7749 ;
		RECT 0.0098 45.2518 0.0481 45.2894 ;
		RECT 0.0098 45.3396 0.0481 45.3773 ;
		RECT 0.0714 42.629 0.1097 42.6667 ;
		RECT 0.0714 45.4902 0.1097 45.5278 ;
		RECT 0.0714 45.6408 0.1097 45.6784 ;
		RECT 0.0714 46.3937 0.1097 46.4314 ;
		RECT 0.0098 46.6071 0.0481 46.6447 ;
		RECT 0.0098 46.7576 0.0481 46.7953 ;
		RECT 0.0714 46.8455 0.1097 46.8831 ;
		RECT 0.0714 47.1467 0.1097 47.1843 ;
		RECT 0.0098 47.36 0.0481 47.3976 ;
		RECT 0.0098 47.5106 0.0481 47.5482 ;
		RECT 0.0098 47.5984 0.0481 47.6361 ;
		RECT 0.0098 42.6918 0.0481 42.7294 ;
		RECT 0.0098 47.8996 0.0481 47.9373 ;
		RECT 0.0714 47.9624 0.1097 48 ;
		RECT 0.0098 48.4141 0.0481 48.4518 ;
		RECT 0.0714 48.8031 0.1097 48.8408 ;
		RECT 0.0098 48.8659 0.0481 48.9035 ;
		RECT 0.0098 48.9537 0.0481 49.0541 ;
		RECT 0.0098 49.1671 0.0481 49.2047 ;
		RECT 0.0098 49.3176 0.0481 49.3553 ;
		RECT 0.0714 49.4055 0.1097 49.4431 ;
		RECT 0.0098 49.4682 0.0481 49.5059 ;
		RECT 0.0098 42.8424 0.0481 42.88 ;
		RECT 0.0098 49.5561 0.0481 49.6565 ;
		RECT 0.0714 49.7067 0.1097 49.7443 ;
		RECT 0.0098 49.7694 0.0481 49.8071 ;
		RECT 0.0714 49.8573 0.1097 49.8949 ;
		RECT 0.0098 50.0078 0.0481 50.1082 ;
		RECT 0.0098 0.1255 0.0481 0.1631 ;
		RECT 0.0098 92.4675 0.0481 92.5051 ;
		RECT 0.0098 42.9929 0.0481 43.0306 ;
		RECT 0.0098 43.0808 0.0481 43.1812 ;
		RECT 0.0714 43.2314 0.1097 43.269 ;
		RECT 0.0098 43.2941 0.0481 43.3318 ;
		RECT 0.0714 43.382 0.1097 43.4196 ;
		 LAYER M3 SPACING 0.012 ;
		RECT 0.133 0 21.693 92.6306 ;
		RECT 0 0 0.133 0.0439 ;
		RECT 0 0.182 0.133 0.9475 ;
		RECT 0.0714 1.0918 0.133 1.2235 ;
		RECT 0 1.211 0.133 1.2235 ;
		RECT 0.0714 1.2235 0.133 1.349 ;
		RECT 0 1.4871 0.133 2.2275 ;
		RECT 0.0714 2.3718 0.133 2.5035 ;
		RECT 0 2.491 0.133 2.5035 ;
		RECT 0.0714 2.5035 0.133 2.629 ;
		RECT 0 2.7671 0.133 3.5075 ;
		RECT 0.0714 3.6518 0.133 3.7835 ;
		RECT 0 3.771 0.133 3.7835 ;
		RECT 0.0714 3.7835 0.133 3.909 ;
		RECT 0 4.0471 0.133 4.7875 ;
		RECT 0.0714 4.9318 0.133 5.0635 ;
		RECT 0 5.051 0.133 5.0635 ;
		RECT 0.0714 5.0635 0.133 5.189 ;
		RECT 0 5.3271 0.133 6.0675 ;
		RECT 0.0714 6.2118 0.133 6.3435 ;
		RECT 0 6.331 0.133 6.3435 ;
		RECT 0.0714 6.3435 0.133 6.469 ;
		RECT 0 6.6071 0.133 7.3475 ;
		RECT 0.0714 7.4918 0.133 7.6235 ;
		RECT 0 7.611 0.133 7.6235 ;
		RECT 0.0714 7.6235 0.133 7.749 ;
		RECT 0 7.8871 0.133 8.6275 ;
		RECT 0.0714 8.7718 0.133 8.9035 ;
		RECT 0 8.891 0.133 8.9035 ;
		RECT 0.0714 8.9035 0.133 9.029 ;
		RECT 0 9.1671 0.133 9.9075 ;
		RECT 0.0714 10.0518 0.133 10.1835 ;
		RECT 0 10.171 0.133 10.1835 ;
		RECT 0.0714 10.1835 0.133 10.309 ;
		RECT 0 10.4471 0.133 11.1875 ;
		RECT 0.0714 11.3318 0.133 11.4635 ;
		RECT 0 11.451 0.133 11.4635 ;
		RECT 0.0714 11.4635 0.133 11.589 ;
		RECT 0 11.7271 0.133 12.4675 ;
		RECT 0.0714 12.6118 0.133 12.7435 ;
		RECT 0 12.731 0.133 12.7435 ;
		RECT 0.0714 12.7435 0.133 12.869 ;
		RECT 0 13.0071 0.133 13.7475 ;
		RECT 0.0714 13.8918 0.133 14.0235 ;
		RECT 0 14.011 0.133 14.0235 ;
		RECT 0.0714 14.0235 0.133 14.149 ;
		RECT 0 14.2871 0.133 15.0275 ;
		RECT 0.0714 15.1718 0.133 15.3035 ;
		RECT 0 15.291 0.133 15.3035 ;
		RECT 0.0714 15.3035 0.133 15.429 ;
		RECT 0 15.5671 0.133 16.3075 ;
		RECT 0.0714 16.4518 0.133 16.5835 ;
		RECT 0 16.571 0.133 16.5835 ;
		RECT 0.0714 16.5835 0.133 16.709 ;
		RECT 0 16.8471 0.133 17.5875 ;
		RECT 0.0714 17.7318 0.133 17.8635 ;
		RECT 0 17.851 0.133 17.8635 ;
		RECT 0.0714 17.8635 0.133 17.989 ;
		RECT 0 18.1271 0.133 18.8675 ;
		RECT 0.0714 19.0118 0.133 19.1435 ;
		RECT 0 19.131 0.133 19.1435 ;
		RECT 0.0714 19.1435 0.133 19.269 ;
		RECT 0 19.4071 0.133 20.1475 ;
		RECT 0.0714 20.2918 0.133 20.4235 ;
		RECT 0 20.411 0.133 20.4235 ;
		RECT 0.0714 20.4235 0.133 20.549 ;
		RECT 0 20.6871 0.133 21.4275 ;
		RECT 0.0714 21.5718 0.133 21.7035 ;
		RECT 0 21.691 0.133 21.7035 ;
		RECT 0.0714 21.7035 0.133 21.829 ;
		RECT 0 21.9671 0.133 22.7075 ;
		RECT 0.0714 22.8518 0.133 22.9835 ;
		RECT 0 22.971 0.133 22.9835 ;
		RECT 0.0714 22.9835 0.133 23.109 ;
		RECT 0 23.2471 0.133 23.9875 ;
		RECT 0.0714 24.1318 0.133 24.2635 ;
		RECT 0 24.251 0.133 24.2635 ;
		RECT 0.0714 24.2635 0.133 24.389 ;
		RECT 0 24.5271 0.133 25.2675 ;
		RECT 0.0714 25.4118 0.133 25.5435 ;
		RECT 0 25.531 0.133 25.5435 ;
		RECT 0.0714 25.5435 0.133 25.669 ;
		RECT 0 25.8071 0.133 26.5475 ;
		RECT 0.0714 26.6918 0.133 26.8235 ;
		RECT 0 26.811 0.133 26.8235 ;
		RECT 0.0714 26.8235 0.133 26.949 ;
		RECT 0 27.0871 0.133 27.8275 ;
		RECT 0.0714 27.9718 0.133 28.1035 ;
		RECT 0 28.091 0.133 28.1035 ;
		RECT 0.0714 28.1035 0.133 28.229 ;
		RECT 0 28.3671 0.133 29.1075 ;
		RECT 0.0714 29.2518 0.133 29.3835 ;
		RECT 0 29.371 0.133 29.3835 ;
		RECT 0.0714 29.3835 0.133 29.509 ;
		RECT 0 29.6471 0.133 30.3875 ;
		RECT 0.0714 30.5318 0.133 30.6635 ;
		RECT 0 30.651 0.133 30.6635 ;
		RECT 0.0714 30.6635 0.133 30.789 ;
		RECT 0 30.9271 0.133 31.6675 ;
		RECT 0.0714 31.8118 0.133 31.9435 ;
		RECT 0 31.931 0.133 31.9435 ;
		RECT 0.0714 31.9435 0.133 32.069 ;
		RECT 0 32.2071 0.133 32.9475 ;
		RECT 0.0714 33.0918 0.133 33.2235 ;
		RECT 0 33.211 0.133 33.2235 ;
		RECT 0.0714 33.2235 0.133 33.349 ;
		RECT 0 33.4871 0.133 34.2275 ;
		RECT 0.0714 34.3718 0.133 34.5035 ;
		RECT 0 34.491 0.133 34.5035 ;
		RECT 0.0714 34.5035 0.133 34.629 ;
		RECT 0 34.7671 0.133 35.5075 ;
		RECT 0.0714 35.6518 0.133 35.7835 ;
		RECT 0 35.771 0.133 35.7835 ;
		RECT 0.0714 35.7835 0.133 35.909 ;
		RECT 0 36.0471 0.133 36.7875 ;
		RECT 0.0714 36.9318 0.133 37.0635 ;
		RECT 0 37.051 0.133 37.0635 ;
		RECT 0.0714 37.0635 0.133 37.189 ;
		RECT 0 37.3271 0.133 38.0675 ;
		RECT 0.0714 38.2118 0.133 38.3435 ;
		RECT 0 38.331 0.133 38.3435 ;
		RECT 0.0714 38.3435 0.133 38.469 ;
		RECT 0 38.6071 0.133 39.3475 ;
		RECT 0.0714 39.4918 0.133 39.6235 ;
		RECT 0 39.611 0.133 39.6235 ;
		RECT 0.0714 39.6235 0.133 39.749 ;
		RECT 0 39.8871 0.133 40.6275 ;
		RECT 0.0714 40.7718 0.133 40.9035 ;
		RECT 0 40.891 0.133 40.9035 ;
		RECT 0.0714 40.9035 0.133 41.029 ;
		RECT 0 41.1671 0.133 41.9075 ;
		RECT 0.0714 42.0518 0.133 42.1835 ;
		RECT 0 42.171 0.133 42.1835 ;
		RECT 0.0714 42.1835 0.133 42.309 ;
		RECT 0 42.4471 0.133 42.7608 ;
		RECT 0 42.8988 0.133 42.9114 ;
		RECT 0 43.0494 0.133 43.3631 ;
		RECT 0 43.5012 0.133 43.5137 ;
		RECT 0 43.6518 0.133 43.6643 ;
		RECT 0 43.8024 0.133 43.9655 ;
		RECT 0 44.1035 0.133 44.2667 ;
		RECT 0 44.4047 0.133 44.4173 ;
		RECT 0 44.5553 0.133 44.7184 ;
		RECT 0 44.8565 0.133 44.869 ;
		RECT 0 45.0071 0.133 45.0196 ;
		RECT 0 45.1576 0.133 45.1702 ;
		RECT 0 45.3082 0.133 45.3208 ;
		RECT 0 45.4588 0.133 45.4714 ;
		RECT 0 45.6094 0.133 45.622 ;
		RECT 0 45.76 0.133 45.7725 ;
		RECT 0 45.9106 0.133 45.9231 ;
		RECT 0 46.0612 0.133 46.0737 ;
		RECT 0 46.2118 0.133 46.2243 ;
		RECT 0 46.3624 0.133 46.3749 ;
		RECT 0 46.5129 0.133 46.5255 ;
		RECT 0 46.6635 0.133 46.6761 ;
		RECT 0 46.8141 0.133 46.8267 ;
		RECT 0 46.9647 0.133 46.9773 ;
		RECT 0 47.1153 0.133 47.1278 ;
		RECT 0 47.2659 0.133 47.2784 ;
		RECT 0 47.4165 0.133 47.429 ;
		RECT 0 47.5671 0.133 47.5796 ;
		RECT 0 47.7176 0.133 47.7302 ;
		RECT 0 47.8682 0.133 48.0314 ;
		RECT 0 48.1694 0.133 48.182 ;
		RECT 0 48.32 0.133 48.3325 ;
		RECT 0 48.4706 0.133 48.4831 ;
		RECT 0 48.6212 0.133 48.6337 ;
		RECT 0 48.7718 0.133 49.0855 ;
		RECT 0 49.2235 0.133 49.2361 ;
		RECT 0 49.3741 0.133 49.8384 ;
		RECT 0 49.9765 0.133 50.1835 ;
		RECT 0.0714 50.3278 0.133 50.4596 ;
		RECT 0 50.4471 0.133 50.4596 ;
		RECT 0.0714 50.4596 0.133 50.5851 ;
		RECT 0 50.7231 0.133 51.4635 ;
		RECT 0.0714 51.6078 0.133 51.7396 ;
		RECT 0 51.7271 0.133 51.7396 ;
		RECT 0.0714 51.7396 0.133 51.8651 ;
		RECT 0 52.0031 0.133 52.7435 ;
		RECT 0.0714 52.8878 0.133 53.0196 ;
		RECT 0 53.0071 0.133 53.0196 ;
		RECT 0.0714 53.0196 0.133 53.1451 ;
		RECT 0 53.2831 0.133 54.0235 ;
		RECT 0.0714 54.1678 0.133 54.2996 ;
		RECT 0 54.2871 0.133 54.2996 ;
		RECT 0.0714 54.2996 0.133 54.4251 ;
		RECT 0 54.5631 0.133 55.3035 ;
		RECT 0.0714 55.4478 0.133 55.5796 ;
		RECT 0 55.5671 0.133 55.5796 ;
		RECT 0.0714 55.5796 0.133 55.7051 ;
		RECT 0 55.8431 0.133 56.5835 ;
		RECT 0.0714 56.7278 0.133 56.8596 ;
		RECT 0 56.8471 0.133 56.8596 ;
		RECT 0.0714 56.8596 0.133 56.9851 ;
		RECT 0 57.1231 0.133 57.8635 ;
		RECT 0.0714 58.0078 0.133 58.1396 ;
		RECT 0 58.1271 0.133 58.1396 ;
		RECT 0.0714 58.1396 0.133 58.2651 ;
		RECT 0 58.4031 0.133 59.1435 ;
		RECT 0.0714 59.2878 0.133 59.4196 ;
		RECT 0 59.4071 0.133 59.4196 ;
		RECT 0.0714 59.4196 0.133 59.5451 ;
		RECT 0 59.6831 0.133 60.4235 ;
		RECT 0.0714 60.5678 0.133 60.6996 ;
		RECT 0 60.6871 0.133 60.6996 ;
		RECT 0.0714 60.6996 0.133 60.8251 ;
		RECT 0 60.9631 0.133 61.7035 ;
		RECT 0.0714 61.8478 0.133 61.9796 ;
		RECT 0 61.9671 0.133 61.9796 ;
		RECT 0.0714 61.9796 0.133 62.1051 ;
		RECT 0 62.2431 0.133 62.9835 ;
		RECT 0.0714 63.1278 0.133 63.2596 ;
		RECT 0 63.2471 0.133 63.2596 ;
		RECT 0.0714 63.2596 0.133 63.3851 ;
		RECT 0 63.5231 0.133 64.2635 ;
		RECT 0.0714 64.4078 0.133 64.5396 ;
		RECT 0 64.5271 0.133 64.5396 ;
		RECT 0.0714 64.5396 0.133 64.6651 ;
		RECT 0 64.8031 0.133 65.5435 ;
		RECT 0.0714 65.6878 0.133 65.8196 ;
		RECT 0 65.8071 0.133 65.8196 ;
		RECT 0.0714 65.8196 0.133 65.9451 ;
		RECT 0 66.0831 0.133 66.8235 ;
		RECT 0.0714 66.9678 0.133 67.0996 ;
		RECT 0 67.0871 0.133 67.0996 ;
		RECT 0.0714 67.0996 0.133 67.2251 ;
		RECT 0 67.3631 0.133 68.1035 ;
		RECT 0.0714 68.2478 0.133 68.3796 ;
		RECT 0 68.3671 0.133 68.3796 ;
		RECT 0.0714 68.3796 0.133 68.5051 ;
		RECT 0 68.6431 0.133 69.3835 ;
		RECT 0.0714 69.5278 0.133 69.6596 ;
		RECT 0 69.6471 0.133 69.6596 ;
		RECT 0.0714 69.6596 0.133 69.7851 ;
		RECT 0 69.9231 0.133 70.6635 ;
		RECT 0.0714 70.8078 0.133 70.9396 ;
		RECT 0 70.9271 0.133 70.9396 ;
		RECT 0.0714 70.9396 0.133 71.0651 ;
		RECT 0 71.2031 0.133 71.9435 ;
		RECT 0.0714 72.0878 0.133 72.2196 ;
		RECT 0 72.2071 0.133 72.2196 ;
		RECT 0.0714 72.2196 0.133 72.3451 ;
		RECT 0 72.4831 0.133 73.2235 ;
		RECT 0.0714 73.3678 0.133 73.4996 ;
		RECT 0 73.4871 0.133 73.4996 ;
		RECT 0.0714 73.4996 0.133 73.6251 ;
		RECT 0 73.7631 0.133 74.5035 ;
		RECT 0.0714 74.6478 0.133 74.7796 ;
		RECT 0 74.7671 0.133 74.7796 ;
		RECT 0.0714 74.7796 0.133 74.9051 ;
		RECT 0 75.0431 0.133 75.7835 ;
		RECT 0.0714 75.9278 0.133 76.0596 ;
		RECT 0 76.0471 0.133 76.0596 ;
		RECT 0.0714 76.0596 0.133 76.1851 ;
		RECT 0 76.3231 0.133 77.0635 ;
		RECT 0.0714 77.2078 0.133 77.3396 ;
		RECT 0 77.3271 0.133 77.3396 ;
		RECT 0.0714 77.3396 0.133 77.4651 ;
		RECT 0 77.6031 0.133 78.3435 ;
		RECT 0.0714 78.4878 0.133 78.6196 ;
		RECT 0 78.6071 0.133 78.6196 ;
		RECT 0.0714 78.6196 0.133 78.7451 ;
		RECT 0 78.8831 0.133 79.6235 ;
		RECT 0.0714 79.7678 0.133 79.8996 ;
		RECT 0 79.8871 0.133 79.8996 ;
		RECT 0.0714 79.8996 0.133 80.0251 ;
		RECT 0 80.1631 0.133 80.9035 ;
		RECT 0.0714 81.0478 0.133 81.1796 ;
		RECT 0 81.1671 0.133 81.1796 ;
		RECT 0.0714 81.1796 0.133 81.3051 ;
		RECT 0 81.4431 0.133 82.1835 ;
		RECT 0.0714 82.3278 0.133 82.4596 ;
		RECT 0 82.4471 0.133 82.4596 ;
		RECT 0.0714 82.4596 0.133 82.5851 ;
		RECT 0 82.7231 0.133 83.4635 ;
		RECT 0.0714 83.6078 0.133 83.7396 ;
		RECT 0 83.7271 0.133 83.7396 ;
		RECT 0.0714 83.7396 0.133 83.8651 ;
		RECT 0 84.0031 0.133 84.7435 ;
		RECT 0.0714 84.8878 0.133 85.0196 ;
		RECT 0 85.0071 0.133 85.0196 ;
		RECT 0.0714 85.0196 0.133 85.1451 ;
		RECT 0 85.2831 0.133 86.0235 ;
		RECT 0.0714 86.1678 0.133 86.2996 ;
		RECT 0 86.2871 0.133 86.2996 ;
		RECT 0.0714 86.2996 0.133 86.4251 ;
		RECT 0 86.5631 0.133 87.3035 ;
		RECT 0.0714 87.4478 0.133 87.5796 ;
		RECT 0 87.5671 0.133 87.5796 ;
		RECT 0.0714 87.5796 0.133 87.7051 ;
		RECT 0 87.8431 0.133 88.5835 ;
		RECT 0.0714 88.7278 0.133 88.8596 ;
		RECT 0 88.8471 0.133 88.8596 ;
		RECT 0.0714 88.8596 0.133 88.9851 ;
		RECT 0 89.1231 0.133 89.8635 ;
		RECT 0.0714 90.0078 0.133 90.1396 ;
		RECT 0 90.1271 0.133 90.1396 ;
		RECT 0.0714 90.1396 0.133 90.2651 ;
		RECT 0 90.4031 0.133 91.1435 ;
		RECT 0.0714 91.2878 0.133 91.4196 ;
		RECT 0 91.4071 0.133 91.4196 ;
		RECT 0.0714 91.4196 0.133 91.5451 ;
		RECT 0 91.6831 0.133 92.4486 ;
		RECT 0 92.5867 0.133 92.6306 ;
		 LAYER M3 ;
		RECT 0.0098 42.4784 0.0481 42.5788 ;
		RECT 0.0714 42.4784 0.1097 42.5788 ;
		RECT 0.0098 42.629 0.0481 42.7294 ;
		RECT 0.0714 42.629 0.1097 42.7294 ;
		RECT 0.0098 42.7796 0.0481 42.88 ;
		RECT 0.0098 42.9302 0.0481 43.0306 ;
		RECT 0.0098 43.0808 0.0481 43.1812 ;
		RECT 0.0098 43.2314 0.0481 43.3318 ;
		RECT 0.0714 43.2314 0.1097 43.3318 ;
		RECT 0.0714 43.382 0.1097 43.4824 ;
		RECT 0.0098 43.5325 0.0481 43.6329 ;
		RECT 0.0098 43.8337 0.0481 43.9341 ;
		RECT 0.0714 43.8337 0.1097 43.9341 ;
		RECT 0.0714 43.9843 0.1097 44.0847 ;
		RECT 0.0098 44.1349 0.0481 44.2353 ;
		RECT 0.0098 44.5867 0.0481 44.6871 ;
		RECT 0.0714 44.5867 0.1097 44.6871 ;
		RECT 0.0714 44.7373 0.1097 44.8376 ;
		RECT 0.0098 45.189 0.0481 45.2894 ;
		RECT 0.0714 45.3396 0.1097 45.44 ;
		RECT 0.0714 45.4902 0.1097 45.5906 ;
		RECT 0.0714 45.6408 0.1097 45.7412 ;
		RECT 0.0714 46.3937 0.1097 46.4941 ;
		RECT 0.0098 46.5443 0.0481 46.6447 ;
		RECT 0.0714 46.6949 0.1097 46.7953 ;
		RECT 0.0714 46.8455 0.1097 46.9459 ;
		RECT 0.0714 47.1467 0.1097 47.2471 ;
		RECT 0.0098 47.4478 0.0481 47.5482 ;
		RECT 0.0098 47.8996 0.0481 48 ;
		RECT 0.0714 47.8996 0.1097 48 ;
		RECT 0.0098 48.8031 0.0481 48.9035 ;
		RECT 0.0714 48.8031 0.1097 48.9035 ;
		RECT 0.0098 48.9537 0.0481 49.0541 ;
		RECT 0.0098 49.1043 0.0481 49.2047 ;
		RECT 0.0098 49.2549 0.0481 49.3553 ;
		RECT 0.0098 49.4055 0.0481 49.5059 ;
		RECT 0.0714 49.4055 0.1097 49.5059 ;
		RECT 0.0098 49.5561 0.0481 49.6565 ;
		RECT 0.0098 49.7067 0.0481 49.8071 ;
		RECT 0.0714 49.7067 0.1097 49.8071 ;
		RECT 0.0714 49.8573 0.1097 49.9576 ;
		RECT 0.0098 50.0078 0.0481 50.1082 ;
		RECT 0.0098 0.0627 0.0481 0.1631 ;
		RECT 0.0098 92.4675 0.0481 92.5678 ;
		 LAYER M3 SPACING 0.012 ;
		RECT 0.0098 42.4784 0.0481 42.5788 ;
		RECT 0.0714 42.4784 0.1097 42.5788 ;
		RECT 0.0098 42.629 0.0481 42.7294 ;
		RECT 0.0714 42.629 0.1097 42.7294 ;
		RECT 0.0098 42.7796 0.0481 42.88 ;
		RECT 0.0098 42.9302 0.0481 43.0306 ;
		RECT 0.0098 43.0808 0.0481 43.1812 ;
		RECT 0.0098 43.2314 0.0481 43.3318 ;
		RECT 0.0714 43.2314 0.1097 43.3318 ;
		RECT 0.0714 43.382 0.1097 43.4824 ;
		RECT 0.0098 43.5325 0.0481 43.6329 ;
		RECT 0.0098 43.8337 0.0481 43.9341 ;
		RECT 0.0714 43.8337 0.1097 43.9341 ;
		RECT 0.0714 43.9843 0.1097 44.0847 ;
		RECT 0.0098 44.1349 0.0481 44.2353 ;
		RECT 0.0098 44.5867 0.0481 44.6871 ;
		RECT 0.0714 44.5867 0.1097 44.6871 ;
		RECT 0.0714 44.7373 0.1097 44.8376 ;
		RECT 0.0098 45.189 0.0481 45.2894 ;
		RECT 0.0714 45.3396 0.1097 45.44 ;
		RECT 0.0714 45.4902 0.1097 45.5906 ;
		RECT 0.0714 45.6408 0.1097 45.7412 ;
		RECT 0.0714 46.3937 0.1097 46.4941 ;
		RECT 0.0098 46.5443 0.0481 46.6447 ;
		RECT 0.0714 46.6949 0.1097 46.7953 ;
		RECT 0.0714 46.8455 0.1097 46.9459 ;
		RECT 0.0714 47.1467 0.1097 47.2471 ;
		RECT 0.0098 47.4478 0.0481 47.5482 ;
		RECT 0.0098 47.8996 0.0481 48 ;
		RECT 0.0714 47.8996 0.1097 48 ;
		RECT 0.0098 48.8031 0.0481 48.9035 ;
		RECT 0.0714 48.8031 0.1097 48.9035 ;
		RECT 0.0098 48.9537 0.0481 49.0541 ;
		RECT 0.0098 49.1043 0.0481 49.2047 ;
		RECT 0.0098 49.2549 0.0481 49.3553 ;
		RECT 0.0098 49.4055 0.0481 49.5059 ;
		RECT 0.0714 49.4055 0.1097 49.5059 ;
		RECT 0.0098 49.5561 0.0481 49.6565 ;
		RECT 0.0098 49.7067 0.0481 49.8071 ;
		RECT 0.0714 49.7067 0.1097 49.8071 ;
		RECT 0.0714 49.8573 0.1097 49.9576 ;
		RECT 0.0098 50.0078 0.0481 50.1082 ;
		RECT 0.0098 0.0627 0.0481 0.1631 ;
		RECT 0.0098 92.4675 0.0481 92.5678 ;
		 LAYER M4 SPACING 0.018 ;
		RECT 0.2105 0.3286 21.546 0.5302 ;
		RECT 21.546 0.3286 21.693 0.5302 ;
		RECT 0.2105 0.64 21.546 0.7631 ;
		RECT 21.546 0.64 21.693 0.7631 ;
		RECT 0.2105 0.9686 21.546 1.1702 ;
		RECT 21.546 0.9686 21.693 1.1702 ;
		RECT 0.2105 1.28 21.546 1.4031 ;
		RECT 21.546 1.28 21.693 1.4031 ;
		RECT 0.2105 1.6086 21.546 1.8102 ;
		RECT 21.546 1.6086 21.693 1.8102 ;
		RECT 0.2105 1.92 21.546 2.0431 ;
		RECT 21.546 1.92 21.693 2.0431 ;
		RECT 0.2105 2.2486 21.546 2.4502 ;
		RECT 21.546 2.2486 21.693 2.4502 ;
		RECT 0.2105 2.56 21.546 2.6831 ;
		RECT 21.546 2.56 21.693 2.6831 ;
		RECT 0.2105 2.8886 21.546 3.0902 ;
		RECT 21.546 2.8886 21.693 3.0902 ;
		RECT 0.2105 3.2 21.546 3.3231 ;
		RECT 21.546 3.2 21.693 3.3231 ;
		RECT 0.2105 3.5286 21.546 3.7302 ;
		RECT 21.546 3.5286 21.693 3.7302 ;
		RECT 0.2105 3.84 21.546 3.9631 ;
		RECT 21.546 3.84 21.693 3.9631 ;
		RECT 0.2105 4.1686 21.546 4.3702 ;
		RECT 21.546 4.1686 21.693 4.3702 ;
		RECT 0.2105 4.48 21.546 4.6031 ;
		RECT 21.546 4.48 21.693 4.6031 ;
		RECT 0.2105 4.8086 21.546 5.0102 ;
		RECT 21.546 4.8086 21.693 5.0102 ;
		RECT 0.2105 5.12 21.546 5.2431 ;
		RECT 21.546 5.12 21.693 5.2431 ;
		RECT 0.2105 5.4486 21.546 5.6502 ;
		RECT 21.546 5.4486 21.693 5.6502 ;
		RECT 0.2105 5.76 21.546 5.8831 ;
		RECT 21.546 5.76 21.693 5.8831 ;
		RECT 0.2105 6.0886 21.546 6.2902 ;
		RECT 21.546 6.0886 21.693 6.2902 ;
		RECT 0.2105 6.4 21.546 6.5231 ;
		RECT 21.546 6.4 21.693 6.5231 ;
		RECT 0.2105 6.7286 21.546 6.9302 ;
		RECT 21.546 6.7286 21.693 6.9302 ;
		RECT 0.2105 7.04 21.546 7.1631 ;
		RECT 21.546 7.04 21.693 7.1631 ;
		RECT 0.2105 7.3686 21.546 7.5702 ;
		RECT 21.546 7.3686 21.693 7.5702 ;
		RECT 0.2105 7.68 21.546 7.8031 ;
		RECT 21.546 7.68 21.693 7.8031 ;
		RECT 0.2105 8.0086 21.546 8.2102 ;
		RECT 21.546 8.0086 21.693 8.2102 ;
		RECT 0.2105 8.32 21.546 8.4431 ;
		RECT 21.546 8.32 21.693 8.4431 ;
		RECT 0.2105 8.6486 21.546 8.8502 ;
		RECT 21.546 8.6486 21.693 8.8502 ;
		RECT 0.2105 8.96 21.546 9.0831 ;
		RECT 21.546 8.96 21.693 9.0831 ;
		RECT 0.2105 9.2886 21.546 9.4902 ;
		RECT 21.546 9.2886 21.693 9.4902 ;
		RECT 0.2105 9.6 21.546 9.7231 ;
		RECT 21.546 9.6 21.693 9.7231 ;
		RECT 0.2105 9.9286 21.546 10.1302 ;
		RECT 21.546 9.9286 21.693 10.1302 ;
		RECT 0.2105 10.24 21.546 10.3631 ;
		RECT 21.546 10.24 21.693 10.3631 ;
		RECT 0.2105 10.5686 21.546 10.7702 ;
		RECT 21.546 10.5686 21.693 10.7702 ;
		RECT 0.2105 10.88 21.546 11.0031 ;
		RECT 21.546 10.88 21.693 11.0031 ;
		RECT 0.2105 11.2086 21.546 11.4102 ;
		RECT 21.546 11.2086 21.693 11.4102 ;
		RECT 0.2105 11.52 21.546 11.6431 ;
		RECT 21.546 11.52 21.693 11.6431 ;
		RECT 0.2105 11.8486 21.546 12.0502 ;
		RECT 21.546 11.8486 21.693 12.0502 ;
		RECT 0.2105 12.16 21.546 12.2831 ;
		RECT 21.546 12.16 21.693 12.2831 ;
		RECT 0.2105 12.4886 21.546 12.6902 ;
		RECT 21.546 12.4886 21.693 12.6902 ;
		RECT 0.2105 12.8 21.546 12.9231 ;
		RECT 21.546 12.8 21.693 12.9231 ;
		RECT 0.2105 13.1286 21.546 13.3302 ;
		RECT 21.546 13.1286 21.693 13.3302 ;
		RECT 0.2105 13.44 21.546 13.5631 ;
		RECT 21.546 13.44 21.693 13.5631 ;
		RECT 0.2105 13.7686 21.546 13.9702 ;
		RECT 21.546 13.7686 21.693 13.9702 ;
		RECT 0.2105 14.08 21.546 14.2031 ;
		RECT 21.546 14.08 21.693 14.2031 ;
		RECT 0.2105 14.4086 21.546 14.6102 ;
		RECT 21.546 14.4086 21.693 14.6102 ;
		RECT 0.2105 14.72 21.546 14.8431 ;
		RECT 21.546 14.72 21.693 14.8431 ;
		RECT 0.2105 15.0486 21.546 15.2502 ;
		RECT 21.546 15.0486 21.693 15.2502 ;
		RECT 0.2105 15.36 21.546 15.4831 ;
		RECT 21.546 15.36 21.693 15.4831 ;
		RECT 0.2105 15.6886 21.546 15.8902 ;
		RECT 21.546 15.6886 21.693 15.8902 ;
		RECT 0.2105 16 21.546 16.1231 ;
		RECT 21.546 16 21.693 16.1231 ;
		RECT 0.2105 16.3286 21.546 16.5302 ;
		RECT 21.546 16.3286 21.693 16.5302 ;
		RECT 0.2105 16.64 21.546 16.7631 ;
		RECT 21.546 16.64 21.693 16.7631 ;
		RECT 0.2105 16.9686 21.546 17.1702 ;
		RECT 21.546 16.9686 21.693 17.1702 ;
		RECT 0.2105 17.28 21.546 17.4031 ;
		RECT 21.546 17.28 21.693 17.4031 ;
		RECT 0.2105 17.6086 21.546 17.8102 ;
		RECT 21.546 17.6086 21.693 17.8102 ;
		RECT 0.2105 17.92 21.546 18.0431 ;
		RECT 21.546 17.92 21.693 18.0431 ;
		RECT 0.2105 18.2486 21.546 18.4502 ;
		RECT 21.546 18.2486 21.693 18.4502 ;
		RECT 0.2105 18.56 21.546 18.6831 ;
		RECT 21.546 18.56 21.693 18.6831 ;
		RECT 0.2105 18.8886 21.546 19.0902 ;
		RECT 21.546 18.8886 21.693 19.0902 ;
		RECT 0.2105 19.2 21.546 19.3231 ;
		RECT 21.546 19.2 21.693 19.3231 ;
		RECT 0.2105 19.5286 21.546 19.7302 ;
		RECT 21.546 19.5286 21.693 19.7302 ;
		RECT 0.2105 19.84 21.546 19.9631 ;
		RECT 21.546 19.84 21.693 19.9631 ;
		RECT 0.2105 20.1686 21.546 20.3702 ;
		RECT 21.546 20.1686 21.693 20.3702 ;
		RECT 0.2105 20.48 21.546 20.6031 ;
		RECT 21.546 20.48 21.693 20.6031 ;
		RECT 0.2105 20.8086 21.546 21.0102 ;
		RECT 21.546 20.8086 21.693 21.0102 ;
		RECT 0.2105 21.12 21.546 21.2431 ;
		RECT 21.546 21.12 21.693 21.2431 ;
		RECT 0.2105 21.4486 21.546 21.6502 ;
		RECT 21.546 21.4486 21.693 21.6502 ;
		RECT 0.2105 21.76 21.546 21.8831 ;
		RECT 21.546 21.76 21.693 21.8831 ;
		RECT 0.2105 22.0886 21.546 22.2902 ;
		RECT 21.546 22.0886 21.693 22.2902 ;
		RECT 0.2105 22.4 21.546 22.5231 ;
		RECT 21.546 22.4 21.693 22.5231 ;
		RECT 0.2105 22.7286 21.546 22.9302 ;
		RECT 21.546 22.7286 21.693 22.9302 ;
		RECT 0.2105 23.04 21.546 23.1631 ;
		RECT 21.546 23.04 21.693 23.1631 ;
		RECT 0.2105 23.3686 21.546 23.5702 ;
		RECT 21.546 23.3686 21.693 23.5702 ;
		RECT 0.2105 23.68 21.546 23.8031 ;
		RECT 21.546 23.68 21.693 23.8031 ;
		RECT 0.2105 24.0086 21.546 24.2102 ;
		RECT 21.546 24.0086 21.693 24.2102 ;
		RECT 0.2105 24.32 21.546 24.4431 ;
		RECT 21.546 24.32 21.693 24.4431 ;
		RECT 0.2105 24.6486 21.546 24.8502 ;
		RECT 21.546 24.6486 21.693 24.8502 ;
		RECT 0.2105 24.96 21.546 25.0831 ;
		RECT 21.546 24.96 21.693 25.0831 ;
		RECT 0.2105 25.2886 21.546 25.4902 ;
		RECT 21.546 25.2886 21.693 25.4902 ;
		RECT 0.2105 25.6 21.546 25.7231 ;
		RECT 21.546 25.6 21.693 25.7231 ;
		RECT 0.2105 25.9286 21.546 26.1302 ;
		RECT 21.546 25.9286 21.693 26.1302 ;
		RECT 0.2105 26.24 21.546 26.3631 ;
		RECT 21.546 26.24 21.693 26.3631 ;
		RECT 0.2105 26.5686 21.546 26.7702 ;
		RECT 21.546 26.5686 21.693 26.7702 ;
		RECT 0.2105 26.88 21.546 27.0031 ;
		RECT 21.546 26.88 21.693 27.0031 ;
		RECT 0.2105 27.2086 21.546 27.4102 ;
		RECT 21.546 27.2086 21.693 27.4102 ;
		RECT 0.2105 27.52 21.546 27.6431 ;
		RECT 21.546 27.52 21.693 27.6431 ;
		RECT 0.2105 27.8486 21.546 28.0502 ;
		RECT 21.546 27.8486 21.693 28.0502 ;
		RECT 0.2105 28.16 21.546 28.2831 ;
		RECT 21.546 28.16 21.693 28.2831 ;
		RECT 0.2105 28.4886 21.546 28.6902 ;
		RECT 21.546 28.4886 21.693 28.6902 ;
		RECT 0.2105 28.8 21.546 28.9231 ;
		RECT 21.546 28.8 21.693 28.9231 ;
		RECT 0.2105 29.1286 21.546 29.3302 ;
		RECT 21.546 29.1286 21.693 29.3302 ;
		RECT 0.2105 29.44 21.546 29.5631 ;
		RECT 21.546 29.44 21.693 29.5631 ;
		RECT 0.2105 29.7686 21.546 29.9702 ;
		RECT 21.546 29.7686 21.693 29.9702 ;
		RECT 0.2105 30.08 21.546 30.2031 ;
		RECT 21.546 30.08 21.693 30.2031 ;
		RECT 0.2105 30.4086 21.546 30.6102 ;
		RECT 21.546 30.4086 21.693 30.6102 ;
		RECT 0.2105 30.72 21.546 30.8431 ;
		RECT 21.546 30.72 21.693 30.8431 ;
		RECT 0.2105 31.0486 21.546 31.2502 ;
		RECT 21.546 31.0486 21.693 31.2502 ;
		RECT 0.2105 31.36 21.546 31.4831 ;
		RECT 21.546 31.36 21.693 31.4831 ;
		RECT 0.2105 31.6886 21.546 31.8902 ;
		RECT 21.546 31.6886 21.693 31.8902 ;
		RECT 0.2105 32 21.546 32.1231 ;
		RECT 21.546 32 21.693 32.1231 ;
		RECT 0.2105 32.3286 21.546 32.5302 ;
		RECT 21.546 32.3286 21.693 32.5302 ;
		RECT 0.2105 32.64 21.546 32.7631 ;
		RECT 21.546 32.64 21.693 32.7631 ;
		RECT 0.2105 32.9686 21.546 33.1702 ;
		RECT 21.546 32.9686 21.693 33.1702 ;
		RECT 0.2105 33.28 21.546 33.4031 ;
		RECT 21.546 33.28 21.693 33.4031 ;
		RECT 0.2105 33.6086 21.546 33.8102 ;
		RECT 21.546 33.6086 21.693 33.8102 ;
		RECT 0.2105 33.92 21.546 34.0431 ;
		RECT 21.546 33.92 21.693 34.0431 ;
		RECT 0.2105 34.2486 21.546 34.4502 ;
		RECT 21.546 34.2486 21.693 34.4502 ;
		RECT 0.2105 34.56 21.546 34.6831 ;
		RECT 21.546 34.56 21.693 34.6831 ;
		RECT 0.2105 34.8886 21.546 35.0902 ;
		RECT 21.546 34.8886 21.693 35.0902 ;
		RECT 0.2105 35.2 21.546 35.3231 ;
		RECT 21.546 35.2 21.693 35.3231 ;
		RECT 0.2105 35.5286 21.546 35.7302 ;
		RECT 21.546 35.5286 21.693 35.7302 ;
		RECT 0.2105 35.84 21.546 35.9631 ;
		RECT 21.546 35.84 21.693 35.9631 ;
		RECT 0.2105 36.1686 21.546 36.3702 ;
		RECT 21.546 36.1686 21.693 36.3702 ;
		RECT 0.2105 36.48 21.546 36.6031 ;
		RECT 21.546 36.48 21.693 36.6031 ;
		RECT 0.2105 36.8086 21.546 37.0102 ;
		RECT 21.546 36.8086 21.693 37.0102 ;
		RECT 0.2105 37.12 21.546 37.2431 ;
		RECT 21.546 37.12 21.693 37.2431 ;
		RECT 0.2105 37.4486 21.546 37.6502 ;
		RECT 21.546 37.4486 21.693 37.6502 ;
		RECT 0.2105 37.76 21.546 37.8831 ;
		RECT 21.546 37.76 21.693 37.8831 ;
		RECT 0.2105 38.0886 21.546 38.2902 ;
		RECT 21.546 38.0886 21.693 38.2902 ;
		RECT 0.2105 38.4 21.546 38.5231 ;
		RECT 21.546 38.4 21.693 38.5231 ;
		RECT 0.2105 38.7286 21.546 38.9302 ;
		RECT 21.546 38.7286 21.693 38.9302 ;
		RECT 0.2105 39.04 21.546 39.1631 ;
		RECT 21.546 39.04 21.693 39.1631 ;
		RECT 0.2105 39.3686 21.546 39.5702 ;
		RECT 21.546 39.3686 21.693 39.5702 ;
		RECT 0.2105 39.68 21.546 39.8031 ;
		RECT 21.546 39.68 21.693 39.8031 ;
		RECT 0.2105 40.0086 21.546 40.2102 ;
		RECT 21.546 40.0086 21.693 40.2102 ;
		RECT 0.2105 40.32 21.546 40.4431 ;
		RECT 21.546 40.32 21.693 40.4431 ;
		RECT 0.2105 40.6486 21.546 40.8502 ;
		RECT 21.546 40.6486 21.693 40.8502 ;
		RECT 0.2105 40.96 21.546 41.0831 ;
		RECT 21.546 40.96 21.693 41.0831 ;
		RECT 0.2105 41.2886 21.546 41.4902 ;
		RECT 21.546 41.2886 21.693 41.4902 ;
		RECT 0.2105 41.6 21.546 41.7231 ;
		RECT 21.546 41.6 21.693 41.7231 ;
		RECT 0.2105 41.9286 21.546 42.1302 ;
		RECT 21.546 41.9286 21.693 42.1302 ;
		RECT 0.2105 42.24 21.546 42.3631 ;
		RECT 21.546 42.24 21.693 42.3631 ;
		RECT 0.2105 42.8267 21.546 43.0761 ;
		RECT 21.546 42.8267 21.693 43.0761 ;
		RECT 0.2105 43.5561 21.546 43.8949 ;
		RECT 21.546 43.5561 21.693 43.8949 ;
		RECT 0.2105 44.0831 21.546 44.422 ;
		RECT 21.546 44.0831 21.693 44.422 ;
		RECT 0.2105 44.6102 21.546 44.949 ;
		RECT 21.546 44.6102 21.693 44.949 ;
		RECT 0.2105 45.1373 21.546 45.4761 ;
		RECT 21.546 45.1373 21.693 45.4761 ;
		RECT 0.2105 45.6643 21.546 46.5302 ;
		RECT 21.546 45.6643 21.693 46.5302 ;
		RECT 0.2105 46.7184 21.546 47.5843 ;
		RECT 21.546 46.7184 21.693 47.5843 ;
		RECT 0.2105 47.7725 21.546 48.1114 ;
		RECT 21.546 47.7725 21.693 48.1114 ;
		RECT 0.2105 48.2996 21.546 48.6384 ;
		RECT 21.546 48.2996 21.693 48.6384 ;
		RECT 0.2105 48.8267 21.546 49.1655 ;
		RECT 21.546 48.8267 21.693 49.1655 ;
		RECT 0.2105 49.7239 21.546 49.9643 ;
		RECT 21.546 49.7239 21.693 49.9643 ;
		RECT 0.2105 50.2675 21.546 50.3906 ;
		RECT 21.546 50.2675 21.693 50.3906 ;
		RECT 0.2105 50.5004 21.546 50.702 ;
		RECT 21.546 50.5004 21.693 50.702 ;
		RECT 0.2105 50.9075 21.546 51.0306 ;
		RECT 21.546 50.9075 21.693 51.0306 ;
		RECT 0.2105 51.1404 21.546 51.342 ;
		RECT 21.546 51.1404 21.693 51.342 ;
		RECT 0.2105 51.5475 21.546 51.6706 ;
		RECT 21.546 51.5475 21.693 51.6706 ;
		RECT 0.2105 51.7804 21.546 51.982 ;
		RECT 21.546 51.7804 21.693 51.982 ;
		RECT 0.2105 52.1875 21.546 52.3106 ;
		RECT 21.546 52.1875 21.693 52.3106 ;
		RECT 0.2105 52.4204 21.546 52.622 ;
		RECT 21.546 52.4204 21.693 52.622 ;
		RECT 0.2105 52.8275 21.546 52.9506 ;
		RECT 21.546 52.8275 21.693 52.9506 ;
		RECT 0.2105 53.0604 21.546 53.262 ;
		RECT 21.546 53.0604 21.693 53.262 ;
		RECT 0.2105 53.4675 21.546 53.5906 ;
		RECT 21.546 53.4675 21.693 53.5906 ;
		RECT 0.2105 53.7004 21.546 53.902 ;
		RECT 21.546 53.7004 21.693 53.902 ;
		RECT 0.2105 54.1075 21.546 54.2306 ;
		RECT 21.546 54.1075 21.693 54.2306 ;
		RECT 0.2105 54.3404 21.546 54.542 ;
		RECT 21.546 54.3404 21.693 54.542 ;
		RECT 0.2105 54.7475 21.546 54.8706 ;
		RECT 21.546 54.7475 21.693 54.8706 ;
		RECT 0.2105 54.9804 21.546 55.182 ;
		RECT 21.546 54.9804 21.693 55.182 ;
		RECT 0.2105 55.3875 21.546 55.5106 ;
		RECT 21.546 55.3875 21.693 55.5106 ;
		RECT 0.2105 55.6204 21.546 55.822 ;
		RECT 21.546 55.6204 21.693 55.822 ;
		RECT 0.2105 56.0275 21.546 56.1506 ;
		RECT 21.546 56.0275 21.693 56.1506 ;
		RECT 0.2105 56.2604 21.546 56.462 ;
		RECT 21.546 56.2604 21.693 56.462 ;
		RECT 0.2105 56.6675 21.546 56.7906 ;
		RECT 21.546 56.6675 21.693 56.7906 ;
		RECT 0.2105 56.9004 21.546 57.102 ;
		RECT 21.546 56.9004 21.693 57.102 ;
		RECT 0.2105 57.3075 21.546 57.4306 ;
		RECT 21.546 57.3075 21.693 57.4306 ;
		RECT 0.2105 57.5404 21.546 57.742 ;
		RECT 21.546 57.5404 21.693 57.742 ;
		RECT 0.2105 57.9475 21.546 58.0706 ;
		RECT 21.546 57.9475 21.693 58.0706 ;
		RECT 0.2105 58.1804 21.546 58.382 ;
		RECT 21.546 58.1804 21.693 58.382 ;
		RECT 0.2105 58.5875 21.546 58.7106 ;
		RECT 21.546 58.5875 21.693 58.7106 ;
		RECT 0.2105 58.8204 21.546 59.022 ;
		RECT 21.546 58.8204 21.693 59.022 ;
		RECT 0.2105 59.2275 21.546 59.3506 ;
		RECT 21.546 59.2275 21.693 59.3506 ;
		RECT 0.2105 59.4604 21.546 59.662 ;
		RECT 21.546 59.4604 21.693 59.662 ;
		RECT 0.2105 59.8675 21.546 59.9906 ;
		RECT 21.546 59.8675 21.693 59.9906 ;
		RECT 0.2105 60.1004 21.546 60.302 ;
		RECT 21.546 60.1004 21.693 60.302 ;
		RECT 0.2105 60.5075 21.546 60.6306 ;
		RECT 21.546 60.5075 21.693 60.6306 ;
		RECT 0.2105 60.7404 21.546 60.942 ;
		RECT 21.546 60.7404 21.693 60.942 ;
		RECT 0.2105 61.1475 21.546 61.2706 ;
		RECT 21.546 61.1475 21.693 61.2706 ;
		RECT 0.2105 61.3804 21.546 61.582 ;
		RECT 21.546 61.3804 21.693 61.582 ;
		RECT 0.2105 61.7875 21.546 61.9106 ;
		RECT 21.546 61.7875 21.693 61.9106 ;
		RECT 0.2105 62.0204 21.546 62.222 ;
		RECT 21.546 62.0204 21.693 62.222 ;
		RECT 0.2105 62.4275 21.546 62.5506 ;
		RECT 21.546 62.4275 21.693 62.5506 ;
		RECT 0.2105 62.6604 21.546 62.862 ;
		RECT 21.546 62.6604 21.693 62.862 ;
		RECT 0.2105 63.0675 21.546 63.1906 ;
		RECT 21.546 63.0675 21.693 63.1906 ;
		RECT 0.2105 63.3004 21.546 63.502 ;
		RECT 21.546 63.3004 21.693 63.502 ;
		RECT 0.2105 63.7075 21.546 63.8306 ;
		RECT 21.546 63.7075 21.693 63.8306 ;
		RECT 0.2105 63.9404 21.546 64.142 ;
		RECT 21.546 63.9404 21.693 64.142 ;
		RECT 0.2105 64.3475 21.546 64.4706 ;
		RECT 21.546 64.3475 21.693 64.4706 ;
		RECT 0.2105 64.5804 21.546 64.782 ;
		RECT 21.546 64.5804 21.693 64.782 ;
		RECT 0.2105 64.9875 21.546 65.1106 ;
		RECT 21.546 64.9875 21.693 65.1106 ;
		RECT 0.2105 65.2204 21.546 65.422 ;
		RECT 21.546 65.2204 21.693 65.422 ;
		RECT 0.2105 65.6275 21.546 65.7506 ;
		RECT 21.546 65.6275 21.693 65.7506 ;
		RECT 0.2105 65.8604 21.546 66.062 ;
		RECT 21.546 65.8604 21.693 66.062 ;
		RECT 0.2105 66.2675 21.546 66.3906 ;
		RECT 21.546 66.2675 21.693 66.3906 ;
		RECT 0.2105 66.5004 21.546 66.702 ;
		RECT 21.546 66.5004 21.693 66.702 ;
		RECT 0.2105 66.9075 21.546 67.0306 ;
		RECT 21.546 66.9075 21.693 67.0306 ;
		RECT 0.2105 67.1404 21.546 67.342 ;
		RECT 21.546 67.1404 21.693 67.342 ;
		RECT 0.2105 67.5475 21.546 67.6706 ;
		RECT 21.546 67.5475 21.693 67.6706 ;
		RECT 0.2105 67.7804 21.546 67.982 ;
		RECT 21.546 67.7804 21.693 67.982 ;
		RECT 0.2105 68.1875 21.546 68.3106 ;
		RECT 21.546 68.1875 21.693 68.3106 ;
		RECT 0.2105 68.4204 21.546 68.622 ;
		RECT 21.546 68.4204 21.693 68.622 ;
		RECT 0.2105 68.8275 21.546 68.9506 ;
		RECT 21.546 68.8275 21.693 68.9506 ;
		RECT 0.2105 69.0604 21.546 69.262 ;
		RECT 21.546 69.0604 21.693 69.262 ;
		RECT 0.2105 69.4675 21.546 69.5906 ;
		RECT 21.546 69.4675 21.693 69.5906 ;
		RECT 0.2105 69.7004 21.546 69.902 ;
		RECT 21.546 69.7004 21.693 69.902 ;
		RECT 0.2105 70.1075 21.546 70.2306 ;
		RECT 21.546 70.1075 21.693 70.2306 ;
		RECT 0.2105 70.3404 21.546 70.542 ;
		RECT 21.546 70.3404 21.693 70.542 ;
		RECT 0.2105 70.7475 21.546 70.8706 ;
		RECT 21.546 70.7475 21.693 70.8706 ;
		RECT 0.2105 70.9804 21.546 71.182 ;
		RECT 21.546 70.9804 21.693 71.182 ;
		RECT 0.2105 71.3875 21.546 71.5106 ;
		RECT 21.546 71.3875 21.693 71.5106 ;
		RECT 0.2105 71.6204 21.546 71.822 ;
		RECT 21.546 71.6204 21.693 71.822 ;
		RECT 0.2105 72.0275 21.546 72.1506 ;
		RECT 21.546 72.0275 21.693 72.1506 ;
		RECT 0.2105 72.2604 21.546 72.462 ;
		RECT 21.546 72.2604 21.693 72.462 ;
		RECT 0.2105 72.6675 21.546 72.7906 ;
		RECT 21.546 72.6675 21.693 72.7906 ;
		RECT 0.2105 72.9004 21.546 73.102 ;
		RECT 21.546 72.9004 21.693 73.102 ;
		RECT 0.2105 73.3075 21.546 73.4306 ;
		RECT 21.546 73.3075 21.693 73.4306 ;
		RECT 0.2105 73.5404 21.546 73.742 ;
		RECT 21.546 73.5404 21.693 73.742 ;
		RECT 0.2105 73.9475 21.546 74.0706 ;
		RECT 21.546 73.9475 21.693 74.0706 ;
		RECT 0.2105 74.1804 21.546 74.382 ;
		RECT 21.546 74.1804 21.693 74.382 ;
		RECT 0.2105 74.5875 21.546 74.7106 ;
		RECT 21.546 74.5875 21.693 74.7106 ;
		RECT 0.2105 74.8204 21.546 75.022 ;
		RECT 21.546 74.8204 21.693 75.022 ;
		RECT 0.2105 75.2275 21.546 75.3506 ;
		RECT 21.546 75.2275 21.693 75.3506 ;
		RECT 0.2105 75.4604 21.546 75.662 ;
		RECT 21.546 75.4604 21.693 75.662 ;
		RECT 0.2105 75.8675 21.546 75.9906 ;
		RECT 21.546 75.8675 21.693 75.9906 ;
		RECT 0.2105 76.1004 21.546 76.302 ;
		RECT 21.546 76.1004 21.693 76.302 ;
		RECT 0.2105 76.5075 21.546 76.6306 ;
		RECT 21.546 76.5075 21.693 76.6306 ;
		RECT 0.2105 76.7404 21.546 76.942 ;
		RECT 21.546 76.7404 21.693 76.942 ;
		RECT 0.2105 77.1475 21.546 77.2706 ;
		RECT 21.546 77.1475 21.693 77.2706 ;
		RECT 0.2105 77.3804 21.546 77.582 ;
		RECT 21.546 77.3804 21.693 77.582 ;
		RECT 0.2105 77.7875 21.546 77.9106 ;
		RECT 21.546 77.7875 21.693 77.9106 ;
		RECT 0.2105 78.0204 21.546 78.222 ;
		RECT 21.546 78.0204 21.693 78.222 ;
		RECT 0.2105 78.4275 21.546 78.5506 ;
		RECT 21.546 78.4275 21.693 78.5506 ;
		RECT 0.2105 78.6604 21.546 78.862 ;
		RECT 21.546 78.6604 21.693 78.862 ;
		RECT 0.2105 79.0675 21.546 79.1906 ;
		RECT 21.546 79.0675 21.693 79.1906 ;
		RECT 0.2105 79.3004 21.546 79.502 ;
		RECT 21.546 79.3004 21.693 79.502 ;
		RECT 0.2105 79.7075 21.546 79.8306 ;
		RECT 21.546 79.7075 21.693 79.8306 ;
		RECT 0.2105 79.9404 21.546 80.142 ;
		RECT 21.546 79.9404 21.693 80.142 ;
		RECT 0.2105 80.3475 21.546 80.4706 ;
		RECT 21.546 80.3475 21.693 80.4706 ;
		RECT 0.2105 80.5804 21.546 80.782 ;
		RECT 21.546 80.5804 21.693 80.782 ;
		RECT 0.2105 80.9875 21.546 81.1106 ;
		RECT 21.546 80.9875 21.693 81.1106 ;
		RECT 0.2105 81.2204 21.546 81.422 ;
		RECT 21.546 81.2204 21.693 81.422 ;
		RECT 0.2105 81.6275 21.546 81.7506 ;
		RECT 21.546 81.6275 21.693 81.7506 ;
		RECT 0.2105 81.8604 21.546 82.062 ;
		RECT 21.546 81.8604 21.693 82.062 ;
		RECT 0.2105 82.2675 21.546 82.3906 ;
		RECT 21.546 82.2675 21.693 82.3906 ;
		RECT 0.2105 82.5004 21.546 82.702 ;
		RECT 21.546 82.5004 21.693 82.702 ;
		RECT 0.2105 82.9075 21.546 83.0306 ;
		RECT 21.546 82.9075 21.693 83.0306 ;
		RECT 0.2105 83.1404 21.546 83.342 ;
		RECT 21.546 83.1404 21.693 83.342 ;
		RECT 0.2105 83.5475 21.546 83.6706 ;
		RECT 21.546 83.5475 21.693 83.6706 ;
		RECT 0.2105 83.7804 21.546 83.982 ;
		RECT 21.546 83.7804 21.693 83.982 ;
		RECT 0.2105 84.1875 21.546 84.3106 ;
		RECT 21.546 84.1875 21.693 84.3106 ;
		RECT 0.2105 84.4204 21.546 84.622 ;
		RECT 21.546 84.4204 21.693 84.622 ;
		RECT 0.2105 84.8275 21.546 84.9506 ;
		RECT 21.546 84.8275 21.693 84.9506 ;
		RECT 0.2105 85.0604 21.546 85.262 ;
		RECT 21.546 85.0604 21.693 85.262 ;
		RECT 0.2105 85.4675 21.546 85.5906 ;
		RECT 21.546 85.4675 21.693 85.5906 ;
		RECT 0.2105 85.7004 21.546 85.902 ;
		RECT 21.546 85.7004 21.693 85.902 ;
		RECT 0.2105 86.1075 21.546 86.2306 ;
		RECT 21.546 86.1075 21.693 86.2306 ;
		RECT 0.2105 86.3404 21.546 86.542 ;
		RECT 21.546 86.3404 21.693 86.542 ;
		RECT 0.2105 86.7475 21.546 86.8706 ;
		RECT 21.546 86.7475 21.693 86.8706 ;
		RECT 0.2105 86.9804 21.546 87.182 ;
		RECT 21.546 86.9804 21.693 87.182 ;
		RECT 0.2105 87.3875 21.546 87.5106 ;
		RECT 21.546 87.3875 21.693 87.5106 ;
		RECT 0.2105 87.6204 21.546 87.822 ;
		RECT 21.546 87.6204 21.693 87.822 ;
		RECT 0.2105 88.0275 21.546 88.1506 ;
		RECT 21.546 88.0275 21.693 88.1506 ;
		RECT 0.2105 88.2604 21.546 88.462 ;
		RECT 21.546 88.2604 21.693 88.462 ;
		RECT 0.2105 88.6675 21.546 88.7906 ;
		RECT 21.546 88.6675 21.693 88.7906 ;
		RECT 0.2105 88.9004 21.546 89.102 ;
		RECT 21.546 88.9004 21.693 89.102 ;
		RECT 0.2105 89.3075 21.546 89.4306 ;
		RECT 21.546 89.3075 21.693 89.4306 ;
		RECT 0.2105 89.5404 21.546 89.742 ;
		RECT 21.546 89.5404 21.693 89.742 ;
		RECT 0.2105 89.9475 21.546 90.0706 ;
		RECT 21.546 89.9475 21.693 90.0706 ;
		RECT 0.2105 90.1804 21.546 90.382 ;
		RECT 21.546 90.1804 21.693 90.382 ;
		RECT 0.2105 90.5875 21.546 90.7106 ;
		RECT 21.546 90.5875 21.693 90.7106 ;
		RECT 0.2105 90.8204 21.546 91.022 ;
		RECT 21.546 90.8204 21.693 91.022 ;
		RECT 0.2105 91.2275 21.546 91.3506 ;
		RECT 21.546 91.2275 21.693 91.3506 ;
		RECT 0.2105 91.4604 21.546 91.662 ;
		RECT 21.546 91.4604 21.693 91.662 ;
		RECT 0.2105 91.8675 21.546 91.9906 ;
		RECT 21.546 91.8675 21.693 91.9906 ;
		RECT 0.2105 92.1004 21.546 92.302 ;
		RECT 21.546 92.1004 21.693 92.302 ;
		 LAYER M4 ;
		RECT 0.2105 0 21.546 0.022 ;
		RECT 21.546 0 21.693 0.022 ;
		RECT 0.2105 43.2643 21.546 43.2894 ;
		RECT 21.546 43.2643 21.693 43.2894 ;
		RECT 0.2105 49.5106 21.546 49.5357 ;
		RECT 21.546 49.5106 21.693 49.5357 ;
		RECT 0.2105 92.6086 21.546 92.6306 ;
		RECT 21.546 92.6086 21.693 92.6306 ;
		 LAYER M4 SPACING 0.018 ;
		RECT 0.2105 0 21.546 0.022 ;
		RECT 21.546 0 21.693 0.022 ;
		RECT 0.2105 43.2643 21.546 43.2894 ;
		RECT 21.546 43.2643 21.693 43.2894 ;
		RECT 0.2105 49.5106 21.546 49.5357 ;
		RECT 21.546 49.5106 21.693 49.5357 ;
		RECT 0.2105 92.6086 21.546 92.6306 ;
		RECT 21.546 92.6086 21.693 92.6306 ;
		 LAYER V1 SPACING 0 ;
		RECT 0 0 21.693 92.6306 ;
		 LAYER V2 SPACING 0 ;
		RECT 0.1097 0 21.693 92.6306 ;
		RECT 0 0 0.1097 0.0627 ;
		RECT 0 0.1631 0.1097 0.9663 ;
		RECT 0 1.0667 0.1097 1.0918 ;
		RECT 0 1.1922 0.1097 1.2424 ;
		RECT 0 1.3427 0.1097 1.3678 ;
		RECT 0 1.4682 0.1097 2.2463 ;
		RECT 0 2.3467 0.1097 2.3718 ;
		RECT 0 2.4722 0.1097 2.5224 ;
		RECT 0 2.6227 0.1097 2.6478 ;
		RECT 0 2.7482 0.1097 3.5263 ;
		RECT 0 3.6267 0.1097 3.6518 ;
		RECT 0 3.7522 0.1097 3.8024 ;
		RECT 0 3.9027 0.1097 3.9278 ;
		RECT 0 4.0282 0.1097 4.8063 ;
		RECT 0 4.9067 0.1097 4.9318 ;
		RECT 0 5.0322 0.1097 5.0824 ;
		RECT 0 5.1827 0.1097 5.2078 ;
		RECT 0 5.3082 0.1097 6.0863 ;
		RECT 0 6.1867 0.1097 6.2118 ;
		RECT 0 6.3122 0.1097 6.3624 ;
		RECT 0 6.4627 0.1097 6.4878 ;
		RECT 0 6.5882 0.1097 7.3663 ;
		RECT 0 7.4667 0.1097 7.4918 ;
		RECT 0 7.5922 0.1097 7.6424 ;
		RECT 0 7.7427 0.1097 7.7678 ;
		RECT 0 7.8682 0.1097 8.6463 ;
		RECT 0 8.7467 0.1097 8.7718 ;
		RECT 0 8.8722 0.1097 8.9224 ;
		RECT 0 9.0227 0.1097 9.0478 ;
		RECT 0 9.1482 0.1097 9.9263 ;
		RECT 0 10.0267 0.1097 10.0518 ;
		RECT 0 10.1522 0.1097 10.2024 ;
		RECT 0 10.3027 0.1097 10.3278 ;
		RECT 0 10.4282 0.1097 11.2063 ;
		RECT 0 11.3067 0.1097 11.3318 ;
		RECT 0 11.4322 0.1097 11.4824 ;
		RECT 0 11.5827 0.1097 11.6078 ;
		RECT 0 11.7082 0.1097 12.4863 ;
		RECT 0 12.5867 0.1097 12.6118 ;
		RECT 0 12.7122 0.1097 12.7624 ;
		RECT 0 12.8627 0.1097 12.8878 ;
		RECT 0 12.9882 0.1097 13.7663 ;
		RECT 0 13.8667 0.1097 13.8918 ;
		RECT 0 13.9922 0.1097 14.0424 ;
		RECT 0 14.1427 0.1097 14.1678 ;
		RECT 0 14.2682 0.1097 15.0463 ;
		RECT 0 15.1467 0.1097 15.1718 ;
		RECT 0 15.2722 0.1097 15.3224 ;
		RECT 0 15.4227 0.1097 15.4478 ;
		RECT 0 15.5482 0.1097 16.3263 ;
		RECT 0 16.4267 0.1097 16.4518 ;
		RECT 0 16.5522 0.1097 16.6024 ;
		RECT 0 16.7027 0.1097 16.7278 ;
		RECT 0 16.8282 0.1097 17.6063 ;
		RECT 0 17.7067 0.1097 17.7318 ;
		RECT 0 17.8322 0.1097 17.8824 ;
		RECT 0 17.9827 0.1097 18.0078 ;
		RECT 0 18.1082 0.1097 18.8863 ;
		RECT 0 18.9867 0.1097 19.0118 ;
		RECT 0 19.1122 0.1097 19.1624 ;
		RECT 0 19.2627 0.1097 19.2878 ;
		RECT 0 19.3882 0.1097 20.1663 ;
		RECT 0 20.2667 0.1097 20.2918 ;
		RECT 0 20.3922 0.1097 20.4424 ;
		RECT 0 20.5427 0.1097 20.5678 ;
		RECT 0 20.6682 0.1097 21.4463 ;
		RECT 0 21.5467 0.1097 21.5718 ;
		RECT 0 21.6722 0.1097 21.7224 ;
		RECT 0 21.8227 0.1097 21.8478 ;
		RECT 0 21.9482 0.1097 22.7263 ;
		RECT 0 22.8267 0.1097 22.8518 ;
		RECT 0 22.9522 0.1097 23.0024 ;
		RECT 0 23.1027 0.1097 23.1278 ;
		RECT 0 23.2282 0.1097 24.0063 ;
		RECT 0 24.1067 0.1097 24.1318 ;
		RECT 0 24.2322 0.1097 24.2824 ;
		RECT 0 24.3827 0.1097 24.4078 ;
		RECT 0 24.5082 0.1097 25.2863 ;
		RECT 0 25.3867 0.1097 25.4118 ;
		RECT 0 25.5122 0.1097 25.5624 ;
		RECT 0 25.6627 0.1097 25.6878 ;
		RECT 0 25.7882 0.1097 26.5663 ;
		RECT 0 26.6667 0.1097 26.6918 ;
		RECT 0 26.7922 0.1097 26.8424 ;
		RECT 0 26.9427 0.1097 26.9678 ;
		RECT 0 27.0682 0.1097 27.8463 ;
		RECT 0 27.9467 0.1097 27.9718 ;
		RECT 0 28.0722 0.1097 28.1224 ;
		RECT 0 28.2227 0.1097 28.2478 ;
		RECT 0 28.3482 0.1097 29.1263 ;
		RECT 0 29.2267 0.1097 29.2518 ;
		RECT 0 29.3522 0.1097 29.4024 ;
		RECT 0 29.5027 0.1097 29.5278 ;
		RECT 0 29.6282 0.1097 30.4063 ;
		RECT 0 30.5067 0.1097 30.5318 ;
		RECT 0 30.6322 0.1097 30.6824 ;
		RECT 0 30.7827 0.1097 30.8078 ;
		RECT 0 30.9082 0.1097 31.6863 ;
		RECT 0 31.7867 0.1097 31.8118 ;
		RECT 0 31.9122 0.1097 31.9624 ;
		RECT 0 32.0627 0.1097 32.0878 ;
		RECT 0 32.1882 0.1097 32.9663 ;
		RECT 0 33.0667 0.1097 33.0918 ;
		RECT 0 33.1922 0.1097 33.2424 ;
		RECT 0 33.3427 0.1097 33.3678 ;
		RECT 0 33.4682 0.1097 34.2463 ;
		RECT 0 34.3467 0.1097 34.3718 ;
		RECT 0 34.4722 0.1097 34.5224 ;
		RECT 0 34.6227 0.1097 34.6478 ;
		RECT 0 34.7482 0.1097 35.5263 ;
		RECT 0 35.6267 0.1097 35.6518 ;
		RECT 0 35.7522 0.1097 35.8024 ;
		RECT 0 35.9027 0.1097 35.9278 ;
		RECT 0 36.0282 0.1097 36.8063 ;
		RECT 0 36.9067 0.1097 36.9318 ;
		RECT 0 37.0322 0.1097 37.0824 ;
		RECT 0 37.1827 0.1097 37.2078 ;
		RECT 0 37.3082 0.1097 38.0863 ;
		RECT 0 38.1867 0.1097 38.2118 ;
		RECT 0 38.3122 0.1097 38.3624 ;
		RECT 0 38.4627 0.1097 38.4878 ;
		RECT 0 38.5882 0.1097 39.3663 ;
		RECT 0 39.4667 0.1097 39.4918 ;
		RECT 0 39.5922 0.1097 39.6424 ;
		RECT 0 39.7427 0.1097 39.7678 ;
		RECT 0 39.8682 0.1097 40.6463 ;
		RECT 0 40.7467 0.1097 40.7718 ;
		RECT 0 40.8722 0.1097 40.9224 ;
		RECT 0 41.0227 0.1097 41.0478 ;
		RECT 0 41.1482 0.1097 41.9263 ;
		RECT 0 42.0267 0.1097 42.0518 ;
		RECT 0 42.1522 0.1097 42.2024 ;
		RECT 0 42.3027 0.1097 42.3278 ;
		RECT 0 42.4282 0.1097 42.7796 ;
		RECT 0 42.88 0.1097 42.9302 ;
		RECT 0 43.0306 0.1097 43.382 ;
		RECT 0 43.4824 0.1097 43.5325 ;
		RECT 0 43.6329 0.1097 43.6831 ;
		RECT 0 43.7835 0.1097 43.9843 ;
		RECT 0 44.0847 0.1097 44.2855 ;
		RECT 0 44.3859 0.1097 44.4361 ;
		RECT 0 44.5365 0.1097 44.7373 ;
		RECT 0 44.8376 0.1097 44.8878 ;
		RECT 0 44.9882 0.1097 45.0384 ;
		RECT 0 45.1388 0.1097 45.189 ;
		RECT 0 45.2894 0.1097 45.3396 ;
		RECT 0 45.3396 0.0098 45.44 ;
		RECT 0 45.44 0.1097 45.4902 ;
		RECT 0 45.5906 0.1097 45.6408 ;
		RECT 0 45.7412 0.1097 45.7914 ;
		RECT 0 45.8918 0.1097 45.942 ;
		RECT 0 46.0424 0.1097 46.0925 ;
		RECT 0 46.1929 0.1097 46.2431 ;
		RECT 0 46.3435 0.1097 46.3937 ;
		RECT 0 46.4941 0.1097 46.5443 ;
		RECT 0 46.6447 0.1097 46.6949 ;
		RECT 0 46.6949 0.0098 46.7953 ;
		RECT 0 46.7953 0.1097 46.8455 ;
		RECT 0 46.9459 0.1097 46.9961 ;
		RECT 0 47.0965 0.1097 47.1467 ;
		RECT 0 47.2471 0.1097 47.2973 ;
		RECT 0 47.2973 0.0098 47.3976 ;
		RECT 0 47.3976 0.1097 47.4478 ;
		RECT 0 47.5482 0.1097 47.5984 ;
		RECT 0 47.5984 0.0098 47.6988 ;
		RECT 0 47.6988 0.1097 47.749 ;
		RECT 0 47.749 0.0098 47.8494 ;
		RECT 0 47.8494 0.1097 48.0502 ;
		RECT 0 48.1506 0.1097 48.2008 ;
		RECT 0 48.3012 0.1097 48.3514 ;
		RECT 0 48.3514 0.0098 48.4518 ;
		RECT 0 48.4518 0.1097 48.502 ;
		RECT 0 48.6024 0.1097 48.6525 ;
		RECT 0 48.7529 0.1097 49.1043 ;
		RECT 0 49.2047 0.1097 49.2549 ;
		RECT 0 49.3553 0.1097 49.8573 ;
		RECT 0 49.9576 0.1097 50.2024 ;
		RECT 0 50.3027 0.1097 50.3278 ;
		RECT 0 50.4282 0.1097 50.4784 ;
		RECT 0 50.5788 0.1097 50.6039 ;
		RECT 0 50.7043 0.1097 51.4824 ;
		RECT 0 51.5827 0.1097 51.6078 ;
		RECT 0 51.7082 0.1097 51.7584 ;
		RECT 0 51.8588 0.1097 51.8839 ;
		RECT 0 51.9843 0.1097 52.7624 ;
		RECT 0 52.8627 0.1097 52.8878 ;
		RECT 0 52.9882 0.1097 53.0384 ;
		RECT 0 53.1388 0.1097 53.1639 ;
		RECT 0 53.2643 0.1097 54.0424 ;
		RECT 0 54.1427 0.1097 54.1678 ;
		RECT 0 54.2682 0.1097 54.3184 ;
		RECT 0 54.4188 0.1097 54.4439 ;
		RECT 0 54.5443 0.1097 55.3224 ;
		RECT 0 55.4227 0.1097 55.4478 ;
		RECT 0 55.5482 0.1097 55.5984 ;
		RECT 0 55.6988 0.1097 55.7239 ;
		RECT 0 55.8243 0.1097 56.6024 ;
		RECT 0 56.7027 0.1097 56.7278 ;
		RECT 0 56.8282 0.1097 56.8784 ;
		RECT 0 56.9788 0.1097 57.0039 ;
		RECT 0 57.1043 0.1097 57.8824 ;
		RECT 0 57.9827 0.1097 58.0078 ;
		RECT 0 58.1082 0.1097 58.1584 ;
		RECT 0 58.2588 0.1097 58.2839 ;
		RECT 0 58.3843 0.1097 59.1624 ;
		RECT 0 59.2627 0.1097 59.2878 ;
		RECT 0 59.3882 0.1097 59.4384 ;
		RECT 0 59.5388 0.1097 59.5639 ;
		RECT 0 59.6643 0.1097 60.4424 ;
		RECT 0 60.5427 0.1097 60.5678 ;
		RECT 0 60.6682 0.1097 60.7184 ;
		RECT 0 60.8188 0.1097 60.8439 ;
		RECT 0 60.9443 0.1097 61.7224 ;
		RECT 0 61.8227 0.1097 61.8478 ;
		RECT 0 61.9482 0.1097 61.9984 ;
		RECT 0 62.0988 0.1097 62.1239 ;
		RECT 0 62.2243 0.1097 63.0024 ;
		RECT 0 63.1027 0.1097 63.1278 ;
		RECT 0 63.2282 0.1097 63.2784 ;
		RECT 0 63.3788 0.1097 63.4039 ;
		RECT 0 63.5043 0.1097 64.2824 ;
		RECT 0 64.3827 0.1097 64.4078 ;
		RECT 0 64.5082 0.1097 64.5584 ;
		RECT 0 64.6588 0.1097 64.6839 ;
		RECT 0 64.7843 0.1097 65.5624 ;
		RECT 0 65.6627 0.1097 65.6878 ;
		RECT 0 65.7882 0.1097 65.8384 ;
		RECT 0 65.9388 0.1097 65.9639 ;
		RECT 0 66.0643 0.1097 66.8424 ;
		RECT 0 66.9427 0.1097 66.9678 ;
		RECT 0 67.0682 0.1097 67.1184 ;
		RECT 0 67.2188 0.1097 67.2439 ;
		RECT 0 67.3443 0.1097 68.1224 ;
		RECT 0 68.2227 0.1097 68.2478 ;
		RECT 0 68.3482 0.1097 68.3984 ;
		RECT 0 68.4988 0.1097 68.5239 ;
		RECT 0 68.6243 0.1097 69.4024 ;
		RECT 0 69.5027 0.1097 69.5278 ;
		RECT 0 69.6282 0.1097 69.6784 ;
		RECT 0 69.7788 0.1097 69.8039 ;
		RECT 0 69.9043 0.1097 70.6824 ;
		RECT 0 70.7827 0.1097 70.8078 ;
		RECT 0 70.9082 0.1097 70.9584 ;
		RECT 0 71.0588 0.1097 71.0839 ;
		RECT 0 71.1843 0.1097 71.9624 ;
		RECT 0 72.0627 0.1097 72.0878 ;
		RECT 0 72.1882 0.1097 72.2384 ;
		RECT 0 72.3388 0.1097 72.3639 ;
		RECT 0 72.4643 0.1097 73.2424 ;
		RECT 0 73.3427 0.1097 73.3678 ;
		RECT 0 73.4682 0.1097 73.5184 ;
		RECT 0 73.6188 0.1097 73.6439 ;
		RECT 0 73.7443 0.1097 74.5224 ;
		RECT 0 74.6227 0.1097 74.6478 ;
		RECT 0 74.7482 0.1097 74.7984 ;
		RECT 0 74.8988 0.1097 74.9239 ;
		RECT 0 75.0243 0.1097 75.8024 ;
		RECT 0 75.9027 0.1097 75.9278 ;
		RECT 0 76.0282 0.1097 76.0784 ;
		RECT 0 76.1788 0.1097 76.2039 ;
		RECT 0 76.3043 0.1097 77.0824 ;
		RECT 0 77.1827 0.1097 77.2078 ;
		RECT 0 77.3082 0.1097 77.3584 ;
		RECT 0 77.4588 0.1097 77.4839 ;
		RECT 0 77.5843 0.1097 78.3624 ;
		RECT 0 78.4627 0.1097 78.4878 ;
		RECT 0 78.5882 0.1097 78.6384 ;
		RECT 0 78.7388 0.1097 78.7639 ;
		RECT 0 78.8643 0.1097 79.6424 ;
		RECT 0 79.7427 0.1097 79.7678 ;
		RECT 0 79.8682 0.1097 79.9184 ;
		RECT 0 80.0188 0.1097 80.0439 ;
		RECT 0 80.1443 0.1097 80.9224 ;
		RECT 0 81.0227 0.1097 81.0478 ;
		RECT 0 81.1482 0.1097 81.1984 ;
		RECT 0 81.2988 0.1097 81.3239 ;
		RECT 0 81.4243 0.1097 82.2024 ;
		RECT 0 82.3027 0.1097 82.3278 ;
		RECT 0 82.4282 0.1097 82.4784 ;
		RECT 0 82.5788 0.1097 82.6039 ;
		RECT 0 82.7043 0.1097 83.4824 ;
		RECT 0 83.5827 0.1097 83.6078 ;
		RECT 0 83.7082 0.1097 83.7584 ;
		RECT 0 83.8588 0.1097 83.8839 ;
		RECT 0 83.9843 0.1097 84.7624 ;
		RECT 0 84.8627 0.1097 84.8878 ;
		RECT 0 84.9882 0.1097 85.0384 ;
		RECT 0 85.1388 0.1097 85.1639 ;
		RECT 0 85.2643 0.1097 86.0424 ;
		RECT 0 86.1427 0.1097 86.1678 ;
		RECT 0 86.2682 0.1097 86.3184 ;
		RECT 0 86.4188 0.1097 86.4439 ;
		RECT 0 86.5443 0.1097 87.3224 ;
		RECT 0 87.4227 0.1097 87.4478 ;
		RECT 0 87.5482 0.1097 87.5984 ;
		RECT 0 87.6988 0.1097 87.7239 ;
		RECT 0 87.8243 0.1097 88.6024 ;
		RECT 0 88.7027 0.1097 88.7278 ;
		RECT 0 88.8282 0.1097 88.8784 ;
		RECT 0 88.9788 0.1097 89.0039 ;
		RECT 0 89.1043 0.1097 89.8824 ;
		RECT 0 89.9827 0.1097 90.0078 ;
		RECT 0 90.1082 0.1097 90.1584 ;
		RECT 0 90.2588 0.1097 90.2839 ;
		RECT 0 90.3843 0.1097 91.1624 ;
		RECT 0 91.2627 0.1097 91.2878 ;
		RECT 0 91.3882 0.1097 91.4384 ;
		RECT 0 91.5388 0.1097 91.5639 ;
		RECT 0 91.6643 0.1097 92.4675 ;
		RECT 0 92.5678 0.1097 92.6306 ;
		 LAYER V2 ;
		RECT 0.0481 1.0918 0.1097 1.2424 ;
		RECT 0.0481 1.2424 0.1097 1.3678 ;
		RECT 0.0481 2.3718 0.1097 2.5224 ;
		RECT 0.0481 2.5224 0.1097 2.6478 ;
		RECT 0.0481 3.6518 0.1097 3.8024 ;
		RECT 0.0481 3.8024 0.1097 3.9278 ;
		RECT 0.0481 4.9318 0.1097 5.0824 ;
		RECT 0.0481 5.0824 0.1097 5.2078 ;
		RECT 0.0481 6.2118 0.1097 6.3624 ;
		RECT 0.0481 6.3624 0.1097 6.4878 ;
		RECT 0.0481 7.4918 0.1097 7.6424 ;
		RECT 0.0481 7.6424 0.1097 7.7678 ;
		RECT 0.0481 8.7718 0.1097 8.9224 ;
		RECT 0.0481 8.9224 0.1097 9.0478 ;
		RECT 0.0481 10.0518 0.1097 10.2024 ;
		RECT 0.0481 10.2024 0.1097 10.3278 ;
		RECT 0.0481 11.3318 0.1097 11.4824 ;
		RECT 0.0481 11.4824 0.1097 11.6078 ;
		RECT 0.0481 12.6118 0.1097 12.7624 ;
		RECT 0.0481 12.7624 0.1097 12.8878 ;
		RECT 0.0481 13.8918 0.1097 14.0424 ;
		RECT 0.0481 14.0424 0.1097 14.1678 ;
		RECT 0.0481 15.1718 0.1097 15.3224 ;
		RECT 0.0481 15.3224 0.1097 15.4478 ;
		RECT 0.0481 16.4518 0.1097 16.6024 ;
		RECT 0.0481 16.6024 0.1097 16.7278 ;
		RECT 0.0481 17.7318 0.1097 17.8824 ;
		RECT 0.0481 17.8824 0.1097 18.0078 ;
		RECT 0.0481 19.0118 0.1097 19.1624 ;
		RECT 0.0481 19.1624 0.1097 19.2878 ;
		RECT 0.0481 20.2918 0.1097 20.4424 ;
		RECT 0.0481 20.4424 0.1097 20.5678 ;
		RECT 0.0481 21.5718 0.1097 21.7224 ;
		RECT 0.0481 21.7224 0.1097 21.8478 ;
		RECT 0.0481 22.8518 0.1097 23.0024 ;
		RECT 0.0481 23.0024 0.1097 23.1278 ;
		RECT 0.0481 24.1318 0.1097 24.2824 ;
		RECT 0.0481 24.2824 0.1097 24.4078 ;
		RECT 0.0481 25.4118 0.1097 25.5624 ;
		RECT 0.0481 25.5624 0.1097 25.6878 ;
		RECT 0.0481 26.6918 0.1097 26.8424 ;
		RECT 0.0481 26.8424 0.1097 26.9678 ;
		RECT 0.0481 27.9718 0.1097 28.1224 ;
		RECT 0.0481 28.1224 0.1097 28.2478 ;
		RECT 0.0481 29.2518 0.1097 29.4024 ;
		RECT 0.0481 29.4024 0.1097 29.5278 ;
		RECT 0.0481 30.5318 0.1097 30.6824 ;
		RECT 0.0481 30.6824 0.1097 30.8078 ;
		RECT 0.0481 31.8118 0.1097 31.9624 ;
		RECT 0.0481 31.9624 0.1097 32.0878 ;
		RECT 0.0481 33.0918 0.1097 33.2424 ;
		RECT 0.0481 33.2424 0.1097 33.3678 ;
		RECT 0.0481 34.3718 0.1097 34.5224 ;
		RECT 0.0481 34.5224 0.1097 34.6478 ;
		RECT 0.0481 35.6518 0.1097 35.8024 ;
		RECT 0.0481 35.8024 0.1097 35.9278 ;
		RECT 0.0481 36.9318 0.1097 37.0824 ;
		RECT 0.0481 37.0824 0.1097 37.2078 ;
		RECT 0.0481 38.2118 0.1097 38.3624 ;
		RECT 0.0481 38.3624 0.1097 38.4878 ;
		RECT 0.0481 39.4918 0.1097 39.6424 ;
		RECT 0.0481 39.6424 0.1097 39.7678 ;
		RECT 0.0481 40.7718 0.1097 40.9224 ;
		RECT 0.0481 40.9224 0.1097 41.0478 ;
		RECT 0.0481 42.0518 0.1097 42.2024 ;
		RECT 0.0481 42.2024 0.1097 42.3278 ;
		RECT 0.0481 50.3278 0.1097 50.4784 ;
		RECT 0.0481 50.4784 0.1097 50.6039 ;
		RECT 0.0481 51.6078 0.1097 51.7584 ;
		RECT 0.0481 51.7584 0.1097 51.8839 ;
		RECT 0.0481 52.8878 0.1097 53.0384 ;
		RECT 0.0481 53.0384 0.1097 53.1639 ;
		RECT 0.0481 54.1678 0.1097 54.3184 ;
		RECT 0.0481 54.3184 0.1097 54.4439 ;
		RECT 0.0481 55.4478 0.1097 55.5984 ;
		RECT 0.0481 55.5984 0.1097 55.7239 ;
		RECT 0.0481 56.7278 0.1097 56.8784 ;
		RECT 0.0481 56.8784 0.1097 57.0039 ;
		RECT 0.0481 58.0078 0.1097 58.1584 ;
		RECT 0.0481 58.1584 0.1097 58.2839 ;
		RECT 0.0481 59.2878 0.1097 59.4384 ;
		RECT 0.0481 59.4384 0.1097 59.5639 ;
		RECT 0.0481 60.5678 0.1097 60.7184 ;
		RECT 0.0481 60.7184 0.1097 60.8439 ;
		RECT 0.0481 61.8478 0.1097 61.9984 ;
		RECT 0.0481 61.9984 0.1097 62.1239 ;
		RECT 0.0481 63.1278 0.1097 63.2784 ;
		RECT 0.0481 63.2784 0.1097 63.4039 ;
		RECT 0.0481 64.4078 0.1097 64.5584 ;
		RECT 0.0481 64.5584 0.1097 64.6839 ;
		RECT 0.0481 65.6878 0.1097 65.8384 ;
		RECT 0.0481 65.8384 0.1097 65.9639 ;
		RECT 0.0481 66.9678 0.1097 67.1184 ;
		RECT 0.0481 67.1184 0.1097 67.2439 ;
		RECT 0.0481 68.2478 0.1097 68.3984 ;
		RECT 0.0481 68.3984 0.1097 68.5239 ;
		RECT 0.0481 69.5278 0.1097 69.6784 ;
		RECT 0.0481 69.6784 0.1097 69.8039 ;
		RECT 0.0481 70.8078 0.1097 70.9584 ;
		RECT 0.0481 70.9584 0.1097 71.0839 ;
		RECT 0.0481 72.0878 0.1097 72.2384 ;
		RECT 0.0481 72.2384 0.1097 72.3639 ;
		RECT 0.0481 73.3678 0.1097 73.5184 ;
		RECT 0.0481 73.5184 0.1097 73.6439 ;
		RECT 0.0481 74.6478 0.1097 74.7984 ;
		RECT 0.0481 74.7984 0.1097 74.9239 ;
		RECT 0.0481 75.9278 0.1097 76.0784 ;
		RECT 0.0481 76.0784 0.1097 76.2039 ;
		RECT 0.0481 77.2078 0.1097 77.3584 ;
		RECT 0.0481 77.3584 0.1097 77.4839 ;
		RECT 0.0481 78.4878 0.1097 78.6384 ;
		RECT 0.0481 78.6384 0.1097 78.7639 ;
		RECT 0.0481 79.7678 0.1097 79.9184 ;
		RECT 0.0481 79.9184 0.1097 80.0439 ;
		RECT 0.0481 81.0478 0.1097 81.1984 ;
		RECT 0.0481 81.1984 0.1097 81.3239 ;
		RECT 0.0481 82.3278 0.1097 82.4784 ;
		RECT 0.0481 82.4784 0.1097 82.6039 ;
		RECT 0.0481 83.6078 0.1097 83.7584 ;
		RECT 0.0481 83.7584 0.1097 83.8839 ;
		RECT 0.0481 84.8878 0.1097 85.0384 ;
		RECT 0.0481 85.0384 0.1097 85.1639 ;
		RECT 0.0481 86.1678 0.1097 86.3184 ;
		RECT 0.0481 86.3184 0.1097 86.4439 ;
		RECT 0.0481 87.4478 0.1097 87.5984 ;
		RECT 0.0481 87.5984 0.1097 87.7239 ;
		RECT 0.0481 88.7278 0.1097 88.8784 ;
		RECT 0.0481 88.8784 0.1097 89.0039 ;
		RECT 0.0481 90.0078 0.1097 90.1584 ;
		RECT 0.0481 90.1584 0.1097 90.2839 ;
		RECT 0.0481 91.2878 0.1097 91.4384 ;
		RECT 0.0481 91.4384 0.1097 91.5639 ;
		RECT 0.0831 42.4906 0.098 42.5031 ;
		RECT 0.0215 42.5533 0.0364 42.5659 ;
		RECT 0.0831 42.6412 0.098 42.6537 ;
		RECT 0.0215 42.7039 0.0364 42.7165 ;
		RECT 0.0215 42.8545 0.0364 42.8671 ;
		RECT 0.0215 43.0051 0.0364 43.0176 ;
		RECT 0.021 43.0937 0.0359 43.1063 ;
		RECT 0.0831 43.2435 0.098 43.2561 ;
		RECT 0.0215 43.3063 0.0364 43.3188 ;
		RECT 0.0831 43.3941 0.098 43.4067 ;
		RECT 0.0215 43.6075 0.0364 43.62 ;
		RECT 0.0831 43.8459 0.098 43.8584 ;
		RECT 0.0215 43.9086 0.0364 43.9212 ;
		RECT 0.0831 43.9965 0.098 44.009 ;
		RECT 0.021 44.1478 0.0359 44.1604 ;
		RECT 0.0831 44.5988 0.098 44.6114 ;
		RECT 0.0215 44.6616 0.0364 44.6741 ;
		RECT 0.0831 44.7494 0.098 44.762 ;
		RECT 0.0215 45.2639 0.0364 45.2765 ;
		RECT 0.0831 45.3839 0.098 45.3965 ;
		RECT 0.0831 45.5024 0.098 45.5149 ;
		RECT 0.0831 45.6529 0.098 45.6655 ;
		RECT 0.0831 46.4059 0.098 46.4184 ;
		RECT 0.0215 46.6192 0.0364 46.6318 ;
		RECT 0.0831 46.7392 0.098 46.7518 ;
		RECT 0.0831 46.8576 0.098 46.8702 ;
		RECT 0.0831 47.1588 0.098 47.1714 ;
		RECT 0.0831 47.3416 0.098 47.3541 ;
		RECT 0.0215 47.5227 0.0364 47.5353 ;
		RECT 0.0831 47.6427 0.098 47.6553 ;
		RECT 0.0831 47.7925 0.098 47.8051 ;
		RECT 0.0215 47.9125 0.0364 47.9251 ;
		RECT 0.0831 47.9753 0.098 47.9878 ;
		RECT 0.0831 48.3957 0.098 48.4082 ;
		RECT 0.0831 48.8153 0.098 48.8278 ;
		RECT 0.0215 48.878 0.0364 48.8906 ;
		RECT 0.021 48.9667 0.0359 48.9792 ;
		RECT 0.0215 49.1792 0.0364 49.1918 ;
		RECT 0.0215 49.3298 0.0364 49.3424 ;
		RECT 0.0831 49.4176 0.098 49.4302 ;
		RECT 0.0215 49.4804 0.0364 49.4929 ;
		RECT 0.021 49.631 0.0359 49.6435 ;
		RECT 0.0831 49.7188 0.098 49.7314 ;
		RECT 0.0215 49.7816 0.0364 49.7941 ;
		RECT 0.0831 49.8694 0.098 49.882 ;
		RECT 0.021 50.0827 0.0359 50.0953 ;
		RECT 0.0215 0.1376 0.0364 0.1502 ;
		RECT 0.0215 92.4804 0.0364 92.4929 ;
		 LAYER V2 SPACING 0 ;
		RECT 0.0481 1.0918 0.1097 1.2424 ;
		RECT 0.0481 1.2424 0.1097 1.3678 ;
		RECT 0.0481 2.3718 0.1097 2.5224 ;
		RECT 0.0481 2.5224 0.1097 2.6478 ;
		RECT 0.0481 3.6518 0.1097 3.8024 ;
		RECT 0.0481 3.8024 0.1097 3.9278 ;
		RECT 0.0481 4.9318 0.1097 5.0824 ;
		RECT 0.0481 5.0824 0.1097 5.2078 ;
		RECT 0.0481 6.2118 0.1097 6.3624 ;
		RECT 0.0481 6.3624 0.1097 6.4878 ;
		RECT 0.0481 7.4918 0.1097 7.6424 ;
		RECT 0.0481 7.6424 0.1097 7.7678 ;
		RECT 0.0481 8.7718 0.1097 8.9224 ;
		RECT 0.0481 8.9224 0.1097 9.0478 ;
		RECT 0.0481 10.0518 0.1097 10.2024 ;
		RECT 0.0481 10.2024 0.1097 10.3278 ;
		RECT 0.0481 11.3318 0.1097 11.4824 ;
		RECT 0.0481 11.4824 0.1097 11.6078 ;
		RECT 0.0481 12.6118 0.1097 12.7624 ;
		RECT 0.0481 12.7624 0.1097 12.8878 ;
		RECT 0.0481 13.8918 0.1097 14.0424 ;
		RECT 0.0481 14.0424 0.1097 14.1678 ;
		RECT 0.0481 15.1718 0.1097 15.3224 ;
		RECT 0.0481 15.3224 0.1097 15.4478 ;
		RECT 0.0481 16.4518 0.1097 16.6024 ;
		RECT 0.0481 16.6024 0.1097 16.7278 ;
		RECT 0.0481 17.7318 0.1097 17.8824 ;
		RECT 0.0481 17.8824 0.1097 18.0078 ;
		RECT 0.0481 19.0118 0.1097 19.1624 ;
		RECT 0.0481 19.1624 0.1097 19.2878 ;
		RECT 0.0481 20.2918 0.1097 20.4424 ;
		RECT 0.0481 20.4424 0.1097 20.5678 ;
		RECT 0.0481 21.5718 0.1097 21.7224 ;
		RECT 0.0481 21.7224 0.1097 21.8478 ;
		RECT 0.0481 22.8518 0.1097 23.0024 ;
		RECT 0.0481 23.0024 0.1097 23.1278 ;
		RECT 0.0481 24.1318 0.1097 24.2824 ;
		RECT 0.0481 24.2824 0.1097 24.4078 ;
		RECT 0.0481 25.4118 0.1097 25.5624 ;
		RECT 0.0481 25.5624 0.1097 25.6878 ;
		RECT 0.0481 26.6918 0.1097 26.8424 ;
		RECT 0.0481 26.8424 0.1097 26.9678 ;
		RECT 0.0481 27.9718 0.1097 28.1224 ;
		RECT 0.0481 28.1224 0.1097 28.2478 ;
		RECT 0.0481 29.2518 0.1097 29.4024 ;
		RECT 0.0481 29.4024 0.1097 29.5278 ;
		RECT 0.0481 30.5318 0.1097 30.6824 ;
		RECT 0.0481 30.6824 0.1097 30.8078 ;
		RECT 0.0481 31.8118 0.1097 31.9624 ;
		RECT 0.0481 31.9624 0.1097 32.0878 ;
		RECT 0.0481 33.0918 0.1097 33.2424 ;
		RECT 0.0481 33.2424 0.1097 33.3678 ;
		RECT 0.0481 34.3718 0.1097 34.5224 ;
		RECT 0.0481 34.5224 0.1097 34.6478 ;
		RECT 0.0481 35.6518 0.1097 35.8024 ;
		RECT 0.0481 35.8024 0.1097 35.9278 ;
		RECT 0.0481 36.9318 0.1097 37.0824 ;
		RECT 0.0481 37.0824 0.1097 37.2078 ;
		RECT 0.0481 38.2118 0.1097 38.3624 ;
		RECT 0.0481 38.3624 0.1097 38.4878 ;
		RECT 0.0481 39.4918 0.1097 39.6424 ;
		RECT 0.0481 39.6424 0.1097 39.7678 ;
		RECT 0.0481 40.7718 0.1097 40.9224 ;
		RECT 0.0481 40.9224 0.1097 41.0478 ;
		RECT 0.0481 42.0518 0.1097 42.2024 ;
		RECT 0.0481 42.2024 0.1097 42.3278 ;
		RECT 0.0481 50.3278 0.1097 50.4784 ;
		RECT 0.0481 50.4784 0.1097 50.6039 ;
		RECT 0.0481 51.6078 0.1097 51.7584 ;
		RECT 0.0481 51.7584 0.1097 51.8839 ;
		RECT 0.0481 52.8878 0.1097 53.0384 ;
		RECT 0.0481 53.0384 0.1097 53.1639 ;
		RECT 0.0481 54.1678 0.1097 54.3184 ;
		RECT 0.0481 54.3184 0.1097 54.4439 ;
		RECT 0.0481 55.4478 0.1097 55.5984 ;
		RECT 0.0481 55.5984 0.1097 55.7239 ;
		RECT 0.0481 56.7278 0.1097 56.8784 ;
		RECT 0.0481 56.8784 0.1097 57.0039 ;
		RECT 0.0481 58.0078 0.1097 58.1584 ;
		RECT 0.0481 58.1584 0.1097 58.2839 ;
		RECT 0.0481 59.2878 0.1097 59.4384 ;
		RECT 0.0481 59.4384 0.1097 59.5639 ;
		RECT 0.0481 60.5678 0.1097 60.7184 ;
		RECT 0.0481 60.7184 0.1097 60.8439 ;
		RECT 0.0481 61.8478 0.1097 61.9984 ;
		RECT 0.0481 61.9984 0.1097 62.1239 ;
		RECT 0.0481 63.1278 0.1097 63.2784 ;
		RECT 0.0481 63.2784 0.1097 63.4039 ;
		RECT 0.0481 64.4078 0.1097 64.5584 ;
		RECT 0.0481 64.5584 0.1097 64.6839 ;
		RECT 0.0481 65.6878 0.1097 65.8384 ;
		RECT 0.0481 65.8384 0.1097 65.9639 ;
		RECT 0.0481 66.9678 0.1097 67.1184 ;
		RECT 0.0481 67.1184 0.1097 67.2439 ;
		RECT 0.0481 68.2478 0.1097 68.3984 ;
		RECT 0.0481 68.3984 0.1097 68.5239 ;
		RECT 0.0481 69.5278 0.1097 69.6784 ;
		RECT 0.0481 69.6784 0.1097 69.8039 ;
		RECT 0.0481 70.8078 0.1097 70.9584 ;
		RECT 0.0481 70.9584 0.1097 71.0839 ;
		RECT 0.0481 72.0878 0.1097 72.2384 ;
		RECT 0.0481 72.2384 0.1097 72.3639 ;
		RECT 0.0481 73.3678 0.1097 73.5184 ;
		RECT 0.0481 73.5184 0.1097 73.6439 ;
		RECT 0.0481 74.6478 0.1097 74.7984 ;
		RECT 0.0481 74.7984 0.1097 74.9239 ;
		RECT 0.0481 75.9278 0.1097 76.0784 ;
		RECT 0.0481 76.0784 0.1097 76.2039 ;
		RECT 0.0481 77.2078 0.1097 77.3584 ;
		RECT 0.0481 77.3584 0.1097 77.4839 ;
		RECT 0.0481 78.4878 0.1097 78.6384 ;
		RECT 0.0481 78.6384 0.1097 78.7639 ;
		RECT 0.0481 79.7678 0.1097 79.9184 ;
		RECT 0.0481 79.9184 0.1097 80.0439 ;
		RECT 0.0481 81.0478 0.1097 81.1984 ;
		RECT 0.0481 81.1984 0.1097 81.3239 ;
		RECT 0.0481 82.3278 0.1097 82.4784 ;
		RECT 0.0481 82.4784 0.1097 82.6039 ;
		RECT 0.0481 83.6078 0.1097 83.7584 ;
		RECT 0.0481 83.7584 0.1097 83.8839 ;
		RECT 0.0481 84.8878 0.1097 85.0384 ;
		RECT 0.0481 85.0384 0.1097 85.1639 ;
		RECT 0.0481 86.1678 0.1097 86.3184 ;
		RECT 0.0481 86.3184 0.1097 86.4439 ;
		RECT 0.0481 87.4478 0.1097 87.5984 ;
		RECT 0.0481 87.5984 0.1097 87.7239 ;
		RECT 0.0481 88.7278 0.1097 88.8784 ;
		RECT 0.0481 88.8784 0.1097 89.0039 ;
		RECT 0.0481 90.0078 0.1097 90.1584 ;
		RECT 0.0481 90.1584 0.1097 90.2839 ;
		RECT 0.0481 91.2878 0.1097 91.4384 ;
		RECT 0.0481 91.4384 0.1097 91.5639 ;
		RECT 0.0831 42.4906 0.098 42.5031 ;
		RECT 0.0215 42.5533 0.0364 42.5659 ;
		RECT 0.0831 42.6412 0.098 42.6537 ;
		RECT 0.0215 42.7039 0.0364 42.7165 ;
		RECT 0.0215 42.8545 0.0364 42.8671 ;
		RECT 0.0215 43.0051 0.0364 43.0176 ;
		RECT 0.021 43.0937 0.0359 43.1063 ;
		RECT 0.0831 43.2435 0.098 43.2561 ;
		RECT 0.0215 43.3063 0.0364 43.3188 ;
		RECT 0.0831 43.3941 0.098 43.4067 ;
		RECT 0.0215 43.6075 0.0364 43.62 ;
		RECT 0.0831 43.8459 0.098 43.8584 ;
		RECT 0.0215 43.9086 0.0364 43.9212 ;
		RECT 0.0831 43.9965 0.098 44.009 ;
		RECT 0.021 44.1478 0.0359 44.1604 ;
		RECT 0.0831 44.5988 0.098 44.6114 ;
		RECT 0.0215 44.6616 0.0364 44.6741 ;
		RECT 0.0831 44.7494 0.098 44.762 ;
		RECT 0.0215 45.2639 0.0364 45.2765 ;
		RECT 0.0831 45.3839 0.098 45.3965 ;
		RECT 0.0831 45.5024 0.098 45.5149 ;
		RECT 0.0831 45.6529 0.098 45.6655 ;
		RECT 0.0831 46.4059 0.098 46.4184 ;
		RECT 0.0215 46.6192 0.0364 46.6318 ;
		RECT 0.0831 46.7392 0.098 46.7518 ;
		RECT 0.0831 46.8576 0.098 46.8702 ;
		RECT 0.0831 47.1588 0.098 47.1714 ;
		RECT 0.0831 47.3416 0.098 47.3541 ;
		RECT 0.0215 47.5227 0.0364 47.5353 ;
		RECT 0.0831 47.6427 0.098 47.6553 ;
		RECT 0.0831 47.7925 0.098 47.8051 ;
		RECT 0.0215 47.9125 0.0364 47.9251 ;
		RECT 0.0831 47.9753 0.098 47.9878 ;
		RECT 0.0831 48.3957 0.098 48.4082 ;
		RECT 0.0831 48.8153 0.098 48.8278 ;
		RECT 0.0215 48.878 0.0364 48.8906 ;
		RECT 0.021 48.9667 0.0359 48.9792 ;
		RECT 0.0215 49.1792 0.0364 49.1918 ;
		RECT 0.0215 49.3298 0.0364 49.3424 ;
		RECT 0.0831 49.4176 0.098 49.4302 ;
		RECT 0.0215 49.4804 0.0364 49.4929 ;
		RECT 0.021 49.631 0.0359 49.6435 ;
		RECT 0.0831 49.7188 0.098 49.7314 ;
		RECT 0.0215 49.7816 0.0364 49.7941 ;
		RECT 0.0831 49.8694 0.098 49.882 ;
		RECT 0.021 50.0827 0.0359 50.0953 ;
		RECT 0.0215 0.1376 0.0364 0.1502 ;
		RECT 0.0215 92.4804 0.0364 92.4929 ;
	END

END HD_1024X66M8B2

END LIBRARY

